VERSION 5.8 ;
BUSBITCHARS "[]" ;
DIVIDERCHAR "/" ;
UNITS
    DATABASE MICRONS 1000 ;
END UNITS

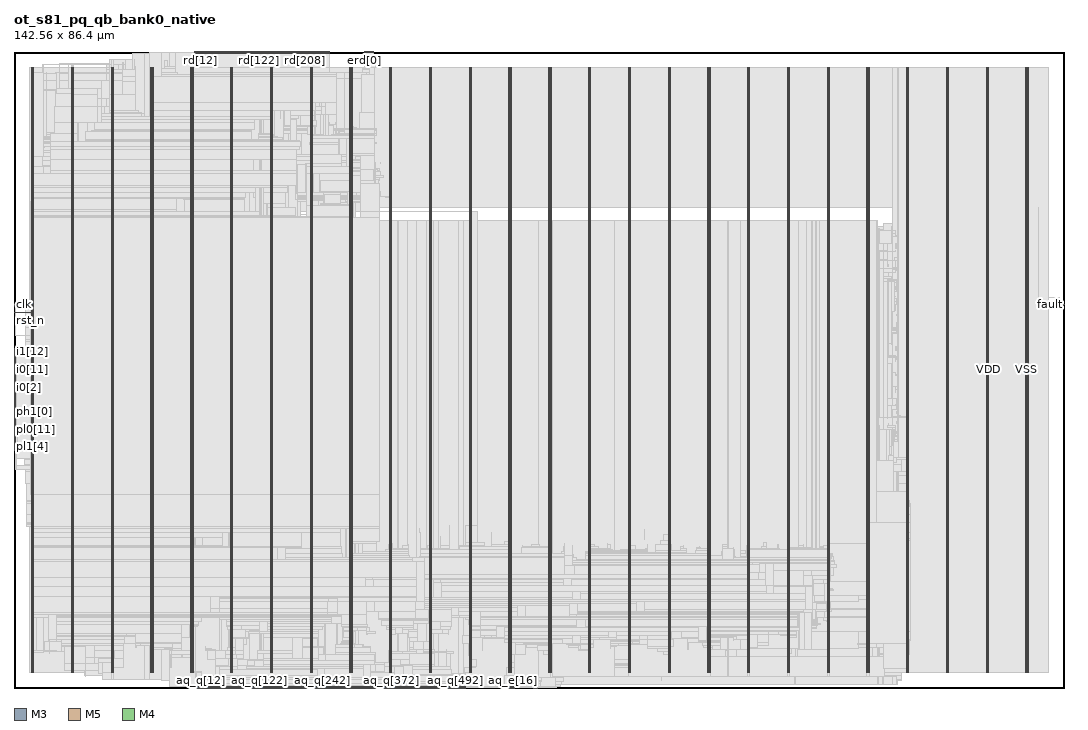
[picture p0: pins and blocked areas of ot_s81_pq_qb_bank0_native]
MACRO ot_s81_pq_qb_bank0_native
  FOREIGN ot_s81_pq_qb_bank0_native 0 0 ;
  CLASS BLOCK ;
  SIZE 142.56 BY 86.4 ;
  PIN aq_e[0]
    DIRECTION INPUT ;
    USE SIGNAL ;
    PORT
      LAYER M3 ;
        RECT  66.528 0 66.546 0.144 ;
    END
  END aq_e[0]
  PIN aq_e[10]
    DIRECTION INPUT ;
    USE SIGNAL ;
    PORT
      LAYER M3 ;
        RECT  67.248 0 67.266 0.144 ;
    END
  END aq_e[10]
  PIN aq_e[11]
    DIRECTION INPUT ;
    USE SIGNAL ;
    PORT
      LAYER M5 ;
        RECT  67.296 0 67.32 0.192 ;
    END
  END aq_e[11]
  PIN aq_e[12]
    DIRECTION INPUT ;
    USE SIGNAL ;
    PORT
      LAYER M3 ;
        RECT  67.392 0 67.41 0.144 ;
    END
  END aq_e[12]
  PIN aq_e[13]
    DIRECTION INPUT ;
    USE SIGNAL ;
    PORT
      LAYER M5 ;
        RECT  67.44 0 67.464 0.192 ;
    END
  END aq_e[13]
  PIN aq_e[14]
    DIRECTION INPUT ;
    USE SIGNAL ;
    PORT
      LAYER M3 ;
        RECT  67.536 0 67.554 0.144 ;
    END
  END aq_e[14]
  PIN aq_e[15]
    DIRECTION INPUT ;
    USE SIGNAL ;
    PORT
      LAYER M5 ;
        RECT  67.584 0 67.608 0.192 ;
    END
  END aq_e[15]
  PIN aq_e[16]
    DIRECTION INPUT ;
    USE SIGNAL ;
    PORT
      LAYER M3 ;
        RECT  67.68 0 67.698 0.144 ;
    END
  END aq_e[16]
  PIN aq_e[17]
    DIRECTION INPUT ;
    USE SIGNAL ;
    PORT
      LAYER M5 ;
        RECT  67.728 0 67.752 0.192 ;
    END
  END aq_e[17]
  PIN aq_e[18]
    DIRECTION INPUT ;
    USE SIGNAL ;
    PORT
      LAYER M3 ;
        RECT  67.824 0 67.842 0.144 ;
    END
  END aq_e[18]
  PIN aq_e[19]
    DIRECTION INPUT ;
    USE SIGNAL ;
    PORT
      LAYER M5 ;
        RECT  67.872 0 67.896 0.192 ;
    END
  END aq_e[19]
  PIN aq_e[1]
    DIRECTION INPUT ;
    USE SIGNAL ;
    PORT
      LAYER M5 ;
        RECT  66.576 0 66.6 0.192 ;
    END
  END aq_e[1]
  PIN aq_e[2]
    DIRECTION INPUT ;
    USE SIGNAL ;
    PORT
      LAYER M3 ;
        RECT  66.672 0 66.69 0.144 ;
    END
  END aq_e[2]
  PIN aq_e[3]
    DIRECTION INPUT ;
    USE SIGNAL ;
    PORT
      LAYER M5 ;
        RECT  66.72 0 66.744 0.192 ;
    END
  END aq_e[3]
  PIN aq_e[4]
    DIRECTION INPUT ;
    USE SIGNAL ;
    PORT
      LAYER M3 ;
        RECT  66.816 0 66.834 0.144 ;
    END
  END aq_e[4]
  PIN aq_e[5]
    DIRECTION INPUT ;
    USE SIGNAL ;
    PORT
      LAYER M5 ;
        RECT  66.864 0 66.888 0.192 ;
    END
  END aq_e[5]
  PIN aq_e[6]
    DIRECTION INPUT ;
    USE SIGNAL ;
    PORT
      LAYER M3 ;
        RECT  66.96 0 66.978 0.144 ;
    END
  END aq_e[6]
  PIN aq_e[7]
    DIRECTION INPUT ;
    USE SIGNAL ;
    PORT
      LAYER M5 ;
        RECT  67.008 0 67.032 0.192 ;
    END
  END aq_e[7]
  PIN aq_e[8]
    DIRECTION INPUT ;
    USE SIGNAL ;
    PORT
      LAYER M3 ;
        RECT  67.104 0 67.122 0.144 ;
    END
  END aq_e[8]
  PIN aq_e[9]
    DIRECTION INPUT ;
    USE SIGNAL ;
    PORT
      LAYER M5 ;
        RECT  67.152 0 67.176 0.192 ;
    END
  END aq_e[9]
  PIN aq_p[0]
    DIRECTION INPUT ;
    USE SIGNAL ;
    PORT
      LAYER M3 ;
        RECT  70.488 0 70.506 0.144 ;
    END
  END aq_p[0]
  PIN aq_p[1]
    DIRECTION INPUT ;
    USE SIGNAL ;
    PORT
      LAYER M5 ;
        RECT  70.512 0 70.536 0.192 ;
    END
  END aq_p[1]
  PIN aq_p[2]
    DIRECTION INPUT ;
    USE SIGNAL ;
    PORT
      LAYER M3 ;
        RECT  70.632 0 70.65 0.144 ;
    END
  END aq_p[2]
  PIN aq_p[3]
    DIRECTION INPUT ;
    USE SIGNAL ;
    PORT
      LAYER M5 ;
        RECT  70.656 0 70.68 0.192 ;
    END
  END aq_p[3]
  PIN aq_p[4]
    DIRECTION INPUT ;
    USE SIGNAL ;
    PORT
      LAYER M3 ;
        RECT  70.776 0 70.794 0.144 ;
    END
  END aq_p[4]
  PIN aq_p[5]
    DIRECTION INPUT ;
    USE SIGNAL ;
    PORT
      LAYER M5 ;
        RECT  70.8 0 70.824 0.192 ;
    END
  END aq_p[5]
  PIN aq_p[6]
    DIRECTION INPUT ;
    USE SIGNAL ;
    PORT
      LAYER M3 ;
        RECT  70.92 0 70.938 0.144 ;
    END
  END aq_p[6]
  PIN aq_p[7]
    DIRECTION INPUT ;
    USE SIGNAL ;
    PORT
      LAYER M5 ;
        RECT  70.944 0 70.968 0.192 ;
    END
  END aq_p[7]
  PIN aq_p[8]
    DIRECTION INPUT ;
    USE SIGNAL ;
    PORT
      LAYER M3 ;
        RECT  71.064 0 71.082 0.144 ;
    END
  END aq_p[8]
  PIN aq_p[9]
    DIRECTION INPUT ;
    USE SIGNAL ;
    PORT
      LAYER M5 ;
        RECT  71.088 0 71.112 0.192 ;
    END
  END aq_p[9]
  PIN aq_q[0]
    DIRECTION INPUT ;
    USE SIGNAL ;
    PORT
      LAYER M3 ;
        RECT  24.48 0 24.498 0.144 ;
    END
  END aq_q[0]
  PIN aq_q[100]
    DIRECTION INPUT ;
    USE SIGNAL ;
    PORT
      LAYER M3 ;
        RECT  31.68 0 31.698 0.144 ;
    END
  END aq_q[100]
  PIN aq_q[101]
    DIRECTION INPUT ;
    USE SIGNAL ;
    PORT
      LAYER M5 ;
        RECT  31.728 0 31.752 0.192 ;
    END
  END aq_q[101]
  PIN aq_q[102]
    DIRECTION INPUT ;
    USE SIGNAL ;
    PORT
      LAYER M3 ;
        RECT  31.824 0 31.842 0.144 ;
    END
  END aq_q[102]
  PIN aq_q[103]
    DIRECTION INPUT ;
    USE SIGNAL ;
    PORT
      LAYER M5 ;
        RECT  31.872 0 31.896 0.192 ;
    END
  END aq_q[103]
  PIN aq_q[104]
    DIRECTION INPUT ;
    USE SIGNAL ;
    PORT
      LAYER M3 ;
        RECT  31.968 0 31.986 0.144 ;
    END
  END aq_q[104]
  PIN aq_q[105]
    DIRECTION INPUT ;
    USE SIGNAL ;
    PORT
      LAYER M5 ;
        RECT  32.016 0 32.04 0.192 ;
    END
  END aq_q[105]
  PIN aq_q[106]
    DIRECTION INPUT ;
    USE SIGNAL ;
    PORT
      LAYER M3 ;
        RECT  32.112 0 32.13 0.144 ;
    END
  END aq_q[106]
  PIN aq_q[107]
    DIRECTION INPUT ;
    USE SIGNAL ;
    PORT
      LAYER M5 ;
        RECT  32.16 0 32.184 0.192 ;
    END
  END aq_q[107]
  PIN aq_q[108]
    DIRECTION INPUT ;
    USE SIGNAL ;
    PORT
      LAYER M3 ;
        RECT  32.256 0 32.274 0.144 ;
    END
  END aq_q[108]
  PIN aq_q[109]
    DIRECTION INPUT ;
    USE SIGNAL ;
    PORT
      LAYER M5 ;
        RECT  32.304 0 32.328 0.192 ;
    END
  END aq_q[109]
  PIN aq_q[10]
    DIRECTION INPUT ;
    USE SIGNAL ;
    PORT
      LAYER M3 ;
        RECT  25.2 0 25.218 0.144 ;
    END
  END aq_q[10]
  PIN aq_q[110]
    DIRECTION INPUT ;
    USE SIGNAL ;
    PORT
      LAYER M3 ;
        RECT  32.4 0 32.418 0.144 ;
    END
  END aq_q[110]
  PIN aq_q[111]
    DIRECTION INPUT ;
    USE SIGNAL ;
    PORT
      LAYER M5 ;
        RECT  32.448 0 32.472 0.192 ;
    END
  END aq_q[111]
  PIN aq_q[112]
    DIRECTION INPUT ;
    USE SIGNAL ;
    PORT
      LAYER M3 ;
        RECT  32.544 0 32.562 0.144 ;
    END
  END aq_q[112]
  PIN aq_q[113]
    DIRECTION INPUT ;
    USE SIGNAL ;
    PORT
      LAYER M5 ;
        RECT  32.592 0 32.616 0.192 ;
    END
  END aq_q[113]
  PIN aq_q[114]
    DIRECTION INPUT ;
    USE SIGNAL ;
    PORT
      LAYER M3 ;
        RECT  32.688 0 32.706 0.144 ;
    END
  END aq_q[114]
  PIN aq_q[115]
    DIRECTION INPUT ;
    USE SIGNAL ;
    PORT
      LAYER M5 ;
        RECT  32.736 0 32.76 0.192 ;
    END
  END aq_q[115]
  PIN aq_q[116]
    DIRECTION INPUT ;
    USE SIGNAL ;
    PORT
      LAYER M3 ;
        RECT  32.832 0 32.85 0.144 ;
    END
  END aq_q[116]
  PIN aq_q[117]
    DIRECTION INPUT ;
    USE SIGNAL ;
    PORT
      LAYER M5 ;
        RECT  32.88 0 32.904 0.192 ;
    END
  END aq_q[117]
  PIN aq_q[118]
    DIRECTION INPUT ;
    USE SIGNAL ;
    PORT
      LAYER M3 ;
        RECT  32.976 0 32.994 0.144 ;
    END
  END aq_q[118]
  PIN aq_q[119]
    DIRECTION INPUT ;
    USE SIGNAL ;
    PORT
      LAYER M5 ;
        RECT  33.024 0 33.048 0.192 ;
    END
  END aq_q[119]
  PIN aq_q[11]
    DIRECTION INPUT ;
    USE SIGNAL ;
    PORT
      LAYER M5 ;
        RECT  25.248 0 25.272 0.192 ;
    END
  END aq_q[11]
  PIN aq_q[120]
    DIRECTION INPUT ;
    USE SIGNAL ;
    PORT
      LAYER M3 ;
        RECT  33.12 0 33.138 0.144 ;
    END
  END aq_q[120]
  PIN aq_q[121]
    DIRECTION INPUT ;
    USE SIGNAL ;
    PORT
      LAYER M5 ;
        RECT  33.168 0 33.192 0.192 ;
    END
  END aq_q[121]
  PIN aq_q[122]
    DIRECTION INPUT ;
    USE SIGNAL ;
    PORT
      LAYER M3 ;
        RECT  33.264 0 33.282 0.144 ;
    END
  END aq_q[122]
  PIN aq_q[123]
    DIRECTION INPUT ;
    USE SIGNAL ;
    PORT
      LAYER M5 ;
        RECT  33.312 0 33.336 0.192 ;
    END
  END aq_q[123]
  PIN aq_q[124]
    DIRECTION INPUT ;
    USE SIGNAL ;
    PORT
      LAYER M3 ;
        RECT  33.408 0 33.426 0.144 ;
    END
  END aq_q[124]
  PIN aq_q[125]
    DIRECTION INPUT ;
    USE SIGNAL ;
    PORT
      LAYER M5 ;
        RECT  33.456 0 33.48 0.192 ;
    END
  END aq_q[125]
  PIN aq_q[126]
    DIRECTION INPUT ;
    USE SIGNAL ;
    PORT
      LAYER M3 ;
        RECT  33.552 0 33.57 0.144 ;
    END
  END aq_q[126]
  PIN aq_q[127]
    DIRECTION INPUT ;
    USE SIGNAL ;
    PORT
      LAYER M5 ;
        RECT  33.6 0 33.624 0.192 ;
    END
  END aq_q[127]
  PIN aq_q[128]
    DIRECTION INPUT ;
    USE SIGNAL ;
    PORT
      LAYER M3 ;
        RECT  33.696 0 33.714 0.144 ;
    END
  END aq_q[128]
  PIN aq_q[129]
    DIRECTION INPUT ;
    USE SIGNAL ;
    PORT
      LAYER M5 ;
        RECT  33.744 0 33.768 0.192 ;
    END
  END aq_q[129]
  PIN aq_q[12]
    DIRECTION INPUT ;
    USE SIGNAL ;
    PORT
      LAYER M3 ;
        RECT  25.344 0 25.362 0.144 ;
    END
  END aq_q[12]
  PIN aq_q[130]
    DIRECTION INPUT ;
    USE SIGNAL ;
    PORT
      LAYER M3 ;
        RECT  33.84 0 33.858 0.144 ;
    END
  END aq_q[130]
  PIN aq_q[131]
    DIRECTION INPUT ;
    USE SIGNAL ;
    PORT
      LAYER M5 ;
        RECT  33.888 0 33.912 0.192 ;
    END
  END aq_q[131]
  PIN aq_q[132]
    DIRECTION INPUT ;
    USE SIGNAL ;
    PORT
      LAYER M3 ;
        RECT  33.984 0 34.002 0.144 ;
    END
  END aq_q[132]
  PIN aq_q[133]
    DIRECTION INPUT ;
    USE SIGNAL ;
    PORT
      LAYER M5 ;
        RECT  34.032 0 34.056 0.192 ;
    END
  END aq_q[133]
  PIN aq_q[134]
    DIRECTION INPUT ;
    USE SIGNAL ;
    PORT
      LAYER M3 ;
        RECT  34.128 0 34.146 0.144 ;
    END
  END aq_q[134]
  PIN aq_q[135]
    DIRECTION INPUT ;
    USE SIGNAL ;
    PORT
      LAYER M5 ;
        RECT  34.176 0 34.2 0.192 ;
    END
  END aq_q[135]
  PIN aq_q[136]
    DIRECTION INPUT ;
    USE SIGNAL ;
    PORT
      LAYER M3 ;
        RECT  34.272 0 34.29 0.144 ;
    END
  END aq_q[136]
  PIN aq_q[137]
    DIRECTION INPUT ;
    USE SIGNAL ;
    PORT
      LAYER M5 ;
        RECT  34.32 0 34.344 0.192 ;
    END
  END aq_q[137]
  PIN aq_q[138]
    DIRECTION INPUT ;
    USE SIGNAL ;
    PORT
      LAYER M3 ;
        RECT  34.416 0 34.434 0.144 ;
    END
  END aq_q[138]
  PIN aq_q[139]
    DIRECTION INPUT ;
    USE SIGNAL ;
    PORT
      LAYER M5 ;
        RECT  34.464 0 34.488 0.192 ;
    END
  END aq_q[139]
  PIN aq_q[13]
    DIRECTION INPUT ;
    USE SIGNAL ;
    PORT
      LAYER M5 ;
        RECT  25.392 0 25.416 0.192 ;
    END
  END aq_q[13]
  PIN aq_q[140]
    DIRECTION INPUT ;
    USE SIGNAL ;
    PORT
      LAYER M3 ;
        RECT  34.56 0 34.578 0.144 ;
    END
  END aq_q[140]
  PIN aq_q[141]
    DIRECTION INPUT ;
    USE SIGNAL ;
    PORT
      LAYER M5 ;
        RECT  34.608 0 34.632 0.192 ;
    END
  END aq_q[141]
  PIN aq_q[142]
    DIRECTION INPUT ;
    USE SIGNAL ;
    PORT
      LAYER M3 ;
        RECT  34.704 0 34.722 0.144 ;
    END
  END aq_q[142]
  PIN aq_q[143]
    DIRECTION INPUT ;
    USE SIGNAL ;
    PORT
      LAYER M5 ;
        RECT  34.752 0 34.776 0.192 ;
    END
  END aq_q[143]
  PIN aq_q[144]
    DIRECTION INPUT ;
    USE SIGNAL ;
    PORT
      LAYER M3 ;
        RECT  34.848 0 34.866 0.144 ;
    END
  END aq_q[144]
  PIN aq_q[145]
    DIRECTION INPUT ;
    USE SIGNAL ;
    PORT
      LAYER M5 ;
        RECT  34.896 0 34.92 0.192 ;
    END
  END aq_q[145]
  PIN aq_q[146]
    DIRECTION INPUT ;
    USE SIGNAL ;
    PORT
      LAYER M3 ;
        RECT  34.992 0 35.01 0.144 ;
    END
  END aq_q[146]
  PIN aq_q[147]
    DIRECTION INPUT ;
    USE SIGNAL ;
    PORT
      LAYER M5 ;
        RECT  35.04 0 35.064 0.192 ;
    END
  END aq_q[147]
  PIN aq_q[148]
    DIRECTION INPUT ;
    USE SIGNAL ;
    PORT
      LAYER M3 ;
        RECT  35.136 0 35.154 0.144 ;
    END
  END aq_q[148]
  PIN aq_q[149]
    DIRECTION INPUT ;
    USE SIGNAL ;
    PORT
      LAYER M5 ;
        RECT  35.184 0 35.208 0.192 ;
    END
  END aq_q[149]
  PIN aq_q[14]
    DIRECTION INPUT ;
    USE SIGNAL ;
    PORT
      LAYER M3 ;
        RECT  25.488 0 25.506 0.144 ;
    END
  END aq_q[14]
  PIN aq_q[150]
    DIRECTION INPUT ;
    USE SIGNAL ;
    PORT
      LAYER M3 ;
        RECT  35.28 0 35.298 0.144 ;
    END
  END aq_q[150]
  PIN aq_q[151]
    DIRECTION INPUT ;
    USE SIGNAL ;
    PORT
      LAYER M5 ;
        RECT  35.328 0 35.352 0.192 ;
    END
  END aq_q[151]
  PIN aq_q[152]
    DIRECTION INPUT ;
    USE SIGNAL ;
    PORT
      LAYER M3 ;
        RECT  35.424 0 35.442 0.144 ;
    END
  END aq_q[152]
  PIN aq_q[153]
    DIRECTION INPUT ;
    USE SIGNAL ;
    PORT
      LAYER M5 ;
        RECT  35.472 0 35.496 0.192 ;
    END
  END aq_q[153]
  PIN aq_q[154]
    DIRECTION INPUT ;
    USE SIGNAL ;
    PORT
      LAYER M3 ;
        RECT  35.568 0 35.586 0.144 ;
    END
  END aq_q[154]
  PIN aq_q[155]
    DIRECTION INPUT ;
    USE SIGNAL ;
    PORT
      LAYER M5 ;
        RECT  35.616 0 35.64 0.192 ;
    END
  END aq_q[155]
  PIN aq_q[156]
    DIRECTION INPUT ;
    USE SIGNAL ;
    PORT
      LAYER M3 ;
        RECT  35.712 0 35.73 0.144 ;
    END
  END aq_q[156]
  PIN aq_q[157]
    DIRECTION INPUT ;
    USE SIGNAL ;
    PORT
      LAYER M5 ;
        RECT  35.76 0 35.784 0.192 ;
    END
  END aq_q[157]
  PIN aq_q[158]
    DIRECTION INPUT ;
    USE SIGNAL ;
    PORT
      LAYER M3 ;
        RECT  35.856 0 35.874 0.144 ;
    END
  END aq_q[158]
  PIN aq_q[159]
    DIRECTION INPUT ;
    USE SIGNAL ;
    PORT
      LAYER M5 ;
        RECT  35.904 0 35.928 0.192 ;
    END
  END aq_q[159]
  PIN aq_q[15]
    DIRECTION INPUT ;
    USE SIGNAL ;
    PORT
      LAYER M5 ;
        RECT  25.536 0 25.56 0.192 ;
    END
  END aq_q[15]
  PIN aq_q[160]
    DIRECTION INPUT ;
    USE SIGNAL ;
    PORT
      LAYER M3 ;
        RECT  36 0 36.018 0.144 ;
    END
  END aq_q[160]
  PIN aq_q[161]
    DIRECTION INPUT ;
    USE SIGNAL ;
    PORT
      LAYER M5 ;
        RECT  36.048 0 36.072 0.192 ;
    END
  END aq_q[161]
  PIN aq_q[162]
    DIRECTION INPUT ;
    USE SIGNAL ;
    PORT
      LAYER M3 ;
        RECT  36.144 0 36.162 0.144 ;
    END
  END aq_q[162]
  PIN aq_q[163]
    DIRECTION INPUT ;
    USE SIGNAL ;
    PORT
      LAYER M5 ;
        RECT  36.192 0 36.216 0.192 ;
    END
  END aq_q[163]
  PIN aq_q[164]
    DIRECTION INPUT ;
    USE SIGNAL ;
    PORT
      LAYER M3 ;
        RECT  36.288 0 36.306 0.144 ;
    END
  END aq_q[164]
  PIN aq_q[165]
    DIRECTION INPUT ;
    USE SIGNAL ;
    PORT
      LAYER M5 ;
        RECT  36.336 0 36.36 0.192 ;
    END
  END aq_q[165]
  PIN aq_q[166]
    DIRECTION INPUT ;
    USE SIGNAL ;
    PORT
      LAYER M3 ;
        RECT  36.432 0 36.45 0.144 ;
    END
  END aq_q[166]
  PIN aq_q[167]
    DIRECTION INPUT ;
    USE SIGNAL ;
    PORT
      LAYER M5 ;
        RECT  36.48 0 36.504 0.192 ;
    END
  END aq_q[167]
  PIN aq_q[168]
    DIRECTION INPUT ;
    USE SIGNAL ;
    PORT
      LAYER M3 ;
        RECT  36.576 0 36.594 0.144 ;
    END
  END aq_q[168]
  PIN aq_q[169]
    DIRECTION INPUT ;
    USE SIGNAL ;
    PORT
      LAYER M5 ;
        RECT  36.624 0 36.648 0.192 ;
    END
  END aq_q[169]
  PIN aq_q[16]
    DIRECTION INPUT ;
    USE SIGNAL ;
    PORT
      LAYER M3 ;
        RECT  25.632 0 25.65 0.144 ;
    END
  END aq_q[16]
  PIN aq_q[170]
    DIRECTION INPUT ;
    USE SIGNAL ;
    PORT
      LAYER M3 ;
        RECT  36.72 0 36.738 0.144 ;
    END
  END aq_q[170]
  PIN aq_q[171]
    DIRECTION INPUT ;
    USE SIGNAL ;
    PORT
      LAYER M5 ;
        RECT  36.768 0 36.792 0.192 ;
    END
  END aq_q[171]
  PIN aq_q[172]
    DIRECTION INPUT ;
    USE SIGNAL ;
    PORT
      LAYER M3 ;
        RECT  36.864 0 36.882 0.144 ;
    END
  END aq_q[172]
  PIN aq_q[173]
    DIRECTION INPUT ;
    USE SIGNAL ;
    PORT
      LAYER M5 ;
        RECT  36.912 0 36.936 0.192 ;
    END
  END aq_q[173]
  PIN aq_q[174]
    DIRECTION INPUT ;
    USE SIGNAL ;
    PORT
      LAYER M3 ;
        RECT  37.008 0 37.026 0.144 ;
    END
  END aq_q[174]
  PIN aq_q[175]
    DIRECTION INPUT ;
    USE SIGNAL ;
    PORT
      LAYER M5 ;
        RECT  37.056 0 37.08 0.192 ;
    END
  END aq_q[175]
  PIN aq_q[176]
    DIRECTION INPUT ;
    USE SIGNAL ;
    PORT
      LAYER M3 ;
        RECT  37.152 0 37.17 0.144 ;
    END
  END aq_q[176]
  PIN aq_q[177]
    DIRECTION INPUT ;
    USE SIGNAL ;
    PORT
      LAYER M5 ;
        RECT  37.2 0 37.224 0.192 ;
    END
  END aq_q[177]
  PIN aq_q[178]
    DIRECTION INPUT ;
    USE SIGNAL ;
    PORT
      LAYER M3 ;
        RECT  37.296 0 37.314 0.144 ;
    END
  END aq_q[178]
  PIN aq_q[179]
    DIRECTION INPUT ;
    USE SIGNAL ;
    PORT
      LAYER M5 ;
        RECT  37.344 0 37.368 0.192 ;
    END
  END aq_q[179]
  PIN aq_q[17]
    DIRECTION INPUT ;
    USE SIGNAL ;
    PORT
      LAYER M5 ;
        RECT  25.68 0 25.704 0.192 ;
    END
  END aq_q[17]
  PIN aq_q[180]
    DIRECTION INPUT ;
    USE SIGNAL ;
    PORT
      LAYER M3 ;
        RECT  37.44 0 37.458 0.144 ;
    END
  END aq_q[180]
  PIN aq_q[181]
    DIRECTION INPUT ;
    USE SIGNAL ;
    PORT
      LAYER M5 ;
        RECT  37.488 0 37.512 0.192 ;
    END
  END aq_q[181]
  PIN aq_q[182]
    DIRECTION INPUT ;
    USE SIGNAL ;
    PORT
      LAYER M3 ;
        RECT  37.584 0 37.602 0.144 ;
    END
  END aq_q[182]
  PIN aq_q[183]
    DIRECTION INPUT ;
    USE SIGNAL ;
    PORT
      LAYER M5 ;
        RECT  37.632 0 37.656 0.192 ;
    END
  END aq_q[183]
  PIN aq_q[184]
    DIRECTION INPUT ;
    USE SIGNAL ;
    PORT
      LAYER M3 ;
        RECT  37.728 0 37.746 0.144 ;
    END
  END aq_q[184]
  PIN aq_q[185]
    DIRECTION INPUT ;
    USE SIGNAL ;
    PORT
      LAYER M5 ;
        RECT  37.776 0 37.8 0.192 ;
    END
  END aq_q[185]
  PIN aq_q[186]
    DIRECTION INPUT ;
    USE SIGNAL ;
    PORT
      LAYER M3 ;
        RECT  37.872 0 37.89 0.144 ;
    END
  END aq_q[186]
  PIN aq_q[187]
    DIRECTION INPUT ;
    USE SIGNAL ;
    PORT
      LAYER M5 ;
        RECT  37.92 0 37.944 0.192 ;
    END
  END aq_q[187]
  PIN aq_q[188]
    DIRECTION INPUT ;
    USE SIGNAL ;
    PORT
      LAYER M3 ;
        RECT  38.016 0 38.034 0.144 ;
    END
  END aq_q[188]
  PIN aq_q[189]
    DIRECTION INPUT ;
    USE SIGNAL ;
    PORT
      LAYER M5 ;
        RECT  38.064 0 38.088 0.192 ;
    END
  END aq_q[189]
  PIN aq_q[18]
    DIRECTION INPUT ;
    USE SIGNAL ;
    PORT
      LAYER M3 ;
        RECT  25.776 0 25.794 0.144 ;
    END
  END aq_q[18]
  PIN aq_q[190]
    DIRECTION INPUT ;
    USE SIGNAL ;
    PORT
      LAYER M3 ;
        RECT  38.16 0 38.178 0.144 ;
    END
  END aq_q[190]
  PIN aq_q[191]
    DIRECTION INPUT ;
    USE SIGNAL ;
    PORT
      LAYER M5 ;
        RECT  38.208 0 38.232 0.192 ;
    END
  END aq_q[191]
  PIN aq_q[192]
    DIRECTION INPUT ;
    USE SIGNAL ;
    PORT
      LAYER M3 ;
        RECT  38.304 0 38.322 0.144 ;
    END
  END aq_q[192]
  PIN aq_q[193]
    DIRECTION INPUT ;
    USE SIGNAL ;
    PORT
      LAYER M5 ;
        RECT  38.352 0 38.376 0.192 ;
    END
  END aq_q[193]
  PIN aq_q[194]
    DIRECTION INPUT ;
    USE SIGNAL ;
    PORT
      LAYER M3 ;
        RECT  38.448 0 38.466 0.144 ;
    END
  END aq_q[194]
  PIN aq_q[195]
    DIRECTION INPUT ;
    USE SIGNAL ;
    PORT
      LAYER M5 ;
        RECT  38.496 0 38.52 0.192 ;
    END
  END aq_q[195]
  PIN aq_q[196]
    DIRECTION INPUT ;
    USE SIGNAL ;
    PORT
      LAYER M3 ;
        RECT  38.592 0 38.61 0.144 ;
    END
  END aq_q[196]
  PIN aq_q[197]
    DIRECTION INPUT ;
    USE SIGNAL ;
    PORT
      LAYER M5 ;
        RECT  38.64 0 38.664 0.192 ;
    END
  END aq_q[197]
  PIN aq_q[198]
    DIRECTION INPUT ;
    USE SIGNAL ;
    PORT
      LAYER M3 ;
        RECT  38.736 0 38.754 0.144 ;
    END
  END aq_q[198]
  PIN aq_q[199]
    DIRECTION INPUT ;
    USE SIGNAL ;
    PORT
      LAYER M5 ;
        RECT  38.784 0 38.808 0.192 ;
    END
  END aq_q[199]
  PIN aq_q[19]
    DIRECTION INPUT ;
    USE SIGNAL ;
    PORT
      LAYER M5 ;
        RECT  25.824 0 25.848 0.192 ;
    END
  END aq_q[19]
  PIN aq_q[1]
    DIRECTION INPUT ;
    USE SIGNAL ;
    PORT
      LAYER M5 ;
        RECT  24.528 0 24.552 0.192 ;
    END
  END aq_q[1]
  PIN aq_q[200]
    DIRECTION INPUT ;
    USE SIGNAL ;
    PORT
      LAYER M3 ;
        RECT  38.88 0 38.898 0.144 ;
    END
  END aq_q[200]
  PIN aq_q[201]
    DIRECTION INPUT ;
    USE SIGNAL ;
    PORT
      LAYER M5 ;
        RECT  38.928 0 38.952 0.192 ;
    END
  END aq_q[201]
  PIN aq_q[202]
    DIRECTION INPUT ;
    USE SIGNAL ;
    PORT
      LAYER M3 ;
        RECT  39.024 0 39.042 0.144 ;
    END
  END aq_q[202]
  PIN aq_q[203]
    DIRECTION INPUT ;
    USE SIGNAL ;
    PORT
      LAYER M5 ;
        RECT  39.072 0 39.096 0.192 ;
    END
  END aq_q[203]
  PIN aq_q[204]
    DIRECTION INPUT ;
    USE SIGNAL ;
    PORT
      LAYER M3 ;
        RECT  39.168 0 39.186 0.144 ;
    END
  END aq_q[204]
  PIN aq_q[205]
    DIRECTION INPUT ;
    USE SIGNAL ;
    PORT
      LAYER M5 ;
        RECT  39.216 0 39.24 0.192 ;
    END
  END aq_q[205]
  PIN aq_q[206]
    DIRECTION INPUT ;
    USE SIGNAL ;
    PORT
      LAYER M3 ;
        RECT  39.312 0 39.33 0.144 ;
    END
  END aq_q[206]
  PIN aq_q[207]
    DIRECTION INPUT ;
    USE SIGNAL ;
    PORT
      LAYER M5 ;
        RECT  39.36 0 39.384 0.192 ;
    END
  END aq_q[207]
  PIN aq_q[208]
    DIRECTION INPUT ;
    USE SIGNAL ;
    PORT
      LAYER M3 ;
        RECT  39.456 0 39.474 0.144 ;
    END
  END aq_q[208]
  PIN aq_q[209]
    DIRECTION INPUT ;
    USE SIGNAL ;
    PORT
      LAYER M5 ;
        RECT  39.504 0 39.528 0.192 ;
    END
  END aq_q[209]
  PIN aq_q[20]
    DIRECTION INPUT ;
    USE SIGNAL ;
    PORT
      LAYER M3 ;
        RECT  25.92 0 25.938 0.144 ;
    END
  END aq_q[20]
  PIN aq_q[210]
    DIRECTION INPUT ;
    USE SIGNAL ;
    PORT
      LAYER M3 ;
        RECT  39.6 0 39.618 0.144 ;
    END
  END aq_q[210]
  PIN aq_q[211]
    DIRECTION INPUT ;
    USE SIGNAL ;
    PORT
      LAYER M5 ;
        RECT  39.648 0 39.672 0.192 ;
    END
  END aq_q[211]
  PIN aq_q[212]
    DIRECTION INPUT ;
    USE SIGNAL ;
    PORT
      LAYER M3 ;
        RECT  39.744 0 39.762 0.144 ;
    END
  END aq_q[212]
  PIN aq_q[213]
    DIRECTION INPUT ;
    USE SIGNAL ;
    PORT
      LAYER M5 ;
        RECT  39.792 0 39.816 0.192 ;
    END
  END aq_q[213]
  PIN aq_q[214]
    DIRECTION INPUT ;
    USE SIGNAL ;
    PORT
      LAYER M3 ;
        RECT  39.888 0 39.906 0.144 ;
    END
  END aq_q[214]
  PIN aq_q[215]
    DIRECTION INPUT ;
    USE SIGNAL ;
    PORT
      LAYER M5 ;
        RECT  39.936 0 39.96 0.192 ;
    END
  END aq_q[215]
  PIN aq_q[216]
    DIRECTION INPUT ;
    USE SIGNAL ;
    PORT
      LAYER M3 ;
        RECT  40.032 0 40.05 0.144 ;
    END
  END aq_q[216]
  PIN aq_q[217]
    DIRECTION INPUT ;
    USE SIGNAL ;
    PORT
      LAYER M5 ;
        RECT  40.08 0 40.104 0.192 ;
    END
  END aq_q[217]
  PIN aq_q[218]
    DIRECTION INPUT ;
    USE SIGNAL ;
    PORT
      LAYER M3 ;
        RECT  40.176 0 40.194 0.144 ;
    END
  END aq_q[218]
  PIN aq_q[219]
    DIRECTION INPUT ;
    USE SIGNAL ;
    PORT
      LAYER M5 ;
        RECT  40.224 0 40.248 0.192 ;
    END
  END aq_q[219]
  PIN aq_q[21]
    DIRECTION INPUT ;
    USE SIGNAL ;
    PORT
      LAYER M5 ;
        RECT  25.968 0 25.992 0.192 ;
    END
  END aq_q[21]
  PIN aq_q[220]
    DIRECTION INPUT ;
    USE SIGNAL ;
    PORT
      LAYER M3 ;
        RECT  40.32 0 40.338 0.144 ;
    END
  END aq_q[220]
  PIN aq_q[221]
    DIRECTION INPUT ;
    USE SIGNAL ;
    PORT
      LAYER M5 ;
        RECT  40.368 0 40.392 0.192 ;
    END
  END aq_q[221]
  PIN aq_q[222]
    DIRECTION INPUT ;
    USE SIGNAL ;
    PORT
      LAYER M3 ;
        RECT  40.464 0 40.482 0.144 ;
    END
  END aq_q[222]
  PIN aq_q[223]
    DIRECTION INPUT ;
    USE SIGNAL ;
    PORT
      LAYER M5 ;
        RECT  40.512 0 40.536 0.192 ;
    END
  END aq_q[223]
  PIN aq_q[224]
    DIRECTION INPUT ;
    USE SIGNAL ;
    PORT
      LAYER M3 ;
        RECT  40.608 0 40.626 0.144 ;
    END
  END aq_q[224]
  PIN aq_q[225]
    DIRECTION INPUT ;
    USE SIGNAL ;
    PORT
      LAYER M5 ;
        RECT  40.656 0 40.68 0.192 ;
    END
  END aq_q[225]
  PIN aq_q[226]
    DIRECTION INPUT ;
    USE SIGNAL ;
    PORT
      LAYER M3 ;
        RECT  40.752 0 40.77 0.144 ;
    END
  END aq_q[226]
  PIN aq_q[227]
    DIRECTION INPUT ;
    USE SIGNAL ;
    PORT
      LAYER M5 ;
        RECT  40.8 0 40.824 0.192 ;
    END
  END aq_q[227]
  PIN aq_q[228]
    DIRECTION INPUT ;
    USE SIGNAL ;
    PORT
      LAYER M3 ;
        RECT  40.896 0 40.914 0.144 ;
    END
  END aq_q[228]
  PIN aq_q[229]
    DIRECTION INPUT ;
    USE SIGNAL ;
    PORT
      LAYER M5 ;
        RECT  40.944 0 40.968 0.192 ;
    END
  END aq_q[229]
  PIN aq_q[22]
    DIRECTION INPUT ;
    USE SIGNAL ;
    PORT
      LAYER M3 ;
        RECT  26.064 0 26.082 0.144 ;
    END
  END aq_q[22]
  PIN aq_q[230]
    DIRECTION INPUT ;
    USE SIGNAL ;
    PORT
      LAYER M3 ;
        RECT  41.04 0 41.058 0.144 ;
    END
  END aq_q[230]
  PIN aq_q[231]
    DIRECTION INPUT ;
    USE SIGNAL ;
    PORT
      LAYER M5 ;
        RECT  41.088 0 41.112 0.192 ;
    END
  END aq_q[231]
  PIN aq_q[232]
    DIRECTION INPUT ;
    USE SIGNAL ;
    PORT
      LAYER M3 ;
        RECT  41.184 0 41.202 0.144 ;
    END
  END aq_q[232]
  PIN aq_q[233]
    DIRECTION INPUT ;
    USE SIGNAL ;
    PORT
      LAYER M5 ;
        RECT  41.232 0 41.256 0.192 ;
    END
  END aq_q[233]
  PIN aq_q[234]
    DIRECTION INPUT ;
    USE SIGNAL ;
    PORT
      LAYER M3 ;
        RECT  41.328 0 41.346 0.144 ;
    END
  END aq_q[234]
  PIN aq_q[235]
    DIRECTION INPUT ;
    USE SIGNAL ;
    PORT
      LAYER M5 ;
        RECT  41.376 0 41.4 0.192 ;
    END
  END aq_q[235]
  PIN aq_q[236]
    DIRECTION INPUT ;
    USE SIGNAL ;
    PORT
      LAYER M3 ;
        RECT  41.472 0 41.49 0.144 ;
    END
  END aq_q[236]
  PIN aq_q[237]
    DIRECTION INPUT ;
    USE SIGNAL ;
    PORT
      LAYER M5 ;
        RECT  41.52 0 41.544 0.192 ;
    END
  END aq_q[237]
  PIN aq_q[238]
    DIRECTION INPUT ;
    USE SIGNAL ;
    PORT
      LAYER M3 ;
        RECT  41.616 0 41.634 0.144 ;
    END
  END aq_q[238]
  PIN aq_q[239]
    DIRECTION INPUT ;
    USE SIGNAL ;
    PORT
      LAYER M5 ;
        RECT  41.664 0 41.688 0.192 ;
    END
  END aq_q[239]
  PIN aq_q[23]
    DIRECTION INPUT ;
    USE SIGNAL ;
    PORT
      LAYER M5 ;
        RECT  26.112 0 26.136 0.192 ;
    END
  END aq_q[23]
  PIN aq_q[240]
    DIRECTION INPUT ;
    USE SIGNAL ;
    PORT
      LAYER M3 ;
        RECT  41.76 0 41.778 0.144 ;
    END
  END aq_q[240]
  PIN aq_q[241]
    DIRECTION INPUT ;
    USE SIGNAL ;
    PORT
      LAYER M5 ;
        RECT  41.808 0 41.832 0.192 ;
    END
  END aq_q[241]
  PIN aq_q[242]
    DIRECTION INPUT ;
    USE SIGNAL ;
    PORT
      LAYER M3 ;
        RECT  41.904 0 41.922 0.144 ;
    END
  END aq_q[242]
  PIN aq_q[243]
    DIRECTION INPUT ;
    USE SIGNAL ;
    PORT
      LAYER M5 ;
        RECT  41.952 0 41.976 0.192 ;
    END
  END aq_q[243]
  PIN aq_q[244]
    DIRECTION INPUT ;
    USE SIGNAL ;
    PORT
      LAYER M3 ;
        RECT  42.048 0 42.066 0.144 ;
    END
  END aq_q[244]
  PIN aq_q[245]
    DIRECTION INPUT ;
    USE SIGNAL ;
    PORT
      LAYER M5 ;
        RECT  42.096 0 42.12 0.192 ;
    END
  END aq_q[245]
  PIN aq_q[246]
    DIRECTION INPUT ;
    USE SIGNAL ;
    PORT
      LAYER M3 ;
        RECT  42.192 0 42.21 0.144 ;
    END
  END aq_q[246]
  PIN aq_q[247]
    DIRECTION INPUT ;
    USE SIGNAL ;
    PORT
      LAYER M5 ;
        RECT  42.24 0 42.264 0.192 ;
    END
  END aq_q[247]
  PIN aq_q[248]
    DIRECTION INPUT ;
    USE SIGNAL ;
    PORT
      LAYER M3 ;
        RECT  42.336 0 42.354 0.144 ;
    END
  END aq_q[248]
  PIN aq_q[249]
    DIRECTION INPUT ;
    USE SIGNAL ;
    PORT
      LAYER M5 ;
        RECT  42.384 0 42.408 0.192 ;
    END
  END aq_q[249]
  PIN aq_q[24]
    DIRECTION INPUT ;
    USE SIGNAL ;
    PORT
      LAYER M3 ;
        RECT  26.208 0 26.226 0.144 ;
    END
  END aq_q[24]
  PIN aq_q[250]
    DIRECTION INPUT ;
    USE SIGNAL ;
    PORT
      LAYER M3 ;
        RECT  42.48 0 42.498 0.144 ;
    END
  END aq_q[250]
  PIN aq_q[251]
    DIRECTION INPUT ;
    USE SIGNAL ;
    PORT
      LAYER M5 ;
        RECT  42.528 0 42.552 0.192 ;
    END
  END aq_q[251]
  PIN aq_q[252]
    DIRECTION INPUT ;
    USE SIGNAL ;
    PORT
      LAYER M3 ;
        RECT  42.624 0 42.642 0.144 ;
    END
  END aq_q[252]
  PIN aq_q[253]
    DIRECTION INPUT ;
    USE SIGNAL ;
    PORT
      LAYER M5 ;
        RECT  42.672 0 42.696 0.192 ;
    END
  END aq_q[253]
  PIN aq_q[254]
    DIRECTION INPUT ;
    USE SIGNAL ;
    PORT
      LAYER M3 ;
        RECT  42.768 0 42.786 0.144 ;
    END
  END aq_q[254]
  PIN aq_q[255]
    DIRECTION INPUT ;
    USE SIGNAL ;
    PORT
      LAYER M5 ;
        RECT  42.816 0 42.84 0.192 ;
    END
  END aq_q[255]
  PIN aq_q[256]
    DIRECTION INPUT ;
    USE SIGNAL ;
    PORT
      LAYER M3 ;
        RECT  42.912 0 42.93 0.144 ;
    END
  END aq_q[256]
  PIN aq_q[257]
    DIRECTION INPUT ;
    USE SIGNAL ;
    PORT
      LAYER M5 ;
        RECT  42.96 0 42.984 0.192 ;
    END
  END aq_q[257]
  PIN aq_q[258]
    DIRECTION INPUT ;
    USE SIGNAL ;
    PORT
      LAYER M3 ;
        RECT  43.056 0 43.074 0.144 ;
    END
  END aq_q[258]
  PIN aq_q[259]
    DIRECTION INPUT ;
    USE SIGNAL ;
    PORT
      LAYER M5 ;
        RECT  43.104 0 43.128 0.192 ;
    END
  END aq_q[259]
  PIN aq_q[25]
    DIRECTION INPUT ;
    USE SIGNAL ;
    PORT
      LAYER M5 ;
        RECT  26.256 0 26.28 0.192 ;
    END
  END aq_q[25]
  PIN aq_q[260]
    DIRECTION INPUT ;
    USE SIGNAL ;
    PORT
      LAYER M3 ;
        RECT  43.2 0 43.218 0.144 ;
    END
  END aq_q[260]
  PIN aq_q[261]
    DIRECTION INPUT ;
    USE SIGNAL ;
    PORT
      LAYER M5 ;
        RECT  43.248 0 43.272 0.192 ;
    END
  END aq_q[261]
  PIN aq_q[262]
    DIRECTION INPUT ;
    USE SIGNAL ;
    PORT
      LAYER M3 ;
        RECT  43.344 0 43.362 0.144 ;
    END
  END aq_q[262]
  PIN aq_q[263]
    DIRECTION INPUT ;
    USE SIGNAL ;
    PORT
      LAYER M5 ;
        RECT  43.392 0 43.416 0.192 ;
    END
  END aq_q[263]
  PIN aq_q[264]
    DIRECTION INPUT ;
    USE SIGNAL ;
    PORT
      LAYER M3 ;
        RECT  43.488 0 43.506 0.144 ;
    END
  END aq_q[264]
  PIN aq_q[265]
    DIRECTION INPUT ;
    USE SIGNAL ;
    PORT
      LAYER M5 ;
        RECT  43.536 0 43.56 0.192 ;
    END
  END aq_q[265]
  PIN aq_q[266]
    DIRECTION INPUT ;
    USE SIGNAL ;
    PORT
      LAYER M3 ;
        RECT  43.632 0 43.65 0.144 ;
    END
  END aq_q[266]
  PIN aq_q[267]
    DIRECTION INPUT ;
    USE SIGNAL ;
    PORT
      LAYER M5 ;
        RECT  43.68 0 43.704 0.192 ;
    END
  END aq_q[267]
  PIN aq_q[268]
    DIRECTION INPUT ;
    USE SIGNAL ;
    PORT
      LAYER M3 ;
        RECT  43.776 0 43.794 0.144 ;
    END
  END aq_q[268]
  PIN aq_q[269]
    DIRECTION INPUT ;
    USE SIGNAL ;
    PORT
      LAYER M5 ;
        RECT  43.824 0 43.848 0.192 ;
    END
  END aq_q[269]
  PIN aq_q[26]
    DIRECTION INPUT ;
    USE SIGNAL ;
    PORT
      LAYER M3 ;
        RECT  26.352 0 26.37 0.144 ;
    END
  END aq_q[26]
  PIN aq_q[270]
    DIRECTION INPUT ;
    USE SIGNAL ;
    PORT
      LAYER M3 ;
        RECT  43.92 0 43.938 0.144 ;
    END
  END aq_q[270]
  PIN aq_q[271]
    DIRECTION INPUT ;
    USE SIGNAL ;
    PORT
      LAYER M5 ;
        RECT  43.968 0 43.992 0.192 ;
    END
  END aq_q[271]
  PIN aq_q[272]
    DIRECTION INPUT ;
    USE SIGNAL ;
    PORT
      LAYER M3 ;
        RECT  44.064 0 44.082 0.144 ;
    END
  END aq_q[272]
  PIN aq_q[273]
    DIRECTION INPUT ;
    USE SIGNAL ;
    PORT
      LAYER M5 ;
        RECT  44.112 0 44.136 0.192 ;
    END
  END aq_q[273]
  PIN aq_q[274]
    DIRECTION INPUT ;
    USE SIGNAL ;
    PORT
      LAYER M3 ;
        RECT  44.208 0 44.226 0.144 ;
    END
  END aq_q[274]
  PIN aq_q[275]
    DIRECTION INPUT ;
    USE SIGNAL ;
    PORT
      LAYER M5 ;
        RECT  44.256 0 44.28 0.192 ;
    END
  END aq_q[275]
  PIN aq_q[276]
    DIRECTION INPUT ;
    USE SIGNAL ;
    PORT
      LAYER M3 ;
        RECT  44.352 0 44.37 0.144 ;
    END
  END aq_q[276]
  PIN aq_q[277]
    DIRECTION INPUT ;
    USE SIGNAL ;
    PORT
      LAYER M5 ;
        RECT  44.4 0 44.424 0.192 ;
    END
  END aq_q[277]
  PIN aq_q[278]
    DIRECTION INPUT ;
    USE SIGNAL ;
    PORT
      LAYER M3 ;
        RECT  44.496 0 44.514 0.144 ;
    END
  END aq_q[278]
  PIN aq_q[279]
    DIRECTION INPUT ;
    USE SIGNAL ;
    PORT
      LAYER M5 ;
        RECT  44.544 0 44.568 0.192 ;
    END
  END aq_q[279]
  PIN aq_q[27]
    DIRECTION INPUT ;
    USE SIGNAL ;
    PORT
      LAYER M5 ;
        RECT  26.4 0 26.424 0.192 ;
    END
  END aq_q[27]
  PIN aq_q[280]
    DIRECTION INPUT ;
    USE SIGNAL ;
    PORT
      LAYER M3 ;
        RECT  44.64 0 44.658 0.144 ;
    END
  END aq_q[280]
  PIN aq_q[281]
    DIRECTION INPUT ;
    USE SIGNAL ;
    PORT
      LAYER M5 ;
        RECT  44.688 0 44.712 0.192 ;
    END
  END aq_q[281]
  PIN aq_q[282]
    DIRECTION INPUT ;
    USE SIGNAL ;
    PORT
      LAYER M3 ;
        RECT  44.784 0 44.802 0.144 ;
    END
  END aq_q[282]
  PIN aq_q[283]
    DIRECTION INPUT ;
    USE SIGNAL ;
    PORT
      LAYER M5 ;
        RECT  44.832 0 44.856 0.192 ;
    END
  END aq_q[283]
  PIN aq_q[284]
    DIRECTION INPUT ;
    USE SIGNAL ;
    PORT
      LAYER M3 ;
        RECT  44.928 0 44.946 0.144 ;
    END
  END aq_q[284]
  PIN aq_q[285]
    DIRECTION INPUT ;
    USE SIGNAL ;
    PORT
      LAYER M5 ;
        RECT  44.976 0 45 0.192 ;
    END
  END aq_q[285]
  PIN aq_q[286]
    DIRECTION INPUT ;
    USE SIGNAL ;
    PORT
      LAYER M3 ;
        RECT  45.072 0 45.09 0.144 ;
    END
  END aq_q[286]
  PIN aq_q[287]
    DIRECTION INPUT ;
    USE SIGNAL ;
    PORT
      LAYER M5 ;
        RECT  45.12 0 45.144 0.192 ;
    END
  END aq_q[287]
  PIN aq_q[288]
    DIRECTION INPUT ;
    USE SIGNAL ;
    PORT
      LAYER M3 ;
        RECT  45.216 0 45.234 0.144 ;
    END
  END aq_q[288]
  PIN aq_q[289]
    DIRECTION INPUT ;
    USE SIGNAL ;
    PORT
      LAYER M5 ;
        RECT  45.264 0 45.288 0.192 ;
    END
  END aq_q[289]
  PIN aq_q[28]
    DIRECTION INPUT ;
    USE SIGNAL ;
    PORT
      LAYER M3 ;
        RECT  26.496 0 26.514 0.144 ;
    END
  END aq_q[28]
  PIN aq_q[290]
    DIRECTION INPUT ;
    USE SIGNAL ;
    PORT
      LAYER M3 ;
        RECT  45.36 0 45.378 0.144 ;
    END
  END aq_q[290]
  PIN aq_q[291]
    DIRECTION INPUT ;
    USE SIGNAL ;
    PORT
      LAYER M5 ;
        RECT  45.408 0 45.432 0.192 ;
    END
  END aq_q[291]
  PIN aq_q[292]
    DIRECTION INPUT ;
    USE SIGNAL ;
    PORT
      LAYER M3 ;
        RECT  45.504 0 45.522 0.144 ;
    END
  END aq_q[292]
  PIN aq_q[293]
    DIRECTION INPUT ;
    USE SIGNAL ;
    PORT
      LAYER M5 ;
        RECT  45.552 0 45.576 0.192 ;
    END
  END aq_q[293]
  PIN aq_q[294]
    DIRECTION INPUT ;
    USE SIGNAL ;
    PORT
      LAYER M3 ;
        RECT  45.648 0 45.666 0.144 ;
    END
  END aq_q[294]
  PIN aq_q[295]
    DIRECTION INPUT ;
    USE SIGNAL ;
    PORT
      LAYER M5 ;
        RECT  45.696 0 45.72 0.192 ;
    END
  END aq_q[295]
  PIN aq_q[296]
    DIRECTION INPUT ;
    USE SIGNAL ;
    PORT
      LAYER M3 ;
        RECT  45.792 0 45.81 0.144 ;
    END
  END aq_q[296]
  PIN aq_q[297]
    DIRECTION INPUT ;
    USE SIGNAL ;
    PORT
      LAYER M5 ;
        RECT  45.84 0 45.864 0.192 ;
    END
  END aq_q[297]
  PIN aq_q[298]
    DIRECTION INPUT ;
    USE SIGNAL ;
    PORT
      LAYER M3 ;
        RECT  45.936 0 45.954 0.144 ;
    END
  END aq_q[298]
  PIN aq_q[299]
    DIRECTION INPUT ;
    USE SIGNAL ;
    PORT
      LAYER M5 ;
        RECT  45.984 0 46.008 0.192 ;
    END
  END aq_q[299]
  PIN aq_q[29]
    DIRECTION INPUT ;
    USE SIGNAL ;
    PORT
      LAYER M5 ;
        RECT  26.544 0 26.568 0.192 ;
    END
  END aq_q[29]
  PIN aq_q[2]
    DIRECTION INPUT ;
    USE SIGNAL ;
    PORT
      LAYER M3 ;
        RECT  24.624 0 24.642 0.144 ;
    END
  END aq_q[2]
  PIN aq_q[300]
    DIRECTION INPUT ;
    USE SIGNAL ;
    PORT
      LAYER M3 ;
        RECT  46.08 0 46.098 0.144 ;
    END
  END aq_q[300]
  PIN aq_q[301]
    DIRECTION INPUT ;
    USE SIGNAL ;
    PORT
      LAYER M5 ;
        RECT  46.128 0 46.152 0.192 ;
    END
  END aq_q[301]
  PIN aq_q[302]
    DIRECTION INPUT ;
    USE SIGNAL ;
    PORT
      LAYER M3 ;
        RECT  46.224 0 46.242 0.144 ;
    END
  END aq_q[302]
  PIN aq_q[303]
    DIRECTION INPUT ;
    USE SIGNAL ;
    PORT
      LAYER M5 ;
        RECT  46.272 0 46.296 0.192 ;
    END
  END aq_q[303]
  PIN aq_q[304]
    DIRECTION INPUT ;
    USE SIGNAL ;
    PORT
      LAYER M3 ;
        RECT  46.368 0 46.386 0.144 ;
    END
  END aq_q[304]
  PIN aq_q[305]
    DIRECTION INPUT ;
    USE SIGNAL ;
    PORT
      LAYER M5 ;
        RECT  46.416 0 46.44 0.192 ;
    END
  END aq_q[305]
  PIN aq_q[306]
    DIRECTION INPUT ;
    USE SIGNAL ;
    PORT
      LAYER M3 ;
        RECT  46.512 0 46.53 0.144 ;
    END
  END aq_q[306]
  PIN aq_q[307]
    DIRECTION INPUT ;
    USE SIGNAL ;
    PORT
      LAYER M5 ;
        RECT  46.56 0 46.584 0.192 ;
    END
  END aq_q[307]
  PIN aq_q[308]
    DIRECTION INPUT ;
    USE SIGNAL ;
    PORT
      LAYER M3 ;
        RECT  46.656 0 46.674 0.144 ;
    END
  END aq_q[308]
  PIN aq_q[309]
    DIRECTION INPUT ;
    USE SIGNAL ;
    PORT
      LAYER M5 ;
        RECT  46.704 0 46.728 0.192 ;
    END
  END aq_q[309]
  PIN aq_q[30]
    DIRECTION INPUT ;
    USE SIGNAL ;
    PORT
      LAYER M3 ;
        RECT  26.64 0 26.658 0.144 ;
    END
  END aq_q[30]
  PIN aq_q[310]
    DIRECTION INPUT ;
    USE SIGNAL ;
    PORT
      LAYER M3 ;
        RECT  46.8 0 46.818 0.144 ;
    END
  END aq_q[310]
  PIN aq_q[311]
    DIRECTION INPUT ;
    USE SIGNAL ;
    PORT
      LAYER M5 ;
        RECT  46.848 0 46.872 0.192 ;
    END
  END aq_q[311]
  PIN aq_q[312]
    DIRECTION INPUT ;
    USE SIGNAL ;
    PORT
      LAYER M3 ;
        RECT  46.944 0 46.962 0.144 ;
    END
  END aq_q[312]
  PIN aq_q[313]
    DIRECTION INPUT ;
    USE SIGNAL ;
    PORT
      LAYER M5 ;
        RECT  46.992 0 47.016 0.192 ;
    END
  END aq_q[313]
  PIN aq_q[314]
    DIRECTION INPUT ;
    USE SIGNAL ;
    PORT
      LAYER M3 ;
        RECT  47.088 0 47.106 0.144 ;
    END
  END aq_q[314]
  PIN aq_q[315]
    DIRECTION INPUT ;
    USE SIGNAL ;
    PORT
      LAYER M5 ;
        RECT  47.136 0 47.16 0.192 ;
    END
  END aq_q[315]
  PIN aq_q[316]
    DIRECTION INPUT ;
    USE SIGNAL ;
    PORT
      LAYER M3 ;
        RECT  47.232 0 47.25 0.144 ;
    END
  END aq_q[316]
  PIN aq_q[317]
    DIRECTION INPUT ;
    USE SIGNAL ;
    PORT
      LAYER M5 ;
        RECT  47.28 0 47.304 0.192 ;
    END
  END aq_q[317]
  PIN aq_q[318]
    DIRECTION INPUT ;
    USE SIGNAL ;
    PORT
      LAYER M3 ;
        RECT  47.376 0 47.394 0.144 ;
    END
  END aq_q[318]
  PIN aq_q[319]
    DIRECTION INPUT ;
    USE SIGNAL ;
    PORT
      LAYER M5 ;
        RECT  47.424 0 47.448 0.192 ;
    END
  END aq_q[319]
  PIN aq_q[31]
    DIRECTION INPUT ;
    USE SIGNAL ;
    PORT
      LAYER M5 ;
        RECT  26.688 0 26.712 0.192 ;
    END
  END aq_q[31]
  PIN aq_q[320]
    DIRECTION INPUT ;
    USE SIGNAL ;
    PORT
      LAYER M3 ;
        RECT  47.52 0 47.538 0.144 ;
    END
  END aq_q[320]
  PIN aq_q[321]
    DIRECTION INPUT ;
    USE SIGNAL ;
    PORT
      LAYER M5 ;
        RECT  47.568 0 47.592 0.192 ;
    END
  END aq_q[321]
  PIN aq_q[322]
    DIRECTION INPUT ;
    USE SIGNAL ;
    PORT
      LAYER M3 ;
        RECT  47.664 0 47.682 0.144 ;
    END
  END aq_q[322]
  PIN aq_q[323]
    DIRECTION INPUT ;
    USE SIGNAL ;
    PORT
      LAYER M5 ;
        RECT  47.712 0 47.736 0.192 ;
    END
  END aq_q[323]
  PIN aq_q[324]
    DIRECTION INPUT ;
    USE SIGNAL ;
    PORT
      LAYER M3 ;
        RECT  47.808 0 47.826 0.144 ;
    END
  END aq_q[324]
  PIN aq_q[325]
    DIRECTION INPUT ;
    USE SIGNAL ;
    PORT
      LAYER M5 ;
        RECT  47.856 0 47.88 0.192 ;
    END
  END aq_q[325]
  PIN aq_q[326]
    DIRECTION INPUT ;
    USE SIGNAL ;
    PORT
      LAYER M3 ;
        RECT  47.952 0 47.97 0.144 ;
    END
  END aq_q[326]
  PIN aq_q[327]
    DIRECTION INPUT ;
    USE SIGNAL ;
    PORT
      LAYER M5 ;
        RECT  48 0 48.024 0.192 ;
    END
  END aq_q[327]
  PIN aq_q[328]
    DIRECTION INPUT ;
    USE SIGNAL ;
    PORT
      LAYER M3 ;
        RECT  48.096 0 48.114 0.144 ;
    END
  END aq_q[328]
  PIN aq_q[329]
    DIRECTION INPUT ;
    USE SIGNAL ;
    PORT
      LAYER M5 ;
        RECT  48.144 0 48.168 0.192 ;
    END
  END aq_q[329]
  PIN aq_q[32]
    DIRECTION INPUT ;
    USE SIGNAL ;
    PORT
      LAYER M3 ;
        RECT  26.784 0 26.802 0.144 ;
    END
  END aq_q[32]
  PIN aq_q[330]
    DIRECTION INPUT ;
    USE SIGNAL ;
    PORT
      LAYER M3 ;
        RECT  48.24 0 48.258 0.144 ;
    END
  END aq_q[330]
  PIN aq_q[331]
    DIRECTION INPUT ;
    USE SIGNAL ;
    PORT
      LAYER M5 ;
        RECT  48.288 0 48.312 0.192 ;
    END
  END aq_q[331]
  PIN aq_q[332]
    DIRECTION INPUT ;
    USE SIGNAL ;
    PORT
      LAYER M3 ;
        RECT  48.384 0 48.402 0.144 ;
    END
  END aq_q[332]
  PIN aq_q[333]
    DIRECTION INPUT ;
    USE SIGNAL ;
    PORT
      LAYER M5 ;
        RECT  48.432 0 48.456 0.192 ;
    END
  END aq_q[333]
  PIN aq_q[334]
    DIRECTION INPUT ;
    USE SIGNAL ;
    PORT
      LAYER M3 ;
        RECT  48.528 0 48.546 0.144 ;
    END
  END aq_q[334]
  PIN aq_q[335]
    DIRECTION INPUT ;
    USE SIGNAL ;
    PORT
      LAYER M5 ;
        RECT  48.576 0 48.6 0.192 ;
    END
  END aq_q[335]
  PIN aq_q[336]
    DIRECTION INPUT ;
    USE SIGNAL ;
    PORT
      LAYER M3 ;
        RECT  48.672 0 48.69 0.144 ;
    END
  END aq_q[336]
  PIN aq_q[337]
    DIRECTION INPUT ;
    USE SIGNAL ;
    PORT
      LAYER M5 ;
        RECT  48.72 0 48.744 0.192 ;
    END
  END aq_q[337]
  PIN aq_q[338]
    DIRECTION INPUT ;
    USE SIGNAL ;
    PORT
      LAYER M3 ;
        RECT  48.816 0 48.834 0.144 ;
    END
  END aq_q[338]
  PIN aq_q[339]
    DIRECTION INPUT ;
    USE SIGNAL ;
    PORT
      LAYER M5 ;
        RECT  48.864 0 48.888 0.192 ;
    END
  END aq_q[339]
  PIN aq_q[33]
    DIRECTION INPUT ;
    USE SIGNAL ;
    PORT
      LAYER M5 ;
        RECT  26.832 0 26.856 0.192 ;
    END
  END aq_q[33]
  PIN aq_q[340]
    DIRECTION INPUT ;
    USE SIGNAL ;
    PORT
      LAYER M3 ;
        RECT  48.96 0 48.978 0.144 ;
    END
  END aq_q[340]
  PIN aq_q[341]
    DIRECTION INPUT ;
    USE SIGNAL ;
    PORT
      LAYER M5 ;
        RECT  49.008 0 49.032 0.192 ;
    END
  END aq_q[341]
  PIN aq_q[342]
    DIRECTION INPUT ;
    USE SIGNAL ;
    PORT
      LAYER M3 ;
        RECT  49.104 0 49.122 0.144 ;
    END
  END aq_q[342]
  PIN aq_q[343]
    DIRECTION INPUT ;
    USE SIGNAL ;
    PORT
      LAYER M5 ;
        RECT  49.152 0 49.176 0.192 ;
    END
  END aq_q[343]
  PIN aq_q[344]
    DIRECTION INPUT ;
    USE SIGNAL ;
    PORT
      LAYER M3 ;
        RECT  49.248 0 49.266 0.144 ;
    END
  END aq_q[344]
  PIN aq_q[345]
    DIRECTION INPUT ;
    USE SIGNAL ;
    PORT
      LAYER M5 ;
        RECT  49.296 0 49.32 0.192 ;
    END
  END aq_q[345]
  PIN aq_q[346]
    DIRECTION INPUT ;
    USE SIGNAL ;
    PORT
      LAYER M3 ;
        RECT  49.392 0 49.41 0.144 ;
    END
  END aq_q[346]
  PIN aq_q[347]
    DIRECTION INPUT ;
    USE SIGNAL ;
    PORT
      LAYER M5 ;
        RECT  49.44 0 49.464 0.192 ;
    END
  END aq_q[347]
  PIN aq_q[348]
    DIRECTION INPUT ;
    USE SIGNAL ;
    PORT
      LAYER M3 ;
        RECT  49.536 0 49.554 0.144 ;
    END
  END aq_q[348]
  PIN aq_q[349]
    DIRECTION INPUT ;
    USE SIGNAL ;
    PORT
      LAYER M5 ;
        RECT  49.584 0 49.608 0.192 ;
    END
  END aq_q[349]
  PIN aq_q[34]
    DIRECTION INPUT ;
    USE SIGNAL ;
    PORT
      LAYER M3 ;
        RECT  26.928 0 26.946 0.144 ;
    END
  END aq_q[34]
  PIN aq_q[350]
    DIRECTION INPUT ;
    USE SIGNAL ;
    PORT
      LAYER M3 ;
        RECT  49.68 0 49.698 0.144 ;
    END
  END aq_q[350]
  PIN aq_q[351]
    DIRECTION INPUT ;
    USE SIGNAL ;
    PORT
      LAYER M5 ;
        RECT  49.728 0 49.752 0.192 ;
    END
  END aq_q[351]
  PIN aq_q[352]
    DIRECTION INPUT ;
    USE SIGNAL ;
    PORT
      LAYER M3 ;
        RECT  49.824 0 49.842 0.144 ;
    END
  END aq_q[352]
  PIN aq_q[353]
    DIRECTION INPUT ;
    USE SIGNAL ;
    PORT
      LAYER M5 ;
        RECT  49.872 0 49.896 0.192 ;
    END
  END aq_q[353]
  PIN aq_q[354]
    DIRECTION INPUT ;
    USE SIGNAL ;
    PORT
      LAYER M3 ;
        RECT  49.968 0 49.986 0.144 ;
    END
  END aq_q[354]
  PIN aq_q[355]
    DIRECTION INPUT ;
    USE SIGNAL ;
    PORT
      LAYER M5 ;
        RECT  50.016 0 50.04 0.192 ;
    END
  END aq_q[355]
  PIN aq_q[356]
    DIRECTION INPUT ;
    USE SIGNAL ;
    PORT
      LAYER M3 ;
        RECT  50.112 0 50.13 0.144 ;
    END
  END aq_q[356]
  PIN aq_q[357]
    DIRECTION INPUT ;
    USE SIGNAL ;
    PORT
      LAYER M5 ;
        RECT  50.16 0 50.184 0.192 ;
    END
  END aq_q[357]
  PIN aq_q[358]
    DIRECTION INPUT ;
    USE SIGNAL ;
    PORT
      LAYER M3 ;
        RECT  50.256 0 50.274 0.144 ;
    END
  END aq_q[358]
  PIN aq_q[359]
    DIRECTION INPUT ;
    USE SIGNAL ;
    PORT
      LAYER M5 ;
        RECT  50.304 0 50.328 0.192 ;
    END
  END aq_q[359]
  PIN aq_q[35]
    DIRECTION INPUT ;
    USE SIGNAL ;
    PORT
      LAYER M5 ;
        RECT  26.976 0 27 0.192 ;
    END
  END aq_q[35]
  PIN aq_q[360]
    DIRECTION INPUT ;
    USE SIGNAL ;
    PORT
      LAYER M3 ;
        RECT  50.4 0 50.418 0.144 ;
    END
  END aq_q[360]
  PIN aq_q[361]
    DIRECTION INPUT ;
    USE SIGNAL ;
    PORT
      LAYER M5 ;
        RECT  50.448 0 50.472 0.192 ;
    END
  END aq_q[361]
  PIN aq_q[362]
    DIRECTION INPUT ;
    USE SIGNAL ;
    PORT
      LAYER M3 ;
        RECT  50.544 0 50.562 0.144 ;
    END
  END aq_q[362]
  PIN aq_q[363]
    DIRECTION INPUT ;
    USE SIGNAL ;
    PORT
      LAYER M5 ;
        RECT  50.592 0 50.616 0.192 ;
    END
  END aq_q[363]
  PIN aq_q[364]
    DIRECTION INPUT ;
    USE SIGNAL ;
    PORT
      LAYER M3 ;
        RECT  50.688 0 50.706 0.144 ;
    END
  END aq_q[364]
  PIN aq_q[365]
    DIRECTION INPUT ;
    USE SIGNAL ;
    PORT
      LAYER M5 ;
        RECT  50.736 0 50.76 0.192 ;
    END
  END aq_q[365]
  PIN aq_q[366]
    DIRECTION INPUT ;
    USE SIGNAL ;
    PORT
      LAYER M3 ;
        RECT  50.832 0 50.85 0.144 ;
    END
  END aq_q[366]
  PIN aq_q[367]
    DIRECTION INPUT ;
    USE SIGNAL ;
    PORT
      LAYER M5 ;
        RECT  50.88 0 50.904 0.192 ;
    END
  END aq_q[367]
  PIN aq_q[368]
    DIRECTION INPUT ;
    USE SIGNAL ;
    PORT
      LAYER M3 ;
        RECT  50.976 0 50.994 0.144 ;
    END
  END aq_q[368]
  PIN aq_q[369]
    DIRECTION INPUT ;
    USE SIGNAL ;
    PORT
      LAYER M5 ;
        RECT  51.024 0 51.048 0.192 ;
    END
  END aq_q[369]
  PIN aq_q[36]
    DIRECTION INPUT ;
    USE SIGNAL ;
    PORT
      LAYER M3 ;
        RECT  27.072 0 27.09 0.144 ;
    END
  END aq_q[36]
  PIN aq_q[370]
    DIRECTION INPUT ;
    USE SIGNAL ;
    PORT
      LAYER M3 ;
        RECT  51.12 0 51.138 0.144 ;
    END
  END aq_q[370]
  PIN aq_q[371]
    DIRECTION INPUT ;
    USE SIGNAL ;
    PORT
      LAYER M5 ;
        RECT  51.168 0 51.192 0.192 ;
    END
  END aq_q[371]
  PIN aq_q[372]
    DIRECTION INPUT ;
    USE SIGNAL ;
    PORT
      LAYER M3 ;
        RECT  51.264 0 51.282 0.144 ;
    END
  END aq_q[372]
  PIN aq_q[373]
    DIRECTION INPUT ;
    USE SIGNAL ;
    PORT
      LAYER M5 ;
        RECT  51.312 0 51.336 0.192 ;
    END
  END aq_q[373]
  PIN aq_q[374]
    DIRECTION INPUT ;
    USE SIGNAL ;
    PORT
      LAYER M3 ;
        RECT  51.408 0 51.426 0.144 ;
    END
  END aq_q[374]
  PIN aq_q[375]
    DIRECTION INPUT ;
    USE SIGNAL ;
    PORT
      LAYER M5 ;
        RECT  51.456 0 51.48 0.192 ;
    END
  END aq_q[375]
  PIN aq_q[376]
    DIRECTION INPUT ;
    USE SIGNAL ;
    PORT
      LAYER M3 ;
        RECT  51.552 0 51.57 0.144 ;
    END
  END aq_q[376]
  PIN aq_q[377]
    DIRECTION INPUT ;
    USE SIGNAL ;
    PORT
      LAYER M5 ;
        RECT  51.6 0 51.624 0.192 ;
    END
  END aq_q[377]
  PIN aq_q[378]
    DIRECTION INPUT ;
    USE SIGNAL ;
    PORT
      LAYER M3 ;
        RECT  51.696 0 51.714 0.144 ;
    END
  END aq_q[378]
  PIN aq_q[379]
    DIRECTION INPUT ;
    USE SIGNAL ;
    PORT
      LAYER M5 ;
        RECT  51.744 0 51.768 0.192 ;
    END
  END aq_q[379]
  PIN aq_q[37]
    DIRECTION INPUT ;
    USE SIGNAL ;
    PORT
      LAYER M5 ;
        RECT  27.12 0 27.144 0.192 ;
    END
  END aq_q[37]
  PIN aq_q[380]
    DIRECTION INPUT ;
    USE SIGNAL ;
    PORT
      LAYER M3 ;
        RECT  51.84 0 51.858 0.144 ;
    END
  END aq_q[380]
  PIN aq_q[381]
    DIRECTION INPUT ;
    USE SIGNAL ;
    PORT
      LAYER M5 ;
        RECT  51.888 0 51.912 0.192 ;
    END
  END aq_q[381]
  PIN aq_q[382]
    DIRECTION INPUT ;
    USE SIGNAL ;
    PORT
      LAYER M3 ;
        RECT  51.984 0 52.002 0.144 ;
    END
  END aq_q[382]
  PIN aq_q[383]
    DIRECTION INPUT ;
    USE SIGNAL ;
    PORT
      LAYER M5 ;
        RECT  52.032 0 52.056 0.192 ;
    END
  END aq_q[383]
  PIN aq_q[384]
    DIRECTION INPUT ;
    USE SIGNAL ;
    PORT
      LAYER M3 ;
        RECT  52.128 0 52.146 0.144 ;
    END
  END aq_q[384]
  PIN aq_q[385]
    DIRECTION INPUT ;
    USE SIGNAL ;
    PORT
      LAYER M5 ;
        RECT  52.176 0 52.2 0.192 ;
    END
  END aq_q[385]
  PIN aq_q[386]
    DIRECTION INPUT ;
    USE SIGNAL ;
    PORT
      LAYER M3 ;
        RECT  52.272 0 52.29 0.144 ;
    END
  END aq_q[386]
  PIN aq_q[387]
    DIRECTION INPUT ;
    USE SIGNAL ;
    PORT
      LAYER M5 ;
        RECT  52.32 0 52.344 0.192 ;
    END
  END aq_q[387]
  PIN aq_q[388]
    DIRECTION INPUT ;
    USE SIGNAL ;
    PORT
      LAYER M3 ;
        RECT  52.416 0 52.434 0.144 ;
    END
  END aq_q[388]
  PIN aq_q[389]
    DIRECTION INPUT ;
    USE SIGNAL ;
    PORT
      LAYER M5 ;
        RECT  52.464 0 52.488 0.192 ;
    END
  END aq_q[389]
  PIN aq_q[38]
    DIRECTION INPUT ;
    USE SIGNAL ;
    PORT
      LAYER M3 ;
        RECT  27.216 0 27.234 0.144 ;
    END
  END aq_q[38]
  PIN aq_q[390]
    DIRECTION INPUT ;
    USE SIGNAL ;
    PORT
      LAYER M3 ;
        RECT  52.56 0 52.578 0.144 ;
    END
  END aq_q[390]
  PIN aq_q[391]
    DIRECTION INPUT ;
    USE SIGNAL ;
    PORT
      LAYER M5 ;
        RECT  52.608 0 52.632 0.192 ;
    END
  END aq_q[391]
  PIN aq_q[392]
    DIRECTION INPUT ;
    USE SIGNAL ;
    PORT
      LAYER M3 ;
        RECT  52.704 0 52.722 0.144 ;
    END
  END aq_q[392]
  PIN aq_q[393]
    DIRECTION INPUT ;
    USE SIGNAL ;
    PORT
      LAYER M5 ;
        RECT  52.752 0 52.776 0.192 ;
    END
  END aq_q[393]
  PIN aq_q[394]
    DIRECTION INPUT ;
    USE SIGNAL ;
    PORT
      LAYER M3 ;
        RECT  52.848 0 52.866 0.144 ;
    END
  END aq_q[394]
  PIN aq_q[395]
    DIRECTION INPUT ;
    USE SIGNAL ;
    PORT
      LAYER M5 ;
        RECT  52.896 0 52.92 0.192 ;
    END
  END aq_q[395]
  PIN aq_q[396]
    DIRECTION INPUT ;
    USE SIGNAL ;
    PORT
      LAYER M3 ;
        RECT  52.992 0 53.01 0.144 ;
    END
  END aq_q[396]
  PIN aq_q[397]
    DIRECTION INPUT ;
    USE SIGNAL ;
    PORT
      LAYER M5 ;
        RECT  53.04 0 53.064 0.192 ;
    END
  END aq_q[397]
  PIN aq_q[398]
    DIRECTION INPUT ;
    USE SIGNAL ;
    PORT
      LAYER M3 ;
        RECT  53.136 0 53.154 0.144 ;
    END
  END aq_q[398]
  PIN aq_q[399]
    DIRECTION INPUT ;
    USE SIGNAL ;
    PORT
      LAYER M5 ;
        RECT  53.184 0 53.208 0.192 ;
    END
  END aq_q[399]
  PIN aq_q[39]
    DIRECTION INPUT ;
    USE SIGNAL ;
    PORT
      LAYER M5 ;
        RECT  27.264 0 27.288 0.192 ;
    END
  END aq_q[39]
  PIN aq_q[3]
    DIRECTION INPUT ;
    USE SIGNAL ;
    PORT
      LAYER M5 ;
        RECT  24.672 0 24.696 0.192 ;
    END
  END aq_q[3]
  PIN aq_q[400]
    DIRECTION INPUT ;
    USE SIGNAL ;
    PORT
      LAYER M3 ;
        RECT  53.28 0 53.298 0.144 ;
    END
  END aq_q[400]
  PIN aq_q[401]
    DIRECTION INPUT ;
    USE SIGNAL ;
    PORT
      LAYER M5 ;
        RECT  53.328 0 53.352 0.192 ;
    END
  END aq_q[401]
  PIN aq_q[402]
    DIRECTION INPUT ;
    USE SIGNAL ;
    PORT
      LAYER M3 ;
        RECT  53.424 0 53.442 0.144 ;
    END
  END aq_q[402]
  PIN aq_q[403]
    DIRECTION INPUT ;
    USE SIGNAL ;
    PORT
      LAYER M5 ;
        RECT  53.472 0 53.496 0.192 ;
    END
  END aq_q[403]
  PIN aq_q[404]
    DIRECTION INPUT ;
    USE SIGNAL ;
    PORT
      LAYER M3 ;
        RECT  53.568 0 53.586 0.144 ;
    END
  END aq_q[404]
  PIN aq_q[405]
    DIRECTION INPUT ;
    USE SIGNAL ;
    PORT
      LAYER M5 ;
        RECT  53.616 0 53.64 0.192 ;
    END
  END aq_q[405]
  PIN aq_q[406]
    DIRECTION INPUT ;
    USE SIGNAL ;
    PORT
      LAYER M3 ;
        RECT  53.712 0 53.73 0.144 ;
    END
  END aq_q[406]
  PIN aq_q[407]
    DIRECTION INPUT ;
    USE SIGNAL ;
    PORT
      LAYER M5 ;
        RECT  53.76 0 53.784 0.192 ;
    END
  END aq_q[407]
  PIN aq_q[408]
    DIRECTION INPUT ;
    USE SIGNAL ;
    PORT
      LAYER M3 ;
        RECT  53.856 0 53.874 0.144 ;
    END
  END aq_q[408]
  PIN aq_q[409]
    DIRECTION INPUT ;
    USE SIGNAL ;
    PORT
      LAYER M5 ;
        RECT  53.904 0 53.928 0.192 ;
    END
  END aq_q[409]
  PIN aq_q[40]
    DIRECTION INPUT ;
    USE SIGNAL ;
    PORT
      LAYER M3 ;
        RECT  27.36 0 27.378 0.144 ;
    END
  END aq_q[40]
  PIN aq_q[410]
    DIRECTION INPUT ;
    USE SIGNAL ;
    PORT
      LAYER M3 ;
        RECT  54 0 54.018 0.144 ;
    END
  END aq_q[410]
  PIN aq_q[411]
    DIRECTION INPUT ;
    USE SIGNAL ;
    PORT
      LAYER M5 ;
        RECT  54.048 0 54.072 0.192 ;
    END
  END aq_q[411]
  PIN aq_q[412]
    DIRECTION INPUT ;
    USE SIGNAL ;
    PORT
      LAYER M3 ;
        RECT  54.144 0 54.162 0.144 ;
    END
  END aq_q[412]
  PIN aq_q[413]
    DIRECTION INPUT ;
    USE SIGNAL ;
    PORT
      LAYER M5 ;
        RECT  54.192 0 54.216 0.192 ;
    END
  END aq_q[413]
  PIN aq_q[414]
    DIRECTION INPUT ;
    USE SIGNAL ;
    PORT
      LAYER M3 ;
        RECT  54.288 0 54.306 0.144 ;
    END
  END aq_q[414]
  PIN aq_q[415]
    DIRECTION INPUT ;
    USE SIGNAL ;
    PORT
      LAYER M5 ;
        RECT  54.336 0 54.36 0.192 ;
    END
  END aq_q[415]
  PIN aq_q[416]
    DIRECTION INPUT ;
    USE SIGNAL ;
    PORT
      LAYER M3 ;
        RECT  54.432 0 54.45 0.144 ;
    END
  END aq_q[416]
  PIN aq_q[417]
    DIRECTION INPUT ;
    USE SIGNAL ;
    PORT
      LAYER M5 ;
        RECT  54.48 0 54.504 0.192 ;
    END
  END aq_q[417]
  PIN aq_q[418]
    DIRECTION INPUT ;
    USE SIGNAL ;
    PORT
      LAYER M3 ;
        RECT  54.576 0 54.594 0.144 ;
    END
  END aq_q[418]
  PIN aq_q[419]
    DIRECTION INPUT ;
    USE SIGNAL ;
    PORT
      LAYER M5 ;
        RECT  54.624 0 54.648 0.192 ;
    END
  END aq_q[419]
  PIN aq_q[41]
    DIRECTION INPUT ;
    USE SIGNAL ;
    PORT
      LAYER M5 ;
        RECT  27.408 0 27.432 0.192 ;
    END
  END aq_q[41]
  PIN aq_q[420]
    DIRECTION INPUT ;
    USE SIGNAL ;
    PORT
      LAYER M3 ;
        RECT  54.72 0 54.738 0.144 ;
    END
  END aq_q[420]
  PIN aq_q[421]
    DIRECTION INPUT ;
    USE SIGNAL ;
    PORT
      LAYER M5 ;
        RECT  54.768 0 54.792 0.192 ;
    END
  END aq_q[421]
  PIN aq_q[422]
    DIRECTION INPUT ;
    USE SIGNAL ;
    PORT
      LAYER M3 ;
        RECT  54.864 0 54.882 0.144 ;
    END
  END aq_q[422]
  PIN aq_q[423]
    DIRECTION INPUT ;
    USE SIGNAL ;
    PORT
      LAYER M5 ;
        RECT  54.912 0 54.936 0.192 ;
    END
  END aq_q[423]
  PIN aq_q[424]
    DIRECTION INPUT ;
    USE SIGNAL ;
    PORT
      LAYER M3 ;
        RECT  55.008 0 55.026 0.144 ;
    END
  END aq_q[424]
  PIN aq_q[425]
    DIRECTION INPUT ;
    USE SIGNAL ;
    PORT
      LAYER M5 ;
        RECT  55.056 0 55.08 0.192 ;
    END
  END aq_q[425]
  PIN aq_q[426]
    DIRECTION INPUT ;
    USE SIGNAL ;
    PORT
      LAYER M3 ;
        RECT  55.152 0 55.17 0.144 ;
    END
  END aq_q[426]
  PIN aq_q[427]
    DIRECTION INPUT ;
    USE SIGNAL ;
    PORT
      LAYER M5 ;
        RECT  55.2 0 55.224 0.192 ;
    END
  END aq_q[427]
  PIN aq_q[428]
    DIRECTION INPUT ;
    USE SIGNAL ;
    PORT
      LAYER M3 ;
        RECT  55.296 0 55.314 0.144 ;
    END
  END aq_q[428]
  PIN aq_q[429]
    DIRECTION INPUT ;
    USE SIGNAL ;
    PORT
      LAYER M5 ;
        RECT  55.344 0 55.368 0.192 ;
    END
  END aq_q[429]
  PIN aq_q[42]
    DIRECTION INPUT ;
    USE SIGNAL ;
    PORT
      LAYER M3 ;
        RECT  27.504 0 27.522 0.144 ;
    END
  END aq_q[42]
  PIN aq_q[430]
    DIRECTION INPUT ;
    USE SIGNAL ;
    PORT
      LAYER M3 ;
        RECT  55.44 0 55.458 0.144 ;
    END
  END aq_q[430]
  PIN aq_q[431]
    DIRECTION INPUT ;
    USE SIGNAL ;
    PORT
      LAYER M5 ;
        RECT  55.488 0 55.512 0.192 ;
    END
  END aq_q[431]
  PIN aq_q[432]
    DIRECTION INPUT ;
    USE SIGNAL ;
    PORT
      LAYER M3 ;
        RECT  55.584 0 55.602 0.144 ;
    END
  END aq_q[432]
  PIN aq_q[433]
    DIRECTION INPUT ;
    USE SIGNAL ;
    PORT
      LAYER M5 ;
        RECT  55.632 0 55.656 0.192 ;
    END
  END aq_q[433]
  PIN aq_q[434]
    DIRECTION INPUT ;
    USE SIGNAL ;
    PORT
      LAYER M3 ;
        RECT  55.728 0 55.746 0.144 ;
    END
  END aq_q[434]
  PIN aq_q[435]
    DIRECTION INPUT ;
    USE SIGNAL ;
    PORT
      LAYER M5 ;
        RECT  55.776 0 55.8 0.192 ;
    END
  END aq_q[435]
  PIN aq_q[436]
    DIRECTION INPUT ;
    USE SIGNAL ;
    PORT
      LAYER M3 ;
        RECT  55.872 0 55.89 0.144 ;
    END
  END aq_q[436]
  PIN aq_q[437]
    DIRECTION INPUT ;
    USE SIGNAL ;
    PORT
      LAYER M5 ;
        RECT  55.92 0 55.944 0.192 ;
    END
  END aq_q[437]
  PIN aq_q[438]
    DIRECTION INPUT ;
    USE SIGNAL ;
    PORT
      LAYER M3 ;
        RECT  56.016 0 56.034 0.144 ;
    END
  END aq_q[438]
  PIN aq_q[439]
    DIRECTION INPUT ;
    USE SIGNAL ;
    PORT
      LAYER M5 ;
        RECT  56.064 0 56.088 0.192 ;
    END
  END aq_q[439]
  PIN aq_q[43]
    DIRECTION INPUT ;
    USE SIGNAL ;
    PORT
      LAYER M5 ;
        RECT  27.552 0 27.576 0.192 ;
    END
  END aq_q[43]
  PIN aq_q[440]
    DIRECTION INPUT ;
    USE SIGNAL ;
    PORT
      LAYER M3 ;
        RECT  56.16 0 56.178 0.144 ;
    END
  END aq_q[440]
  PIN aq_q[441]
    DIRECTION INPUT ;
    USE SIGNAL ;
    PORT
      LAYER M5 ;
        RECT  56.208 0 56.232 0.192 ;
    END
  END aq_q[441]
  PIN aq_q[442]
    DIRECTION INPUT ;
    USE SIGNAL ;
    PORT
      LAYER M3 ;
        RECT  56.304 0 56.322 0.144 ;
    END
  END aq_q[442]
  PIN aq_q[443]
    DIRECTION INPUT ;
    USE SIGNAL ;
    PORT
      LAYER M5 ;
        RECT  56.352 0 56.376 0.192 ;
    END
  END aq_q[443]
  PIN aq_q[444]
    DIRECTION INPUT ;
    USE SIGNAL ;
    PORT
      LAYER M3 ;
        RECT  56.448 0 56.466 0.144 ;
    END
  END aq_q[444]
  PIN aq_q[445]
    DIRECTION INPUT ;
    USE SIGNAL ;
    PORT
      LAYER M5 ;
        RECT  56.496 0 56.52 0.192 ;
    END
  END aq_q[445]
  PIN aq_q[446]
    DIRECTION INPUT ;
    USE SIGNAL ;
    PORT
      LAYER M3 ;
        RECT  56.592 0 56.61 0.144 ;
    END
  END aq_q[446]
  PIN aq_q[447]
    DIRECTION INPUT ;
    USE SIGNAL ;
    PORT
      LAYER M5 ;
        RECT  56.64 0 56.664 0.192 ;
    END
  END aq_q[447]
  PIN aq_q[448]
    DIRECTION INPUT ;
    USE SIGNAL ;
    PORT
      LAYER M3 ;
        RECT  56.736 0 56.754 0.144 ;
    END
  END aq_q[448]
  PIN aq_q[449]
    DIRECTION INPUT ;
    USE SIGNAL ;
    PORT
      LAYER M5 ;
        RECT  56.784 0 56.808 0.192 ;
    END
  END aq_q[449]
  PIN aq_q[44]
    DIRECTION INPUT ;
    USE SIGNAL ;
    PORT
      LAYER M3 ;
        RECT  27.648 0 27.666 0.144 ;
    END
  END aq_q[44]
  PIN aq_q[450]
    DIRECTION INPUT ;
    USE SIGNAL ;
    PORT
      LAYER M3 ;
        RECT  56.88 0 56.898 0.144 ;
    END
  END aq_q[450]
  PIN aq_q[451]
    DIRECTION INPUT ;
    USE SIGNAL ;
    PORT
      LAYER M5 ;
        RECT  56.928 0 56.952 0.192 ;
    END
  END aq_q[451]
  PIN aq_q[452]
    DIRECTION INPUT ;
    USE SIGNAL ;
    PORT
      LAYER M3 ;
        RECT  57.024 0 57.042 0.144 ;
    END
  END aq_q[452]
  PIN aq_q[453]
    DIRECTION INPUT ;
    USE SIGNAL ;
    PORT
      LAYER M5 ;
        RECT  57.072 0 57.096 0.192 ;
    END
  END aq_q[453]
  PIN aq_q[454]
    DIRECTION INPUT ;
    USE SIGNAL ;
    PORT
      LAYER M3 ;
        RECT  57.168 0 57.186 0.144 ;
    END
  END aq_q[454]
  PIN aq_q[455]
    DIRECTION INPUT ;
    USE SIGNAL ;
    PORT
      LAYER M5 ;
        RECT  57.216 0 57.24 0.192 ;
    END
  END aq_q[455]
  PIN aq_q[456]
    DIRECTION INPUT ;
    USE SIGNAL ;
    PORT
      LAYER M3 ;
        RECT  57.312 0 57.33 0.144 ;
    END
  END aq_q[456]
  PIN aq_q[457]
    DIRECTION INPUT ;
    USE SIGNAL ;
    PORT
      LAYER M5 ;
        RECT  57.36 0 57.384 0.192 ;
    END
  END aq_q[457]
  PIN aq_q[458]
    DIRECTION INPUT ;
    USE SIGNAL ;
    PORT
      LAYER M3 ;
        RECT  57.456 0 57.474 0.144 ;
    END
  END aq_q[458]
  PIN aq_q[459]
    DIRECTION INPUT ;
    USE SIGNAL ;
    PORT
      LAYER M5 ;
        RECT  57.504 0 57.528 0.192 ;
    END
  END aq_q[459]
  PIN aq_q[45]
    DIRECTION INPUT ;
    USE SIGNAL ;
    PORT
      LAYER M5 ;
        RECT  27.696 0 27.72 0.192 ;
    END
  END aq_q[45]
  PIN aq_q[460]
    DIRECTION INPUT ;
    USE SIGNAL ;
    PORT
      LAYER M3 ;
        RECT  57.6 0 57.618 0.144 ;
    END
  END aq_q[460]
  PIN aq_q[461]
    DIRECTION INPUT ;
    USE SIGNAL ;
    PORT
      LAYER M5 ;
        RECT  57.648 0 57.672 0.192 ;
    END
  END aq_q[461]
  PIN aq_q[462]
    DIRECTION INPUT ;
    USE SIGNAL ;
    PORT
      LAYER M3 ;
        RECT  57.744 0 57.762 0.144 ;
    END
  END aq_q[462]
  PIN aq_q[463]
    DIRECTION INPUT ;
    USE SIGNAL ;
    PORT
      LAYER M5 ;
        RECT  57.792 0 57.816 0.192 ;
    END
  END aq_q[463]
  PIN aq_q[464]
    DIRECTION INPUT ;
    USE SIGNAL ;
    PORT
      LAYER M3 ;
        RECT  57.888 0 57.906 0.144 ;
    END
  END aq_q[464]
  PIN aq_q[465]
    DIRECTION INPUT ;
    USE SIGNAL ;
    PORT
      LAYER M5 ;
        RECT  57.936 0 57.96 0.192 ;
    END
  END aq_q[465]
  PIN aq_q[466]
    DIRECTION INPUT ;
    USE SIGNAL ;
    PORT
      LAYER M3 ;
        RECT  58.032 0 58.05 0.144 ;
    END
  END aq_q[466]
  PIN aq_q[467]
    DIRECTION INPUT ;
    USE SIGNAL ;
    PORT
      LAYER M5 ;
        RECT  58.08 0 58.104 0.192 ;
    END
  END aq_q[467]
  PIN aq_q[468]
    DIRECTION INPUT ;
    USE SIGNAL ;
    PORT
      LAYER M3 ;
        RECT  58.176 0 58.194 0.144 ;
    END
  END aq_q[468]
  PIN aq_q[469]
    DIRECTION INPUT ;
    USE SIGNAL ;
    PORT
      LAYER M5 ;
        RECT  58.224 0 58.248 0.192 ;
    END
  END aq_q[469]
  PIN aq_q[46]
    DIRECTION INPUT ;
    USE SIGNAL ;
    PORT
      LAYER M3 ;
        RECT  27.792 0 27.81 0.144 ;
    END
  END aq_q[46]
  PIN aq_q[470]
    DIRECTION INPUT ;
    USE SIGNAL ;
    PORT
      LAYER M3 ;
        RECT  58.32 0 58.338 0.144 ;
    END
  END aq_q[470]
  PIN aq_q[471]
    DIRECTION INPUT ;
    USE SIGNAL ;
    PORT
      LAYER M5 ;
        RECT  58.368 0 58.392 0.192 ;
    END
  END aq_q[471]
  PIN aq_q[472]
    DIRECTION INPUT ;
    USE SIGNAL ;
    PORT
      LAYER M3 ;
        RECT  58.464 0 58.482 0.144 ;
    END
  END aq_q[472]
  PIN aq_q[473]
    DIRECTION INPUT ;
    USE SIGNAL ;
    PORT
      LAYER M5 ;
        RECT  58.512 0 58.536 0.192 ;
    END
  END aq_q[473]
  PIN aq_q[474]
    DIRECTION INPUT ;
    USE SIGNAL ;
    PORT
      LAYER M3 ;
        RECT  58.608 0 58.626 0.144 ;
    END
  END aq_q[474]
  PIN aq_q[475]
    DIRECTION INPUT ;
    USE SIGNAL ;
    PORT
      LAYER M5 ;
        RECT  58.656 0 58.68 0.192 ;
    END
  END aq_q[475]
  PIN aq_q[476]
    DIRECTION INPUT ;
    USE SIGNAL ;
    PORT
      LAYER M3 ;
        RECT  58.752 0 58.77 0.144 ;
    END
  END aq_q[476]
  PIN aq_q[477]
    DIRECTION INPUT ;
    USE SIGNAL ;
    PORT
      LAYER M5 ;
        RECT  58.8 0 58.824 0.192 ;
    END
  END aq_q[477]
  PIN aq_q[478]
    DIRECTION INPUT ;
    USE SIGNAL ;
    PORT
      LAYER M3 ;
        RECT  58.896 0 58.914 0.144 ;
    END
  END aq_q[478]
  PIN aq_q[479]
    DIRECTION INPUT ;
    USE SIGNAL ;
    PORT
      LAYER M5 ;
        RECT  58.944 0 58.968 0.192 ;
    END
  END aq_q[479]
  PIN aq_q[47]
    DIRECTION INPUT ;
    USE SIGNAL ;
    PORT
      LAYER M5 ;
        RECT  27.84 0 27.864 0.192 ;
    END
  END aq_q[47]
  PIN aq_q[480]
    DIRECTION INPUT ;
    USE SIGNAL ;
    PORT
      LAYER M3 ;
        RECT  59.04 0 59.058 0.144 ;
    END
  END aq_q[480]
  PIN aq_q[481]
    DIRECTION INPUT ;
    USE SIGNAL ;
    PORT
      LAYER M5 ;
        RECT  59.088 0 59.112 0.192 ;
    END
  END aq_q[481]
  PIN aq_q[482]
    DIRECTION INPUT ;
    USE SIGNAL ;
    PORT
      LAYER M3 ;
        RECT  59.184 0 59.202 0.144 ;
    END
  END aq_q[482]
  PIN aq_q[483]
    DIRECTION INPUT ;
    USE SIGNAL ;
    PORT
      LAYER M5 ;
        RECT  59.232 0 59.256 0.192 ;
    END
  END aq_q[483]
  PIN aq_q[484]
    DIRECTION INPUT ;
    USE SIGNAL ;
    PORT
      LAYER M3 ;
        RECT  59.328 0 59.346 0.144 ;
    END
  END aq_q[484]
  PIN aq_q[485]
    DIRECTION INPUT ;
    USE SIGNAL ;
    PORT
      LAYER M5 ;
        RECT  59.376 0 59.4 0.192 ;
    END
  END aq_q[485]
  PIN aq_q[486]
    DIRECTION INPUT ;
    USE SIGNAL ;
    PORT
      LAYER M3 ;
        RECT  59.472 0 59.49 0.144 ;
    END
  END aq_q[486]
  PIN aq_q[487]
    DIRECTION INPUT ;
    USE SIGNAL ;
    PORT
      LAYER M5 ;
        RECT  59.52 0 59.544 0.192 ;
    END
  END aq_q[487]
  PIN aq_q[488]
    DIRECTION INPUT ;
    USE SIGNAL ;
    PORT
      LAYER M3 ;
        RECT  59.616 0 59.634 0.144 ;
    END
  END aq_q[488]
  PIN aq_q[489]
    DIRECTION INPUT ;
    USE SIGNAL ;
    PORT
      LAYER M5 ;
        RECT  59.664 0 59.688 0.192 ;
    END
  END aq_q[489]
  PIN aq_q[48]
    DIRECTION INPUT ;
    USE SIGNAL ;
    PORT
      LAYER M3 ;
        RECT  27.936 0 27.954 0.144 ;
    END
  END aq_q[48]
  PIN aq_q[490]
    DIRECTION INPUT ;
    USE SIGNAL ;
    PORT
      LAYER M3 ;
        RECT  59.76 0 59.778 0.144 ;
    END
  END aq_q[490]
  PIN aq_q[491]
    DIRECTION INPUT ;
    USE SIGNAL ;
    PORT
      LAYER M5 ;
        RECT  59.808 0 59.832 0.192 ;
    END
  END aq_q[491]
  PIN aq_q[492]
    DIRECTION INPUT ;
    USE SIGNAL ;
    PORT
      LAYER M3 ;
        RECT  59.904 0 59.922 0.144 ;
    END
  END aq_q[492]
  PIN aq_q[493]
    DIRECTION INPUT ;
    USE SIGNAL ;
    PORT
      LAYER M5 ;
        RECT  59.952 0 59.976 0.192 ;
    END
  END aq_q[493]
  PIN aq_q[494]
    DIRECTION INPUT ;
    USE SIGNAL ;
    PORT
      LAYER M3 ;
        RECT  60.048 0 60.066 0.144 ;
    END
  END aq_q[494]
  PIN aq_q[495]
    DIRECTION INPUT ;
    USE SIGNAL ;
    PORT
      LAYER M5 ;
        RECT  60.096 0 60.12 0.192 ;
    END
  END aq_q[495]
  PIN aq_q[496]
    DIRECTION INPUT ;
    USE SIGNAL ;
    PORT
      LAYER M3 ;
        RECT  60.192 0 60.21 0.144 ;
    END
  END aq_q[496]
  PIN aq_q[497]
    DIRECTION INPUT ;
    USE SIGNAL ;
    PORT
      LAYER M5 ;
        RECT  60.24 0 60.264 0.192 ;
    END
  END aq_q[497]
  PIN aq_q[498]
    DIRECTION INPUT ;
    USE SIGNAL ;
    PORT
      LAYER M3 ;
        RECT  60.336 0 60.354 0.144 ;
    END
  END aq_q[498]
  PIN aq_q[499]
    DIRECTION INPUT ;
    USE SIGNAL ;
    PORT
      LAYER M5 ;
        RECT  60.384 0 60.408 0.192 ;
    END
  END aq_q[499]
  PIN aq_q[49]
    DIRECTION INPUT ;
    USE SIGNAL ;
    PORT
      LAYER M5 ;
        RECT  27.984 0 28.008 0.192 ;
    END
  END aq_q[49]
  PIN aq_q[4]
    DIRECTION INPUT ;
    USE SIGNAL ;
    PORT
      LAYER M3 ;
        RECT  24.768 0 24.786 0.144 ;
    END
  END aq_q[4]
  PIN aq_q[500]
    DIRECTION INPUT ;
    USE SIGNAL ;
    PORT
      LAYER M3 ;
        RECT  60.48 0 60.498 0.144 ;
    END
  END aq_q[500]
  PIN aq_q[501]
    DIRECTION INPUT ;
    USE SIGNAL ;
    PORT
      LAYER M5 ;
        RECT  60.528 0 60.552 0.192 ;
    END
  END aq_q[501]
  PIN aq_q[502]
    DIRECTION INPUT ;
    USE SIGNAL ;
    PORT
      LAYER M3 ;
        RECT  60.624 0 60.642 0.144 ;
    END
  END aq_q[502]
  PIN aq_q[503]
    DIRECTION INPUT ;
    USE SIGNAL ;
    PORT
      LAYER M5 ;
        RECT  60.672 0 60.696 0.192 ;
    END
  END aq_q[503]
  PIN aq_q[504]
    DIRECTION INPUT ;
    USE SIGNAL ;
    PORT
      LAYER M3 ;
        RECT  60.768 0 60.786 0.144 ;
    END
  END aq_q[504]
  PIN aq_q[505]
    DIRECTION INPUT ;
    USE SIGNAL ;
    PORT
      LAYER M5 ;
        RECT  60.816 0 60.84 0.192 ;
    END
  END aq_q[505]
  PIN aq_q[506]
    DIRECTION INPUT ;
    USE SIGNAL ;
    PORT
      LAYER M3 ;
        RECT  60.912 0 60.93 0.144 ;
    END
  END aq_q[506]
  PIN aq_q[507]
    DIRECTION INPUT ;
    USE SIGNAL ;
    PORT
      LAYER M5 ;
        RECT  60.96 0 60.984 0.192 ;
    END
  END aq_q[507]
  PIN aq_q[508]
    DIRECTION INPUT ;
    USE SIGNAL ;
    PORT
      LAYER M3 ;
        RECT  61.056 0 61.074 0.144 ;
    END
  END aq_q[508]
  PIN aq_q[509]
    DIRECTION INPUT ;
    USE SIGNAL ;
    PORT
      LAYER M5 ;
        RECT  61.104 0 61.128 0.192 ;
    END
  END aq_q[509]
  PIN aq_q[50]
    DIRECTION INPUT ;
    USE SIGNAL ;
    PORT
      LAYER M3 ;
        RECT  28.08 0 28.098 0.144 ;
    END
  END aq_q[50]
  PIN aq_q[510]
    DIRECTION INPUT ;
    USE SIGNAL ;
    PORT
      LAYER M3 ;
        RECT  61.2 0 61.218 0.144 ;
    END
  END aq_q[510]
  PIN aq_q[511]
    DIRECTION INPUT ;
    USE SIGNAL ;
    PORT
      LAYER M5 ;
        RECT  61.248 0 61.272 0.192 ;
    END
  END aq_q[511]
  PIN aq_q[51]
    DIRECTION INPUT ;
    USE SIGNAL ;
    PORT
      LAYER M5 ;
        RECT  28.128 0 28.152 0.192 ;
    END
  END aq_q[51]
  PIN aq_q[52]
    DIRECTION INPUT ;
    USE SIGNAL ;
    PORT
      LAYER M3 ;
        RECT  28.224 0 28.242 0.144 ;
    END
  END aq_q[52]
  PIN aq_q[53]
    DIRECTION INPUT ;
    USE SIGNAL ;
    PORT
      LAYER M5 ;
        RECT  28.272 0 28.296 0.192 ;
    END
  END aq_q[53]
  PIN aq_q[54]
    DIRECTION INPUT ;
    USE SIGNAL ;
    PORT
      LAYER M3 ;
        RECT  28.368 0 28.386 0.144 ;
    END
  END aq_q[54]
  PIN aq_q[55]
    DIRECTION INPUT ;
    USE SIGNAL ;
    PORT
      LAYER M5 ;
        RECT  28.416 0 28.44 0.192 ;
    END
  END aq_q[55]
  PIN aq_q[56]
    DIRECTION INPUT ;
    USE SIGNAL ;
    PORT
      LAYER M3 ;
        RECT  28.512 0 28.53 0.144 ;
    END
  END aq_q[56]
  PIN aq_q[57]
    DIRECTION INPUT ;
    USE SIGNAL ;
    PORT
      LAYER M5 ;
        RECT  28.56 0 28.584 0.192 ;
    END
  END aq_q[57]
  PIN aq_q[58]
    DIRECTION INPUT ;
    USE SIGNAL ;
    PORT
      LAYER M3 ;
        RECT  28.656 0 28.674 0.144 ;
    END
  END aq_q[58]
  PIN aq_q[59]
    DIRECTION INPUT ;
    USE SIGNAL ;
    PORT
      LAYER M5 ;
        RECT  28.704 0 28.728 0.192 ;
    END
  END aq_q[59]
  PIN aq_q[5]
    DIRECTION INPUT ;
    USE SIGNAL ;
    PORT
      LAYER M5 ;
        RECT  24.816 0 24.84 0.192 ;
    END
  END aq_q[5]
  PIN aq_q[60]
    DIRECTION INPUT ;
    USE SIGNAL ;
    PORT
      LAYER M3 ;
        RECT  28.8 0 28.818 0.144 ;
    END
  END aq_q[60]
  PIN aq_q[61]
    DIRECTION INPUT ;
    USE SIGNAL ;
    PORT
      LAYER M5 ;
        RECT  28.848 0 28.872 0.192 ;
    END
  END aq_q[61]
  PIN aq_q[62]
    DIRECTION INPUT ;
    USE SIGNAL ;
    PORT
      LAYER M3 ;
        RECT  28.944 0 28.962 0.144 ;
    END
  END aq_q[62]
  PIN aq_q[63]
    DIRECTION INPUT ;
    USE SIGNAL ;
    PORT
      LAYER M5 ;
        RECT  28.992 0 29.016 0.192 ;
    END
  END aq_q[63]
  PIN aq_q[64]
    DIRECTION INPUT ;
    USE SIGNAL ;
    PORT
      LAYER M3 ;
        RECT  29.088 0 29.106 0.144 ;
    END
  END aq_q[64]
  PIN aq_q[65]
    DIRECTION INPUT ;
    USE SIGNAL ;
    PORT
      LAYER M5 ;
        RECT  29.136 0 29.16 0.192 ;
    END
  END aq_q[65]
  PIN aq_q[66]
    DIRECTION INPUT ;
    USE SIGNAL ;
    PORT
      LAYER M3 ;
        RECT  29.232 0 29.25 0.144 ;
    END
  END aq_q[66]
  PIN aq_q[67]
    DIRECTION INPUT ;
    USE SIGNAL ;
    PORT
      LAYER M5 ;
        RECT  29.28 0 29.304 0.192 ;
    END
  END aq_q[67]
  PIN aq_q[68]
    DIRECTION INPUT ;
    USE SIGNAL ;
    PORT
      LAYER M3 ;
        RECT  29.376 0 29.394 0.144 ;
    END
  END aq_q[68]
  PIN aq_q[69]
    DIRECTION INPUT ;
    USE SIGNAL ;
    PORT
      LAYER M5 ;
        RECT  29.424 0 29.448 0.192 ;
    END
  END aq_q[69]
  PIN aq_q[6]
    DIRECTION INPUT ;
    USE SIGNAL ;
    PORT
      LAYER M3 ;
        RECT  24.912 0 24.93 0.144 ;
    END
  END aq_q[6]
  PIN aq_q[70]
    DIRECTION INPUT ;
    USE SIGNAL ;
    PORT
      LAYER M3 ;
        RECT  29.52 0 29.538 0.144 ;
    END
  END aq_q[70]
  PIN aq_q[71]
    DIRECTION INPUT ;
    USE SIGNAL ;
    PORT
      LAYER M5 ;
        RECT  29.568 0 29.592 0.192 ;
    END
  END aq_q[71]
  PIN aq_q[72]
    DIRECTION INPUT ;
    USE SIGNAL ;
    PORT
      LAYER M3 ;
        RECT  29.664 0 29.682 0.144 ;
    END
  END aq_q[72]
  PIN aq_q[73]
    DIRECTION INPUT ;
    USE SIGNAL ;
    PORT
      LAYER M5 ;
        RECT  29.712 0 29.736 0.192 ;
    END
  END aq_q[73]
  PIN aq_q[74]
    DIRECTION INPUT ;
    USE SIGNAL ;
    PORT
      LAYER M3 ;
        RECT  29.808 0 29.826 0.144 ;
    END
  END aq_q[74]
  PIN aq_q[75]
    DIRECTION INPUT ;
    USE SIGNAL ;
    PORT
      LAYER M5 ;
        RECT  29.856 0 29.88 0.192 ;
    END
  END aq_q[75]
  PIN aq_q[76]
    DIRECTION INPUT ;
    USE SIGNAL ;
    PORT
      LAYER M3 ;
        RECT  29.952 0 29.97 0.144 ;
    END
  END aq_q[76]
  PIN aq_q[77]
    DIRECTION INPUT ;
    USE SIGNAL ;
    PORT
      LAYER M5 ;
        RECT  30 0 30.024 0.192 ;
    END
  END aq_q[77]
  PIN aq_q[78]
    DIRECTION INPUT ;
    USE SIGNAL ;
    PORT
      LAYER M3 ;
        RECT  30.096 0 30.114 0.144 ;
    END
  END aq_q[78]
  PIN aq_q[79]
    DIRECTION INPUT ;
    USE SIGNAL ;
    PORT
      LAYER M5 ;
        RECT  30.144 0 30.168 0.192 ;
    END
  END aq_q[79]
  PIN aq_q[7]
    DIRECTION INPUT ;
    USE SIGNAL ;
    PORT
      LAYER M5 ;
        RECT  24.96 0 24.984 0.192 ;
    END
  END aq_q[7]
  PIN aq_q[80]
    DIRECTION INPUT ;
    USE SIGNAL ;
    PORT
      LAYER M3 ;
        RECT  30.24 0 30.258 0.144 ;
    END
  END aq_q[80]
  PIN aq_q[81]
    DIRECTION INPUT ;
    USE SIGNAL ;
    PORT
      LAYER M5 ;
        RECT  30.288 0 30.312 0.192 ;
    END
  END aq_q[81]
  PIN aq_q[82]
    DIRECTION INPUT ;
    USE SIGNAL ;
    PORT
      LAYER M3 ;
        RECT  30.384 0 30.402 0.144 ;
    END
  END aq_q[82]
  PIN aq_q[83]
    DIRECTION INPUT ;
    USE SIGNAL ;
    PORT
      LAYER M5 ;
        RECT  30.432 0 30.456 0.192 ;
    END
  END aq_q[83]
  PIN aq_q[84]
    DIRECTION INPUT ;
    USE SIGNAL ;
    PORT
      LAYER M3 ;
        RECT  30.528 0 30.546 0.144 ;
    END
  END aq_q[84]
  PIN aq_q[85]
    DIRECTION INPUT ;
    USE SIGNAL ;
    PORT
      LAYER M5 ;
        RECT  30.576 0 30.6 0.192 ;
    END
  END aq_q[85]
  PIN aq_q[86]
    DIRECTION INPUT ;
    USE SIGNAL ;
    PORT
      LAYER M3 ;
        RECT  30.672 0 30.69 0.144 ;
    END
  END aq_q[86]
  PIN aq_q[87]
    DIRECTION INPUT ;
    USE SIGNAL ;
    PORT
      LAYER M5 ;
        RECT  30.72 0 30.744 0.192 ;
    END
  END aq_q[87]
  PIN aq_q[88]
    DIRECTION INPUT ;
    USE SIGNAL ;
    PORT
      LAYER M3 ;
        RECT  30.816 0 30.834 0.144 ;
    END
  END aq_q[88]
  PIN aq_q[89]
    DIRECTION INPUT ;
    USE SIGNAL ;
    PORT
      LAYER M5 ;
        RECT  30.864 0 30.888 0.192 ;
    END
  END aq_q[89]
  PIN aq_q[8]
    DIRECTION INPUT ;
    USE SIGNAL ;
    PORT
      LAYER M3 ;
        RECT  25.056 0 25.074 0.144 ;
    END
  END aq_q[8]
  PIN aq_q[90]
    DIRECTION INPUT ;
    USE SIGNAL ;
    PORT
      LAYER M3 ;
        RECT  30.96 0 30.978 0.144 ;
    END
  END aq_q[90]
  PIN aq_q[91]
    DIRECTION INPUT ;
    USE SIGNAL ;
    PORT
      LAYER M5 ;
        RECT  31.008 0 31.032 0.192 ;
    END
  END aq_q[91]
  PIN aq_q[92]
    DIRECTION INPUT ;
    USE SIGNAL ;
    PORT
      LAYER M3 ;
        RECT  31.104 0 31.122 0.144 ;
    END
  END aq_q[92]
  PIN aq_q[93]
    DIRECTION INPUT ;
    USE SIGNAL ;
    PORT
      LAYER M5 ;
        RECT  31.152 0 31.176 0.192 ;
    END
  END aq_q[93]
  PIN aq_q[94]
    DIRECTION INPUT ;
    USE SIGNAL ;
    PORT
      LAYER M3 ;
        RECT  31.248 0 31.266 0.144 ;
    END
  END aq_q[94]
  PIN aq_q[95]
    DIRECTION INPUT ;
    USE SIGNAL ;
    PORT
      LAYER M5 ;
        RECT  31.296 0 31.32 0.192 ;
    END
  END aq_q[95]
  PIN aq_q[96]
    DIRECTION INPUT ;
    USE SIGNAL ;
    PORT
      LAYER M3 ;
        RECT  31.392 0 31.41 0.144 ;
    END
  END aq_q[96]
  PIN aq_q[97]
    DIRECTION INPUT ;
    USE SIGNAL ;
    PORT
      LAYER M5 ;
        RECT  31.44 0 31.464 0.192 ;
    END
  END aq_q[97]
  PIN aq_q[98]
    DIRECTION INPUT ;
    USE SIGNAL ;
    PORT
      LAYER M3 ;
        RECT  31.536 0 31.554 0.144 ;
    END
  END aq_q[98]
  PIN aq_q[99]
    DIRECTION INPUT ;
    USE SIGNAL ;
    PORT
      LAYER M5 ;
        RECT  31.584 0 31.608 0.192 ;
    END
  END aq_q[99]
  PIN aq_q[9]
    DIRECTION INPUT ;
    USE SIGNAL ;
    PORT
      LAYER M5 ;
        RECT  25.104 0 25.128 0.192 ;
    END
  END aq_q[9]
  PIN clk
    DIRECTION INPUT ;
    USE SIGNAL ;
    PORT
      LAYER M4 ;
        RECT  0 52.032 0.192 52.056 ;
    END
    PORT
      LAYER M4 ;
        RECT  0.156 52.032 0.275 52.056 ;
    END
  END clk
  PIN erd[0]
    DIRECTION OUTPUT ;
    USE SIGNAL ;
    PORT
      LAYER M3 ;
        RECT  47.52 86.256 47.538 86.4 ;
    END
  END erd[0]
  PIN erd[1]
    DIRECTION OUTPUT ;
    USE SIGNAL ;
    PORT
      LAYER M3 ;
        RECT  47.664 86.256 47.682 86.4 ;
    END
  END erd[1]
  PIN erd[2]
    DIRECTION OUTPUT ;
    USE SIGNAL ;
    PORT
      LAYER M3 ;
        RECT  47.808 86.256 47.826 86.4 ;
    END
  END erd[2]
  PIN erd[3]
    DIRECTION OUTPUT ;
    USE SIGNAL ;
    PORT
      LAYER M3 ;
        RECT  47.952 86.256 47.97 86.4 ;
    END
  END erd[3]
  PIN erd[4]
    DIRECTION OUTPUT ;
    USE SIGNAL ;
    PORT
      LAYER M3 ;
        RECT  48.096 86.256 48.114 86.4 ;
    END
  END erd[4]
  PIN erd[5]
    DIRECTION OUTPUT ;
    USE SIGNAL ;
    PORT
      LAYER M3 ;
        RECT  48.24 86.256 48.258 86.4 ;
    END
  END erd[5]
  PIN erd[6]
    DIRECTION OUTPUT ;
    USE SIGNAL ;
    PORT
      LAYER M3 ;
        RECT  48.384 86.256 48.402 86.4 ;
    END
  END erd[6]
  PIN erd[7]
    DIRECTION OUTPUT ;
    USE SIGNAL ;
    PORT
      LAYER M3 ;
        RECT  48.528 86.256 48.546 86.4 ;
    END
  END erd[7]
  PIN erd[8]
    DIRECTION OUTPUT ;
    USE SIGNAL ;
    PORT
      LAYER M3 ;
        RECT  48.672 86.256 48.69 86.4 ;
    END
  END erd[8]
  PIN erd[9]
    DIRECTION OUTPUT ;
    USE SIGNAL ;
    PORT
      LAYER M3 ;
        RECT  48.816 86.256 48.834 86.4 ;
    END
  END erd[9]
  PIN fault
    DIRECTION OUTPUT ;
    USE SIGNAL ;
    PORT
      LAYER M4 ;
        RECT  142.368 52.032 142.56 52.056 ;
    END
    PORT
      LAYER M4 ;
        RECT  141.901 52.032 142.38 52.056 ;
    END
  END fault
  PIN i0[0]
    DIRECTION INPUT ;
    USE SIGNAL ;
    PORT
      LAYER M4 ;
        RECT  0 41.616 0.192 41.64 ;
    END
  END i0[0]
  PIN i0[10]
    DIRECTION INPUT ;
    USE SIGNAL ;
    PORT
      LAYER M4 ;
        RECT  0 43.056 0.192 43.08 ;
    END
  END i0[10]
  PIN i0[11]
    DIRECTION INPUT ;
    USE SIGNAL ;
    PORT
      LAYER M4 ;
        RECT  0 43.2 0.192 43.224 ;
    END
  END i0[11]
  PIN i0[12]
    DIRECTION INPUT ;
    USE SIGNAL ;
    PORT
      LAYER M4 ;
        RECT  0 43.344 0.192 43.368 ;
    END
  END i0[12]
  PIN i0[13]
    DIRECTION INPUT ;
    USE SIGNAL ;
    PORT
      LAYER M4 ;
        RECT  0 43.488 0.192 43.512 ;
    END
  END i0[13]
  PIN i0[14]
    DIRECTION INPUT ;
    USE SIGNAL ;
    PORT
      LAYER M4 ;
        RECT  0 43.632 0.192 43.656 ;
    END
  END i0[14]
  PIN i0[15]
    DIRECTION INPUT ;
    USE SIGNAL ;
    PORT
      LAYER M4 ;
        RECT  0 43.776 0.192 43.8 ;
    END
  END i0[15]
  PIN i0[1]
    DIRECTION INPUT ;
    USE SIGNAL ;
    PORT
      LAYER M4 ;
        RECT  0 41.76 0.192 41.784 ;
    END
  END i0[1]
  PIN i0[2]
    DIRECTION INPUT ;
    USE SIGNAL ;
    PORT
      LAYER M4 ;
        RECT  0 41.904 0.192 41.928 ;
    END
  END i0[2]
  PIN i0[3]
    DIRECTION INPUT ;
    USE SIGNAL ;
    PORT
      LAYER M4 ;
        RECT  0 42.048 0.192 42.072 ;
    END
  END i0[3]
  PIN i0[4]
    DIRECTION INPUT ;
    USE SIGNAL ;
    PORT
      LAYER M4 ;
        RECT  0 42.192 0.192 42.216 ;
    END
  END i0[4]
  PIN i0[5]
    DIRECTION INPUT ;
    USE SIGNAL ;
    PORT
      LAYER M4 ;
        RECT  0 42.336 0.192 42.36 ;
    END
  END i0[5]
  PIN i0[6]
    DIRECTION INPUT ;
    USE SIGNAL ;
    PORT
      LAYER M4 ;
        RECT  0 42.48 0.192 42.504 ;
    END
  END i0[6]
  PIN i0[7]
    DIRECTION INPUT ;
    USE SIGNAL ;
    PORT
      LAYER M4 ;
        RECT  0 42.624 0.192 42.648 ;
    END
  END i0[7]
  PIN i0[8]
    DIRECTION INPUT ;
    USE SIGNAL ;
    PORT
      LAYER M4 ;
        RECT  0 42.768 0.192 42.792 ;
    END
  END i0[8]
  PIN i0[9]
    DIRECTION INPUT ;
    USE SIGNAL ;
    PORT
      LAYER M4 ;
        RECT  0 42.912 0.192 42.936 ;
    END
  END i0[9]
  PIN i1[0]
    DIRECTION INPUT ;
    USE SIGNAL ;
    PORT
      LAYER M4 ;
        RECT  0 43.92 0.192 43.944 ;
    END
  END i1[0]
  PIN i1[10]
    DIRECTION INPUT ;
    USE SIGNAL ;
    PORT
      LAYER M4 ;
        RECT  0 45.36 0.192 45.384 ;
    END
  END i1[10]
  PIN i1[11]
    DIRECTION INPUT ;
    USE SIGNAL ;
    PORT
      LAYER M4 ;
        RECT  0 45.504 0.192 45.528 ;
    END
  END i1[11]
  PIN i1[12]
    DIRECTION INPUT ;
    USE SIGNAL ;
    PORT
      LAYER M4 ;
        RECT  0 45.648 0.192 45.672 ;
    END
  END i1[12]
  PIN i1[13]
    DIRECTION INPUT ;
    USE SIGNAL ;
    PORT
      LAYER M4 ;
        RECT  0 45.792 0.192 45.816 ;
    END
  END i1[13]
  PIN i1[14]
    DIRECTION INPUT ;
    USE SIGNAL ;
    PORT
      LAYER M4 ;
        RECT  0 45.936 0.192 45.96 ;
    END
  END i1[14]
  PIN i1[15]
    DIRECTION INPUT ;
    USE SIGNAL ;
    PORT
      LAYER M4 ;
        RECT  0 46.08 0.192 46.104 ;
    END
  END i1[15]
  PIN i1[1]
    DIRECTION INPUT ;
    USE SIGNAL ;
    PORT
      LAYER M4 ;
        RECT  0 44.064 0.192 44.088 ;
    END
  END i1[1]
  PIN i1[2]
    DIRECTION INPUT ;
    USE SIGNAL ;
    PORT
      LAYER M4 ;
        RECT  0 44.208 0.192 44.232 ;
    END
  END i1[2]
  PIN i1[3]
    DIRECTION INPUT ;
    USE SIGNAL ;
    PORT
      LAYER M4 ;
        RECT  0 44.352 0.192 44.376 ;
    END
  END i1[3]
  PIN i1[4]
    DIRECTION INPUT ;
    USE SIGNAL ;
    PORT
      LAYER M4 ;
        RECT  0 44.496 0.192 44.52 ;
    END
  END i1[4]
  PIN i1[5]
    DIRECTION INPUT ;
    USE SIGNAL ;
    PORT
      LAYER M4 ;
        RECT  0 44.64 0.192 44.664 ;
    END
  END i1[5]
  PIN i1[6]
    DIRECTION INPUT ;
    USE SIGNAL ;
    PORT
      LAYER M4 ;
        RECT  0 44.784 0.192 44.808 ;
    END
  END i1[6]
  PIN i1[7]
    DIRECTION INPUT ;
    USE SIGNAL ;
    PORT
      LAYER M4 ;
        RECT  0 44.928 0.192 44.952 ;
    END
  END i1[7]
  PIN i1[8]
    DIRECTION INPUT ;
    USE SIGNAL ;
    PORT
      LAYER M4 ;
        RECT  0 45.072 0.192 45.096 ;
    END
  END i1[8]
  PIN i1[9]
    DIRECTION INPUT ;
    USE SIGNAL ;
    PORT
      LAYER M4 ;
        RECT  0 45.216 0.192 45.24 ;
    END
  END i1[9]
  PIN ph0[0]
    DIRECTION INPUT ;
    USE SIGNAL ;
    PORT
      LAYER M4 ;
        RECT  0 38.448 0.192 38.472 ;
    END
  END ph0[0]
  PIN ph0[1]
    DIRECTION INPUT ;
    USE SIGNAL ;
    PORT
      LAYER M4 ;
        RECT  0 38.304 0.192 38.328 ;
    END
  END ph0[1]
  PIN ph0[2]
    DIRECTION INPUT ;
    USE SIGNAL ;
    PORT
      LAYER M4 ;
        RECT  0 38.16 0.192 38.184 ;
    END
  END ph0[2]
  PIN ph0[3]
    DIRECTION INPUT ;
    USE SIGNAL ;
    PORT
      LAYER M4 ;
        RECT  0 38.016 0.192 38.04 ;
    END
  END ph0[3]
  PIN ph0[4]
    DIRECTION INPUT ;
    USE SIGNAL ;
    PORT
      LAYER M4 ;
        RECT  0 37.872 0.192 37.896 ;
    END
  END ph0[4]
  PIN ph0[5]
    DIRECTION INPUT ;
    USE SIGNAL ;
    PORT
      LAYER M4 ;
        RECT  0 37.728 0.192 37.752 ;
    END
  END ph0[5]
  PIN ph1[0]
    DIRECTION INPUT ;
    USE SIGNAL ;
    PORT
      LAYER M4 ;
        RECT  0 37.584 0.192 37.608 ;
    END
  END ph1[0]
  PIN ph1[1]
    DIRECTION INPUT ;
    USE SIGNAL ;
    PORT
      LAYER M4 ;
        RECT  0 37.44 0.192 37.464 ;
    END
  END ph1[1]
  PIN ph1[2]
    DIRECTION INPUT ;
    USE SIGNAL ;
    PORT
      LAYER M4 ;
        RECT  0 37.296 0.192 37.32 ;
    END
  END ph1[2]
  PIN ph1[3]
    DIRECTION INPUT ;
    USE SIGNAL ;
    PORT
      LAYER M4 ;
        RECT  0 37.152 0.192 37.176 ;
    END
  END ph1[3]
  PIN ph1[4]
    DIRECTION INPUT ;
    USE SIGNAL ;
    PORT
      LAYER M4 ;
        RECT  0 37.008 0.192 37.032 ;
    END
  END ph1[4]
  PIN ph1[5]
    DIRECTION INPUT ;
    USE SIGNAL ;
    PORT
      LAYER M4 ;
        RECT  0 36.864 0.192 36.888 ;
    END
  END ph1[5]
  PIN pl0[0]
    DIRECTION INPUT ;
    USE SIGNAL ;
    PORT
      LAYER M4 ;
        RECT  0 36.72 0.192 36.744 ;
    END
  END pl0[0]
  PIN pl0[10]
    DIRECTION INPUT ;
    USE SIGNAL ;
    PORT
      LAYER M4 ;
        RECT  0 35.28 0.192 35.304 ;
    END
  END pl0[10]
  PIN pl0[11]
    DIRECTION INPUT ;
    USE SIGNAL ;
    PORT
      LAYER M4 ;
        RECT  0 35.136 0.192 35.16 ;
    END
  END pl0[11]
  PIN pl0[12]
    DIRECTION INPUT ;
    USE SIGNAL ;
    PORT
      LAYER M4 ;
        RECT  0 34.992 0.192 35.016 ;
    END
  END pl0[12]
  PIN pl0[13]
    DIRECTION INPUT ;
    USE SIGNAL ;
    PORT
      LAYER M4 ;
        RECT  0 34.848 0.192 34.872 ;
    END
  END pl0[13]
  PIN pl0[14]
    DIRECTION INPUT ;
    USE SIGNAL ;
    PORT
      LAYER M4 ;
        RECT  0 34.704 0.192 34.728 ;
    END
  END pl0[14]
  PIN pl0[15]
    DIRECTION INPUT ;
    USE SIGNAL ;
    PORT
      LAYER M4 ;
        RECT  0 34.56 0.192 34.584 ;
    END
  END pl0[15]
  PIN pl0[1]
    DIRECTION INPUT ;
    USE SIGNAL ;
    PORT
      LAYER M4 ;
        RECT  0 36.576 0.192 36.6 ;
    END
  END pl0[1]
  PIN pl0[2]
    DIRECTION INPUT ;
    USE SIGNAL ;
    PORT
      LAYER M4 ;
        RECT  0 36.432 0.192 36.456 ;
    END
  END pl0[2]
  PIN pl0[3]
    DIRECTION INPUT ;
    USE SIGNAL ;
    PORT
      LAYER M4 ;
        RECT  0 36.288 0.192 36.312 ;
    END
  END pl0[3]
  PIN pl0[4]
    DIRECTION INPUT ;
    USE SIGNAL ;
    PORT
      LAYER M4 ;
        RECT  0 36.144 0.192 36.168 ;
    END
  END pl0[4]
  PIN pl0[5]
    DIRECTION INPUT ;
    USE SIGNAL ;
    PORT
      LAYER M4 ;
        RECT  0 36 0.192 36.024 ;
    END
  END pl0[5]
  PIN pl0[6]
    DIRECTION INPUT ;
    USE SIGNAL ;
    PORT
      LAYER M4 ;
        RECT  0 35.856 0.192 35.88 ;
    END
  END pl0[6]
  PIN pl0[7]
    DIRECTION INPUT ;
    USE SIGNAL ;
    PORT
      LAYER M4 ;
        RECT  0 35.712 0.192 35.736 ;
    END
  END pl0[7]
  PIN pl0[8]
    DIRECTION INPUT ;
    USE SIGNAL ;
    PORT
      LAYER M4 ;
        RECT  0 35.568 0.192 35.592 ;
    END
  END pl0[8]
  PIN pl0[9]
    DIRECTION INPUT ;
    USE SIGNAL ;
    PORT
      LAYER M4 ;
        RECT  0 35.424 0.192 35.448 ;
    END
  END pl0[9]
  PIN pl1[0]
    DIRECTION INPUT ;
    USE SIGNAL ;
    PORT
      LAYER M4 ;
        RECT  0 34.416 0.192 34.44 ;
    END
  END pl1[0]
  PIN pl1[10]
    DIRECTION INPUT ;
    USE SIGNAL ;
    PORT
      LAYER M4 ;
        RECT  0 32.976 0.192 33 ;
    END
  END pl1[10]
  PIN pl1[11]
    DIRECTION INPUT ;
    USE SIGNAL ;
    PORT
      LAYER M4 ;
        RECT  0 32.832 0.192 32.856 ;
    END
  END pl1[11]
  PIN pl1[12]
    DIRECTION INPUT ;
    USE SIGNAL ;
    PORT
      LAYER M4 ;
        RECT  0 32.688 0.192 32.712 ;
    END
  END pl1[12]
  PIN pl1[13]
    DIRECTION INPUT ;
    USE SIGNAL ;
    PORT
      LAYER M4 ;
        RECT  0 32.544 0.192 32.568 ;
    END
  END pl1[13]
  PIN pl1[14]
    DIRECTION INPUT ;
    USE SIGNAL ;
    PORT
      LAYER M4 ;
        RECT  0 32.4 0.192 32.424 ;
    END
  END pl1[14]
  PIN pl1[15]
    DIRECTION INPUT ;
    USE SIGNAL ;
    PORT
      LAYER M4 ;
        RECT  0 32.256 0.192 32.28 ;
    END
  END pl1[15]
  PIN pl1[1]
    DIRECTION INPUT ;
    USE SIGNAL ;
    PORT
      LAYER M4 ;
        RECT  0 34.272 0.192 34.296 ;
    END
  END pl1[1]
  PIN pl1[2]
    DIRECTION INPUT ;
    USE SIGNAL ;
    PORT
      LAYER M4 ;
        RECT  0 34.128 0.192 34.152 ;
    END
  END pl1[2]
  PIN pl1[3]
    DIRECTION INPUT ;
    USE SIGNAL ;
    PORT
      LAYER M4 ;
        RECT  0 33.984 0.192 34.008 ;
    END
  END pl1[3]
  PIN pl1[4]
    DIRECTION INPUT ;
    USE SIGNAL ;
    PORT
      LAYER M4 ;
        RECT  0 33.84 0.192 33.864 ;
    END
  END pl1[4]
  PIN pl1[5]
    DIRECTION INPUT ;
    USE SIGNAL ;
    PORT
      LAYER M4 ;
        RECT  0 33.696 0.192 33.72 ;
    END
  END pl1[5]
  PIN pl1[6]
    DIRECTION INPUT ;
    USE SIGNAL ;
    PORT
      LAYER M4 ;
        RECT  0 33.552 0.192 33.576 ;
    END
  END pl1[6]
  PIN pl1[7]
    DIRECTION INPUT ;
    USE SIGNAL ;
    PORT
      LAYER M4 ;
        RECT  0 33.408 0.192 33.432 ;
    END
  END pl1[7]
  PIN pl1[8]
    DIRECTION INPUT ;
    USE SIGNAL ;
    PORT
      LAYER M4 ;
        RECT  0 33.264 0.192 33.288 ;
    END
  END pl1[8]
  PIN pl1[9]
    DIRECTION INPUT ;
    USE SIGNAL ;
    PORT
      LAYER M4 ;
        RECT  0 33.12 0.192 33.144 ;
    END
  END pl1[9]
  PIN rd[0]
    DIRECTION OUTPUT ;
    USE SIGNAL ;
    PORT
      LAYER M3 ;
        RECT  24.48 86.256 24.498 86.4 ;
    END
  END rd[0]
  PIN rd[100]
    DIRECTION OUTPUT ;
    USE SIGNAL ;
    PORT
      LAYER M3 ;
        RECT  31.68 86.256 31.698 86.4 ;
    END
  END rd[100]
  PIN rd[101]
    DIRECTION OUTPUT ;
    USE SIGNAL ;
    PORT
      LAYER M5 ;
        RECT  31.728 86.208 31.752 86.4 ;
    END
  END rd[101]
  PIN rd[102]
    DIRECTION OUTPUT ;
    USE SIGNAL ;
    PORT
      LAYER M3 ;
        RECT  31.824 86.256 31.842 86.4 ;
    END
  END rd[102]
  PIN rd[103]
    DIRECTION OUTPUT ;
    USE SIGNAL ;
    PORT
      LAYER M5 ;
        RECT  31.872 86.208 31.896 86.4 ;
    END
  END rd[103]
  PIN rd[104]
    DIRECTION OUTPUT ;
    USE SIGNAL ;
    PORT
      LAYER M3 ;
        RECT  31.968 86.256 31.986 86.4 ;
    END
  END rd[104]
  PIN rd[105]
    DIRECTION OUTPUT ;
    USE SIGNAL ;
    PORT
      LAYER M5 ;
        RECT  32.016 86.208 32.04 86.4 ;
    END
  END rd[105]
  PIN rd[106]
    DIRECTION OUTPUT ;
    USE SIGNAL ;
    PORT
      LAYER M3 ;
        RECT  32.112 86.256 32.13 86.4 ;
    END
  END rd[106]
  PIN rd[107]
    DIRECTION OUTPUT ;
    USE SIGNAL ;
    PORT
      LAYER M5 ;
        RECT  32.16 86.208 32.184 86.4 ;
    END
  END rd[107]
  PIN rd[108]
    DIRECTION OUTPUT ;
    USE SIGNAL ;
    PORT
      LAYER M3 ;
        RECT  32.256 86.256 32.274 86.4 ;
    END
  END rd[108]
  PIN rd[109]
    DIRECTION OUTPUT ;
    USE SIGNAL ;
    PORT
      LAYER M5 ;
        RECT  32.304 86.208 32.328 86.4 ;
    END
  END rd[109]
  PIN rd[10]
    DIRECTION OUTPUT ;
    USE SIGNAL ;
    PORT
      LAYER M3 ;
        RECT  25.2 86.256 25.218 86.4 ;
    END
  END rd[10]
  PIN rd[110]
    DIRECTION OUTPUT ;
    USE SIGNAL ;
    PORT
      LAYER M3 ;
        RECT  32.4 86.256 32.418 86.4 ;
    END
  END rd[110]
  PIN rd[111]
    DIRECTION OUTPUT ;
    USE SIGNAL ;
    PORT
      LAYER M5 ;
        RECT  32.448 86.208 32.472 86.4 ;
    END
  END rd[111]
  PIN rd[112]
    DIRECTION OUTPUT ;
    USE SIGNAL ;
    PORT
      LAYER M3 ;
        RECT  32.544 86.256 32.562 86.4 ;
    END
  END rd[112]
  PIN rd[113]
    DIRECTION OUTPUT ;
    USE SIGNAL ;
    PORT
      LAYER M5 ;
        RECT  32.592 86.208 32.616 86.4 ;
    END
  END rd[113]
  PIN rd[114]
    DIRECTION OUTPUT ;
    USE SIGNAL ;
    PORT
      LAYER M3 ;
        RECT  32.688 86.256 32.706 86.4 ;
    END
  END rd[114]
  PIN rd[115]
    DIRECTION OUTPUT ;
    USE SIGNAL ;
    PORT
      LAYER M5 ;
        RECT  32.736 86.208 32.76 86.4 ;
    END
  END rd[115]
  PIN rd[116]
    DIRECTION OUTPUT ;
    USE SIGNAL ;
    PORT
      LAYER M3 ;
        RECT  32.832 86.256 32.85 86.4 ;
    END
  END rd[116]
  PIN rd[117]
    DIRECTION OUTPUT ;
    USE SIGNAL ;
    PORT
      LAYER M5 ;
        RECT  32.88 86.208 32.904 86.4 ;
    END
  END rd[117]
  PIN rd[118]
    DIRECTION OUTPUT ;
    USE SIGNAL ;
    PORT
      LAYER M3 ;
        RECT  32.976 86.256 32.994 86.4 ;
    END
  END rd[118]
  PIN rd[119]
    DIRECTION OUTPUT ;
    USE SIGNAL ;
    PORT
      LAYER M5 ;
        RECT  33.024 86.208 33.048 86.4 ;
    END
  END rd[119]
  PIN rd[11]
    DIRECTION OUTPUT ;
    USE SIGNAL ;
    PORT
      LAYER M5 ;
        RECT  25.248 86.208 25.272 86.4 ;
    END
  END rd[11]
  PIN rd[120]
    DIRECTION OUTPUT ;
    USE SIGNAL ;
    PORT
      LAYER M3 ;
        RECT  33.12 86.256 33.138 86.4 ;
    END
  END rd[120]
  PIN rd[121]
    DIRECTION OUTPUT ;
    USE SIGNAL ;
    PORT
      LAYER M5 ;
        RECT  33.168 86.208 33.192 86.4 ;
    END
  END rd[121]
  PIN rd[122]
    DIRECTION OUTPUT ;
    USE SIGNAL ;
    PORT
      LAYER M3 ;
        RECT  33.264 86.256 33.282 86.4 ;
    END
  END rd[122]
  PIN rd[123]
    DIRECTION OUTPUT ;
    USE SIGNAL ;
    PORT
      LAYER M5 ;
        RECT  33.312 86.208 33.336 86.4 ;
    END
  END rd[123]
  PIN rd[124]
    DIRECTION OUTPUT ;
    USE SIGNAL ;
    PORT
      LAYER M3 ;
        RECT  33.408 86.256 33.426 86.4 ;
    END
  END rd[124]
  PIN rd[125]
    DIRECTION OUTPUT ;
    USE SIGNAL ;
    PORT
      LAYER M5 ;
        RECT  33.456 86.208 33.48 86.4 ;
    END
  END rd[125]
  PIN rd[126]
    DIRECTION OUTPUT ;
    USE SIGNAL ;
    PORT
      LAYER M3 ;
        RECT  33.552 86.256 33.57 86.4 ;
    END
  END rd[126]
  PIN rd[127]
    DIRECTION OUTPUT ;
    USE SIGNAL ;
    PORT
      LAYER M5 ;
        RECT  33.6 86.208 33.624 86.4 ;
    END
  END rd[127]
  PIN rd[128]
    DIRECTION OUTPUT ;
    USE SIGNAL ;
    PORT
      LAYER M3 ;
        RECT  33.696 86.256 33.714 86.4 ;
    END
  END rd[128]
  PIN rd[129]
    DIRECTION OUTPUT ;
    USE SIGNAL ;
    PORT
      LAYER M5 ;
        RECT  33.744 86.208 33.768 86.4 ;
    END
  END rd[129]
  PIN rd[12]
    DIRECTION OUTPUT ;
    USE SIGNAL ;
    PORT
      LAYER M3 ;
        RECT  25.344 86.256 25.362 86.4 ;
    END
  END rd[12]
  PIN rd[130]
    DIRECTION OUTPUT ;
    USE SIGNAL ;
    PORT
      LAYER M3 ;
        RECT  33.84 86.256 33.858 86.4 ;
    END
  END rd[130]
  PIN rd[131]
    DIRECTION OUTPUT ;
    USE SIGNAL ;
    PORT
      LAYER M5 ;
        RECT  33.888 86.208 33.912 86.4 ;
    END
  END rd[131]
  PIN rd[132]
    DIRECTION OUTPUT ;
    USE SIGNAL ;
    PORT
      LAYER M3 ;
        RECT  33.984 86.256 34.002 86.4 ;
    END
  END rd[132]
  PIN rd[133]
    DIRECTION OUTPUT ;
    USE SIGNAL ;
    PORT
      LAYER M5 ;
        RECT  34.032 86.208 34.056 86.4 ;
    END
  END rd[133]
  PIN rd[134]
    DIRECTION OUTPUT ;
    USE SIGNAL ;
    PORT
      LAYER M3 ;
        RECT  34.128 86.256 34.146 86.4 ;
    END
  END rd[134]
  PIN rd[135]
    DIRECTION OUTPUT ;
    USE SIGNAL ;
    PORT
      LAYER M5 ;
        RECT  34.176 86.208 34.2 86.4 ;
    END
  END rd[135]
  PIN rd[136]
    DIRECTION OUTPUT ;
    USE SIGNAL ;
    PORT
      LAYER M3 ;
        RECT  34.272 86.256 34.29 86.4 ;
    END
  END rd[136]
  PIN rd[137]
    DIRECTION OUTPUT ;
    USE SIGNAL ;
    PORT
      LAYER M5 ;
        RECT  34.32 86.208 34.344 86.4 ;
    END
  END rd[137]
  PIN rd[138]
    DIRECTION OUTPUT ;
    USE SIGNAL ;
    PORT
      LAYER M3 ;
        RECT  34.416 86.256 34.434 86.4 ;
    END
  END rd[138]
  PIN rd[139]
    DIRECTION OUTPUT ;
    USE SIGNAL ;
    PORT
      LAYER M5 ;
        RECT  34.464 86.208 34.488 86.4 ;
    END
  END rd[139]
  PIN rd[13]
    DIRECTION OUTPUT ;
    USE SIGNAL ;
    PORT
      LAYER M5 ;
        RECT  25.392 86.208 25.416 86.4 ;
    END
  END rd[13]
  PIN rd[140]
    DIRECTION OUTPUT ;
    USE SIGNAL ;
    PORT
      LAYER M3 ;
        RECT  34.56 86.256 34.578 86.4 ;
    END
  END rd[140]
  PIN rd[141]
    DIRECTION OUTPUT ;
    USE SIGNAL ;
    PORT
      LAYER M5 ;
        RECT  34.608 86.208 34.632 86.4 ;
    END
  END rd[141]
  PIN rd[142]
    DIRECTION OUTPUT ;
    USE SIGNAL ;
    PORT
      LAYER M3 ;
        RECT  34.704 86.256 34.722 86.4 ;
    END
  END rd[142]
  PIN rd[143]
    DIRECTION OUTPUT ;
    USE SIGNAL ;
    PORT
      LAYER M5 ;
        RECT  34.752 86.208 34.776 86.4 ;
    END
  END rd[143]
  PIN rd[144]
    DIRECTION OUTPUT ;
    USE SIGNAL ;
    PORT
      LAYER M3 ;
        RECT  34.848 86.256 34.866 86.4 ;
    END
  END rd[144]
  PIN rd[145]
    DIRECTION OUTPUT ;
    USE SIGNAL ;
    PORT
      LAYER M5 ;
        RECT  34.896 86.208 34.92 86.4 ;
    END
  END rd[145]
  PIN rd[146]
    DIRECTION OUTPUT ;
    USE SIGNAL ;
    PORT
      LAYER M3 ;
        RECT  34.992 86.256 35.01 86.4 ;
    END
  END rd[146]
  PIN rd[147]
    DIRECTION OUTPUT ;
    USE SIGNAL ;
    PORT
      LAYER M5 ;
        RECT  35.04 86.208 35.064 86.4 ;
    END
  END rd[147]
  PIN rd[148]
    DIRECTION OUTPUT ;
    USE SIGNAL ;
    PORT
      LAYER M3 ;
        RECT  35.136 86.256 35.154 86.4 ;
    END
  END rd[148]
  PIN rd[149]
    DIRECTION OUTPUT ;
    USE SIGNAL ;
    PORT
      LAYER M5 ;
        RECT  35.184 86.208 35.208 86.4 ;
    END
  END rd[149]
  PIN rd[14]
    DIRECTION OUTPUT ;
    USE SIGNAL ;
    PORT
      LAYER M3 ;
        RECT  25.488 86.256 25.506 86.4 ;
    END
  END rd[14]
  PIN rd[150]
    DIRECTION OUTPUT ;
    USE SIGNAL ;
    PORT
      LAYER M3 ;
        RECT  35.28 86.256 35.298 86.4 ;
    END
  END rd[150]
  PIN rd[151]
    DIRECTION OUTPUT ;
    USE SIGNAL ;
    PORT
      LAYER M5 ;
        RECT  35.328 86.208 35.352 86.4 ;
    END
  END rd[151]
  PIN rd[152]
    DIRECTION OUTPUT ;
    USE SIGNAL ;
    PORT
      LAYER M3 ;
        RECT  35.424 86.256 35.442 86.4 ;
    END
  END rd[152]
  PIN rd[153]
    DIRECTION OUTPUT ;
    USE SIGNAL ;
    PORT
      LAYER M5 ;
        RECT  35.472 86.208 35.496 86.4 ;
    END
  END rd[153]
  PIN rd[154]
    DIRECTION OUTPUT ;
    USE SIGNAL ;
    PORT
      LAYER M3 ;
        RECT  35.568 86.256 35.586 86.4 ;
    END
  END rd[154]
  PIN rd[155]
    DIRECTION OUTPUT ;
    USE SIGNAL ;
    PORT
      LAYER M5 ;
        RECT  35.616 86.208 35.64 86.4 ;
    END
  END rd[155]
  PIN rd[156]
    DIRECTION OUTPUT ;
    USE SIGNAL ;
    PORT
      LAYER M3 ;
        RECT  35.712 86.256 35.73 86.4 ;
    END
  END rd[156]
  PIN rd[157]
    DIRECTION OUTPUT ;
    USE SIGNAL ;
    PORT
      LAYER M5 ;
        RECT  35.76 86.208 35.784 86.4 ;
    END
  END rd[157]
  PIN rd[158]
    DIRECTION OUTPUT ;
    USE SIGNAL ;
    PORT
      LAYER M3 ;
        RECT  35.856 86.256 35.874 86.4 ;
    END
  END rd[158]
  PIN rd[159]
    DIRECTION OUTPUT ;
    USE SIGNAL ;
    PORT
      LAYER M5 ;
        RECT  35.904 86.208 35.928 86.4 ;
    END
  END rd[159]
  PIN rd[15]
    DIRECTION OUTPUT ;
    USE SIGNAL ;
    PORT
      LAYER M5 ;
        RECT  25.536 86.208 25.56 86.4 ;
    END
  END rd[15]
  PIN rd[160]
    DIRECTION OUTPUT ;
    USE SIGNAL ;
    PORT
      LAYER M3 ;
        RECT  36 86.256 36.018 86.4 ;
    END
  END rd[160]
  PIN rd[161]
    DIRECTION OUTPUT ;
    USE SIGNAL ;
    PORT
      LAYER M5 ;
        RECT  36.048 86.208 36.072 86.4 ;
    END
  END rd[161]
  PIN rd[162]
    DIRECTION OUTPUT ;
    USE SIGNAL ;
    PORT
      LAYER M3 ;
        RECT  36.144 86.256 36.162 86.4 ;
    END
  END rd[162]
  PIN rd[163]
    DIRECTION OUTPUT ;
    USE SIGNAL ;
    PORT
      LAYER M5 ;
        RECT  36.192 86.208 36.216 86.4 ;
    END
  END rd[163]
  PIN rd[164]
    DIRECTION OUTPUT ;
    USE SIGNAL ;
    PORT
      LAYER M3 ;
        RECT  36.288 86.256 36.306 86.4 ;
    END
  END rd[164]
  PIN rd[165]
    DIRECTION OUTPUT ;
    USE SIGNAL ;
    PORT
      LAYER M5 ;
        RECT  36.336 86.208 36.36 86.4 ;
    END
  END rd[165]
  PIN rd[166]
    DIRECTION OUTPUT ;
    USE SIGNAL ;
    PORT
      LAYER M3 ;
        RECT  36.432 86.256 36.45 86.4 ;
    END
  END rd[166]
  PIN rd[167]
    DIRECTION OUTPUT ;
    USE SIGNAL ;
    PORT
      LAYER M5 ;
        RECT  36.48 86.208 36.504 86.4 ;
    END
  END rd[167]
  PIN rd[168]
    DIRECTION OUTPUT ;
    USE SIGNAL ;
    PORT
      LAYER M3 ;
        RECT  36.576 86.256 36.594 86.4 ;
    END
  END rd[168]
  PIN rd[169]
    DIRECTION OUTPUT ;
    USE SIGNAL ;
    PORT
      LAYER M5 ;
        RECT  36.624 86.208 36.648 86.4 ;
    END
  END rd[169]
  PIN rd[16]
    DIRECTION OUTPUT ;
    USE SIGNAL ;
    PORT
      LAYER M3 ;
        RECT  25.632 86.256 25.65 86.4 ;
    END
  END rd[16]
  PIN rd[170]
    DIRECTION OUTPUT ;
    USE SIGNAL ;
    PORT
      LAYER M3 ;
        RECT  36.72 86.256 36.738 86.4 ;
    END
  END rd[170]
  PIN rd[171]
    DIRECTION OUTPUT ;
    USE SIGNAL ;
    PORT
      LAYER M5 ;
        RECT  36.768 86.208 36.792 86.4 ;
    END
  END rd[171]
  PIN rd[172]
    DIRECTION OUTPUT ;
    USE SIGNAL ;
    PORT
      LAYER M3 ;
        RECT  36.864 86.256 36.882 86.4 ;
    END
  END rd[172]
  PIN rd[173]
    DIRECTION OUTPUT ;
    USE SIGNAL ;
    PORT
      LAYER M5 ;
        RECT  36.912 86.208 36.936 86.4 ;
    END
  END rd[173]
  PIN rd[174]
    DIRECTION OUTPUT ;
    USE SIGNAL ;
    PORT
      LAYER M3 ;
        RECT  37.008 86.256 37.026 86.4 ;
    END
  END rd[174]
  PIN rd[175]
    DIRECTION OUTPUT ;
    USE SIGNAL ;
    PORT
      LAYER M5 ;
        RECT  37.056 86.208 37.08 86.4 ;
    END
  END rd[175]
  PIN rd[176]
    DIRECTION OUTPUT ;
    USE SIGNAL ;
    PORT
      LAYER M3 ;
        RECT  37.152 86.256 37.17 86.4 ;
    END
  END rd[176]
  PIN rd[177]
    DIRECTION OUTPUT ;
    USE SIGNAL ;
    PORT
      LAYER M5 ;
        RECT  37.2 86.208 37.224 86.4 ;
    END
  END rd[177]
  PIN rd[178]
    DIRECTION OUTPUT ;
    USE SIGNAL ;
    PORT
      LAYER M3 ;
        RECT  37.296 86.256 37.314 86.4 ;
    END
  END rd[178]
  PIN rd[179]
    DIRECTION OUTPUT ;
    USE SIGNAL ;
    PORT
      LAYER M5 ;
        RECT  37.344 86.208 37.368 86.4 ;
    END
  END rd[179]
  PIN rd[17]
    DIRECTION OUTPUT ;
    USE SIGNAL ;
    PORT
      LAYER M5 ;
        RECT  25.68 86.208 25.704 86.4 ;
    END
  END rd[17]
  PIN rd[180]
    DIRECTION OUTPUT ;
    USE SIGNAL ;
    PORT
      LAYER M3 ;
        RECT  37.44 86.256 37.458 86.4 ;
    END
  END rd[180]
  PIN rd[181]
    DIRECTION OUTPUT ;
    USE SIGNAL ;
    PORT
      LAYER M5 ;
        RECT  37.488 86.208 37.512 86.4 ;
    END
  END rd[181]
  PIN rd[182]
    DIRECTION OUTPUT ;
    USE SIGNAL ;
    PORT
      LAYER M3 ;
        RECT  37.584 86.256 37.602 86.4 ;
    END
  END rd[182]
  PIN rd[183]
    DIRECTION OUTPUT ;
    USE SIGNAL ;
    PORT
      LAYER M5 ;
        RECT  37.632 86.208 37.656 86.4 ;
    END
  END rd[183]
  PIN rd[184]
    DIRECTION OUTPUT ;
    USE SIGNAL ;
    PORT
      LAYER M3 ;
        RECT  37.728 86.256 37.746 86.4 ;
    END
  END rd[184]
  PIN rd[185]
    DIRECTION OUTPUT ;
    USE SIGNAL ;
    PORT
      LAYER M5 ;
        RECT  37.776 86.208 37.8 86.4 ;
    END
  END rd[185]
  PIN rd[186]
    DIRECTION OUTPUT ;
    USE SIGNAL ;
    PORT
      LAYER M3 ;
        RECT  37.872 86.256 37.89 86.4 ;
    END
  END rd[186]
  PIN rd[187]
    DIRECTION OUTPUT ;
    USE SIGNAL ;
    PORT
      LAYER M5 ;
        RECT  37.92 86.208 37.944 86.4 ;
    END
  END rd[187]
  PIN rd[188]
    DIRECTION OUTPUT ;
    USE SIGNAL ;
    PORT
      LAYER M3 ;
        RECT  38.016 86.256 38.034 86.4 ;
    END
  END rd[188]
  PIN rd[189]
    DIRECTION OUTPUT ;
    USE SIGNAL ;
    PORT
      LAYER M5 ;
        RECT  38.064 86.208 38.088 86.4 ;
    END
  END rd[189]
  PIN rd[18]
    DIRECTION OUTPUT ;
    USE SIGNAL ;
    PORT
      LAYER M3 ;
        RECT  25.776 86.256 25.794 86.4 ;
    END
  END rd[18]
  PIN rd[190]
    DIRECTION OUTPUT ;
    USE SIGNAL ;
    PORT
      LAYER M3 ;
        RECT  38.16 86.256 38.178 86.4 ;
    END
  END rd[190]
  PIN rd[191]
    DIRECTION OUTPUT ;
    USE SIGNAL ;
    PORT
      LAYER M5 ;
        RECT  38.208 86.208 38.232 86.4 ;
    END
  END rd[191]
  PIN rd[192]
    DIRECTION OUTPUT ;
    USE SIGNAL ;
    PORT
      LAYER M3 ;
        RECT  38.304 86.256 38.322 86.4 ;
    END
  END rd[192]
  PIN rd[193]
    DIRECTION OUTPUT ;
    USE SIGNAL ;
    PORT
      LAYER M5 ;
        RECT  38.352 86.208 38.376 86.4 ;
    END
  END rd[193]
  PIN rd[194]
    DIRECTION OUTPUT ;
    USE SIGNAL ;
    PORT
      LAYER M3 ;
        RECT  38.448 86.256 38.466 86.4 ;
    END
  END rd[194]
  PIN rd[195]
    DIRECTION OUTPUT ;
    USE SIGNAL ;
    PORT
      LAYER M5 ;
        RECT  38.496 86.208 38.52 86.4 ;
    END
  END rd[195]
  PIN rd[196]
    DIRECTION OUTPUT ;
    USE SIGNAL ;
    PORT
      LAYER M3 ;
        RECT  38.592 86.256 38.61 86.4 ;
    END
  END rd[196]
  PIN rd[197]
    DIRECTION OUTPUT ;
    USE SIGNAL ;
    PORT
      LAYER M5 ;
        RECT  38.64 86.208 38.664 86.4 ;
    END
  END rd[197]
  PIN rd[198]
    DIRECTION OUTPUT ;
    USE SIGNAL ;
    PORT
      LAYER M3 ;
        RECT  38.736 86.256 38.754 86.4 ;
    END
  END rd[198]
  PIN rd[199]
    DIRECTION OUTPUT ;
    USE SIGNAL ;
    PORT
      LAYER M5 ;
        RECT  38.784 86.208 38.808 86.4 ;
    END
  END rd[199]
  PIN rd[19]
    DIRECTION OUTPUT ;
    USE SIGNAL ;
    PORT
      LAYER M5 ;
        RECT  25.824 86.208 25.848 86.4 ;
    END
  END rd[19]
  PIN rd[1]
    DIRECTION OUTPUT ;
    USE SIGNAL ;
    PORT
      LAYER M5 ;
        RECT  24.528 86.208 24.552 86.4 ;
    END
  END rd[1]
  PIN rd[200]
    DIRECTION OUTPUT ;
    USE SIGNAL ;
    PORT
      LAYER M3 ;
        RECT  38.88 86.256 38.898 86.4 ;
    END
  END rd[200]
  PIN rd[201]
    DIRECTION OUTPUT ;
    USE SIGNAL ;
    PORT
      LAYER M5 ;
        RECT  38.928 86.208 38.952 86.4 ;
    END
  END rd[201]
  PIN rd[202]
    DIRECTION OUTPUT ;
    USE SIGNAL ;
    PORT
      LAYER M3 ;
        RECT  39.024 86.256 39.042 86.4 ;
    END
  END rd[202]
  PIN rd[203]
    DIRECTION OUTPUT ;
    USE SIGNAL ;
    PORT
      LAYER M5 ;
        RECT  39.072 86.208 39.096 86.4 ;
    END
  END rd[203]
  PIN rd[204]
    DIRECTION OUTPUT ;
    USE SIGNAL ;
    PORT
      LAYER M3 ;
        RECT  39.168 86.256 39.186 86.4 ;
    END
  END rd[204]
  PIN rd[205]
    DIRECTION OUTPUT ;
    USE SIGNAL ;
    PORT
      LAYER M5 ;
        RECT  39.216 86.208 39.24 86.4 ;
    END
  END rd[205]
  PIN rd[206]
    DIRECTION OUTPUT ;
    USE SIGNAL ;
    PORT
      LAYER M3 ;
        RECT  39.312 86.256 39.33 86.4 ;
    END
  END rd[206]
  PIN rd[207]
    DIRECTION OUTPUT ;
    USE SIGNAL ;
    PORT
      LAYER M5 ;
        RECT  39.36 86.208 39.384 86.4 ;
    END
  END rd[207]
  PIN rd[208]
    DIRECTION OUTPUT ;
    USE SIGNAL ;
    PORT
      LAYER M3 ;
        RECT  39.456 86.256 39.474 86.4 ;
    END
  END rd[208]
  PIN rd[209]
    DIRECTION OUTPUT ;
    USE SIGNAL ;
    PORT
      LAYER M5 ;
        RECT  39.504 86.208 39.528 86.4 ;
    END
  END rd[209]
  PIN rd[20]
    DIRECTION OUTPUT ;
    USE SIGNAL ;
    PORT
      LAYER M3 ;
        RECT  25.92 86.256 25.938 86.4 ;
    END
  END rd[20]
  PIN rd[210]
    DIRECTION OUTPUT ;
    USE SIGNAL ;
    PORT
      LAYER M3 ;
        RECT  39.6 86.256 39.618 86.4 ;
    END
  END rd[210]
  PIN rd[211]
    DIRECTION OUTPUT ;
    USE SIGNAL ;
    PORT
      LAYER M5 ;
        RECT  39.648 86.208 39.672 86.4 ;
    END
  END rd[211]
  PIN rd[212]
    DIRECTION OUTPUT ;
    USE SIGNAL ;
    PORT
      LAYER M3 ;
        RECT  39.744 86.256 39.762 86.4 ;
    END
  END rd[212]
  PIN rd[213]
    DIRECTION OUTPUT ;
    USE SIGNAL ;
    PORT
      LAYER M5 ;
        RECT  39.792 86.208 39.816 86.4 ;
    END
  END rd[213]
  PIN rd[214]
    DIRECTION OUTPUT ;
    USE SIGNAL ;
    PORT
      LAYER M3 ;
        RECT  39.888 86.256 39.906 86.4 ;
    END
  END rd[214]
  PIN rd[215]
    DIRECTION OUTPUT ;
    USE SIGNAL ;
    PORT
      LAYER M5 ;
        RECT  39.936 86.208 39.96 86.4 ;
    END
  END rd[215]
  PIN rd[216]
    DIRECTION OUTPUT ;
    USE SIGNAL ;
    PORT
      LAYER M3 ;
        RECT  40.032 86.256 40.05 86.4 ;
    END
  END rd[216]
  PIN rd[217]
    DIRECTION OUTPUT ;
    USE SIGNAL ;
    PORT
      LAYER M5 ;
        RECT  40.08 86.208 40.104 86.4 ;
    END
  END rd[217]
  PIN rd[218]
    DIRECTION OUTPUT ;
    USE SIGNAL ;
    PORT
      LAYER M3 ;
        RECT  40.176 86.256 40.194 86.4 ;
    END
  END rd[218]
  PIN rd[219]
    DIRECTION OUTPUT ;
    USE SIGNAL ;
    PORT
      LAYER M5 ;
        RECT  40.224 86.208 40.248 86.4 ;
    END
  END rd[219]
  PIN rd[21]
    DIRECTION OUTPUT ;
    USE SIGNAL ;
    PORT
      LAYER M5 ;
        RECT  25.968 86.208 25.992 86.4 ;
    END
  END rd[21]
  PIN rd[220]
    DIRECTION OUTPUT ;
    USE SIGNAL ;
    PORT
      LAYER M3 ;
        RECT  40.32 86.256 40.338 86.4 ;
    END
  END rd[220]
  PIN rd[221]
    DIRECTION OUTPUT ;
    USE SIGNAL ;
    PORT
      LAYER M5 ;
        RECT  40.368 86.208 40.392 86.4 ;
    END
  END rd[221]
  PIN rd[222]
    DIRECTION OUTPUT ;
    USE SIGNAL ;
    PORT
      LAYER M3 ;
        RECT  40.464 86.256 40.482 86.4 ;
    END
  END rd[222]
  PIN rd[223]
    DIRECTION OUTPUT ;
    USE SIGNAL ;
    PORT
      LAYER M5 ;
        RECT  40.512 86.208 40.536 86.4 ;
    END
  END rd[223]
  PIN rd[224]
    DIRECTION OUTPUT ;
    USE SIGNAL ;
    PORT
      LAYER M3 ;
        RECT  40.608 86.256 40.626 86.4 ;
    END
  END rd[224]
  PIN rd[225]
    DIRECTION OUTPUT ;
    USE SIGNAL ;
    PORT
      LAYER M5 ;
        RECT  40.656 86.208 40.68 86.4 ;
    END
  END rd[225]
  PIN rd[226]
    DIRECTION OUTPUT ;
    USE SIGNAL ;
    PORT
      LAYER M3 ;
        RECT  40.752 86.256 40.77 86.4 ;
    END
  END rd[226]
  PIN rd[227]
    DIRECTION OUTPUT ;
    USE SIGNAL ;
    PORT
      LAYER M5 ;
        RECT  40.8 86.208 40.824 86.4 ;
    END
  END rd[227]
  PIN rd[228]
    DIRECTION OUTPUT ;
    USE SIGNAL ;
    PORT
      LAYER M3 ;
        RECT  40.896 86.256 40.914 86.4 ;
    END
  END rd[228]
  PIN rd[229]
    DIRECTION OUTPUT ;
    USE SIGNAL ;
    PORT
      LAYER M5 ;
        RECT  40.944 86.208 40.968 86.4 ;
    END
  END rd[229]
  PIN rd[22]
    DIRECTION OUTPUT ;
    USE SIGNAL ;
    PORT
      LAYER M3 ;
        RECT  26.064 86.256 26.082 86.4 ;
    END
  END rd[22]
  PIN rd[230]
    DIRECTION OUTPUT ;
    USE SIGNAL ;
    PORT
      LAYER M3 ;
        RECT  41.04 86.256 41.058 86.4 ;
    END
  END rd[230]
  PIN rd[231]
    DIRECTION OUTPUT ;
    USE SIGNAL ;
    PORT
      LAYER M5 ;
        RECT  41.088 86.208 41.112 86.4 ;
    END
  END rd[231]
  PIN rd[232]
    DIRECTION OUTPUT ;
    USE SIGNAL ;
    PORT
      LAYER M3 ;
        RECT  41.184 86.256 41.202 86.4 ;
    END
  END rd[232]
  PIN rd[233]
    DIRECTION OUTPUT ;
    USE SIGNAL ;
    PORT
      LAYER M5 ;
        RECT  41.232 86.208 41.256 86.4 ;
    END
  END rd[233]
  PIN rd[234]
    DIRECTION OUTPUT ;
    USE SIGNAL ;
    PORT
      LAYER M3 ;
        RECT  41.328 86.256 41.346 86.4 ;
    END
  END rd[234]
  PIN rd[235]
    DIRECTION OUTPUT ;
    USE SIGNAL ;
    PORT
      LAYER M5 ;
        RECT  41.376 86.208 41.4 86.4 ;
    END
  END rd[235]
  PIN rd[236]
    DIRECTION OUTPUT ;
    USE SIGNAL ;
    PORT
      LAYER M3 ;
        RECT  41.472 86.256 41.49 86.4 ;
    END
  END rd[236]
  PIN rd[237]
    DIRECTION OUTPUT ;
    USE SIGNAL ;
    PORT
      LAYER M5 ;
        RECT  41.52 86.208 41.544 86.4 ;
    END
  END rd[237]
  PIN rd[238]
    DIRECTION OUTPUT ;
    USE SIGNAL ;
    PORT
      LAYER M3 ;
        RECT  41.616 86.256 41.634 86.4 ;
    END
  END rd[238]
  PIN rd[239]
    DIRECTION OUTPUT ;
    USE SIGNAL ;
    PORT
      LAYER M5 ;
        RECT  41.664 86.208 41.688 86.4 ;
    END
  END rd[239]
  PIN rd[23]
    DIRECTION OUTPUT ;
    USE SIGNAL ;
    PORT
      LAYER M5 ;
        RECT  26.112 86.208 26.136 86.4 ;
    END
  END rd[23]
  PIN rd[240]
    DIRECTION OUTPUT ;
    USE SIGNAL ;
    PORT
      LAYER M3 ;
        RECT  41.76 86.256 41.778 86.4 ;
    END
  END rd[240]
  PIN rd[241]
    DIRECTION OUTPUT ;
    USE SIGNAL ;
    PORT
      LAYER M5 ;
        RECT  41.808 86.208 41.832 86.4 ;
    END
  END rd[241]
  PIN rd[242]
    DIRECTION OUTPUT ;
    USE SIGNAL ;
    PORT
      LAYER M3 ;
        RECT  41.904 86.256 41.922 86.4 ;
    END
  END rd[242]
  PIN rd[243]
    DIRECTION OUTPUT ;
    USE SIGNAL ;
    PORT
      LAYER M5 ;
        RECT  41.952 86.208 41.976 86.4 ;
    END
  END rd[243]
  PIN rd[244]
    DIRECTION OUTPUT ;
    USE SIGNAL ;
    PORT
      LAYER M3 ;
        RECT  42.048 86.256 42.066 86.4 ;
    END
  END rd[244]
  PIN rd[245]
    DIRECTION OUTPUT ;
    USE SIGNAL ;
    PORT
      LAYER M5 ;
        RECT  42.096 86.208 42.12 86.4 ;
    END
  END rd[245]
  PIN rd[246]
    DIRECTION OUTPUT ;
    USE SIGNAL ;
    PORT
      LAYER M3 ;
        RECT  42.192 86.256 42.21 86.4 ;
    END
  END rd[246]
  PIN rd[247]
    DIRECTION OUTPUT ;
    USE SIGNAL ;
    PORT
      LAYER M5 ;
        RECT  42.24 86.208 42.264 86.4 ;
    END
  END rd[247]
  PIN rd[248]
    DIRECTION OUTPUT ;
    USE SIGNAL ;
    PORT
      LAYER M3 ;
        RECT  42.336 86.256 42.354 86.4 ;
    END
  END rd[248]
  PIN rd[249]
    DIRECTION OUTPUT ;
    USE SIGNAL ;
    PORT
      LAYER M5 ;
        RECT  42.384 86.208 42.408 86.4 ;
    END
  END rd[249]
  PIN rd[24]
    DIRECTION OUTPUT ;
    USE SIGNAL ;
    PORT
      LAYER M3 ;
        RECT  26.208 86.256 26.226 86.4 ;
    END
  END rd[24]
  PIN rd[250]
    DIRECTION OUTPUT ;
    USE SIGNAL ;
    PORT
      LAYER M3 ;
        RECT  42.48 86.256 42.498 86.4 ;
    END
  END rd[250]
  PIN rd[251]
    DIRECTION OUTPUT ;
    USE SIGNAL ;
    PORT
      LAYER M5 ;
        RECT  42.528 86.208 42.552 86.4 ;
    END
  END rd[251]
  PIN rd[252]
    DIRECTION OUTPUT ;
    USE SIGNAL ;
    PORT
      LAYER M3 ;
        RECT  42.624 86.256 42.642 86.4 ;
    END
  END rd[252]
  PIN rd[253]
    DIRECTION OUTPUT ;
    USE SIGNAL ;
    PORT
      LAYER M5 ;
        RECT  42.672 86.208 42.696 86.4 ;
    END
  END rd[253]
  PIN rd[254]
    DIRECTION OUTPUT ;
    USE SIGNAL ;
    PORT
      LAYER M3 ;
        RECT  42.768 86.256 42.786 86.4 ;
    END
  END rd[254]
  PIN rd[255]
    DIRECTION OUTPUT ;
    USE SIGNAL ;
    PORT
      LAYER M5 ;
        RECT  42.816 86.208 42.84 86.4 ;
    END
  END rd[255]
  PIN rd[25]
    DIRECTION OUTPUT ;
    USE SIGNAL ;
    PORT
      LAYER M5 ;
        RECT  26.256 86.208 26.28 86.4 ;
    END
  END rd[25]
  PIN rd[26]
    DIRECTION OUTPUT ;
    USE SIGNAL ;
    PORT
      LAYER M3 ;
        RECT  26.352 86.256 26.37 86.4 ;
    END
  END rd[26]
  PIN rd[27]
    DIRECTION OUTPUT ;
    USE SIGNAL ;
    PORT
      LAYER M5 ;
        RECT  26.4 86.208 26.424 86.4 ;
    END
  END rd[27]
  PIN rd[28]
    DIRECTION OUTPUT ;
    USE SIGNAL ;
    PORT
      LAYER M3 ;
        RECT  26.496 86.256 26.514 86.4 ;
    END
  END rd[28]
  PIN rd[29]
    DIRECTION OUTPUT ;
    USE SIGNAL ;
    PORT
      LAYER M5 ;
        RECT  26.544 86.208 26.568 86.4 ;
    END
  END rd[29]
  PIN rd[2]
    DIRECTION OUTPUT ;
    USE SIGNAL ;
    PORT
      LAYER M3 ;
        RECT  24.624 86.256 24.642 86.4 ;
    END
  END rd[2]
  PIN rd[30]
    DIRECTION OUTPUT ;
    USE SIGNAL ;
    PORT
      LAYER M3 ;
        RECT  26.64 86.256 26.658 86.4 ;
    END
  END rd[30]
  PIN rd[31]
    DIRECTION OUTPUT ;
    USE SIGNAL ;
    PORT
      LAYER M5 ;
        RECT  26.688 86.208 26.712 86.4 ;
    END
  END rd[31]
  PIN rd[32]
    DIRECTION OUTPUT ;
    USE SIGNAL ;
    PORT
      LAYER M3 ;
        RECT  26.784 86.256 26.802 86.4 ;
    END
  END rd[32]
  PIN rd[33]
    DIRECTION OUTPUT ;
    USE SIGNAL ;
    PORT
      LAYER M5 ;
        RECT  26.832 86.208 26.856 86.4 ;
    END
  END rd[33]
  PIN rd[34]
    DIRECTION OUTPUT ;
    USE SIGNAL ;
    PORT
      LAYER M3 ;
        RECT  26.928 86.256 26.946 86.4 ;
    END
  END rd[34]
  PIN rd[35]
    DIRECTION OUTPUT ;
    USE SIGNAL ;
    PORT
      LAYER M5 ;
        RECT  26.976 86.208 27 86.4 ;
    END
  END rd[35]
  PIN rd[36]
    DIRECTION OUTPUT ;
    USE SIGNAL ;
    PORT
      LAYER M3 ;
        RECT  27.072 86.256 27.09 86.4 ;
    END
  END rd[36]
  PIN rd[37]
    DIRECTION OUTPUT ;
    USE SIGNAL ;
    PORT
      LAYER M5 ;
        RECT  27.12 86.208 27.144 86.4 ;
    END
  END rd[37]
  PIN rd[38]
    DIRECTION OUTPUT ;
    USE SIGNAL ;
    PORT
      LAYER M3 ;
        RECT  27.216 86.256 27.234 86.4 ;
    END
  END rd[38]
  PIN rd[39]
    DIRECTION OUTPUT ;
    USE SIGNAL ;
    PORT
      LAYER M5 ;
        RECT  27.264 86.208 27.288 86.4 ;
    END
  END rd[39]
  PIN rd[3]
    DIRECTION OUTPUT ;
    USE SIGNAL ;
    PORT
      LAYER M5 ;
        RECT  24.672 86.208 24.696 86.4 ;
    END
  END rd[3]
  PIN rd[40]
    DIRECTION OUTPUT ;
    USE SIGNAL ;
    PORT
      LAYER M3 ;
        RECT  27.36 86.256 27.378 86.4 ;
    END
  END rd[40]
  PIN rd[41]
    DIRECTION OUTPUT ;
    USE SIGNAL ;
    PORT
      LAYER M5 ;
        RECT  27.408 86.208 27.432 86.4 ;
    END
  END rd[41]
  PIN rd[42]
    DIRECTION OUTPUT ;
    USE SIGNAL ;
    PORT
      LAYER M3 ;
        RECT  27.504 86.256 27.522 86.4 ;
    END
  END rd[42]
  PIN rd[43]
    DIRECTION OUTPUT ;
    USE SIGNAL ;
    PORT
      LAYER M5 ;
        RECT  27.552 86.208 27.576 86.4 ;
    END
  END rd[43]
  PIN rd[44]
    DIRECTION OUTPUT ;
    USE SIGNAL ;
    PORT
      LAYER M3 ;
        RECT  27.648 86.256 27.666 86.4 ;
    END
  END rd[44]
  PIN rd[45]
    DIRECTION OUTPUT ;
    USE SIGNAL ;
    PORT
      LAYER M5 ;
        RECT  27.696 86.208 27.72 86.4 ;
    END
  END rd[45]
  PIN rd[46]
    DIRECTION OUTPUT ;
    USE SIGNAL ;
    PORT
      LAYER M3 ;
        RECT  27.792 86.256 27.81 86.4 ;
    END
  END rd[46]
  PIN rd[47]
    DIRECTION OUTPUT ;
    USE SIGNAL ;
    PORT
      LAYER M5 ;
        RECT  27.84 86.208 27.864 86.4 ;
    END
  END rd[47]
  PIN rd[48]
    DIRECTION OUTPUT ;
    USE SIGNAL ;
    PORT
      LAYER M3 ;
        RECT  27.936 86.256 27.954 86.4 ;
    END
  END rd[48]
  PIN rd[49]
    DIRECTION OUTPUT ;
    USE SIGNAL ;
    PORT
      LAYER M5 ;
        RECT  27.984 86.208 28.008 86.4 ;
    END
  END rd[49]
  PIN rd[4]
    DIRECTION OUTPUT ;
    USE SIGNAL ;
    PORT
      LAYER M3 ;
        RECT  24.768 86.256 24.786 86.4 ;
    END
  END rd[4]
  PIN rd[50]
    DIRECTION OUTPUT ;
    USE SIGNAL ;
    PORT
      LAYER M3 ;
        RECT  28.08 86.256 28.098 86.4 ;
    END
  END rd[50]
  PIN rd[51]
    DIRECTION OUTPUT ;
    USE SIGNAL ;
    PORT
      LAYER M5 ;
        RECT  28.128 86.208 28.152 86.4 ;
    END
  END rd[51]
  PIN rd[52]
    DIRECTION OUTPUT ;
    USE SIGNAL ;
    PORT
      LAYER M3 ;
        RECT  28.224 86.256 28.242 86.4 ;
    END
  END rd[52]
  PIN rd[53]
    DIRECTION OUTPUT ;
    USE SIGNAL ;
    PORT
      LAYER M5 ;
        RECT  28.272 86.208 28.296 86.4 ;
    END
  END rd[53]
  PIN rd[54]
    DIRECTION OUTPUT ;
    USE SIGNAL ;
    PORT
      LAYER M3 ;
        RECT  28.368 86.256 28.386 86.4 ;
    END
  END rd[54]
  PIN rd[55]
    DIRECTION OUTPUT ;
    USE SIGNAL ;
    PORT
      LAYER M5 ;
        RECT  28.416 86.208 28.44 86.4 ;
    END
  END rd[55]
  PIN rd[56]
    DIRECTION OUTPUT ;
    USE SIGNAL ;
    PORT
      LAYER M3 ;
        RECT  28.512 86.256 28.53 86.4 ;
    END
  END rd[56]
  PIN rd[57]
    DIRECTION OUTPUT ;
    USE SIGNAL ;
    PORT
      LAYER M5 ;
        RECT  28.56 86.208 28.584 86.4 ;
    END
  END rd[57]
  PIN rd[58]
    DIRECTION OUTPUT ;
    USE SIGNAL ;
    PORT
      LAYER M3 ;
        RECT  28.656 86.256 28.674 86.4 ;
    END
  END rd[58]
  PIN rd[59]
    DIRECTION OUTPUT ;
    USE SIGNAL ;
    PORT
      LAYER M5 ;
        RECT  28.704 86.208 28.728 86.4 ;
    END
  END rd[59]
  PIN rd[5]
    DIRECTION OUTPUT ;
    USE SIGNAL ;
    PORT
      LAYER M5 ;
        RECT  24.816 86.208 24.84 86.4 ;
    END
  END rd[5]
  PIN rd[60]
    DIRECTION OUTPUT ;
    USE SIGNAL ;
    PORT
      LAYER M3 ;
        RECT  28.8 86.256 28.818 86.4 ;
    END
  END rd[60]
  PIN rd[61]
    DIRECTION OUTPUT ;
    USE SIGNAL ;
    PORT
      LAYER M5 ;
        RECT  28.848 86.208 28.872 86.4 ;
    END
  END rd[61]
  PIN rd[62]
    DIRECTION OUTPUT ;
    USE SIGNAL ;
    PORT
      LAYER M3 ;
        RECT  28.944 86.256 28.962 86.4 ;
    END
  END rd[62]
  PIN rd[63]
    DIRECTION OUTPUT ;
    USE SIGNAL ;
    PORT
      LAYER M5 ;
        RECT  28.992 86.208 29.016 86.4 ;
    END
  END rd[63]
  PIN rd[64]
    DIRECTION OUTPUT ;
    USE SIGNAL ;
    PORT
      LAYER M3 ;
        RECT  29.088 86.256 29.106 86.4 ;
    END
  END rd[64]
  PIN rd[65]
    DIRECTION OUTPUT ;
    USE SIGNAL ;
    PORT
      LAYER M5 ;
        RECT  29.136 86.208 29.16 86.4 ;
    END
  END rd[65]
  PIN rd[66]
    DIRECTION OUTPUT ;
    USE SIGNAL ;
    PORT
      LAYER M3 ;
        RECT  29.232 86.256 29.25 86.4 ;
    END
  END rd[66]
  PIN rd[67]
    DIRECTION OUTPUT ;
    USE SIGNAL ;
    PORT
      LAYER M5 ;
        RECT  29.28 86.208 29.304 86.4 ;
    END
  END rd[67]
  PIN rd[68]
    DIRECTION OUTPUT ;
    USE SIGNAL ;
    PORT
      LAYER M3 ;
        RECT  29.376 86.256 29.394 86.4 ;
    END
  END rd[68]
  PIN rd[69]
    DIRECTION OUTPUT ;
    USE SIGNAL ;
    PORT
      LAYER M5 ;
        RECT  29.424 86.208 29.448 86.4 ;
    END
  END rd[69]
  PIN rd[6]
    DIRECTION OUTPUT ;
    USE SIGNAL ;
    PORT
      LAYER M3 ;
        RECT  24.912 86.256 24.93 86.4 ;
    END
  END rd[6]
  PIN rd[70]
    DIRECTION OUTPUT ;
    USE SIGNAL ;
    PORT
      LAYER M3 ;
        RECT  29.52 86.256 29.538 86.4 ;
    END
  END rd[70]
  PIN rd[71]
    DIRECTION OUTPUT ;
    USE SIGNAL ;
    PORT
      LAYER M5 ;
        RECT  29.568 86.208 29.592 86.4 ;
    END
  END rd[71]
  PIN rd[72]
    DIRECTION OUTPUT ;
    USE SIGNAL ;
    PORT
      LAYER M3 ;
        RECT  29.664 86.256 29.682 86.4 ;
    END
  END rd[72]
  PIN rd[73]
    DIRECTION OUTPUT ;
    USE SIGNAL ;
    PORT
      LAYER M5 ;
        RECT  29.712 86.208 29.736 86.4 ;
    END
  END rd[73]
  PIN rd[74]
    DIRECTION OUTPUT ;
    USE SIGNAL ;
    PORT
      LAYER M3 ;
        RECT  29.808 86.256 29.826 86.4 ;
    END
  END rd[74]
  PIN rd[75]
    DIRECTION OUTPUT ;
    USE SIGNAL ;
    PORT
      LAYER M5 ;
        RECT  29.856 86.208 29.88 86.4 ;
    END
  END rd[75]
  PIN rd[76]
    DIRECTION OUTPUT ;
    USE SIGNAL ;
    PORT
      LAYER M3 ;
        RECT  29.952 86.256 29.97 86.4 ;
    END
  END rd[76]
  PIN rd[77]
    DIRECTION OUTPUT ;
    USE SIGNAL ;
    PORT
      LAYER M5 ;
        RECT  30 86.208 30.024 86.4 ;
    END
  END rd[77]
  PIN rd[78]
    DIRECTION OUTPUT ;
    USE SIGNAL ;
    PORT
      LAYER M3 ;
        RECT  30.096 86.256 30.114 86.4 ;
    END
  END rd[78]
  PIN rd[79]
    DIRECTION OUTPUT ;
    USE SIGNAL ;
    PORT
      LAYER M5 ;
        RECT  30.144 86.208 30.168 86.4 ;
    END
  END rd[79]
  PIN rd[7]
    DIRECTION OUTPUT ;
    USE SIGNAL ;
    PORT
      LAYER M5 ;
        RECT  24.96 86.208 24.984 86.4 ;
    END
  END rd[7]
  PIN rd[80]
    DIRECTION OUTPUT ;
    USE SIGNAL ;
    PORT
      LAYER M3 ;
        RECT  30.24 86.256 30.258 86.4 ;
    END
  END rd[80]
  PIN rd[81]
    DIRECTION OUTPUT ;
    USE SIGNAL ;
    PORT
      LAYER M5 ;
        RECT  30.288 86.208 30.312 86.4 ;
    END
  END rd[81]
  PIN rd[82]
    DIRECTION OUTPUT ;
    USE SIGNAL ;
    PORT
      LAYER M3 ;
        RECT  30.384 86.256 30.402 86.4 ;
    END
  END rd[82]
  PIN rd[83]
    DIRECTION OUTPUT ;
    USE SIGNAL ;
    PORT
      LAYER M5 ;
        RECT  30.432 86.208 30.456 86.4 ;
    END
  END rd[83]
  PIN rd[84]
    DIRECTION OUTPUT ;
    USE SIGNAL ;
    PORT
      LAYER M3 ;
        RECT  30.528 86.256 30.546 86.4 ;
    END
  END rd[84]
  PIN rd[85]
    DIRECTION OUTPUT ;
    USE SIGNAL ;
    PORT
      LAYER M5 ;
        RECT  30.576 86.208 30.6 86.4 ;
    END
  END rd[85]
  PIN rd[86]
    DIRECTION OUTPUT ;
    USE SIGNAL ;
    PORT
      LAYER M3 ;
        RECT  30.672 86.256 30.69 86.4 ;
    END
  END rd[86]
  PIN rd[87]
    DIRECTION OUTPUT ;
    USE SIGNAL ;
    PORT
      LAYER M5 ;
        RECT  30.72 86.208 30.744 86.4 ;
    END
  END rd[87]
  PIN rd[88]
    DIRECTION OUTPUT ;
    USE SIGNAL ;
    PORT
      LAYER M3 ;
        RECT  30.816 86.256 30.834 86.4 ;
    END
  END rd[88]
  PIN rd[89]
    DIRECTION OUTPUT ;
    USE SIGNAL ;
    PORT
      LAYER M5 ;
        RECT  30.864 86.208 30.888 86.4 ;
    END
  END rd[89]
  PIN rd[8]
    DIRECTION OUTPUT ;
    USE SIGNAL ;
    PORT
      LAYER M3 ;
        RECT  25.056 86.256 25.074 86.4 ;
    END
  END rd[8]
  PIN rd[90]
    DIRECTION OUTPUT ;
    USE SIGNAL ;
    PORT
      LAYER M3 ;
        RECT  30.96 86.256 30.978 86.4 ;
    END
  END rd[90]
  PIN rd[91]
    DIRECTION OUTPUT ;
    USE SIGNAL ;
    PORT
      LAYER M5 ;
        RECT  31.008 86.208 31.032 86.4 ;
    END
  END rd[91]
  PIN rd[92]
    DIRECTION OUTPUT ;
    USE SIGNAL ;
    PORT
      LAYER M3 ;
        RECT  31.104 86.256 31.122 86.4 ;
    END
  END rd[92]
  PIN rd[93]
    DIRECTION OUTPUT ;
    USE SIGNAL ;
    PORT
      LAYER M5 ;
        RECT  31.152 86.208 31.176 86.4 ;
    END
  END rd[93]
  PIN rd[94]
    DIRECTION OUTPUT ;
    USE SIGNAL ;
    PORT
      LAYER M3 ;
        RECT  31.248 86.256 31.266 86.4 ;
    END
  END rd[94]
  PIN rd[95]
    DIRECTION OUTPUT ;
    USE SIGNAL ;
    PORT
      LAYER M5 ;
        RECT  31.296 86.208 31.32 86.4 ;
    END
  END rd[95]
  PIN rd[96]
    DIRECTION OUTPUT ;
    USE SIGNAL ;
    PORT
      LAYER M3 ;
        RECT  31.392 86.256 31.41 86.4 ;
    END
  END rd[96]
  PIN rd[97]
    DIRECTION OUTPUT ;
    USE SIGNAL ;
    PORT
      LAYER M5 ;
        RECT  31.44 86.208 31.464 86.4 ;
    END
  END rd[97]
  PIN rd[98]
    DIRECTION OUTPUT ;
    USE SIGNAL ;
    PORT
      LAYER M3 ;
        RECT  31.536 86.256 31.554 86.4 ;
    END
  END rd[98]
  PIN rd[99]
    DIRECTION OUTPUT ;
    USE SIGNAL ;
    PORT
      LAYER M5 ;
        RECT  31.584 86.208 31.608 86.4 ;
    END
  END rd[99]
  PIN rd[9]
    DIRECTION OUTPUT ;
    USE SIGNAL ;
    PORT
      LAYER M5 ;
        RECT  25.104 86.208 25.128 86.4 ;
    END
  END rd[9]
  PIN rq0
    DIRECTION INPUT ;
    USE SIGNAL ;
    PORT
      LAYER M4 ;
        RECT  0 38.736 0.192 38.76 ;
    END
  END rq0
  PIN rq1
    DIRECTION INPUT ;
    USE SIGNAL ;
    PORT
      LAYER M4 ;
        RECT  0 38.592 0.192 38.616 ;
    END
  END rq1
  PIN rst_n
    DIRECTION INPUT ;
    USE SIGNAL ;
    PORT
      LAYER M4 ;
        RECT  0 51.024 0.192 51.048 ;
    END
    PORT
      LAYER M4 ;
        RECT  0.156 51.024 2.408 51.048 ;
    END
  END rst_n
  PIN w0[0]
    DIRECTION INPUT ;
    USE SIGNAL ;
    PORT
      LAYER M4 ;
        RECT  0 38.88 0.192 38.904 ;
    END
  END w0[0]
  PIN w0[1]
    DIRECTION INPUT ;
    USE SIGNAL ;
    PORT
      LAYER M4 ;
        RECT  0 39.024 0.192 39.048 ;
    END
  END w0[1]
  PIN w0[2]
    DIRECTION INPUT ;
    USE SIGNAL ;
    PORT
      LAYER M4 ;
        RECT  0 39.168 0.192 39.192 ;
    END
  END w0[2]
  PIN w0[3]
    DIRECTION INPUT ;
    USE SIGNAL ;
    PORT
      LAYER M4 ;
        RECT  0 39.312 0.192 39.336 ;
    END
  END w0[3]
  PIN w0[4]
    DIRECTION INPUT ;
    USE SIGNAL ;
    PORT
      LAYER M4 ;
        RECT  0 39.456 0.192 39.48 ;
    END
  END w0[4]
  PIN w0[5]
    DIRECTION INPUT ;
    USE SIGNAL ;
    PORT
      LAYER M4 ;
        RECT  0 39.6 0.192 39.624 ;
    END
  END w0[5]
  PIN w0[6]
    DIRECTION INPUT ;
    USE SIGNAL ;
    PORT
      LAYER M4 ;
        RECT  0 39.744 0.192 39.768 ;
    END
  END w0[6]
  PIN w0[7]
    DIRECTION INPUT ;
    USE SIGNAL ;
    PORT
      LAYER M4 ;
        RECT  0 39.888 0.192 39.912 ;
    END
  END w0[7]
  PIN w0[8]
    DIRECTION INPUT ;
    USE SIGNAL ;
    PORT
      LAYER M4 ;
        RECT  0 40.032 0.192 40.056 ;
    END
  END w0[8]
  PIN w1[0]
    DIRECTION INPUT ;
    USE SIGNAL ;
    PORT
      LAYER M4 ;
        RECT  0 40.176 0.192 40.2 ;
    END
  END w1[0]
  PIN w1[1]
    DIRECTION INPUT ;
    USE SIGNAL ;
    PORT
      LAYER M4 ;
        RECT  0 40.32 0.192 40.344 ;
    END
  END w1[1]
  PIN w1[2]
    DIRECTION INPUT ;
    USE SIGNAL ;
    PORT
      LAYER M4 ;
        RECT  0 40.464 0.192 40.488 ;
    END
  END w1[2]
  PIN w1[3]
    DIRECTION INPUT ;
    USE SIGNAL ;
    PORT
      LAYER M4 ;
        RECT  0 40.608 0.192 40.632 ;
    END
  END w1[3]
  PIN w1[4]
    DIRECTION INPUT ;
    USE SIGNAL ;
    PORT
      LAYER M4 ;
        RECT  0 40.752 0.192 40.776 ;
    END
  END w1[4]
  PIN w1[5]
    DIRECTION INPUT ;
    USE SIGNAL ;
    PORT
      LAYER M4 ;
        RECT  0 40.896 0.192 40.92 ;
    END
  END w1[5]
  PIN w1[6]
    DIRECTION INPUT ;
    USE SIGNAL ;
    PORT
      LAYER M4 ;
        RECT  0 41.04 0.192 41.064 ;
    END
  END w1[6]
  PIN w1[7]
    DIRECTION INPUT ;
    USE SIGNAL ;
    PORT
      LAYER M4 ;
        RECT  0 41.184 0.192 41.208 ;
    END
  END w1[7]
  PIN w1[8]
    DIRECTION INPUT ;
    USE SIGNAL ;
    PORT
      LAYER M4 ;
        RECT  0 41.328 0.192 41.352 ;
    END
  END w1[8]
  PIN wv
    DIRECTION INPUT ;
    USE SIGNAL ;
    PORT
      LAYER M4 ;
        RECT  0 41.472 0.192 41.496 ;
    END
  END wv
  PIN VDD
    DIRECTION INOUT ;
    USE POWER ;
    PORT
      LAYER M5 ;
        RECT  137.592 2.151 137.712 84.249 ;
        RECT  132.192 2.151 132.312 84.249 ;
        RECT  126.792 2.151 126.912 84.249 ;
        RECT  121.392 2.151 121.512 84.249 ;
        RECT  115.992 2.151 116.112 84.249 ;
        RECT  110.592 2.151 110.712 84.249 ;
        RECT  105.192 2.151 105.312 84.249 ;
        RECT  99.792 2.151 99.912 84.249 ;
        RECT  94.392 2.151 94.512 84.249 ;
        RECT  88.992 2.151 89.112 84.249 ;
        RECT  83.592 2.151 83.712 84.249 ;
        RECT  78.192 2.151 78.312 84.249 ;
        RECT  72.792 2.151 72.912 84.249 ;
        RECT  67.392 2.151 67.512 84.249 ;
        RECT  61.992 2.151 62.112 84.249 ;
        RECT  56.592 2.151 56.712 84.249 ;
        RECT  51.192 2.151 51.312 84.249 ;
        RECT  45.792 2.151 45.912 84.249 ;
        RECT  40.392 2.151 40.512 84.249 ;
        RECT  34.992 2.151 35.112 84.249 ;
        RECT  29.592 2.151 29.712 84.249 ;
        RECT  24.192 2.151 24.312 84.249 ;
        RECT  18.792 2.151 18.912 84.249 ;
        RECT  13.392 2.151 13.512 84.249 ;
        RECT  7.992 2.151 8.112 84.249 ;
        RECT  2.592 2.151 2.712 84.249 ;
    END
  END VDD
  PIN VSS
    DIRECTION INOUT ;
    USE GROUND ;
    PORT
      LAYER M5 ;
        RECT  137.4 2.137 137.52 84.263 ;
        RECT  132 2.137 132.12 84.263 ;
        RECT  126.6 2.137 126.72 84.263 ;
        RECT  121.2 2.137 121.32 84.263 ;
        RECT  115.8 2.137 115.92 84.263 ;
        RECT  110.4 2.137 110.52 84.263 ;
        RECT  105 2.137 105.12 84.263 ;
        RECT  99.6 2.137 99.72 84.263 ;
        RECT  94.2 2.137 94.32 84.263 ;
        RECT  88.8 2.137 88.92 84.263 ;
        RECT  83.4 2.137 83.52 84.263 ;
        RECT  78 2.137 78.12 84.263 ;
        RECT  72.6 2.137 72.72 84.263 ;
        RECT  67.2 2.137 67.32 84.263 ;
        RECT  61.8 2.137 61.92 84.263 ;
        RECT  56.4 2.137 56.52 84.263 ;
        RECT  51 2.137 51.12 84.263 ;
        RECT  45.6 2.137 45.72 84.263 ;
        RECT  40.2 2.137 40.32 84.263 ;
        RECT  34.8 2.137 34.92 84.263 ;
        RECT  29.4 2.137 29.52 84.263 ;
        RECT  24 2.137 24.12 84.263 ;
        RECT  18.6 2.137 18.72 84.263 ;
        RECT  13.2 2.137 13.32 84.263 ;
        RECT  7.8 2.137 7.92 84.263 ;
        RECT  2.4 2.137 2.52 84.263 ;
    END
  END VSS
  # OT_OBS_CLOSED layer=M5 d_um=1.536 added=336
  OBS
    LAYER LVTN ;
     RECT  12.906 4.725 18.954 4.86 ;
     RECT  13.068 4.86 13.608 4.995 ;
     RECT  71.874 7.965 72.468 8.1 ;
     RECT  88.398 7.965 90.072 8.1 ;
     RECT  90.558 7.965 92.232 8.1 ;
     RECT  99.576 7.965 100.116 8.1 ;
     RECT  82.188 8.1 83.862 8.235 ;
     RECT  99.846 8.1 100.494 8.235 ;
     RECT  72.306 8.505 72.684 8.64 ;
     RECT  100.872 8.64 101.358 8.775 ;
     RECT  105.138 8.64 106.11 8.775 ;
     RECT  72.144 9.045 73.764 9.18 ;
     RECT  79.974 9.045 80.622 9.18 ;
     RECT  90.828 9.18 91.692 9.315 ;
     RECT  103.95 9.585 105.408 9.72 ;
     RECT  7.56 10.26 8.532 10.395 ;
     RECT  105.354 10.26 106.164 10.395 ;
     RECT  72.252 10.665 73.008 10.8 ;
     RECT  77.76 10.665 79.218 10.8 ;
     RECT  104.436 10.665 105.57 10.8 ;
     RECT  81.702 11.205 82.026 11.34 ;
     RECT  105.894 12.285 106.38 12.42 ;
     RECT  77.274 12.825 77.706 12.96 ;
     RECT  90.882 12.825 91.692 12.96 ;
     RECT  105.516 12.825 106.65 12.96 ;
     RECT  48.924 12.96 50.004 13.095 ;
     RECT  81.648 12.96 81.972 13.095 ;
     RECT  75.06 13.365 77.058 13.5 ;
     RECT  58.644 14.04 60.858 14.175 ;
     RECT  57.726 14.58 58.266 14.715 ;
     RECT  69.66 14.58 70.686 14.715 ;
     RECT  81.054 15.12 81.54 15.255 ;
     RECT  81.756 15.66 82.188 15.795 ;
     RECT  79.812 16.2 80.244 16.335 ;
     RECT  33.588 16.605 34.29 16.74 ;
     RECT  65.988 16.74 67.176 16.875 ;
     RECT  81.432 16.74 82.242 16.875 ;
     RECT  45.9 17.28 46.602 17.415 ;
     RECT  101.196 17.28 101.574 17.415 ;
     RECT  105.948 17.28 107.622 17.415 ;
     RECT  43.848 17.685 44.172 17.82 ;
     RECT  61.182 17.685 62.37 17.82 ;
     RECT  99.522 17.685 100.008 17.82 ;
     RECT  64.314 17.82 66.042 17.955 ;
     RECT  66.69 17.82 67.122 17.955 ;
     RECT  68.31 17.82 68.904 17.955 ;
     RECT  64.692 18.225 65.07 18.36 ;
     RECT  80.082 18.225 80.514 18.36 ;
     RECT  36.558 18.36 37.53 18.495 ;
     RECT  65.394 18.36 65.934 18.495 ;
     RECT  77.922 18.36 79.434 18.495 ;
     RECT  37.584 18.765 38.772 18.9 ;
     RECT  66.204 18.765 74.466 18.9 ;
     RECT  80.568 18.765 83.592 18.9 ;
     RECT  10.692 18.9 12.258 19.035 ;
     RECT  14.796 18.9 15.336 19.035 ;
     RECT  31.59 18.9 33.048 19.035 ;
     RECT  33.696 18.9 35.1 19.035 ;
     RECT  36.45 18.9 38.718 19.035 ;
     RECT  39.042 18.9 40.014 19.035 ;
     RECT  47.304 18.9 48.114 19.035 ;
     RECT  31.374 19.305 32.454 19.44 ;
     RECT  33.534 19.305 35.91 19.44 ;
     RECT  41.742 19.305 42.714 19.44 ;
     RECT  48.654 19.305 49.464 19.44 ;
     RECT  77.706 19.305 79.002 19.44 ;
     RECT  22.788 19.44 24.462 19.575 ;
     RECT  31.374 19.44 33.588 19.575 ;
     RECT  34.776 19.44 36.882 19.575 ;
     RECT  39.528 19.44 40.068 19.575 ;
     RECT  46.116 19.44 47.358 19.575 ;
     RECT  48.114 19.44 48.762 19.575 ;
     RECT  49.41 19.44 51.192 19.575 ;
     RECT  52.812 19.44 54.108 19.575 ;
     RECT  77.112 19.44 77.868 19.575 ;
     RECT  29.646 19.845 30.834 19.98 ;
     RECT  44.28 19.845 45.468 19.98 ;
     RECT  35.532 19.98 37.368 20.115 ;
     RECT  7.938 22.14 8.802 22.275 ;
     RECT  7.992 23.085 8.37 23.22 ;
     RECT  7.452 23.625 7.884 23.76 ;
     RECT  15.552 24.165 18.522 24.3 ;
     RECT  13.446 25.92 14.526 26.055 ;
     RECT  13.5 26.325 14.04 26.46 ;
     RECT  10.854 28.62 11.718 28.755 ;
     RECT  15.876 28.62 18.954 28.755 ;
     RECT  2.754 29.565 4.05 29.7 ;
     RECT  6.912 30.24 8.154 30.375 ;
     RECT  14.688 31.32 16.362 31.455 ;
     RECT  15.606 31.725 16.632 31.86 ;
     RECT  2.754 31.86 3.726 31.995 ;
     RECT  14.418 31.86 15.12 31.995 ;
     RECT  3.834 32.4 5.562 32.535 ;
     RECT  13.878 32.4 14.58 32.535 ;
     RECT  2.268 32.805 3.24 32.94 ;
     RECT  12.15 32.805 13.176 32.94 ;
     RECT  10.26 33.48 10.962 33.615 ;
     RECT  2.268 33.885 4.104 34.02 ;
     RECT  4.428 33.885 5.994 34.02 ;
     RECT  17.28 33.885 17.928 34.02 ;
     RECT  2.862 34.425 3.51 34.56 ;
     RECT  2.97 34.965 4.05 35.1 ;
     RECT  2.268 35.1 3.456 35.235 ;
     RECT  3.672 35.505 5.022 35.64 ;
     RECT  9.504 35.505 10.638 35.64 ;
     RECT  2.538 36.045 3.51 36.18 ;
     RECT  2.322 36.18 3.294 36.315 ;
     RECT  19.17 37.8 20.304 37.935 ;
     RECT  2.862 38.745 4.968 38.88 ;
     RECT  3.294 39.285 7.506 39.42 ;
     RECT  17.928 41.445 20.304 41.58 ;
     RECT  6.966 46.44 9.504 46.575 ;
     RECT  13.878 50.625 14.58 50.76 ;
     RECT  15.282 50.625 16.47 50.76 ;
     RECT  15.768 52.785 16.146 52.92 ;
     RECT  19.656 54.405 20.304 54.54 ;
     RECT  9.45 56.16 9.774 56.295 ;
     RECT  10.152 57.105 11.286 57.24 ;
     RECT  13.662 57.105 14.634 57.24 ;
     RECT  17.766 59.94 18.36 60.075 ;
     RECT  10.314 63.045 10.746 63.18 ;
     RECT  7.398 63.72 8.748 63.855 ;
     RECT  14.904 63.72 15.228 63.855 ;
     RECT  7.56 64.665 8.046 64.8 ;
     RECT  16.416 64.665 17.442 64.8 ;
     RECT  46.872 65.745 47.358 65.88 ;
     RECT  29.052 65.88 31.536 66.015 ;
     RECT  40.662 65.88 41.256 66.015 ;
     RECT  47.25 66.285 49.086 66.42 ;
     RECT  12.042 66.96 12.366 67.095 ;
     RECT  11.07 67.905 12.906 68.04 ;
     RECT  36.99 68.58 38.07 68.715 ;
     RECT  40.986 68.985 42.012 69.12 ;
     RECT  49.302 68.985 52.056 69.12 ;
     RECT  29.808 69.66 30.348 69.795 ;
     RECT  45.252 71.28 46.44 71.415 ;
     RECT  34.776 72.36 35.802 72.495 ;
     RECT  45.198 72.36 45.576 72.495 ;
     RECT  34.722 72.765 36.072 72.9 ;
     RECT  45.036 75.06 45.738 75.195 ;
    LAYER LVTP ;
     RECT  12.906 4.59 18.954 4.725 ;
     RECT  13.068 4.995 13.608 5.13 ;
     RECT  71.874 7.83 72.468 7.965 ;
     RECT  88.398 7.83 90.072 7.965 ;
     RECT  90.558 7.83 92.232 7.965 ;
     RECT  99.576 7.83 100.116 7.965 ;
     RECT  82.188 8.235 83.862 8.37 ;
     RECT  99.846 8.235 100.494 8.37 ;
     RECT  72.306 8.37 72.684 8.505 ;
     RECT  100.872 8.775 101.358 8.91 ;
     RECT  105.138 8.775 106.11 8.91 ;
     RECT  72.144 8.91 73.764 9.045 ;
     RECT  79.974 8.91 80.622 9.045 ;
     RECT  90.828 9.315 91.692 9.45 ;
     RECT  103.95 9.45 105.408 9.585 ;
     RECT  7.56 10.395 8.532 10.53 ;
     RECT  105.354 10.395 106.164 10.53 ;
     RECT  72.252 10.53 73.008 10.665 ;
     RECT  77.76 10.53 79.218 10.665 ;
     RECT  104.436 10.53 105.57 10.665 ;
     RECT  81.702 11.07 82.026 11.205 ;
     RECT  105.894 12.15 106.38 12.285 ;
     RECT  77.274 12.69 77.706 12.825 ;
     RECT  90.882 12.69 91.692 12.825 ;
     RECT  105.516 12.69 106.65 12.825 ;
     RECT  48.924 13.095 50.004 13.23 ;
     RECT  81.648 13.095 81.972 13.23 ;
     RECT  75.06 13.23 77.058 13.365 ;
     RECT  58.644 14.175 60.858 14.31 ;
     RECT  57.726 14.715 58.266 14.85 ;
     RECT  69.66 14.715 70.686 14.85 ;
     RECT  81.054 15.255 81.54 15.39 ;
     RECT  81.756 15.795 82.188 15.93 ;
     RECT  79.812 16.335 80.244 16.47 ;
     RECT  33.588 16.47 34.29 16.605 ;
     RECT  65.988 16.875 67.176 17.01 ;
     RECT  81.432 16.875 82.242 17.01 ;
     RECT  45.9 17.415 46.602 17.55 ;
     RECT  101.196 17.415 101.574 17.55 ;
     RECT  105.948 17.415 107.622 17.55 ;
     RECT  43.848 17.55 44.172 17.685 ;
     RECT  61.182 17.55 62.37 17.685 ;
     RECT  99.522 17.55 100.008 17.685 ;
     RECT  64.314 17.955 66.042 18.09 ;
     RECT  66.69 17.955 67.122 18.09 ;
     RECT  68.31 17.955 68.904 18.09 ;
     RECT  64.692 18.09 65.07 18.225 ;
     RECT  80.082 18.09 80.514 18.225 ;
     RECT  36.558 18.495 37.53 18.63 ;
     RECT  65.394 18.495 65.934 18.63 ;
     RECT  77.922 18.495 79.434 18.63 ;
     RECT  37.584 18.63 38.772 18.765 ;
     RECT  66.204 18.63 74.466 18.765 ;
     RECT  80.568 18.63 83.592 18.765 ;
     RECT  10.692 19.035 12.258 19.17 ;
     RECT  14.796 19.035 15.336 19.17 ;
     RECT  31.59 19.035 33.048 19.17 ;
     RECT  33.696 19.035 35.1 19.17 ;
     RECT  36.45 19.035 38.718 19.17 ;
     RECT  39.042 19.035 40.014 19.17 ;
     RECT  47.304 19.035 48.114 19.17 ;
     RECT  31.374 19.17 32.454 19.305 ;
     RECT  33.534 19.17 35.91 19.305 ;
     RECT  41.742 19.17 42.714 19.305 ;
     RECT  48.654 19.17 49.464 19.305 ;
     RECT  77.706 19.17 79.002 19.305 ;
     RECT  22.788 19.575 24.462 19.71 ;
     RECT  31.374 19.575 33.588 19.71 ;
     RECT  34.776 19.575 36.882 19.71 ;
     RECT  39.528 19.575 40.068 19.71 ;
     RECT  46.116 19.575 47.358 19.71 ;
     RECT  48.114 19.575 48.762 19.71 ;
     RECT  49.41 19.575 51.192 19.71 ;
     RECT  52.812 19.575 54.108 19.71 ;
     RECT  77.112 19.575 77.868 19.71 ;
     RECT  29.646 19.71 30.834 19.845 ;
     RECT  44.28 19.71 45.468 19.845 ;
     RECT  35.532 20.115 37.368 20.25 ;
     RECT  7.938 22.275 8.802 22.41 ;
     RECT  7.992 22.95 8.37 23.085 ;
     RECT  7.452 23.49 7.884 23.625 ;
     RECT  15.552 24.03 18.522 24.165 ;
     RECT  13.446 26.055 14.526 26.19 ;
     RECT  13.5 26.19 14.04 26.325 ;
     RECT  10.854 28.755 11.718 28.89 ;
     RECT  15.876 28.755 18.954 28.89 ;
     RECT  2.754 29.43 4.05 29.565 ;
     RECT  6.912 30.375 8.154 30.51 ;
     RECT  14.688 31.455 16.362 31.59 ;
     RECT  15.606 31.59 16.632 31.725 ;
     RECT  2.754 31.995 3.726 32.13 ;
     RECT  14.418 31.995 15.12 32.13 ;
     RECT  3.834 32.535 5.562 32.67 ;
     RECT  13.878 32.535 14.58 32.67 ;
     RECT  2.268 32.67 3.24 32.805 ;
     RECT  12.15 32.67 13.176 32.805 ;
     RECT  10.26 33.615 10.962 33.75 ;
     RECT  2.268 33.75 4.104 33.885 ;
     RECT  4.428 33.75 5.994 33.885 ;
     RECT  17.28 33.75 17.928 33.885 ;
     RECT  2.862 34.29 3.51 34.425 ;
     RECT  2.97 34.83 4.05 34.965 ;
     RECT  2.268 35.235 3.456 35.37 ;
     RECT  3.672 35.37 5.022 35.505 ;
     RECT  9.504 35.37 10.638 35.505 ;
     RECT  2.538 35.91 3.51 36.045 ;
     RECT  2.322 36.315 3.294 36.45 ;
     RECT  19.17 37.935 20.304 38.07 ;
     RECT  2.862 38.61 4.968 38.745 ;
     RECT  3.294 39.15 7.506 39.285 ;
     RECT  17.928 41.31 20.304 41.445 ;
     RECT  6.966 46.575 9.504 46.71 ;
     RECT  13.878 50.49 14.58 50.625 ;
     RECT  15.282 50.49 16.47 50.625 ;
     RECT  15.768 52.65 16.146 52.785 ;
     RECT  19.656 54.27 20.304 54.405 ;
     RECT  9.45 56.295 9.774 56.43 ;
     RECT  10.152 56.97 11.286 57.105 ;
     RECT  13.662 56.97 14.634 57.105 ;
     RECT  17.766 60.075 18.36 60.21 ;
     RECT  10.314 62.91 10.746 63.045 ;
     RECT  7.398 63.855 8.748 63.99 ;
     RECT  14.904 63.855 15.228 63.99 ;
     RECT  7.56 64.53 8.046 64.665 ;
     RECT  16.416 64.53 17.442 64.665 ;
     RECT  46.872 65.61 47.358 65.745 ;
     RECT  29.052 66.015 31.536 66.15 ;
     RECT  40.662 66.015 41.256 66.15 ;
     RECT  47.25 66.15 49.086 66.285 ;
     RECT  12.042 67.095 12.366 67.23 ;
     RECT  11.07 67.77 12.906 67.905 ;
     RECT  36.99 68.715 38.07 68.85 ;
     RECT  40.986 68.85 42.012 68.985 ;
     RECT  49.302 68.85 52.056 68.985 ;
     RECT  29.808 69.795 30.348 69.93 ;
     RECT  45.252 71.415 46.44 71.55 ;
     RECT  34.776 72.495 35.802 72.63 ;
     RECT  45.198 72.495 45.576 72.63 ;
     RECT  34.722 72.63 36.072 72.765 ;
     RECT  45.036 75.195 45.738 75.33 ;
    LAYER RVTN ;
     RECT  2.16 2.16 140.4 2.295 ;
     RECT  2.16 2.565 140.4 2.835 ;
     RECT  2.16 3.105 140.4 3.375 ;
     RECT  2.16 3.645 140.4 3.915 ;
     RECT  2.16 4.185 140.4 4.455 ;
     RECT  2.16 4.725 12.906 4.86 ;
     RECT  18.954 4.725 140.4 4.86 ;
     RECT  2.16 4.86 13.068 4.995 ;
     RECT  13.608 4.86 140.4 4.995 ;
     RECT  2.16 5.265 140.4 5.535 ;
     RECT  2.16 5.805 140.4 6.075 ;
     RECT  2.16 6.345 140.4 6.615 ;
     RECT  2.16 6.885 140.4 7.155 ;
     RECT  2.16 7.425 140.4 7.695 ;
     RECT  2.16 7.965 71.874 8.1 ;
     RECT  72.468 7.965 88.398 8.1 ;
     RECT  90.072 7.965 90.558 8.1 ;
     RECT  92.232 7.965 99.576 8.1 ;
     RECT  100.116 7.965 140.4 8.1 ;
     RECT  2.16 8.1 82.188 8.235 ;
     RECT  83.862 8.1 99.846 8.235 ;
     RECT  100.494 8.1 140.4 8.235 ;
     RECT  2.16 8.505 72.306 8.64 ;
     RECT  72.684 8.505 140.4 8.64 ;
     RECT  2.16 8.64 100.872 8.775 ;
     RECT  101.358 8.64 105.138 8.775 ;
     RECT  106.11 8.64 140.4 8.775 ;
     RECT  2.16 9.045 72.144 9.18 ;
     RECT  73.764 9.045 79.974 9.18 ;
     RECT  80.622 9.045 140.4 9.18 ;
     RECT  2.16 9.18 90.828 9.315 ;
     RECT  91.692 9.18 140.4 9.315 ;
     RECT  2.16 9.585 103.95 9.72 ;
     RECT  105.408 9.585 140.4 9.72 ;
     RECT  2.16 9.72 140.4 9.855 ;
     RECT  2.16 10.125 140.4 10.26 ;
     RECT  2.16 10.26 7.56 10.395 ;
     RECT  8.532 10.26 105.354 10.395 ;
     RECT  106.164 10.26 140.4 10.395 ;
     RECT  2.16 10.665 72.252 10.8 ;
     RECT  73.008 10.665 77.76 10.8 ;
     RECT  79.218 10.665 104.436 10.8 ;
     RECT  105.57 10.665 140.4 10.8 ;
     RECT  2.16 10.8 140.4 10.935 ;
     RECT  2.16 11.205 81.702 11.34 ;
     RECT  82.026 11.205 140.4 11.34 ;
     RECT  2.16 11.34 140.4 11.475 ;
     RECT  2.16 11.745 140.4 12.015 ;
     RECT  2.16 12.285 105.894 12.42 ;
     RECT  106.38 12.285 140.4 12.42 ;
     RECT  2.16 12.42 140.4 12.555 ;
     RECT  2.16 12.825 77.274 12.96 ;
     RECT  77.706 12.825 90.882 12.96 ;
     RECT  91.692 12.825 105.516 12.96 ;
     RECT  106.65 12.825 140.4 12.96 ;
     RECT  2.16 12.96 48.924 13.095 ;
     RECT  50.004 12.96 81.648 13.095 ;
     RECT  81.972 12.96 140.4 13.095 ;
     RECT  2.16 13.365 75.06 13.5 ;
     RECT  77.058 13.365 140.4 13.5 ;
     RECT  2.16 13.5 140.4 13.635 ;
     RECT  2.16 13.905 140.4 14.04 ;
     RECT  2.16 14.04 58.644 14.175 ;
     RECT  60.858 14.04 140.4 14.175 ;
     RECT  2.16 14.445 140.4 14.58 ;
     RECT  2.16 14.58 57.726 14.715 ;
     RECT  58.266 14.58 69.66 14.715 ;
     RECT  70.686 14.58 140.4 14.715 ;
     RECT  2.16 14.985 140.4 15.12 ;
     RECT  2.16 15.12 81.054 15.255 ;
     RECT  81.54 15.12 140.4 15.255 ;
     RECT  2.16 15.525 140.4 15.66 ;
     RECT  2.16 15.66 81.756 15.795 ;
     RECT  82.188 15.66 140.4 15.795 ;
     RECT  2.16 16.065 140.4 16.2 ;
     RECT  2.16 16.2 79.812 16.335 ;
     RECT  80.244 16.2 140.4 16.335 ;
     RECT  2.16 16.605 33.588 16.74 ;
     RECT  34.29 16.605 140.4 16.74 ;
     RECT  2.16 16.74 65.988 16.875 ;
     RECT  67.176 16.74 81.432 16.875 ;
     RECT  82.242 16.74 140.4 16.875 ;
     RECT  2.16 17.145 140.4 17.28 ;
     RECT  2.16 17.28 45.9 17.415 ;
     RECT  46.602 17.28 101.196 17.415 ;
     RECT  101.574 17.28 105.948 17.415 ;
     RECT  107.622 17.28 140.4 17.415 ;
     RECT  2.16 17.685 43.848 17.82 ;
     RECT  44.172 17.685 61.182 17.82 ;
     RECT  62.37 17.685 99.522 17.82 ;
     RECT  100.008 17.685 140.4 17.82 ;
     RECT  2.16 17.82 64.314 17.955 ;
     RECT  66.042 17.82 66.69 17.955 ;
     RECT  67.122 17.82 68.31 17.955 ;
     RECT  68.904 17.82 140.4 17.955 ;
     RECT  2.16 18.225 64.692 18.36 ;
     RECT  65.07 18.225 80.082 18.36 ;
     RECT  80.514 18.225 140.4 18.36 ;
     RECT  2.16 18.36 36.558 18.495 ;
     RECT  37.53 18.36 65.394 18.495 ;
     RECT  65.934 18.36 77.922 18.495 ;
     RECT  79.434 18.36 140.4 18.495 ;
     RECT  2.16 18.765 37.584 18.9 ;
     RECT  38.772 18.765 66.204 18.9 ;
     RECT  74.466 18.765 80.568 18.9 ;
     RECT  83.592 18.765 140.4 18.9 ;
     RECT  2.16 18.9 10.692 19.035 ;
     RECT  12.258 18.9 14.796 19.035 ;
     RECT  15.336 18.9 31.59 19.035 ;
     RECT  33.048 18.9 33.696 19.035 ;
     RECT  35.1 18.9 36.45 19.035 ;
     RECT  38.718 18.9 39.042 19.035 ;
     RECT  40.014 18.9 47.304 19.035 ;
     RECT  48.114 18.9 140.4 19.035 ;
     RECT  2.16 19.305 31.374 19.44 ;
     RECT  32.454 19.305 33.534 19.44 ;
     RECT  35.91 19.305 41.742 19.44 ;
     RECT  42.714 19.305 48.654 19.44 ;
     RECT  49.464 19.305 77.706 19.44 ;
     RECT  79.002 19.305 140.4 19.44 ;
     RECT  2.16 19.44 22.788 19.575 ;
     RECT  24.462 19.44 31.374 19.575 ;
     RECT  33.588 19.44 34.776 19.575 ;
     RECT  36.882 19.44 39.528 19.575 ;
     RECT  40.068 19.44 46.116 19.575 ;
     RECT  47.358 19.44 48.114 19.575 ;
     RECT  48.762 19.44 49.41 19.575 ;
     RECT  51.192 19.44 52.812 19.575 ;
     RECT  54.108 19.44 77.112 19.575 ;
     RECT  77.868 19.44 140.4 19.575 ;
     RECT  2.16 19.845 29.646 19.98 ;
     RECT  30.834 19.845 44.28 19.98 ;
     RECT  45.468 19.845 140.4 19.98 ;
     RECT  2.16 19.98 35.532 20.115 ;
     RECT  37.368 19.98 140.4 20.115 ;
     RECT  2.16 20.385 20.412 20.655 ;
     RECT  119.34 20.385 140.4 20.655 ;
     RECT  2.16 20.925 20.412 21.195 ;
     RECT  119.34 20.925 140.4 21.195 ;
     RECT  2.16 21.465 20.412 21.735 ;
     RECT  119.34 21.465 140.4 21.735 ;
     RECT  2.16 22.005 20.412 22.14 ;
     RECT  2.16 22.14 7.938 22.275 ;
     RECT  8.802 22.14 20.412 22.275 ;
     RECT  119.34 22.005 140.4 22.275 ;
     RECT  2.16 22.545 20.412 22.815 ;
     RECT  119.34 22.545 140.4 22.815 ;
     RECT  2.16 23.085 7.992 23.22 ;
     RECT  8.37 23.085 20.412 23.22 ;
     RECT  2.16 23.22 20.412 23.355 ;
     RECT  119.34 23.085 140.4 23.355 ;
     RECT  2.16 23.625 7.452 23.76 ;
     RECT  7.884 23.625 20.412 23.76 ;
     RECT  2.16 23.76 20.412 23.895 ;
     RECT  119.34 23.625 140.4 23.895 ;
     RECT  2.16 24.165 15.552 24.3 ;
     RECT  18.522 24.165 20.412 24.3 ;
     RECT  2.16 24.3 20.412 24.435 ;
     RECT  119.34 24.165 140.4 24.435 ;
     RECT  2.16 24.705 20.412 24.975 ;
     RECT  119.34 24.705 140.4 24.975 ;
     RECT  2.16 25.245 20.412 25.515 ;
     RECT  119.34 25.245 140.4 25.515 ;
     RECT  2.16 25.785 20.412 25.92 ;
     RECT  2.16 25.92 13.446 26.055 ;
     RECT  14.526 25.92 20.412 26.055 ;
     RECT  119.34 25.785 140.4 26.055 ;
     RECT  2.16 26.325 13.5 26.46 ;
     RECT  14.04 26.325 20.412 26.46 ;
     RECT  2.16 26.46 20.412 26.595 ;
     RECT  119.34 26.325 140.4 26.595 ;
     RECT  2.16 26.865 20.412 27.135 ;
     RECT  119.34 26.865 140.4 27.135 ;
     RECT  2.16 27.405 20.412 27.675 ;
     RECT  119.34 27.405 140.4 27.675 ;
     RECT  2.16 27.945 20.412 28.215 ;
     RECT  119.34 27.945 140.4 28.215 ;
     RECT  2.16 28.485 20.412 28.62 ;
     RECT  2.16 28.62 10.854 28.755 ;
     RECT  11.718 28.62 15.876 28.755 ;
     RECT  18.954 28.62 20.412 28.755 ;
     RECT  119.34 28.485 140.4 28.755 ;
     RECT  2.16 29.025 20.412 29.295 ;
     RECT  119.34 29.025 140.4 29.295 ;
     RECT  2.16 29.565 2.754 29.7 ;
     RECT  4.05 29.565 20.412 29.7 ;
     RECT  2.16 29.7 20.412 29.835 ;
     RECT  119.34 29.565 140.4 29.835 ;
     RECT  2.16 30.105 20.412 30.24 ;
     RECT  2.16 30.24 6.912 30.375 ;
     RECT  8.154 30.24 20.412 30.375 ;
     RECT  119.34 30.105 140.4 30.375 ;
     RECT  2.16 30.645 20.412 30.915 ;
     RECT  119.34 30.645 140.4 30.915 ;
     RECT  2.16 31.185 20.412 31.32 ;
     RECT  2.16 31.32 14.688 31.455 ;
     RECT  16.362 31.32 20.412 31.455 ;
     RECT  119.34 31.185 140.4 31.455 ;
     RECT  2.16 31.725 15.606 31.86 ;
     RECT  16.632 31.725 20.412 31.86 ;
     RECT  2.16 31.86 2.754 31.995 ;
     RECT  3.726 31.86 14.418 31.995 ;
     RECT  15.12 31.86 20.412 31.995 ;
     RECT  119.34 31.725 140.4 31.995 ;
     RECT  2.16 32.265 20.412 32.4 ;
     RECT  2.16 32.4 3.834 32.535 ;
     RECT  5.562 32.4 13.878 32.535 ;
     RECT  14.58 32.4 20.412 32.535 ;
     RECT  119.34 32.265 140.4 32.535 ;
     RECT  2.16 32.805 2.268 32.94 ;
     RECT  3.24 32.805 12.15 32.94 ;
     RECT  13.176 32.805 20.412 32.94 ;
     RECT  2.16 32.94 20.412 33.075 ;
     RECT  119.34 32.805 140.4 33.075 ;
     RECT  2.16 33.345 20.412 33.48 ;
     RECT  2.16 33.48 10.26 33.615 ;
     RECT  10.962 33.48 20.412 33.615 ;
     RECT  119.34 33.345 140.4 33.615 ;
     RECT  2.16 33.885 2.268 34.02 ;
     RECT  4.104 33.885 4.428 34.02 ;
     RECT  5.994 33.885 17.28 34.02 ;
     RECT  17.928 33.885 20.412 34.02 ;
     RECT  2.16 34.02 20.412 34.155 ;
     RECT  119.34 33.885 140.4 34.155 ;
     RECT  2.16 34.425 2.862 34.56 ;
     RECT  3.51 34.425 20.412 34.56 ;
     RECT  2.16 34.56 20.412 34.695 ;
     RECT  119.34 34.425 140.4 34.695 ;
     RECT  2.16 34.965 2.97 35.1 ;
     RECT  4.05 34.965 20.412 35.1 ;
     RECT  2.16 35.1 2.268 35.235 ;
     RECT  3.456 35.1 20.412 35.235 ;
     RECT  119.34 34.965 140.4 35.235 ;
     RECT  2.16 35.505 3.672 35.64 ;
     RECT  5.022 35.505 9.504 35.64 ;
     RECT  10.638 35.505 20.412 35.64 ;
     RECT  2.16 35.64 20.412 35.775 ;
     RECT  119.34 35.505 140.4 35.775 ;
     RECT  2.16 36.045 2.538 36.18 ;
     RECT  3.51 36.045 20.412 36.18 ;
     RECT  2.16 36.18 2.322 36.315 ;
     RECT  3.294 36.18 20.412 36.315 ;
     RECT  119.34 36.045 140.4 36.315 ;
     RECT  2.16 36.585 20.412 36.855 ;
     RECT  119.34 36.585 140.4 36.855 ;
     RECT  2.16 37.125 20.412 37.395 ;
     RECT  119.34 37.125 140.4 37.395 ;
     RECT  2.16 37.665 20.412 37.8 ;
     RECT  2.16 37.8 19.17 37.935 ;
     RECT  20.304 37.8 20.412 37.935 ;
     RECT  119.34 37.665 140.4 37.935 ;
     RECT  2.16 38.205 20.412 38.475 ;
     RECT  119.34 38.205 140.4 38.475 ;
     RECT  2.16 38.745 2.862 38.88 ;
     RECT  4.968 38.745 20.412 38.88 ;
     RECT  2.16 38.88 20.412 39.015 ;
     RECT  119.34 38.745 140.4 39.015 ;
     RECT  2.16 39.285 3.294 39.42 ;
     RECT  7.506 39.285 20.412 39.42 ;
     RECT  2.16 39.42 20.412 39.555 ;
     RECT  119.34 39.285 140.4 39.555 ;
     RECT  2.16 39.825 20.412 40.095 ;
     RECT  119.34 39.825 140.4 40.095 ;
     RECT  2.16 40.365 20.412 40.635 ;
     RECT  119.34 40.365 140.4 40.635 ;
     RECT  2.16 40.905 20.412 41.175 ;
     RECT  119.34 40.905 140.4 41.175 ;
     RECT  2.16 41.445 17.928 41.58 ;
     RECT  20.304 41.445 20.412 41.58 ;
     RECT  2.16 41.58 20.412 41.715 ;
     RECT  119.34 41.445 140.4 41.715 ;
     RECT  2.16 41.985 20.412 42.255 ;
     RECT  119.34 41.985 140.4 42.255 ;
     RECT  2.16 42.525 20.412 42.795 ;
     RECT  119.34 42.525 140.4 42.795 ;
     RECT  2.16 43.065 20.412 43.335 ;
     RECT  119.34 43.065 140.4 43.335 ;
     RECT  2.16 43.605 20.412 43.875 ;
     RECT  119.34 43.605 140.4 43.875 ;
     RECT  2.16 44.145 20.412 44.415 ;
     RECT  119.34 44.145 140.4 44.415 ;
     RECT  2.16 44.685 20.412 44.955 ;
     RECT  119.34 44.685 140.4 44.955 ;
     RECT  2.16 45.225 20.412 45.495 ;
     RECT  119.34 45.225 140.4 45.495 ;
     RECT  2.16 45.765 20.412 46.035 ;
     RECT  119.34 45.765 140.4 46.035 ;
     RECT  2.16 46.305 20.412 46.44 ;
     RECT  2.16 46.44 6.966 46.575 ;
     RECT  9.504 46.44 20.412 46.575 ;
     RECT  119.34 46.305 140.4 46.575 ;
     RECT  2.16 46.845 20.412 47.115 ;
     RECT  119.34 46.845 140.4 47.115 ;
     RECT  2.16 47.385 20.412 47.655 ;
     RECT  119.34 47.385 140.4 47.655 ;
     RECT  2.16 47.925 20.412 48.195 ;
     RECT  119.34 47.925 140.4 48.195 ;
     RECT  2.16 48.465 20.412 48.735 ;
     RECT  119.34 48.465 140.4 48.735 ;
     RECT  2.16 49.005 20.412 49.275 ;
     RECT  119.34 49.005 140.4 49.275 ;
     RECT  2.16 49.545 20.412 49.815 ;
     RECT  119.34 49.545 140.4 49.815 ;
     RECT  2.16 50.085 20.412 50.355 ;
     RECT  119.34 50.085 140.4 50.355 ;
     RECT  2.16 50.625 13.878 50.76 ;
     RECT  14.58 50.625 15.282 50.76 ;
     RECT  16.47 50.625 20.412 50.76 ;
     RECT  2.16 50.76 20.412 50.895 ;
     RECT  119.34 50.625 140.4 50.895 ;
     RECT  2.16 51.165 20.412 51.435 ;
     RECT  119.34 51.165 140.4 51.435 ;
     RECT  2.16 51.705 20.412 51.975 ;
     RECT  119.34 51.705 140.4 51.975 ;
     RECT  2.16 52.245 20.412 52.515 ;
     RECT  119.34 52.245 140.4 52.515 ;
     RECT  2.16 52.785 15.768 52.92 ;
     RECT  16.146 52.785 20.412 52.92 ;
     RECT  2.16 52.92 20.412 53.055 ;
     RECT  119.34 52.785 140.4 53.055 ;
     RECT  2.16 53.325 20.412 53.595 ;
     RECT  119.34 53.325 140.4 53.595 ;
     RECT  2.16 53.865 20.412 54.135 ;
     RECT  119.34 53.865 140.4 54.135 ;
     RECT  2.16 54.405 19.656 54.54 ;
     RECT  20.304 54.405 20.412 54.54 ;
     RECT  2.16 54.54 20.412 54.675 ;
     RECT  119.34 54.405 140.4 54.675 ;
     RECT  2.16 54.945 20.412 55.215 ;
     RECT  119.34 54.945 140.4 55.215 ;
     RECT  2.16 55.485 20.412 55.755 ;
     RECT  119.34 55.485 140.4 55.755 ;
     RECT  2.16 56.025 20.412 56.16 ;
     RECT  2.16 56.16 9.45 56.295 ;
     RECT  9.774 56.16 20.412 56.295 ;
     RECT  119.34 56.025 140.4 56.295 ;
     RECT  2.16 56.565 20.412 56.835 ;
     RECT  119.34 56.565 140.4 56.835 ;
     RECT  2.16 57.105 10.152 57.24 ;
     RECT  11.286 57.105 13.662 57.24 ;
     RECT  14.634 57.105 20.412 57.24 ;
     RECT  2.16 57.24 20.412 57.375 ;
     RECT  119.34 57.105 140.4 57.375 ;
     RECT  2.16 57.645 20.412 57.915 ;
     RECT  119.34 57.645 140.4 57.915 ;
     RECT  2.16 58.185 20.412 58.455 ;
     RECT  119.34 58.185 140.4 58.455 ;
     RECT  2.16 58.725 20.412 58.995 ;
     RECT  119.34 58.725 140.4 58.995 ;
     RECT  2.16 59.265 20.412 59.535 ;
     RECT  119.34 59.265 140.4 59.535 ;
     RECT  2.16 59.805 20.412 59.94 ;
     RECT  2.16 59.94 17.766 60.075 ;
     RECT  18.36 59.94 20.412 60.075 ;
     RECT  119.34 59.805 140.4 60.075 ;
     RECT  2.16 60.345 20.412 60.615 ;
     RECT  119.34 60.345 140.4 60.615 ;
     RECT  2.16 60.885 20.412 61.155 ;
     RECT  119.34 60.885 140.4 61.155 ;
     RECT  2.16 61.425 20.412 61.695 ;
     RECT  119.34 61.425 140.4 61.695 ;
     RECT  2.16 61.965 20.412 62.235 ;
     RECT  119.34 61.965 140.4 62.235 ;
     RECT  2.16 62.505 20.412 62.775 ;
     RECT  119.34 62.505 140.4 62.775 ;
     RECT  2.16 63.045 10.314 63.18 ;
     RECT  10.746 63.045 20.412 63.18 ;
     RECT  2.16 63.18 20.412 63.315 ;
     RECT  119.34 63.045 140.4 63.315 ;
     RECT  2.16 63.585 20.412 63.72 ;
     RECT  2.16 63.72 7.398 63.855 ;
     RECT  8.748 63.72 14.904 63.855 ;
     RECT  15.228 63.72 20.412 63.855 ;
     RECT  119.34 63.585 140.4 63.855 ;
     RECT  2.16 64.125 20.412 64.395 ;
     RECT  119.34 64.125 140.4 64.395 ;
     RECT  2.16 64.665 7.56 64.8 ;
     RECT  8.046 64.665 16.416 64.8 ;
     RECT  17.442 64.665 20.412 64.8 ;
     RECT  2.16 64.8 20.412 64.935 ;
     RECT  119.34 64.665 140.4 64.935 ;
     RECT  2.16 65.205 20.412 65.475 ;
     RECT  119.34 65.205 140.4 65.475 ;
     RECT  2.16 65.745 46.872 65.88 ;
     RECT  47.358 65.745 140.4 65.88 ;
     RECT  2.16 65.88 29.052 66.015 ;
     RECT  31.536 65.88 40.662 66.015 ;
     RECT  41.256 65.88 140.4 66.015 ;
     RECT  2.16 66.285 47.25 66.42 ;
     RECT  49.086 66.285 140.4 66.42 ;
     RECT  2.16 66.42 140.4 66.555 ;
     RECT  2.16 66.825 140.4 66.96 ;
     RECT  2.16 66.96 12.042 67.095 ;
     RECT  12.366 66.96 140.4 67.095 ;
     RECT  2.16 67.365 140.4 67.635 ;
     RECT  2.16 67.905 11.07 68.04 ;
     RECT  12.906 67.905 140.4 68.04 ;
     RECT  2.16 68.04 140.4 68.175 ;
     RECT  2.16 68.445 140.4 68.58 ;
     RECT  2.16 68.58 36.99 68.715 ;
     RECT  38.07 68.58 140.4 68.715 ;
     RECT  2.16 68.985 40.986 69.12 ;
     RECT  42.012 68.985 49.302 69.12 ;
     RECT  52.056 68.985 140.4 69.12 ;
     RECT  2.16 69.12 140.4 69.255 ;
     RECT  2.16 69.525 140.4 69.66 ;
     RECT  2.16 69.66 29.808 69.795 ;
     RECT  30.348 69.66 140.4 69.795 ;
     RECT  2.16 70.065 140.4 70.335 ;
     RECT  2.16 70.605 140.4 70.875 ;
     RECT  2.16 71.145 140.4 71.28 ;
     RECT  2.16 71.28 45.252 71.415 ;
     RECT  46.44 71.28 140.4 71.415 ;
     RECT  2.16 71.685 140.4 71.955 ;
     RECT  2.16 72.225 140.4 72.36 ;
     RECT  2.16 72.36 34.776 72.495 ;
     RECT  35.802 72.36 45.198 72.495 ;
     RECT  45.576 72.36 140.4 72.495 ;
     RECT  2.16 72.765 34.722 72.9 ;
     RECT  36.072 72.765 140.4 72.9 ;
     RECT  2.16 72.9 140.4 73.035 ;
     RECT  2.16 73.305 140.4 73.575 ;
     RECT  2.16 73.845 140.4 74.115 ;
     RECT  2.16 74.385 140.4 74.655 ;
     RECT  2.16 74.925 140.4 75.06 ;
     RECT  2.16 75.06 45.036 75.195 ;
     RECT  45.738 75.06 140.4 75.195 ;
     RECT  2.16 75.465 140.4 75.735 ;
     RECT  2.16 76.005 140.4 76.275 ;
     RECT  2.16 76.545 140.4 76.815 ;
     RECT  2.16 77.085 140.4 77.355 ;
     RECT  2.16 77.625 140.4 77.895 ;
     RECT  2.16 78.165 140.4 78.435 ;
     RECT  2.16 78.705 140.4 78.975 ;
     RECT  2.16 79.245 140.4 79.515 ;
     RECT  2.16 79.785 140.4 80.055 ;
     RECT  2.16 80.325 140.4 80.595 ;
     RECT  2.16 80.865 140.4 81.135 ;
     RECT  2.16 81.405 140.4 81.675 ;
     RECT  2.16 81.945 140.4 82.215 ;
     RECT  2.16 82.485 140.4 82.755 ;
     RECT  2.16 83.025 140.4 83.295 ;
     RECT  2.16 83.565 140.4 83.835 ;
     RECT  2.16 84.105 140.4 84.24 ;
    LAYER RVTP ;
     RECT  2.16 2.295 140.4 2.565 ;
     RECT  2.16 2.835 140.4 3.105 ;
     RECT  2.16 3.375 140.4 3.645 ;
     RECT  2.16 3.915 140.4 4.185 ;
     RECT  2.16 4.455 140.4 4.59 ;
     RECT  2.16 4.59 12.906 4.725 ;
     RECT  18.954 4.59 140.4 4.725 ;
     RECT  2.16 4.995 13.068 5.13 ;
     RECT  13.608 4.995 140.4 5.13 ;
     RECT  2.16 5.13 140.4 5.265 ;
     RECT  2.16 5.535 140.4 5.805 ;
     RECT  2.16 6.075 140.4 6.345 ;
     RECT  2.16 6.615 140.4 6.885 ;
     RECT  2.16 7.155 140.4 7.425 ;
     RECT  2.16 7.695 140.4 7.83 ;
     RECT  2.16 7.83 71.874 7.965 ;
     RECT  72.468 7.83 88.398 7.965 ;
     RECT  90.072 7.83 90.558 7.965 ;
     RECT  92.232 7.83 99.576 7.965 ;
     RECT  100.116 7.83 140.4 7.965 ;
     RECT  2.16 8.235 82.188 8.37 ;
     RECT  83.862 8.235 99.846 8.37 ;
     RECT  100.494 8.235 140.4 8.37 ;
     RECT  2.16 8.37 72.306 8.505 ;
     RECT  72.684 8.37 140.4 8.505 ;
     RECT  2.16 8.775 100.872 8.91 ;
     RECT  101.358 8.775 105.138 8.91 ;
     RECT  106.11 8.775 140.4 8.91 ;
     RECT  2.16 8.91 72.144 9.045 ;
     RECT  73.764 8.91 79.974 9.045 ;
     RECT  80.622 8.91 140.4 9.045 ;
     RECT  2.16 9.315 90.828 9.45 ;
     RECT  91.692 9.315 140.4 9.45 ;
     RECT  2.16 9.45 103.95 9.585 ;
     RECT  105.408 9.45 140.4 9.585 ;
     RECT  2.16 9.855 140.4 10.125 ;
     RECT  2.16 10.395 7.56 10.53 ;
     RECT  8.532 10.395 105.354 10.53 ;
     RECT  106.164 10.395 140.4 10.53 ;
     RECT  2.16 10.53 72.252 10.665 ;
     RECT  73.008 10.53 77.76 10.665 ;
     RECT  79.218 10.53 104.436 10.665 ;
     RECT  105.57 10.53 140.4 10.665 ;
     RECT  2.16 10.935 140.4 11.07 ;
     RECT  2.16 11.07 81.702 11.205 ;
     RECT  82.026 11.07 140.4 11.205 ;
     RECT  2.16 11.475 140.4 11.745 ;
     RECT  2.16 12.015 140.4 12.15 ;
     RECT  2.16 12.15 105.894 12.285 ;
     RECT  106.38 12.15 140.4 12.285 ;
     RECT  2.16 12.555 140.4 12.69 ;
     RECT  2.16 12.69 77.274 12.825 ;
     RECT  77.706 12.69 90.882 12.825 ;
     RECT  91.692 12.69 105.516 12.825 ;
     RECT  106.65 12.69 140.4 12.825 ;
     RECT  2.16 13.095 48.924 13.23 ;
     RECT  50.004 13.095 81.648 13.23 ;
     RECT  81.972 13.095 140.4 13.23 ;
     RECT  2.16 13.23 75.06 13.365 ;
     RECT  77.058 13.23 140.4 13.365 ;
     RECT  2.16 13.635 140.4 13.905 ;
     RECT  2.16 14.175 58.644 14.31 ;
     RECT  60.858 14.175 140.4 14.31 ;
     RECT  2.16 14.31 140.4 14.445 ;
     RECT  2.16 14.715 57.726 14.85 ;
     RECT  58.266 14.715 69.66 14.85 ;
     RECT  70.686 14.715 140.4 14.85 ;
     RECT  2.16 14.85 140.4 14.985 ;
     RECT  2.16 15.255 81.054 15.39 ;
     RECT  81.54 15.255 140.4 15.39 ;
     RECT  2.16 15.39 140.4 15.525 ;
     RECT  2.16 15.795 81.756 15.93 ;
     RECT  82.188 15.795 140.4 15.93 ;
     RECT  2.16 15.93 140.4 16.065 ;
     RECT  2.16 16.335 79.812 16.47 ;
     RECT  80.244 16.335 140.4 16.47 ;
     RECT  2.16 16.47 33.588 16.605 ;
     RECT  34.29 16.47 140.4 16.605 ;
     RECT  2.16 16.875 65.988 17.01 ;
     RECT  67.176 16.875 81.432 17.01 ;
     RECT  82.242 16.875 140.4 17.01 ;
     RECT  2.16 17.01 140.4 17.145 ;
     RECT  2.16 17.415 45.9 17.55 ;
     RECT  46.602 17.415 101.196 17.55 ;
     RECT  101.574 17.415 105.948 17.55 ;
     RECT  107.622 17.415 140.4 17.55 ;
     RECT  2.16 17.55 43.848 17.685 ;
     RECT  44.172 17.55 61.182 17.685 ;
     RECT  62.37 17.55 99.522 17.685 ;
     RECT  100.008 17.55 140.4 17.685 ;
     RECT  2.16 17.955 64.314 18.09 ;
     RECT  66.042 17.955 66.69 18.09 ;
     RECT  67.122 17.955 68.31 18.09 ;
     RECT  68.904 17.955 140.4 18.09 ;
     RECT  2.16 18.09 64.692 18.225 ;
     RECT  65.07 18.09 80.082 18.225 ;
     RECT  80.514 18.09 140.4 18.225 ;
     RECT  2.16 18.495 36.558 18.63 ;
     RECT  37.53 18.495 65.394 18.63 ;
     RECT  65.934 18.495 77.922 18.63 ;
     RECT  79.434 18.495 140.4 18.63 ;
     RECT  2.16 18.63 37.584 18.765 ;
     RECT  38.772 18.63 66.204 18.765 ;
     RECT  74.466 18.63 80.568 18.765 ;
     RECT  83.592 18.63 140.4 18.765 ;
     RECT  2.16 19.035 10.692 19.17 ;
     RECT  12.258 19.035 14.796 19.17 ;
     RECT  15.336 19.035 31.59 19.17 ;
     RECT  33.048 19.035 33.696 19.17 ;
     RECT  35.1 19.035 36.45 19.17 ;
     RECT  38.718 19.035 39.042 19.17 ;
     RECT  40.014 19.035 47.304 19.17 ;
     RECT  48.114 19.035 140.4 19.17 ;
     RECT  2.16 19.17 31.374 19.305 ;
     RECT  32.454 19.17 33.534 19.305 ;
     RECT  35.91 19.17 41.742 19.305 ;
     RECT  42.714 19.17 48.654 19.305 ;
     RECT  49.464 19.17 77.706 19.305 ;
     RECT  79.002 19.17 140.4 19.305 ;
     RECT  2.16 19.575 22.788 19.71 ;
     RECT  24.462 19.575 31.374 19.71 ;
     RECT  33.588 19.575 34.776 19.71 ;
     RECT  36.882 19.575 39.528 19.71 ;
     RECT  40.068 19.575 46.116 19.71 ;
     RECT  47.358 19.575 48.114 19.71 ;
     RECT  48.762 19.575 49.41 19.71 ;
     RECT  51.192 19.575 52.812 19.71 ;
     RECT  54.108 19.575 77.112 19.71 ;
     RECT  77.868 19.575 140.4 19.71 ;
     RECT  2.16 19.71 29.646 19.845 ;
     RECT  30.834 19.71 44.28 19.845 ;
     RECT  45.468 19.71 140.4 19.845 ;
     RECT  2.16 20.115 35.532 20.25 ;
     RECT  37.368 20.115 140.4 20.25 ;
     RECT  2.16 20.25 20.412 20.385 ;
     RECT  119.34 20.25 140.4 20.385 ;
     RECT  2.16 20.655 20.412 20.925 ;
     RECT  119.34 20.655 140.4 20.925 ;
     RECT  2.16 21.195 20.412 21.465 ;
     RECT  119.34 21.195 140.4 21.465 ;
     RECT  2.16 21.735 20.412 22.005 ;
     RECT  119.34 21.735 140.4 22.005 ;
     RECT  2.16 22.275 7.938 22.41 ;
     RECT  8.802 22.275 20.412 22.41 ;
     RECT  2.16 22.41 20.412 22.545 ;
     RECT  119.34 22.275 140.4 22.545 ;
     RECT  2.16 22.815 20.412 22.95 ;
     RECT  2.16 22.95 7.992 23.085 ;
     RECT  8.37 22.95 20.412 23.085 ;
     RECT  119.34 22.815 140.4 23.085 ;
     RECT  2.16 23.355 20.412 23.49 ;
     RECT  2.16 23.49 7.452 23.625 ;
     RECT  7.884 23.49 20.412 23.625 ;
     RECT  119.34 23.355 140.4 23.625 ;
     RECT  2.16 23.895 20.412 24.03 ;
     RECT  2.16 24.03 15.552 24.165 ;
     RECT  18.522 24.03 20.412 24.165 ;
     RECT  119.34 23.895 140.4 24.165 ;
     RECT  2.16 24.435 20.412 24.705 ;
     RECT  119.34 24.435 140.4 24.705 ;
     RECT  2.16 24.975 20.412 25.245 ;
     RECT  119.34 24.975 140.4 25.245 ;
     RECT  2.16 25.515 20.412 25.785 ;
     RECT  119.34 25.515 140.4 25.785 ;
     RECT  2.16 26.055 13.446 26.19 ;
     RECT  14.526 26.055 20.412 26.19 ;
     RECT  2.16 26.19 13.5 26.325 ;
     RECT  14.04 26.19 20.412 26.325 ;
     RECT  119.34 26.055 140.4 26.325 ;
     RECT  2.16 26.595 20.412 26.865 ;
     RECT  119.34 26.595 140.4 26.865 ;
     RECT  2.16 27.135 20.412 27.405 ;
     RECT  119.34 27.135 140.4 27.405 ;
     RECT  2.16 27.675 20.412 27.945 ;
     RECT  119.34 27.675 140.4 27.945 ;
     RECT  2.16 28.215 20.412 28.485 ;
     RECT  119.34 28.215 140.4 28.485 ;
     RECT  2.16 28.755 10.854 28.89 ;
     RECT  11.718 28.755 15.876 28.89 ;
     RECT  18.954 28.755 20.412 28.89 ;
     RECT  2.16 28.89 20.412 29.025 ;
     RECT  119.34 28.755 140.4 29.025 ;
     RECT  2.16 29.295 20.412 29.43 ;
     RECT  2.16 29.43 2.754 29.565 ;
     RECT  4.05 29.43 20.412 29.565 ;
     RECT  119.34 29.295 140.4 29.565 ;
     RECT  2.16 29.835 20.412 30.105 ;
     RECT  119.34 29.835 140.4 30.105 ;
     RECT  2.16 30.375 6.912 30.51 ;
     RECT  8.154 30.375 20.412 30.51 ;
     RECT  2.16 30.51 20.412 30.645 ;
     RECT  119.34 30.375 140.4 30.645 ;
     RECT  2.16 30.915 20.412 31.185 ;
     RECT  119.34 30.915 140.4 31.185 ;
     RECT  2.16 31.455 14.688 31.59 ;
     RECT  16.362 31.455 20.412 31.59 ;
     RECT  2.16 31.59 15.606 31.725 ;
     RECT  16.632 31.59 20.412 31.725 ;
     RECT  119.34 31.455 140.4 31.725 ;
     RECT  2.16 31.995 2.754 32.13 ;
     RECT  3.726 31.995 14.418 32.13 ;
     RECT  15.12 31.995 20.412 32.13 ;
     RECT  2.16 32.13 20.412 32.265 ;
     RECT  119.34 31.995 140.4 32.265 ;
     RECT  2.16 32.535 3.834 32.67 ;
     RECT  5.562 32.535 13.878 32.67 ;
     RECT  14.58 32.535 20.412 32.67 ;
     RECT  2.16 32.67 2.268 32.805 ;
     RECT  3.24 32.67 12.15 32.805 ;
     RECT  13.176 32.67 20.412 32.805 ;
     RECT  119.34 32.535 140.4 32.805 ;
     RECT  2.16 33.075 20.412 33.345 ;
     RECT  119.34 33.075 140.4 33.345 ;
     RECT  2.16 33.615 10.26 33.75 ;
     RECT  10.962 33.615 20.412 33.75 ;
     RECT  2.16 33.75 2.268 33.885 ;
     RECT  4.104 33.75 4.428 33.885 ;
     RECT  5.994 33.75 17.28 33.885 ;
     RECT  17.928 33.75 20.412 33.885 ;
     RECT  119.34 33.615 140.4 33.885 ;
     RECT  2.16 34.155 20.412 34.29 ;
     RECT  2.16 34.29 2.862 34.425 ;
     RECT  3.51 34.29 20.412 34.425 ;
     RECT  119.34 34.155 140.4 34.425 ;
     RECT  2.16 34.695 20.412 34.83 ;
     RECT  2.16 34.83 2.97 34.965 ;
     RECT  4.05 34.83 20.412 34.965 ;
     RECT  119.34 34.695 140.4 34.965 ;
     RECT  2.16 35.235 2.268 35.37 ;
     RECT  3.456 35.235 20.412 35.37 ;
     RECT  2.16 35.37 3.672 35.505 ;
     RECT  5.022 35.37 9.504 35.505 ;
     RECT  10.638 35.37 20.412 35.505 ;
     RECT  119.34 35.235 140.4 35.505 ;
     RECT  2.16 35.775 20.412 35.91 ;
     RECT  2.16 35.91 2.538 36.045 ;
     RECT  3.51 35.91 20.412 36.045 ;
     RECT  119.34 35.775 140.4 36.045 ;
     RECT  2.16 36.315 2.322 36.45 ;
     RECT  3.294 36.315 20.412 36.45 ;
     RECT  2.16 36.45 20.412 36.585 ;
     RECT  119.34 36.315 140.4 36.585 ;
     RECT  2.16 36.855 20.412 37.125 ;
     RECT  119.34 36.855 140.4 37.125 ;
     RECT  2.16 37.395 20.412 37.665 ;
     RECT  119.34 37.395 140.4 37.665 ;
     RECT  2.16 37.935 19.17 38.07 ;
     RECT  20.304 37.935 20.412 38.07 ;
     RECT  2.16 38.07 20.412 38.205 ;
     RECT  119.34 37.935 140.4 38.205 ;
     RECT  2.16 38.475 20.412 38.61 ;
     RECT  2.16 38.61 2.862 38.745 ;
     RECT  4.968 38.61 20.412 38.745 ;
     RECT  119.34 38.475 140.4 38.745 ;
     RECT  2.16 39.015 20.412 39.15 ;
     RECT  2.16 39.15 3.294 39.285 ;
     RECT  7.506 39.15 20.412 39.285 ;
     RECT  119.34 39.015 140.4 39.285 ;
     RECT  2.16 39.555 20.412 39.825 ;
     RECT  119.34 39.555 140.4 39.825 ;
     RECT  2.16 40.095 20.412 40.365 ;
     RECT  119.34 40.095 140.4 40.365 ;
     RECT  2.16 40.635 20.412 40.905 ;
     RECT  119.34 40.635 140.4 40.905 ;
     RECT  2.16 41.175 20.412 41.31 ;
     RECT  2.16 41.31 17.928 41.445 ;
     RECT  20.304 41.31 20.412 41.445 ;
     RECT  119.34 41.175 140.4 41.445 ;
     RECT  2.16 41.715 20.412 41.985 ;
     RECT  119.34 41.715 140.4 41.985 ;
     RECT  2.16 42.255 20.412 42.525 ;
     RECT  119.34 42.255 140.4 42.525 ;
     RECT  2.16 42.795 20.412 43.065 ;
     RECT  119.34 42.795 140.4 43.065 ;
     RECT  2.16 43.335 20.412 43.605 ;
     RECT  119.34 43.335 140.4 43.605 ;
     RECT  2.16 43.875 20.412 44.145 ;
     RECT  119.34 43.875 140.4 44.145 ;
     RECT  2.16 44.415 20.412 44.685 ;
     RECT  119.34 44.415 140.4 44.685 ;
     RECT  2.16 44.955 20.412 45.225 ;
     RECT  119.34 44.955 140.4 45.225 ;
     RECT  2.16 45.495 20.412 45.765 ;
     RECT  119.34 45.495 140.4 45.765 ;
     RECT  2.16 46.035 20.412 46.305 ;
     RECT  119.34 46.035 140.4 46.305 ;
     RECT  2.16 46.575 6.966 46.71 ;
     RECT  9.504 46.575 20.412 46.71 ;
     RECT  2.16 46.71 20.412 46.845 ;
     RECT  119.34 46.575 140.4 46.845 ;
     RECT  2.16 47.115 20.412 47.385 ;
     RECT  119.34 47.115 140.4 47.385 ;
     RECT  2.16 47.655 20.412 47.925 ;
     RECT  119.34 47.655 140.4 47.925 ;
     RECT  2.16 48.195 20.412 48.465 ;
     RECT  119.34 48.195 140.4 48.465 ;
     RECT  2.16 48.735 20.412 49.005 ;
     RECT  119.34 48.735 140.4 49.005 ;
     RECT  2.16 49.275 20.412 49.545 ;
     RECT  119.34 49.275 140.4 49.545 ;
     RECT  2.16 49.815 20.412 50.085 ;
     RECT  119.34 49.815 140.4 50.085 ;
     RECT  2.16 50.355 20.412 50.49 ;
     RECT  2.16 50.49 13.878 50.625 ;
     RECT  14.58 50.49 15.282 50.625 ;
     RECT  16.47 50.49 20.412 50.625 ;
     RECT  119.34 50.355 140.4 50.625 ;
     RECT  2.16 50.895 20.412 51.165 ;
     RECT  119.34 50.895 140.4 51.165 ;
     RECT  2.16 51.435 20.412 51.705 ;
     RECT  119.34 51.435 140.4 51.705 ;
     RECT  2.16 51.975 20.412 52.245 ;
     RECT  119.34 51.975 140.4 52.245 ;
     RECT  2.16 52.515 20.412 52.65 ;
     RECT  2.16 52.65 15.768 52.785 ;
     RECT  16.146 52.65 20.412 52.785 ;
     RECT  119.34 52.515 140.4 52.785 ;
     RECT  2.16 53.055 20.412 53.325 ;
     RECT  119.34 53.055 140.4 53.325 ;
     RECT  2.16 53.595 20.412 53.865 ;
     RECT  119.34 53.595 140.4 53.865 ;
     RECT  2.16 54.135 20.412 54.27 ;
     RECT  2.16 54.27 19.656 54.405 ;
     RECT  20.304 54.27 20.412 54.405 ;
     RECT  119.34 54.135 140.4 54.405 ;
     RECT  2.16 54.675 20.412 54.945 ;
     RECT  119.34 54.675 140.4 54.945 ;
     RECT  2.16 55.215 20.412 55.485 ;
     RECT  119.34 55.215 140.4 55.485 ;
     RECT  2.16 55.755 20.412 56.025 ;
     RECT  119.34 55.755 140.4 56.025 ;
     RECT  2.16 56.295 9.45 56.43 ;
     RECT  9.774 56.295 20.412 56.43 ;
     RECT  2.16 56.43 20.412 56.565 ;
     RECT  119.34 56.295 140.4 56.565 ;
     RECT  2.16 56.835 20.412 56.97 ;
     RECT  2.16 56.97 10.152 57.105 ;
     RECT  11.286 56.97 13.662 57.105 ;
     RECT  14.634 56.97 20.412 57.105 ;
     RECT  119.34 56.835 140.4 57.105 ;
     RECT  2.16 57.375 20.412 57.645 ;
     RECT  119.34 57.375 140.4 57.645 ;
     RECT  2.16 57.915 20.412 58.185 ;
     RECT  119.34 57.915 140.4 58.185 ;
     RECT  2.16 58.455 20.412 58.725 ;
     RECT  119.34 58.455 140.4 58.725 ;
     RECT  2.16 58.995 20.412 59.265 ;
     RECT  119.34 58.995 140.4 59.265 ;
     RECT  2.16 59.535 20.412 59.805 ;
     RECT  119.34 59.535 140.4 59.805 ;
     RECT  2.16 60.075 17.766 60.21 ;
     RECT  18.36 60.075 20.412 60.21 ;
     RECT  2.16 60.21 20.412 60.345 ;
     RECT  119.34 60.075 140.4 60.345 ;
     RECT  2.16 60.615 20.412 60.885 ;
     RECT  119.34 60.615 140.4 60.885 ;
     RECT  2.16 61.155 20.412 61.425 ;
     RECT  119.34 61.155 140.4 61.425 ;
     RECT  2.16 61.695 20.412 61.965 ;
     RECT  119.34 61.695 140.4 61.965 ;
     RECT  2.16 62.235 20.412 62.505 ;
     RECT  119.34 62.235 140.4 62.505 ;
     RECT  2.16 62.775 20.412 62.91 ;
     RECT  2.16 62.91 10.314 63.045 ;
     RECT  10.746 62.91 20.412 63.045 ;
     RECT  119.34 62.775 140.4 63.045 ;
     RECT  2.16 63.315 20.412 63.585 ;
     RECT  119.34 63.315 140.4 63.585 ;
     RECT  2.16 63.855 7.398 63.99 ;
     RECT  8.748 63.855 14.904 63.99 ;
     RECT  15.228 63.855 20.412 63.99 ;
     RECT  2.16 63.99 20.412 64.125 ;
     RECT  119.34 63.855 140.4 64.125 ;
     RECT  2.16 64.395 20.412 64.53 ;
     RECT  2.16 64.53 7.56 64.665 ;
     RECT  8.046 64.53 16.416 64.665 ;
     RECT  17.442 64.53 20.412 64.665 ;
     RECT  119.34 64.395 140.4 64.665 ;
     RECT  2.16 64.935 20.412 65.205 ;
     RECT  119.34 64.935 140.4 65.205 ;
     RECT  2.16 65.475 20.412 65.61 ;
     RECT  119.34 65.475 140.4 65.61 ;
     RECT  2.16 65.61 46.872 65.745 ;
     RECT  47.358 65.61 140.4 65.745 ;
     RECT  2.16 66.015 29.052 66.15 ;
     RECT  31.536 66.015 40.662 66.15 ;
     RECT  41.256 66.015 140.4 66.15 ;
     RECT  2.16 66.15 47.25 66.285 ;
     RECT  49.086 66.15 140.4 66.285 ;
     RECT  2.16 66.555 140.4 66.825 ;
     RECT  2.16 67.095 12.042 67.23 ;
     RECT  12.366 67.095 140.4 67.23 ;
     RECT  2.16 67.23 140.4 67.365 ;
     RECT  2.16 67.635 140.4 67.77 ;
     RECT  2.16 67.77 11.07 67.905 ;
     RECT  12.906 67.77 140.4 67.905 ;
     RECT  2.16 68.175 140.4 68.445 ;
     RECT  2.16 68.715 36.99 68.85 ;
     RECT  38.07 68.715 140.4 68.85 ;
     RECT  2.16 68.85 40.986 68.985 ;
     RECT  42.012 68.85 49.302 68.985 ;
     RECT  52.056 68.85 140.4 68.985 ;
     RECT  2.16 69.255 140.4 69.525 ;
     RECT  2.16 69.795 29.808 69.93 ;
     RECT  30.348 69.795 140.4 69.93 ;
     RECT  2.16 69.93 140.4 70.065 ;
     RECT  2.16 70.335 140.4 70.605 ;
     RECT  2.16 70.875 140.4 71.145 ;
     RECT  2.16 71.415 45.252 71.55 ;
     RECT  46.44 71.415 140.4 71.55 ;
     RECT  2.16 71.55 140.4 71.685 ;
     RECT  2.16 71.955 140.4 72.225 ;
     RECT  2.16 72.495 34.776 72.63 ;
     RECT  35.802 72.495 45.198 72.63 ;
     RECT  45.576 72.495 140.4 72.63 ;
     RECT  2.16 72.63 34.722 72.765 ;
     RECT  36.072 72.63 140.4 72.765 ;
     RECT  2.16 73.035 140.4 73.305 ;
     RECT  2.16 73.575 140.4 73.845 ;
     RECT  2.16 74.115 140.4 74.385 ;
     RECT  2.16 74.655 140.4 74.925 ;
     RECT  2.16 75.195 45.036 75.33 ;
     RECT  45.738 75.195 140.4 75.33 ;
     RECT  2.16 75.33 140.4 75.465 ;
     RECT  2.16 75.735 140.4 76.005 ;
     RECT  2.16 76.275 140.4 76.545 ;
     RECT  2.16 76.815 140.4 77.085 ;
     RECT  2.16 77.355 140.4 77.625 ;
     RECT  2.16 77.895 140.4 78.165 ;
     RECT  2.16 78.435 140.4 78.705 ;
     RECT  2.16 78.975 140.4 79.245 ;
     RECT  2.16 79.515 140.4 79.785 ;
     RECT  2.16 80.055 140.4 80.325 ;
     RECT  2.16 80.595 140.4 80.865 ;
     RECT  2.16 81.135 140.4 81.405 ;
     RECT  2.16 81.675 140.4 81.945 ;
     RECT  2.16 82.215 140.4 82.485 ;
     RECT  2.16 82.755 140.4 83.025 ;
     RECT  2.16 83.295 140.4 83.565 ;
     RECT  2.16 83.835 140.4 84.105 ;
    LAYER M1 ;
     RECT  2.16 2.151 140.4 20.259 ;
     RECT  22.464 22.464 117.288 63.528 ;
     RECT  2.16 20.259 20.412 65.601 ;
     RECT  119.34 20.259 140.4 65.601 ;
     RECT  2.16 65.601 140.4 84.249 ;
    LAYER M2 ;
     RECT  0.211 37.062 0.247 38.538 ;
     RECT  0.211 39.294 0.247 40.32 ;
     RECT  0.211 43.848 0.247 43.866 ;
     RECT  0.211 35.01 0.535 36.036 ;
     RECT  0.247 36.9 0.535 40.32 ;
     RECT  0.211 41.22 0.535 42.624 ;
     RECT  0.319 31.266 0.571 31.284 ;
     RECT  0.535 34.506 1.579 40.32 ;
     RECT  0.247 43.848 1.651 44.442 ;
     RECT  0.571 31.266 1.723 31.914 ;
     RECT  1.579 33.858 1.723 40.32 ;
     RECT  0.535 41.076 1.723 42.624 ;
     RECT  1.399 30.384 1.975 30.402 ;
     RECT  1.615 27.756 2.16 27.774 ;
     RECT  1.975 29.916 2.16 30.402 ;
     RECT  1.723 31.266 2.16 32.454 ;
     RECT  1.723 33.858 2.16 42.624 ;
     RECT  1.651 43.848 2.16 45.144 ;
     RECT  1.615 49.248 2.16 49.266 ;
     RECT  1.687 50.436 2.16 50.454 ;
     RECT  1.579 51.408 2.16 51.426 ;
     RECT  2.16 2.151 12.523 84.249 ;
     RECT  12.523 2.151 14.179 84.708 ;
     RECT  14.179 2.151 19.615 85.329 ;
     RECT  19.615 1.926 20.155 85.329 ;
     RECT  20.155 1.881 20.412 85.329 ;
     RECT  20.412 48.816 20.435 50.382 ;
     RECT  20.412 56.808 20.435 58.788 ;
     RECT  20.412 52.596 20.471 53.01 ;
     RECT  20.412 59.778 20.471 85.329 ;
     RECT  20.412 47.286 20.507 47.916 ;
     RECT  20.412 55.26 20.507 55.278 ;
     RECT  20.435 57.618 20.507 58.788 ;
     RECT  20.471 60.822 20.507 85.329 ;
     RECT  20.507 60.858 20.651 61.524 ;
     RECT  20.412 1.881 20.687 33.102 ;
     RECT  20.507 47.286 20.687 47.88 ;
     RECT  20.687 1.881 20.795 30.168 ;
     RECT  20.507 62.316 20.795 85.329 ;
     RECT  20.412 38.178 20.939 40.428 ;
     RECT  20.507 57.618 21.011 58.014 ;
     RECT  20.687 31.158 21.083 33.102 ;
     RECT  20.435 48.816 21.083 49.878 ;
     RECT  21.083 48.906 21.119 49.734 ;
     RECT  20.651 60.858 21.119 61.146 ;
     RECT  21.127 1.116 21.163 1.134 ;
     RECT  20.795 1.881 21.163 27.162 ;
     RECT  20.412 42.066 21.163 44.208 ;
     RECT  20.795 28.296 21.227 30.168 ;
     RECT  21.163 1.116 21.263 27.162 ;
     RECT  20.471 59.778 21.263 59.832 ;
     RECT  20.412 45.126 21.271 45.144 ;
     RECT  20.939 38.646 21.299 40.428 ;
     RECT  21.271 45.036 21.299 45.144 ;
     RECT  20.471 52.992 21.299 53.01 ;
     RECT  21.083 31.698 21.307 33.102 ;
     RECT  20.412 33.966 21.307 35.874 ;
     RECT  21.299 39.096 21.307 40.428 ;
     RECT  20.795 62.676 21.371 85.329 ;
     RECT  21.163 42.066 21.407 44.289 ;
     RECT  21.263 59.778 21.407 59.796 ;
     RECT  21.263 1.116 21.415 26.928 ;
     RECT  21.307 39.096 21.415 40.464 ;
     RECT  20.412 41.256 21.415 41.274 ;
     RECT  21.407 43.074 21.415 44.289 ;
     RECT  21.299 45.036 21.415 45.054 ;
     RECT  20.412 46.08 21.443 46.368 ;
     RECT  21.415 43.074 21.479 45.054 ;
     RECT  20.687 47.286 21.487 47.61 ;
     RECT  21.307 31.698 21.515 35.874 ;
     RECT  21.119 61.011 21.515 61.146 ;
     RECT  21.415 1.026 21.523 26.928 ;
     RECT  21.487 46.971 21.523 47.61 ;
     RECT  21.515 31.698 21.551 32.904 ;
     RECT  20.412 37.026 21.551 37.422 ;
     RECT  21.415 39.096 21.551 41.274 ;
     RECT  21.479 43.686 21.551 45.054 ;
     RECT  21.371 63.288 21.559 85.329 ;
     RECT  21.407 42.066 21.587 42.282 ;
     RECT  21.551 43.686 21.587 44.982 ;
     RECT  21.515 33.696 21.623 35.874 ;
     RECT  21.551 39.096 21.623 40.464 ;
     RECT  21.587 43.686 21.623 44.208 ;
     RECT  21.523 46.971 21.623 47.682 ;
     RECT  21.227 28.296 21.659 29.664 ;
     RECT  21.551 31.77 21.659 32.364 ;
     RECT  21.551 37.026 21.659 37.224 ;
     RECT  21.623 39.096 21.659 40.428 ;
     RECT  21.587 42.066 21.659 42.084 ;
     RECT  21.623 47.592 21.659 47.682 ;
     RECT  21.119 48.906 21.659 49.689 ;
     RECT  21.659 28.296 21.695 28.818 ;
     RECT  21.623 35.046 21.695 35.874 ;
     RECT  20.412 51.714 21.731 51.732 ;
     RECT  21.443 46.08 22.171 46.179 ;
     RECT  21.523 0.531 22.207 26.928 ;
     RECT  21.551 41.256 22.279 41.274 ;
     RECT  21.011 57.996 22.279 58.014 ;
     RECT  20.507 58.77 22.279 58.788 ;
     RECT  22.207 0.531 22.464 27.549 ;
     RECT  21.695 28.296 22.464 28.314 ;
     RECT  21.659 29.61 22.464 29.664 ;
     RECT  21.659 31.77 22.464 31.788 ;
     RECT  21.623 34.236 22.464 34.254 ;
     RECT  21.695 35.046 22.464 35.334 ;
     RECT  21.659 37.026 22.464 37.044 ;
     RECT  21.659 39.096 22.464 39.654 ;
     RECT  21.659 40.41 22.464 40.428 ;
     RECT  22.279 41.256 22.464 41.94 ;
     RECT  21.623 44.154 22.464 44.208 ;
     RECT  22.171 46.08 22.464 46.224 ;
     RECT  21.659 48.906 22.464 48.996 ;
     RECT  22.279 56.421 22.464 56.439 ;
     RECT  22.279 57.312 22.464 58.014 ;
     RECT  22.279 58.77 22.464 59.526 ;
     RECT  21.515 61.128 22.464 61.146 ;
     RECT  21.559 63.288 22.464 85.374 ;
     RECT  22.464 0.531 24.035 85.374 ;
     RECT  24.035 65.142 24.575 85.374 ;
     RECT  24.575 65.178 24.647 85.374 ;
     RECT  24.035 0.531 24.691 64.35 ;
     RECT  24.691 0.216 24.763 64.35 ;
     RECT  24.763 0.144 24.863 64.35 ;
     RECT  24.863 0.216 25.079 64.35 ;
     RECT  25.079 0.531 25.223 64.35 ;
     RECT  24.647 65.286 25.439 85.374 ;
     RECT  25.439 65.412 25.655 85.374 ;
     RECT  25.655 65.556 26.267 85.374 ;
     RECT  25.223 0.531 27.967 63.528 ;
     RECT  27.967 0.216 28.075 63.528 ;
     RECT  26.267 65.601 29.263 85.374 ;
     RECT  20.155 86.274 29.263 86.292 ;
     RECT  29.263 65.601 29.399 86.292 ;
     RECT  28.075 0.144 30.947 63.528 ;
     RECT  29.399 65.601 31.099 85.374 ;
     RECT  30.947 0.216 31.675 63.528 ;
     RECT  31.675 0.144 32.387 63.528 ;
     RECT  31.099 65.25 32.503 85.374 ;
     RECT  32.503 65.25 33.143 85.518 ;
     RECT  29.399 86.274 33.619 86.292 ;
     RECT  33.619 86.202 33.647 86.292 ;
     RECT  33.647 86.202 33.863 86.22 ;
     RECT  33.143 65.25 34.519 85.284 ;
     RECT  32.387 0.531 34.627 63.528 ;
     RECT  34.519 65.25 34.871 85.518 ;
     RECT  34.627 0.144 36.455 63.528 ;
     RECT  34.871 65.25 36.743 85.284 ;
     RECT  36.455 0.18 37.183 63.528 ;
     RECT  37.183 0.144 37.535 63.528 ;
     RECT  37.535 0.216 38.515 63.528 ;
     RECT  38.515 0.144 38.615 63.528 ;
     RECT  38.615 0.216 39.451 63.528 ;
     RECT  36.743 65.25 40.343 85.248 ;
     RECT  40.343 65.25 40.919 84.789 ;
     RECT  40.919 65.25 41.063 84.708 ;
     RECT  25.223 64.332 41.351 64.35 ;
     RECT  39.451 0.144 41.575 63.528 ;
     RECT  41.575 0.072 42.151 63.528 ;
     RECT  41.063 65.25 42.503 84.636 ;
     RECT  42.503 65.25 47.443 84.249 ;
     RECT  47.443 65.25 47.687 84.294 ;
     RECT  42.151 0.036 73.607 63.528 ;
     RECT  73.607 0.45 74.399 63.528 ;
     RECT  74.399 0.486 106.043 63.528 ;
     RECT  106.043 0.531 117.288 63.528 ;
     RECT  117.288 0.531 117.419 22.419 ;
     RECT  117.288 23.4 117.419 24.354 ;
     RECT  117.419 0.531 117.887 21.222 ;
     RECT  117.419 21.978 117.923 22.419 ;
     RECT  117.419 24.336 117.923 24.354 ;
     RECT  117.419 23.4 117.959 23.418 ;
     RECT  117.288 25.641 117.995 26.784 ;
     RECT  117.887 0.531 118.031 21.15 ;
     RECT  117.923 21.978 118.031 22.374 ;
     RECT  117.288 34.092 118.039 62.694 ;
     RECT  118.031 21.978 118.247 22.068 ;
     RECT  117.995 26.766 118.391 26.784 ;
     RECT  117.995 25.641 118.427 25.659 ;
     RECT  118.031 0.531 119.34 21.114 ;
     RECT  118.247 21.978 119.34 21.996 ;
     RECT  118.039 34.092 119.34 63 ;
     RECT  47.687 65.25 119.34 84.249 ;
     RECT  119.34 0.531 119.903 84.249 ;
     RECT  119.903 1.026 120.083 84.249 ;
     RECT  120.083 1.026 120.371 1.089 ;
     RECT  120.371 1.026 120.515 1.044 ;
     RECT  120.083 2.151 140.4 84.249 ;
     RECT  140.4 52.956 141.935 52.974 ;
    LAYER M3 ;
     RECT  42.156 0.031 42.174 0.067 ;
     RECT  41.58 0.067 42.174 0.108 ;
     RECT  42.948 0.103 42.966 0.108 ;
     RECT  71.532 0.067 71.55 0.108 ;
     RECT  73.584 0.031 73.602 0.139 ;
     RECT  24.48 0.108 61.218 0.175 ;
     RECT  24.48 0.175 61.578 0.187 ;
     RECT  73.584 0.139 74.25 0.445 ;
     RECT  63.864 0.103 63.882 0.481 ;
     RECT  21.06 0.139 21.078 0.526 ;
     RECT  23.94 0.187 61.578 0.571 ;
     RECT  70.488 0.108 71.55 0.619 ;
     RECT  21.06 0.526 21.546 0.811 ;
     RECT  66.528 0.108 67.842 0.811 ;
     RECT  63.288 0.481 63.882 0.841 ;
     RECT  73.584 0.445 74.394 0.877 ;
     RECT  70.38 0.619 71.55 0.913 ;
     RECT  21.06 0.811 22.266 1.003 ;
     RECT  23.328 0.571 61.578 1.003 ;
     RECT  62.928 0.841 63.882 1.021 ;
     RECT  119.88 0.526 119.898 1.021 ;
     RECT  70.38 0.913 71.586 1.051 ;
     RECT  119.88 1.021 120.51 1.111 ;
     RECT  21.06 1.003 61.578 1.147 ;
     RECT  65.52 0.526 65.538 1.147 ;
     RECT  72.756 1.387 72.774 1.417 ;
     RECT  72.432 1.417 72.774 1.483 ;
     RECT  73.584 0.877 74.574 1.483 ;
     RECT  62.928 1.021 64.53 1.579 ;
     RECT  65.448 1.147 65.538 1.579 ;
     RECT  21.06 1.147 61.65 1.723 ;
     RECT  62.928 1.579 65.538 1.723 ;
     RECT  66.528 0.811 68.31 1.723 ;
     RECT  69.048 1.651 69.066 1.723 ;
     RECT  70.02 1.051 71.586 1.723 ;
     RECT  72.432 1.483 74.574 1.723 ;
     RECT  20.088 1.051 20.106 1.771 ;
     RECT  21.06 1.723 62.154 1.771 ;
     RECT  20.088 1.771 62.154 1.831 ;
     RECT  62.928 1.723 69.066 1.831 ;
     RECT  70.02 1.723 74.574 1.867 ;
     RECT  20.088 1.831 69.066 1.921 ;
     RECT  87.912 0.985 87.93 1.957 ;
     RECT  69.84 1.867 74.574 1.993 ;
     RECT  69.84 1.993 74.646 2.101 ;
     RECT  76.932 1.759 76.95 2.129 ;
     RECT  77.94 1.759 77.958 2.143 ;
     RECT  89.496 1.651 89.514 2.143 ;
     RECT  99.18 2.101 99.198 2.143 ;
     RECT  119.808 1.111 120.51 2.143 ;
     RECT  69.84 2.101 74.718 2.191 ;
     RECT  19.62 1.921 69.066 2.251 ;
     RECT  69.84 2.191 75.042 2.251 ;
     RECT  19.62 2.251 75.042 2.255 ;
     RECT  2.415 2.143 2.505 2.413 ;
     RECT  7.815 2.143 7.905 2.413 ;
     RECT  13.215 2.143 13.305 2.413 ;
     RECT  18.615 2.143 18.705 2.413 ;
     RECT  77.94 2.143 78.105 2.413 ;
     RECT  83.415 2.143 83.505 2.413 ;
     RECT  94.215 2.143 94.305 2.413 ;
     RECT  99.18 2.143 99.705 2.413 ;
     RECT  105.015 2.143 105.105 2.413 ;
     RECT  110.415 2.143 110.505 2.413 ;
     RECT  115.815 2.143 115.905 2.413 ;
     RECT  119.808 2.143 121.305 2.413 ;
     RECT  126.615 2.143 126.705 2.413 ;
     RECT  132.015 2.143 132.105 2.413 ;
     RECT  137.415 2.143 137.505 2.413 ;
     RECT  83.415 2.413 83.697 2.569 ;
     RECT  77.94 2.413 78.297 2.635 ;
     RECT  88.815 2.143 89.514 2.635 ;
     RECT  110.415 2.413 110.697 2.635 ;
     RECT  77.904 2.635 78.297 2.731 ;
     RECT  82.116 2.299 82.134 2.731 ;
     RECT  83.415 2.569 83.862 2.731 ;
     RECT  110.304 2.635 110.697 2.765 ;
     RECT  114.588 2.587 114.606 2.765 ;
     RECT  76.392 2.533 76.446 2.779 ;
     RECT  82.116 2.731 83.862 2.839 ;
     RECT  77.904 2.731 78.678 2.861 ;
     RECT  87.732 1.957 87.93 2.875 ;
     RECT  88.704 2.635 89.514 2.875 ;
     RECT  86.652 2.335 86.67 3.001 ;
     RECT  19.728 2.255 75.042 3.019 ;
     RECT  99.18 2.413 99.897 3.029 ;
     RECT  81.54 2.839 83.862 3.037 ;
     RECT  119.808 2.413 121.497 3.037 ;
     RECT  77.904 2.861 78.642 3.073 ;
     RECT  19.728 3.019 75.222 3.109 ;
     RECT  92.916 3.037 92.934 3.109 ;
     RECT  81.54 3.037 84.474 3.137 ;
     RECT  81.54 3.137 84.402 3.145 ;
     RECT  18.615 2.413 18.897 3.181 ;
     RECT  19.728 3.109 75.33 3.181 ;
     RECT  86.652 3.001 86.706 3.181 ;
     RECT  80.964 3.145 84.402 3.209 ;
     RECT  18.615 3.181 75.33 3.211 ;
     RECT  18.615 3.211 75.366 3.259 ;
     RECT  115.815 2.413 116.097 3.271 ;
     RECT  18.504 3.259 75.366 3.299 ;
     RECT  86.652 3.181 86.814 3.299 ;
     RECT  117.828 2.263 117.846 3.307 ;
     RECT  80.964 3.209 84.33 3.341 ;
     RECT  87.732 2.875 89.514 3.343 ;
     RECT  18.615 3.299 75.366 3.371 ;
     RECT  92.916 3.109 93.078 3.371 ;
     RECT  18.615 3.371 75.078 3.437 ;
     RECT  18.615 3.437 74.934 3.443 ;
     RECT  92.988 3.371 93.078 3.451 ;
     RECT  94.215 2.413 94.497 3.451 ;
     RECT  96.408 3.037 96.426 3.451 ;
     RECT  97.524 3.343 97.542 3.451 ;
     RECT  96.408 3.451 97.542 3.479 ;
     RECT  76.356 2.779 76.446 3.541 ;
     RECT  92.988 3.451 94.497 3.541 ;
     RECT  77.544 3.073 78.642 3.569 ;
     RECT  92.088 3.451 92.106 3.569 ;
     RECT  92.988 3.541 94.734 3.569 ;
     RECT  96.408 3.479 96.93 3.569 ;
     RECT  106.02 0.481 106.038 3.569 ;
     RECT  87.732 3.343 89.766 3.613 ;
     RECT  90.612 3.577 90.702 3.613 ;
     RECT  119.484 3.037 121.497 3.613 ;
     RECT  114.732 3.577 114.75 3.649 ;
     RECT  87.732 3.613 90.702 3.677 ;
     RECT  87.732 3.677 90.666 3.685 ;
     RECT  114.588 3.649 114.75 3.685 ;
     RECT  94.068 3.569 94.734 3.713 ;
     RECT  76.32 3.541 76.446 3.721 ;
     RECT  115.815 3.271 116.298 3.721 ;
     RECT  77.94 3.569 78.642 3.749 ;
     RECT  114.588 3.685 114.822 3.839 ;
     RECT  18.615 3.443 74.718 3.911 ;
     RECT  114.588 3.839 114.75 3.911 ;
     RECT  117.828 3.307 118.386 3.919 ;
     RECT  119.196 3.613 121.497 3.919 ;
     RECT  76.032 3.721 76.446 3.947 ;
     RECT  92.988 3.569 93.006 3.947 ;
     RECT  114.588 3.911 114.606 3.947 ;
     RECT  117.828 3.919 121.497 3.955 ;
     RECT  13.215 2.413 13.497 3.979 ;
     RECT  80.964 3.341 83.697 4.081 ;
     RECT  70.2 3.911 74.718 4.109 ;
     RECT  76.356 3.947 76.446 4.109 ;
     RECT  86.652 3.299 86.742 4.123 ;
     RECT  11.484 1.675 11.502 4.171 ;
     RECT  80.712 4.081 83.697 4.171 ;
     RECT  84.492 3.991 84.582 4.171 ;
     RECT  18.615 3.911 69.426 4.189 ;
     RECT  79.956 2.371 79.974 4.225 ;
     RECT  80.712 4.171 84.582 4.225 ;
     RECT  79.956 4.225 84.582 4.253 ;
     RECT  82.116 4.253 84.582 4.261 ;
     RECT  87.66 3.685 90.666 4.289 ;
     RECT  87.66 4.289 90.522 4.351 ;
     RECT  86.472 4.123 86.742 4.363 ;
     RECT  87.48 4.351 90.522 4.363 ;
     RECT  70.2 4.109 73.746 4.379 ;
     RECT  77.94 3.749 78.498 4.379 ;
     RECT  70.272 4.379 71.118 4.487 ;
     RECT  86.472 4.363 90.522 4.487 ;
     RECT  86.472 4.487 87.138 4.493 ;
     RECT  117.576 3.955 121.497 4.495 ;
     RECT  79.956 4.253 81.27 4.531 ;
     RECT  82.116 4.261 84.69 4.531 ;
     RECT  71.892 4.379 73.746 4.541 ;
     RECT  78.015 4.379 78.462 4.559 ;
     RECT  86.472 4.493 86.886 4.603 ;
     RECT  82.116 4.531 84.726 4.621 ;
     RECT  85.788 4.603 86.886 4.621 ;
     RECT  74.7 4.109 74.718 4.651 ;
     RECT  75.492 4.621 75.582 4.651 ;
     RECT  85.716 4.621 86.886 4.657 ;
     RECT  117.576 4.495 121.554 4.657 ;
     RECT  18.324 4.189 69.426 4.721 ;
     RECT  20.268 4.721 69.426 4.729 ;
     RECT  105.015 2.413 105.297 4.729 ;
     RECT  11.484 4.171 12.15 4.747 ;
     RECT  13.215 3.979 13.59 4.747 ;
     RECT  76.392 4.109 76.446 4.765 ;
     RECT  77.22 4.693 77.238 4.765 ;
     RECT  13.176 4.747 13.59 4.801 ;
     RECT  70.848 4.487 71.118 4.829 ;
     RECT  20.268 4.729 69.462 4.891 ;
     RECT  94.068 3.713 94.497 4.891 ;
     RECT  85.68 4.657 86.886 4.927 ;
     RECT  99.615 3.029 99.897 4.927 ;
     RECT  13.104 4.801 13.914 4.955 ;
     RECT  72 4.541 73.746 4.955 ;
     RECT  10.836 4.747 12.15 4.973 ;
     RECT  85.572 4.927 86.886 4.973 ;
     RECT  14.832 4.027 14.85 4.991 ;
     RECT  72.468 4.955 73.746 4.999 ;
     RECT  74.7 4.651 75.582 4.999 ;
     RECT  70.92 4.829 71.118 5.027 ;
     RECT  4.752 4.693 4.77 5.035 ;
     RECT  5.688 4.987 5.706 5.035 ;
     RECT  79.524 4.531 81.27 5.035 ;
     RECT  4.752 5.035 5.706 5.063 ;
     RECT  20.268 4.891 69.498 5.063 ;
     RECT  4.752 5.063 5.454 5.069 ;
     RECT  72.468 4.999 75.582 5.071 ;
     RECT  76.392 4.765 77.238 5.071 ;
     RECT  85.572 4.973 86.742 5.071 ;
     RECT  13.104 4.955 13.878 5.099 ;
     RECT  82.116 4.621 84.798 5.099 ;
     RECT  10.944 4.973 12.15 5.117 ;
     RECT  96.624 3.569 96.93 5.131 ;
     RECT  82.116 5.099 82.314 5.161 ;
     RECT  92.34 4.459 92.358 5.161 ;
     RECT  94.032 4.891 94.497 5.161 ;
     RECT  96.624 5.131 97.002 5.161 ;
     RECT  18.324 4.721 18.954 5.189 ;
     RECT  72.468 5.071 77.238 5.197 ;
     RECT  78.015 4.559 78.39 5.197 ;
     RECT  87.912 4.487 90.522 5.197 ;
     RECT  92.16 5.161 92.358 5.227 ;
     RECT  93.132 4.891 93.15 5.227 ;
     RECT  106.38 3.721 106.398 5.227 ;
     RECT  92.16 5.227 93.15 5.233 ;
     RECT  93.888 5.161 94.497 5.233 ;
     RECT  87.912 5.197 90.882 5.269 ;
     RECT  92.16 5.233 94.497 5.269 ;
     RECT  71.1 5.027 71.118 5.305 ;
     RECT  72.468 5.197 78.39 5.305 ;
     RECT  79.2 5.035 81.27 5.305 ;
     RECT  82.08 5.161 82.314 5.305 ;
     RECT  87.912 5.269 90.918 5.305 ;
     RECT  92.16 5.269 94.77 5.305 ;
     RECT  95.868 5.161 97.002 5.305 ;
     RECT  98.028 4.261 98.046 5.305 ;
     RECT  87.912 5.305 94.914 5.341 ;
     RECT  106.38 5.227 106.686 5.357 ;
     RECT  114.66 5.323 114.678 5.371 ;
     RECT  83.232 5.099 84.798 5.419 ;
     RECT  85.536 5.071 86.742 5.419 ;
     RECT  95.868 5.305 98.046 5.419 ;
     RECT  71.1 5.305 71.19 5.467 ;
     RECT  101.016 5.371 101.034 5.501 ;
     RECT  106.38 5.357 106.614 5.501 ;
     RECT  114.588 5.371 114.678 5.501 ;
     RECT  18.615 5.189 18.954 5.515 ;
     RECT  87.804 5.341 94.914 5.515 ;
     RECT  99.576 4.927 99.897 5.563 ;
     RECT  114.66 5.501 114.678 5.597 ;
     RECT  71.1 5.467 71.226 5.611 ;
     RECT  95.868 5.419 98.154 5.611 ;
     RECT  99.252 5.563 99.897 5.611 ;
     RECT  101.808 5.563 102.222 5.611 ;
     RECT  17.172 5.707 17.298 5.737 ;
     RECT  70.02 5.467 70.182 5.737 ;
     RECT  95.868 5.611 100.206 5.801 ;
     RECT  17.1 5.737 17.298 5.803 ;
     RECT  70.02 5.737 70.218 5.803 ;
     RECT  117.54 4.657 121.554 5.803 ;
     RECT  20.268 5.063 69.21 5.809 ;
     RECT  70.02 5.803 70.326 5.809 ;
     RECT  101.808 5.611 102.654 5.809 ;
     RECT  20.268 5.809 70.326 5.845 ;
     RECT  71.1 5.611 71.37 5.845 ;
     RECT  72.468 5.305 82.314 5.845 ;
     RECT  101.808 5.809 103.23 5.845 ;
     RECT  87.66 5.515 94.914 5.851 ;
     RECT  95.868 5.801 100.098 5.851 ;
     RECT  20.268 5.845 71.37 5.881 ;
     RECT  72.468 5.845 82.386 5.881 ;
     RECT  83.232 5.419 86.742 5.881 ;
     RECT  87.66 5.851 100.098 5.881 ;
     RECT  87.624 5.881 100.098 5.885 ;
     RECT  114.696 5.707 114.714 5.885 ;
     RECT  72.468 5.881 82.422 6.007 ;
     RECT  83.16 5.881 86.886 6.007 ;
     RECT  20.268 5.881 71.73 6.035 ;
     RECT  15.048 5.305 15.066 6.079 ;
     RECT  11.412 5.117 12.15 6.151 ;
     RECT  13.215 5.099 13.878 6.151 ;
     RECT  72.468 6.007 86.886 6.151 ;
     RECT  87.624 5.885 99.99 6.151 ;
     RECT  101.7 5.845 103.23 6.179 ;
     RECT  72.468 6.151 99.99 6.269 ;
     RECT  100.872 5.947 100.926 6.269 ;
     RECT  71.496 6.035 71.73 6.277 ;
     RECT  72.468 6.269 99.897 6.277 ;
     RECT  18.615 5.515 18.99 6.349 ;
     RECT  100.908 6.269 100.926 6.379 ;
     RECT  101.7 6.179 103.014 6.379 ;
     RECT  18.615 6.349 19.026 6.385 ;
     RECT  20.268 6.035 70.686 6.385 ;
     RECT  106.38 5.501 106.398 6.475 ;
     RECT  117.54 5.803 121.59 6.511 ;
     RECT  105.015 4.729 105.606 6.523 ;
     RECT  100.908 6.379 103.014 6.539 ;
     RECT  117.54 6.511 121.662 6.547 ;
     RECT  17.1 5.803 17.334 6.583 ;
     RECT  106.38 6.475 106.614 6.605 ;
     RECT  11.412 6.151 13.878 6.619 ;
     RECT  14.94 6.079 15.066 6.619 ;
     RECT  104.904 6.523 105.606 6.619 ;
     RECT  106.38 6.605 106.542 6.619 ;
     RECT  11.412 6.619 15.066 6.691 ;
     RECT  17.1 6.583 17.622 6.691 ;
     RECT  11.412 6.691 15.138 6.811 ;
     RECT  103.752 6.811 103.878 6.817 ;
     RECT  18.615 6.385 70.686 6.893 ;
     RECT  103.752 6.817 104.022 6.925 ;
     RECT  11.412 6.811 15.282 6.961 ;
     RECT  16.884 6.691 17.622 6.961 ;
     RECT  63.648 6.893 70.686 6.961 ;
     RECT  71.496 6.277 99.897 6.961 ;
     RECT  101.952 6.539 103.014 6.961 ;
     RECT  103.752 6.925 104.13 6.961 ;
     RECT  104.904 6.619 106.542 6.961 ;
     RECT  63.648 6.961 70.722 7.159 ;
     RECT  71.46 6.961 99.897 7.159 ;
     RECT  11.412 6.961 17.658 7.231 ;
     RECT  18.615 6.893 62.91 7.231 ;
     RECT  110.415 2.765 110.697 7.231 ;
     RECT  63.648 7.159 99.897 7.243 ;
     RECT  110.415 7.231 110.79 7.277 ;
     RECT  10.836 7.231 62.91 7.349 ;
     RECT  114.588 6.475 114.606 7.373 ;
     RECT  100.908 6.539 101.034 7.429 ;
     RECT  101.952 6.961 106.542 7.429 ;
     RECT  100.908 7.429 106.542 7.465 ;
     RECT  25.452 7.349 62.91 7.627 ;
     RECT  63.648 7.243 99.99 7.627 ;
     RECT  115.815 3.721 116.514 7.675 ;
     RECT  117.324 6.547 121.662 7.675 ;
     RECT  10.836 7.349 24.498 7.699 ;
     RECT  10.728 7.699 24.498 7.735 ;
     RECT  25.452 7.627 99.99 7.735 ;
     RECT  100.8 7.465 106.542 7.735 ;
     RECT  7.815 2.413 8.097 7.771 ;
     RECT  10.656 7.735 24.498 7.771 ;
     RECT  7.815 7.771 9.594 7.933 ;
     RECT  25.452 7.735 106.542 7.933 ;
     RECT  7.272 7.933 9.594 7.963 ;
     RECT  6.3 7.819 6.318 7.969 ;
     RECT  7.272 7.963 9.63 7.969 ;
     RECT  108.252 7.897 108.27 8.041 ;
     RECT  6.3 7.969 9.63 8.131 ;
     RECT  10.548 7.771 24.498 8.131 ;
     RECT  25.452 7.933 106.758 8.131 ;
     RECT  108.216 8.041 108.918 8.167 ;
     RECT  107.928 8.167 108.918 8.275 ;
     RECT  4.752 5.069 4.77 8.401 ;
     RECT  107.82 8.275 108.918 8.473 ;
     RECT  4.752 8.401 5.166 8.509 ;
     RECT  6.3 8.131 106.758 8.509 ;
     RECT  107.82 8.473 109.062 8.581 ;
     RECT  3.96 8.581 3.978 8.671 ;
     RECT  107.82 8.581 109.494 8.699 ;
     RECT  4.752 8.509 106.758 8.735 ;
     RECT  86.76 8.735 106.758 8.827 ;
     RECT  107.82 8.699 109.062 8.827 ;
     RECT  3.42 8.671 3.978 8.851 ;
     RECT  4.752 8.735 86.022 8.851 ;
     RECT  110.415 7.277 110.697 9.049 ;
     RECT  110.376 9.049 110.697 9.211 ;
     RECT  3.42 8.851 86.022 9.275 ;
     RECT  3.636 9.275 86.022 9.347 ;
     RECT  5.508 9.347 86.022 9.499 ;
     RECT  86.76 8.827 109.062 9.499 ;
     RECT  5.508 9.499 109.062 9.617 ;
     RECT  5.652 9.617 109.062 9.931 ;
     RECT  3.636 9.347 4.77 10.129 ;
     RECT  5.652 9.931 109.206 10.193 ;
     RECT  6.804 10.193 109.206 10.205 ;
     RECT  2.415 2.413 2.697 10.219 ;
     RECT  3.42 10.129 4.77 10.219 ;
     RECT  109.944 9.211 110.697 10.363 ;
     RECT  2.415 10.219 4.77 10.471 ;
     RECT  5.652 10.193 6.066 10.471 ;
     RECT  7.272 10.205 109.206 10.603 ;
     RECT  109.944 10.363 110.97 10.603 ;
     RECT  7.272 10.603 110.97 10.733 ;
     RECT  109.836 10.733 110.97 10.769 ;
     RECT  2.415 10.471 6.066 11.083 ;
     RECT  2.415 11.083 6.498 11.227 ;
     RECT  7.272 10.733 109.062 11.227 ;
     RECT  2.415 11.227 109.062 11.551 ;
     RECT  109.836 10.769 110.862 11.551 ;
     RECT  2.415 11.551 110.862 11.669 ;
     RECT  2.415 11.669 106.758 11.705 ;
     RECT  111.852 11.677 111.87 11.749 ;
     RECT  107.784 11.669 110.862 11.821 ;
     RECT  111.78 11.749 111.87 11.939 ;
     RECT  114.588 11.803 114.606 11.981 ;
     RECT  107.784 11.821 110.898 12.427 ;
     RECT  107.64 12.427 110.898 12.479 ;
     RECT  111.852 11.939 111.87 12.479 ;
     RECT  102.564 11.705 106.758 12.715 ;
     RECT  102.564 12.715 106.794 12.763 ;
     RECT  2.415 11.705 101.754 12.829 ;
     RECT  102.528 12.763 106.794 12.829 ;
     RECT  107.64 12.479 110.754 12.829 ;
     RECT  2.415 12.829 110.754 13.261 ;
     RECT  2.415 13.261 111.222 13.433 ;
     RECT  2.415 13.433 111.15 13.559 ;
     RECT  2.415 13.559 110.697 13.973 ;
     RECT  2.415 13.973 47.502 14.243 ;
     RECT  48.24 13.973 110.697 14.791 ;
     RECT  2.415 14.243 47.358 14.989 ;
     RECT  48.24 14.791 110.79 14.989 ;
     RECT  2.415 14.989 110.826 15.331 ;
     RECT  2.415 15.331 111.222 16.411 ;
     RECT  2.415 16.411 111.69 16.709 ;
     RECT  2.415 16.709 111.402 17.117 ;
     RECT  107.496 17.117 111.402 17.339 ;
     RECT  2.415 17.117 32.31 17.447 ;
     RECT  31.464 17.447 32.31 17.851 ;
     RECT  33.084 17.117 106.686 17.851 ;
     RECT  107.496 17.339 111.222 17.879 ;
     RECT  107.496 17.879 111.078 18.221 ;
     RECT  31.464 17.851 106.686 18.235 ;
     RECT  107.496 18.221 110.697 18.235 ;
     RECT  31.464 18.235 110.697 18.317 ;
     RECT  2.415 17.447 30.69 18.499 ;
     RECT  31.464 18.317 98.514 18.499 ;
     RECT  2.415 18.499 98.514 19.103 ;
     RECT  52.272 19.103 98.514 19.111 ;
     RECT  99.252 18.317 110.697 19.111 ;
     RECT  52.272 19.111 110.697 19.139 ;
     RECT  52.272 19.139 106.614 19.229 ;
     RECT  107.424 19.139 109.494 19.229 ;
     RECT  55.368 19.229 91.782 19.277 ;
     RECT  107.424 19.229 107.442 19.277 ;
     RECT  108.468 19.229 109.35 19.301 ;
     RECT  52.272 19.229 54.594 19.325 ;
     RECT  92.772 19.229 105.297 19.337 ;
     RECT  2.415 19.103 51.498 19.373 ;
     RECT  60.444 19.277 91.782 19.373 ;
     RECT  93.744 19.337 105.297 19.373 ;
     RECT  106.2 19.229 106.218 19.373 ;
     RECT  70.524 19.373 91.674 19.421 ;
     RECT  26.856 19.373 51.498 19.499 ;
     RECT  52.704 19.325 54.594 19.499 ;
     RECT  60.444 19.373 69.75 19.499 ;
     RECT  70.524 19.421 91.638 19.499 ;
     RECT  93.78 19.373 105.297 19.499 ;
     RECT  108.468 19.301 108.882 19.499 ;
     RECT  52.812 19.499 54.486 19.517 ;
     RECT  26.856 19.499 27.846 19.535 ;
     RECT  69.372 19.499 69.606 19.535 ;
     RECT  71.064 19.499 80.406 19.565 ;
     RECT  95.832 19.499 98.226 19.565 ;
     RECT  99.612 19.499 105.297 19.571 ;
     RECT  54.432 19.517 54.486 19.679 ;
     RECT  60.444 19.499 68.31 19.757 ;
     RECT  26.856 19.535 27.414 19.769 ;
     RECT  55.368 19.277 59.706 19.769 ;
     RECT  71.064 19.565 77.094 19.769 ;
     RECT  81.468 19.499 89.478 19.769 ;
     RECT  95.832 19.565 97.65 19.769 ;
     RECT  61.344 19.757 68.31 19.805 ;
     RECT  72.504 19.769 73.71 19.805 ;
     RECT  81.468 19.769 82.278 19.805 ;
     RECT  93.78 19.499 94.95 19.805 ;
     RECT  55.368 19.769 59.67 19.841 ;
     RECT  66.96 19.805 68.31 19.841 ;
     RECT  90.504 19.499 91.638 19.853 ;
     RECT  28.836 19.499 51.462 19.877 ;
     RECT  74.556 19.769 77.094 19.877 ;
     RECT  81.972 19.805 82.062 19.877 ;
     RECT  93.816 19.805 94.95 19.877 ;
     RECT  61.344 19.805 65.934 19.901 ;
     RECT  83.415 19.769 89.478 19.901 ;
     RECT  55.368 19.841 59.022 19.913 ;
     RECT  71.064 19.769 71.658 19.913 ;
     RECT  75.744 19.877 77.094 19.913 ;
     RECT  78.015 19.565 80.406 19.913 ;
     RECT  83.415 19.901 89.37 19.913 ;
     RECT  99.612 19.571 101.25 19.913 ;
     RECT  110.415 19.139 110.697 19.915 ;
     RECT  2.415 19.373 26.046 19.949 ;
     RECT  28.944 19.877 51.462 19.949 ;
     RECT  90.504 19.853 91.422 19.949 ;
     RECT  101.988 19.571 105.297 19.949 ;
     RECT  110.304 19.915 110.697 19.949 ;
     RECT  114.588 19.819 114.606 19.949 ;
     RECT  67.215 19.841 68.31 19.997 ;
     RECT  72.615 19.805 72.99 19.997 ;
     RECT  78.015 19.913 78.297 19.997 ;
     RECT  83.415 19.913 86.706 19.997 ;
     RECT  99.615 19.913 101.25 19.997 ;
     RECT  110.415 19.949 110.697 19.997 ;
     RECT  115.815 7.675 121.662 19.997 ;
     RECT  28.944 19.949 29.862 20.039 ;
     RECT  30.672 19.949 44.01 20.039 ;
     RECT  83.607 19.997 86.706 20.039 ;
     RECT  87.552 19.913 89.097 20.039 ;
     RECT  95.904 19.769 97.65 20.039 ;
     RECT  99.807 19.997 101.25 20.039 ;
     RECT  101.988 19.949 102.366 20.039 ;
     RECT  103.14 19.949 105.297 20.039 ;
     RECT  27.324 19.769 27.414 20.045 ;
     RECT  99.807 20.039 100.35 20.045 ;
     RECT  95.904 20.039 96.534 20.075 ;
     RECT  101.988 20.039 102.006 20.075 ;
     RECT  94.176 19.877 94.95 20.093 ;
     RECT  30.708 20.039 44.01 20.111 ;
     RECT  83.607 20.039 86.454 20.141 ;
     RECT  45.036 19.949 51.462 20.183 ;
     RECT  83.607 20.141 86.202 20.189 ;
     RECT  61.344 19.901 64.602 20.219 ;
     RECT  75.744 19.913 75.762 20.219 ;
     RECT  76.968 19.913 77.094 20.219 ;
     RECT  30.708 20.111 37.494 20.237 ;
     RECT  47.34 20.183 51.462 20.237 ;
     RECT  78.207 19.997 78.297 20.267 ;
     RECT  83.607 20.189 84.906 20.267 ;
     RECT  87.696 20.039 89.097 20.267 ;
     RECT  99.807 20.045 99.897 20.267 ;
     RECT  105.207 20.039 105.297 20.267 ;
     RECT  110.607 19.997 110.697 20.267 ;
     RECT  116.007 19.997 121.662 20.267 ;
     RECT  76.968 20.219 77.022 20.285 ;
     RECT  83.772 20.267 84.906 20.285 ;
     RECT  87.696 20.267 88.326 20.285 ;
     RECT  36.252 20.237 37.494 20.309 ;
     RECT  55.368 19.913 56.79 20.309 ;
     RECT  61.344 20.219 63.738 20.309 ;
     RECT  67.32 19.997 68.31 20.309 ;
     RECT  72.72 19.997 72.99 20.309 ;
     RECT  77.004 20.285 77.022 20.309 ;
     RECT  55.368 20.309 55.89 20.345 ;
     RECT  90.504 19.949 90.522 20.345 ;
     RECT  29.088 20.039 29.862 20.381 ;
     RECT  36.324 20.309 37.494 20.381 ;
     RECT  38.376 20.111 44.01 20.381 ;
     RECT  62.604 20.309 63.738 20.381 ;
     RECT  96.408 20.075 96.534 20.381 ;
     RECT  103.176 20.039 103.806 20.417 ;
     RECT  68.292 20.309 68.31 20.429 ;
     RECT  29.088 20.381 29.106 20.453 ;
     RECT  30.708 20.237 35.226 20.453 ;
     RECT  36.504 20.381 37.494 20.453 ;
     RECT  45.036 20.183 46.17 20.453 ;
     RECT  33.912 20.453 35.226 20.489 ;
     RECT  47.484 20.237 51.462 20.489 ;
     RECT  29.844 20.381 29.862 20.525 ;
     RECT  45.072 20.453 45.09 20.525 ;
     RECT  47.484 20.489 48.654 20.525 ;
     RECT  42.192 20.381 44.01 20.534 ;
     RECT  97.632 20.039 97.65 20.534 ;
     RECT  79.488 19.913 80.262 20.579 ;
     RECT  27.864 20.539 27.882 20.587 ;
     RECT  60.444 19.757 60.462 20.615 ;
     RECT  103.788 20.417 103.806 20.615 ;
     RECT  30.708 20.453 32.49 20.651 ;
     RECT  49.392 20.489 51.462 20.651 ;
     RECT  92.772 19.337 92.79 20.651 ;
     RECT  38.376 20.381 41.454 20.669 ;
     RECT  47.808 20.525 48.654 20.669 ;
     RECT  85.644 20.189 86.202 20.687 ;
     RECT  38.376 20.669 40.374 20.723 ;
     RECT  80.244 20.579 80.262 20.723 ;
     RECT  2.415 19.949 22.77 20.731 ;
     RECT  23.508 19.949 26.046 20.731 ;
     RECT  30.708 20.651 31.41 20.759 ;
     RECT  96.516 20.381 96.534 20.759 ;
     RECT  2.415 20.731 26.046 20.804 ;
     RECT  27.864 20.587 27.954 20.804 ;
     RECT  65.376 19.901 65.934 20.804 ;
     RECT  79.488 20.579 79.506 20.804 ;
     RECT  61.344 20.309 61.362 20.813 ;
     RECT  25.416 20.804 26.046 20.849 ;
     RECT  32.436 20.651 32.49 20.849 ;
     RECT  64.584 20.219 64.602 20.849 ;
     RECT  69.372 19.535 69.39 20.849 ;
     RECT  2.415 20.804 24.498 20.885 ;
     RECT  27.864 20.804 27.882 20.885 ;
     RECT  57.564 19.913 59.022 20.885 ;
     RECT  94.176 20.093 94.626 20.885 ;
     RECT  48.132 20.669 48.654 20.921 ;
     RECT  84.132 20.285 84.906 20.921 ;
     RECT  31.392 20.759 31.41 20.957 ;
     RECT  85.644 20.687 85.662 20.957 ;
     RECT  32.472 20.849 32.49 20.993 ;
     RECT  36.54 20.453 37.494 21.029 ;
     RECT  62.604 20.381 62.622 21.046 ;
     RECT  38.376 20.723 39.942 21.053 ;
     RECT  62.532 21.046 62.622 21.074 ;
     RECT  23.832 20.885 24.498 21.101 ;
     RECT  36.54 21.029 37.134 21.101 ;
     RECT  50.76 20.651 51.462 21.101 ;
     RECT  63.612 20.381 63.738 21.101 ;
     RECT  42.84 20.534 44.01 21.115 ;
     RECT  46.152 20.453 46.17 21.115 ;
     RECT  116.496 20.267 121.662 21.119 ;
     RECT  48.132 20.921 48.258 21.149 ;
     RECT  51.444 21.101 51.462 21.155 ;
     RECT  34.524 20.489 35.154 21.191 ;
     RECT  91.404 19.949 91.422 21.191 ;
     RECT  25.704 20.849 26.046 21.211 ;
     RECT  27.324 21.163 27.342 21.211 ;
     RECT  74.556 19.877 74.574 21.227 ;
     RECT  114.588 21.091 114.606 21.227 ;
     RECT  42.84 21.115 44.118 21.245 ;
     RECT  29.952 21.163 29.97 21.293 ;
     RECT  42.84 21.245 43.866 21.389 ;
     RECT  52.812 19.517 53.514 21.389 ;
     RECT  57.96 20.885 59.022 21.389 ;
     RECT  25.704 21.211 27.342 21.425 ;
     RECT  71.28 19.913 71.658 21.425 ;
     RECT  53.496 21.389 53.514 21.437 ;
     RECT  2.415 20.885 23.058 21.461 ;
     RECT  49.392 20.651 49.806 21.461 ;
     RECT  87.696 20.285 87.714 21.485 ;
     RECT  38.736 21.053 39.942 21.497 ;
     RECT  58.32 21.389 59.022 21.533 ;
     RECT  6.732 21.461 23.058 21.629 ;
     RECT  46.152 21.115 46.782 21.629 ;
     RECT  25.704 21.425 26.766 21.643 ;
     RECT  48.168 21.149 48.258 21.643 ;
     RECT  48.168 21.643 48.294 21.677 ;
     RECT  41.436 20.669 41.454 21.695 ;
     RECT  84.132 20.921 84.15 21.695 ;
     RECT  42.84 21.389 43.11 21.725 ;
     RECT  43.092 21.725 43.11 21.731 ;
     RECT  71.496 21.425 71.658 21.731 ;
     RECT  38.736 21.497 39.366 21.856 ;
     RECT  2.415 21.461 5.958 21.979 ;
     RECT  114.696 21.931 114.714 22.075 ;
     RECT  1.692 21.979 5.958 22.219 ;
     RECT  1.656 22.219 5.958 22.267 ;
     RECT  6.732 21.629 22.878 22.267 ;
     RECT  1.656 22.267 22.878 22.464 ;
     RECT  24.48 21.101 24.498 22.464 ;
     RECT  25.632 21.643 26.766 22.464 ;
     RECT  34.524 21.191 34.722 22.464 ;
     RECT  37.116 21.101 37.134 22.464 ;
     RECT  38.196 21.856 39.366 22.464 ;
     RECT  43.848 21.389 43.866 22.464 ;
     RECT  46.764 21.629 46.782 22.464 ;
     RECT  48.276 21.677 48.294 22.464 ;
     RECT  49.788 21.461 49.806 22.464 ;
     RECT  54.468 19.679 54.486 22.464 ;
     RECT  55.368 20.345 55.386 22.464 ;
     RECT  58.608 21.533 59.022 22.464 ;
     RECT  62.532 21.074 62.55 22.464 ;
     RECT  63.648 21.101 63.738 22.464 ;
     RECT  65.376 20.804 65.466 22.464 ;
     RECT  71.64 21.731 71.658 22.464 ;
     RECT  84.888 20.921 84.906 22.464 ;
     RECT  114.588 22.075 114.714 22.464 ;
     RECT  117 21.119 121.662 22.464 ;
     RECT  1.656 22.464 121.662 22.505 ;
     RECT  1.656 22.505 6.03 23.515 ;
     RECT  6.768 22.505 121.662 23.515 ;
     RECT  1.656 23.515 121.662 24.989 ;
     RECT  1.656 24.989 121.626 25.277 ;
     RECT  1.656 25.277 121.59 25.469 ;
     RECT  1.656 25.469 121.497 27.751 ;
     RECT  1.62 27.751 121.497 29.405 ;
     RECT  1.62 29.405 120.474 30.379 ;
     RECT  1.404 30.379 120.474 31.037 ;
     RECT  1.404 31.037 120.402 31.325 ;
     RECT  0.324 31.261 0.342 31.531 ;
     RECT  0.324 31.531 0.63 32.299 ;
     RECT  0.252 32.299 0.63 32.717 ;
     RECT  1.404 31.325 120.042 33.437 ;
     RECT  0.576 32.717 0.63 33.725 ;
     RECT  1.404 33.437 120.006 33.725 ;
     RECT  0.576 33.725 0.594 33.883 ;
     RECT  0.252 33.883 0.594 33.917 ;
     RECT  118.224 33.725 120.006 34.205 ;
     RECT  119.448 34.205 120.006 34.301 ;
     RECT  118.224 34.205 118.242 34.493 ;
     RECT  119.628 34.301 120.006 34.589 ;
     RECT  0.252 33.917 0.558 34.733 ;
     RECT  119.628 34.589 119.79 34.799 ;
     RECT  0.252 34.733 0.27 34.987 ;
     RECT  119.628 34.799 119.646 35.131 ;
     RECT  119.232 35.131 119.646 35.401 ;
     RECT  1.404 33.725 117.414 35.515 ;
     RECT  118.62 35.401 119.646 35.573 ;
     RECT  1.404 35.515 117.45 35.581 ;
     RECT  1.404 35.581 117.486 35.645 ;
     RECT  1.404 35.645 117.414 35.741 ;
     RECT  118.692 35.573 118.71 35.879 ;
     RECT  0.216 34.987 0.27 36.041 ;
     RECT  119.88 35.941 119.898 36.149 ;
     RECT  1.584 35.741 117.414 36.661 ;
     RECT  1.584 36.661 117.45 36.701 ;
     RECT  120.276 36.763 120.294 36.859 ;
     RECT  120.276 36.859 120.33 36.893 ;
     RECT  0.54 36.391 0.558 36.895 ;
     RECT  118.584 36.553 118.602 36.895 ;
     RECT  120.276 36.893 120.294 37.049 ;
     RECT  0.252 36.895 0.558 37.057 ;
     RECT  0.216 37.057 0.558 37.435 ;
     RECT  0.216 37.435 0.594 37.469 ;
     RECT  119.844 37.327 119.898 37.589 ;
     RECT  0.216 37.469 0.558 37.613 ;
     RECT  118.584 36.895 119.106 37.757 ;
     RECT  119.088 37.757 119.106 37.867 ;
     RECT  119.088 37.867 119.754 38.333 ;
     RECT  0.216 37.613 0.234 38.407 ;
     RECT  119.736 38.333 119.754 38.407 ;
     RECT  1.584 36.701 117.414 38.491 ;
     RECT  119.736 38.407 120.078 38.507 ;
     RECT  1.584 38.491 117.45 38.543 ;
     RECT  119.772 38.507 120.078 38.543 ;
     RECT  118.62 38.551 118.638 38.641 ;
     RECT  1.584 38.543 117.414 38.741 ;
     RECT  118.584 38.641 118.638 39.119 ;
     RECT  119.772 38.543 120.006 39.253 ;
     RECT  119.088 39.253 120.006 39.281 ;
     RECT  119.952 39.281 120.006 39.317 ;
     RECT  119.952 39.317 119.97 39.587 ;
     RECT  1.584 38.741 117.378 39.631 ;
     RECT  119.088 39.281 119.106 39.965 ;
     RECT  1.584 39.631 117.414 40.261 ;
     RECT  0.216 38.407 0.27 40.325 ;
     RECT  1.584 40.261 117.45 40.445 ;
     RECT  119.628 40.135 119.646 40.567 ;
     RECT  119.628 40.567 119.97 40.873 ;
     RECT  119.052 40.873 119.97 40.909 ;
     RECT  119.052 40.909 120.078 40.937 ;
     RECT  120.06 40.937 120.078 41.009 ;
     RECT  0.252 40.325 0.27 41.071 ;
     RECT  0.252 41.071 0.558 41.179 ;
     RECT  119.052 40.937 119.178 41.179 ;
     RECT  118.584 41.179 119.178 41.279 ;
     RECT  1.584 40.445 117.414 41.341 ;
     RECT  0.216 41.179 0.558 41.501 ;
     RECT  1.584 41.341 117.45 41.597 ;
     RECT  118.584 41.279 119.106 42.139 ;
     RECT  118.584 42.139 119.214 42.287 ;
     RECT  0.216 41.501 0.27 42.493 ;
     RECT  119.664 42.421 119.79 42.529 ;
     RECT  118.584 42.287 118.71 42.593 ;
     RECT  0.216 42.493 0.846 42.629 ;
     RECT  119.664 42.529 120.078 42.629 ;
     RECT  119.664 42.629 119.682 42.845 ;
     RECT  118.584 42.593 118.674 43.411 ;
     RECT  0.828 42.629 0.846 43.843 ;
     RECT  118.584 43.411 119.106 44.093 ;
     RECT  119.664 44.311 119.682 44.653 ;
     RECT  0.216 43.843 0.846 44.669 ;
     RECT  119.664 44.653 119.862 44.753 ;
     RECT  0.216 44.669 0.27 44.813 ;
     RECT  118.584 44.093 118.602 44.887 ;
     RECT  119.664 44.753 119.754 44.887 ;
     RECT  118.584 44.887 119.754 44.951 ;
     RECT  0.252 44.813 0.27 45.101 ;
     RECT  118.584 44.951 119.682 45.149 ;
     RECT  118.584 45.149 118.674 45.629 ;
     RECT  118.62 45.629 118.674 45.967 ;
     RECT  118.62 45.967 118.71 46.103 ;
     RECT  118.692 46.103 118.71 46.205 ;
     RECT  119.736 45.769 119.754 46.309 ;
     RECT  119.736 46.309 119.97 46.373 ;
     RECT  119.952 46.373 119.97 46.409 ;
     RECT  1.584 41.597 117.414 47.047 ;
     RECT  120.06 47.047 120.078 47.147 ;
     RECT  1.584 47.047 117.45 47.261 ;
     RECT  119.088 46.615 119.106 47.281 ;
     RECT  118.584 47.281 119.106 48.127 ;
     RECT  118.584 48.127 119.754 48.271 ;
     RECT  118.584 48.271 119.79 48.509 ;
     RECT  118.62 48.509 119.79 48.739 ;
     RECT  118.62 48.739 119.97 48.839 ;
     RECT  119.052 48.839 119.97 48.929 ;
     RECT  119.052 48.929 119.898 48.965 ;
     RECT  1.584 47.261 117.414 49.001 ;
     RECT  119.052 48.965 119.106 49.181 ;
     RECT  119.88 48.965 119.898 49.577 ;
     RECT  1.584 49.001 117.378 49.819 ;
     RECT  119.952 49.747 119.97 49.981 ;
     RECT  119.952 49.981 120.006 50.117 ;
     RECT  119.088 49.181 119.106 50.237 ;
     RECT  118.584 50.287 118.746 50.459 ;
     RECT  118.584 50.459 118.71 50.549 ;
     RECT  119.772 50.521 119.79 50.729 ;
     RECT  118.584 50.549 118.674 50.999 ;
     RECT  1.584 49.819 117.414 51.389 ;
     RECT  1.584 51.389 117.378 51.431 ;
     RECT  119.52 51.163 119.61 51.451 ;
     RECT  119.376 51.451 119.61 51.643 ;
     RECT  118.584 50.999 118.602 51.701 ;
     RECT  119.376 51.643 119.646 52.015 ;
     RECT  2.232 51.431 117.378 52.141 ;
     RECT  118.62 51.943 118.638 52.411 ;
     RECT  119.376 52.015 119.754 52.411 ;
     RECT  118.62 52.411 119.754 52.519 ;
     RECT  118.584 52.519 119.754 52.817 ;
     RECT  118.584 52.817 119.718 52.889 ;
     RECT  141.912 52.027 141.93 52.979 ;
     RECT  2.232 52.141 117.414 52.987 ;
     RECT  118.584 52.889 119.61 53.117 ;
     RECT  2.232 52.987 117.45 53.693 ;
     RECT  119.448 53.117 119.61 53.833 ;
     RECT  118.584 53.117 118.602 54.139 ;
     RECT  119.448 53.833 119.754 54.139 ;
     RECT  118.584 54.139 119.754 54.239 ;
     RECT  119.556 54.239 119.754 54.301 ;
     RECT  119.556 54.301 119.79 54.437 ;
     RECT  118.584 54.239 118.602 55.003 ;
     RECT  119.556 54.437 119.754 55.003 ;
     RECT  118.584 55.003 119.754 55.291 ;
     RECT  118.584 55.291 119.97 55.409 ;
     RECT  2.232 53.693 117.414 55.579 ;
     RECT  118.584 55.409 119.178 55.579 ;
     RECT  2.232 55.579 119.178 55.859 ;
     RECT  120.096 55.651 120.114 55.859 ;
     RECT  2.232 55.859 118.674 56.363 ;
     RECT  2.232 56.363 118.062 56.489 ;
     RECT  119.556 56.347 119.646 56.641 ;
     RECT  2.232 56.489 118.026 56.669 ;
     RECT  119.556 56.641 119.862 56.923 ;
     RECT  119.268 56.923 119.862 57.101 ;
     RECT  119.628 57.101 119.862 57.145 ;
     RECT  2.232 56.669 117.45 57.371 ;
     RECT  118.584 57.271 118.746 57.371 ;
     RECT  118.584 57.371 118.674 57.443 ;
     RECT  119.628 57.145 119.97 58.075 ;
     RECT  119.592 58.075 119.97 58.415 ;
     RECT  119.952 58.415 119.97 58.649 ;
     RECT  2.232 57.371 117.414 58.939 ;
     RECT  2.232 58.939 117.45 59.189 ;
     RECT  119.628 59.227 119.646 59.459 ;
     RECT  119.736 59.611 119.934 59.765 ;
     RECT  119.736 59.765 119.79 59.999 ;
     RECT  119.736 59.999 119.754 60.305 ;
     RECT  118.584 57.443 118.602 60.379 ;
     RECT  118.584 60.379 119.286 61.223 ;
     RECT  2.232 59.189 117.414 61.339 ;
     RECT  119.628 61.243 119.646 61.357 ;
     RECT  119.628 61.357 119.862 61.493 ;
     RECT  2.232 61.339 118.026 62.011 ;
     RECT  119.628 61.493 119.718 62.107 ;
     RECT  119.16 62.107 119.718 62.159 ;
     RECT  2.232 62.011 118.062 62.189 ;
     RECT  119.16 62.159 119.178 62.609 ;
     RECT  2.268 62.189 118.062 62.699 ;
     RECT  119.988 62.401 120.006 62.699 ;
     RECT  118.044 62.699 118.062 63.005 ;
     RECT  2.268 62.699 117.288 63.528 ;
     RECT  41.328 63.528 41.346 64.355 ;
     RECT  2.268 63.528 25.218 64.699 ;
     RECT  43.164 64.939 43.182 65.227 ;
     RECT  31.212 64.747 31.23 65.245 ;
     RECT  139.032 52.987 139.05 65.273 ;
     RECT  36.468 64.699 36.486 65.275 ;
     RECT  2.268 64.699 25.47 65.407 ;
     RECT  2.268 65.407 25.65 65.551 ;
     RECT  47.628 64.651 47.646 65.563 ;
     RECT  46.296 63.528 46.314 65.593 ;
     RECT  40.407 65.593 40.497 65.641 ;
     RECT  29.607 65.593 29.697 65.659 ;
     RECT  45.807 65.593 46.314 65.659 ;
     RECT  47.376 65.563 47.646 65.659 ;
     RECT  31.104 65.245 31.23 65.749 ;
     RECT  40.407 65.641 41.13 65.749 ;
     RECT  27.108 65.713 27.126 65.785 ;
     RECT  45.807 65.659 47.646 65.785 ;
     RECT  38.772 65.707 38.79 65.803 ;
     RECT  27.108 65.785 27.882 65.821 ;
     RECT  38.304 65.803 38.79 65.821 ;
     RECT  40.407 65.749 41.49 65.821 ;
     RECT  43.164 65.227 43.47 65.821 ;
     RECT  49.212 64.987 49.23 65.821 ;
     RECT  45.807 65.785 47.718 65.851 ;
     RECT  35.007 65.593 35.097 65.863 ;
     RECT  40.407 65.821 41.778 65.863 ;
     RECT  45.036 65.821 45.054 65.863 ;
     RECT  45.807 65.851 47.79 65.863 ;
     RECT  51.207 65.593 51.297 65.863 ;
     RECT  56.607 65.593 56.697 65.863 ;
     RECT  62.007 65.593 62.097 65.863 ;
     RECT  67.407 65.593 67.497 65.863 ;
     RECT  72.807 65.593 72.897 65.863 ;
     RECT  78.207 65.593 78.297 65.863 ;
     RECT  83.607 65.593 83.697 65.863 ;
     RECT  89.007 65.593 89.097 65.863 ;
     RECT  94.407 65.593 94.497 65.863 ;
     RECT  99.807 65.593 99.897 65.863 ;
     RECT  105.207 65.593 105.297 65.863 ;
     RECT  110.607 65.593 110.697 65.863 ;
     RECT  116.007 65.593 116.097 65.863 ;
     RECT  48.672 65.821 49.23 65.885 ;
     RECT  27.036 65.821 27.882 65.911 ;
     RECT  29.16 65.659 29.697 65.911 ;
     RECT  43.164 65.821 43.506 65.947 ;
     RECT  38.304 65.821 39.366 66.043 ;
     RECT  33.948 65.821 33.966 66.055 ;
     RECT  38.196 66.043 39.366 66.055 ;
     RECT  40.215 65.863 41.778 66.055 ;
     RECT  2.268 65.551 26.262 66.077 ;
     RECT  2.376 66.077 26.262 66.091 ;
     RECT  27.036 65.911 29.697 66.091 ;
     RECT  30.852 65.749 31.23 66.091 ;
     RECT  33.84 66.055 33.966 66.091 ;
     RECT  34.815 65.863 35.097 66.091 ;
     RECT  36.108 65.275 36.486 66.091 ;
     RECT  37.224 63.528 37.242 66.091 ;
     RECT  38.196 66.055 41.778 66.091 ;
     RECT  45.036 65.863 47.79 66.091 ;
     RECT  2.376 66.091 29.697 66.181 ;
     RECT  33.84 66.091 34.038 66.181 ;
     RECT  34.776 66.091 35.097 66.181 ;
     RECT  30.852 66.091 32.598 66.217 ;
     RECT  33.84 66.181 35.097 66.217 ;
     RECT  2.376 66.181 29.862 66.245 ;
     RECT  49.14 65.885 49.23 66.253 ;
     RECT  30.852 66.217 35.097 66.289 ;
     RECT  43.164 65.947 44.118 66.289 ;
     RECT  45 66.091 47.79 66.289 ;
     RECT  36.108 66.091 42.318 66.325 ;
     RECT  43.164 66.289 47.79 66.325 ;
     RECT  2.412 66.245 29.862 66.361 ;
     RECT  30.852 66.289 35.226 66.361 ;
     RECT  49.14 66.253 49.302 66.361 ;
     RECT  2.412 66.361 35.226 66.475 ;
     RECT  36.108 66.325 47.79 66.475 ;
     RECT  49.14 66.361 49.626 66.551 ;
     RECT  2.412 66.475 47.79 66.631 ;
     RECT  51.015 65.863 51.297 66.631 ;
     RECT  49.212 66.551 49.626 66.667 ;
     RECT  50.4 66.631 51.297 66.667 ;
     RECT  49.212 66.667 51.297 66.701 ;
     RECT  2.412 66.631 48.258 66.757 ;
     RECT  2.412 66.757 48.33 66.785 ;
     RECT  2.415 66.785 48.33 66.821 ;
     RECT  49.212 66.701 49.77 66.857 ;
     RECT  47.304 66.821 48.33 66.901 ;
     RECT  49.536 66.857 49.77 67.091 ;
     RECT  49.68 67.091 49.698 67.361 ;
     RECT  47.304 66.901 48.474 67.441 ;
     RECT  47.304 67.441 48.798 67.517 ;
     RECT  2.415 66.821 46.494 67.829 ;
     RECT  2.415 67.829 3.438 67.865 ;
     RECT  4.284 67.829 44.694 67.865 ;
     RECT  4.32 67.865 44.694 67.901 ;
     RECT  45.432 67.829 46.494 68.143 ;
     RECT  47.304 67.517 48.69 68.143 ;
     RECT  4.428 67.901 44.694 68.611 ;
     RECT  45.432 68.143 48.69 68.611 ;
     RECT  4.428 68.611 48.69 68.719 ;
     RECT  4.248 68.719 48.69 68.791 ;
     RECT  49.428 68.395 49.446 68.791 ;
     RECT  4.248 68.791 49.446 68.953 ;
     RECT  2.415 67.865 3.366 69.061 ;
     RECT  4.248 68.953 49.662 69.061 ;
     RECT  2.415 69.061 49.662 69.331 ;
     RECT  2.415 69.331 50.166 69.593 ;
     RECT  2.415 69.593 49.734 70.157 ;
     RECT  2.415 70.157 49.626 70.259 ;
     RECT  2.415 70.259 49.59 70.529 ;
     RECT  42.696 70.529 49.59 70.565 ;
     RECT  2.415 70.529 41.922 70.673 ;
     RECT  2.415 70.673 41.886 70.925 ;
     RECT  42.732 70.565 49.014 71.339 ;
     RECT  42.732 71.339 48.798 71.411 ;
     RECT  49.788 71.221 49.806 71.411 ;
     RECT  2.415 70.925 41.85 71.653 ;
     RECT  42.732 71.411 48.726 71.653 ;
     RECT  2.415 71.653 48.726 72.149 ;
     RECT  2.415 72.149 48.69 72.173 ;
     RECT  3.744 72.173 48.69 72.689 ;
     RECT  3.744 72.689 46.53 72.955 ;
     RECT  3.6 72.955 46.53 72.995 ;
     RECT  47.268 72.689 48.69 73.075 ;
     RECT  2.415 72.173 2.862 73.345 ;
     RECT  4.032 72.995 46.53 73.507 ;
     RECT  47.268 73.075 48.978 73.507 ;
     RECT  4.032 73.507 48.978 73.921 ;
     RECT  4.032 73.921 49.266 74.039 ;
     RECT  2.415 73.345 2.97 74.047 ;
     RECT  4.032 74.039 48.978 74.075 ;
     RECT  4.032 74.075 48.042 74.111 ;
     RECT  2.415 74.047 3.222 74.191 ;
     RECT  4.032 74.111 47.862 74.191 ;
     RECT  2.415 74.191 47.862 74.489 ;
     RECT  3.78 74.489 47.862 74.615 ;
     RECT  3.78 74.615 15.246 74.651 ;
     RECT  9.432 74.651 15.246 74.687 ;
     RECT  16.092 74.615 47.862 74.759 ;
     RECT  3.78 74.651 8.586 74.849 ;
     RECT  9.432 74.687 15.174 74.849 ;
     RECT  9.432 74.849 14.814 74.885 ;
     RECT  48.888 74.075 48.978 75.001 ;
     RECT  4.428 74.849 8.586 75.119 ;
     RECT  9.432 74.885 11.358 75.119 ;
     RECT  9.432 75.119 10.134 75.155 ;
     RECT  12.348 74.885 14.814 75.155 ;
     RECT  17.964 74.759 47.862 75.259 ;
     RECT  48.888 75.001 49.158 75.259 ;
     RECT  9.432 75.155 9.738 75.389 ;
     RECT  4.428 75.119 5.166 75.437 ;
     RECT  9.54 75.389 9.558 75.437 ;
     RECT  7.344 75.119 8.55 75.533 ;
     RECT  17.964 75.259 49.158 75.695 ;
     RECT  17.964 75.695 47.43 75.821 ;
     RECT  48.348 75.695 49.158 75.821 ;
     RECT  17.964 75.821 46.53 75.869 ;
     RECT  17.964 75.869 41.526 75.929 ;
     RECT  42.3 75.869 46.53 75.929 ;
     RECT  47.412 75.821 47.43 75.929 ;
     RECT  48.96 75.821 49.158 75.965 ;
     RECT  45.144 75.929 46.53 76.073 ;
     RECT  48.96 75.965 48.978 76.109 ;
     RECT  45.144 76.073 46.098 76.199 ;
     RECT  17.964 75.929 41.49 76.235 ;
     RECT  33.66 76.235 41.49 76.469 ;
     RECT  42.336 75.929 43.722 76.505 ;
     RECT  16.092 74.759 17.154 76.649 ;
     RECT  42.336 76.505 42.858 76.739 ;
     RECT  43.704 76.505 43.722 76.739 ;
     RECT  37.116 76.469 41.49 76.781 ;
     RECT  39.564 76.781 41.49 76.783 ;
     RECT  42.336 76.739 42.786 76.783 ;
     RECT  38.484 76.781 38.646 76.811 ;
     RECT  39.564 76.783 42.786 76.811 ;
     RECT  33.66 76.469 36.306 76.883 ;
     RECT  38.628 76.811 38.646 76.883 ;
     RECT  39.564 76.811 42.642 76.883 ;
     RECT  7.344 75.533 8.097 76.891 ;
     RECT  17.964 76.235 32.922 76.891 ;
     RECT  37.116 76.781 37.746 76.919 ;
     RECT  17.712 76.891 32.922 76.981 ;
     RECT  33.66 76.883 35.097 76.981 ;
     RECT  39.888 76.883 42.642 77.009 ;
     RECT  36.288 76.883 36.306 77.323 ;
     RECT  36.288 77.323 36.594 77.357 ;
     RECT  11.304 75.119 11.358 77.657 ;
     RECT  47.592 77.515 47.61 77.701 ;
     RECT  37.728 76.919 37.746 77.827 ;
     RECT  17.712 76.981 35.097 77.863 ;
     RECT  39.888 77.009 41.778 77.899 ;
     RECT  47.592 77.701 47.826 78.043 ;
     RECT  47.376 78.043 47.826 78.077 ;
     RECT  47.376 78.077 47.394 78.089 ;
     RECT  48.672 78.043 48.69 78.091 ;
     RECT  7.308 76.891 8.097 78.125 ;
     RECT  47.16 78.091 47.178 78.125 ;
     RECT  48.456 78.091 48.69 78.125 ;
     RECT  7.344 78.125 8.097 78.161 ;
     RECT  17.712 77.863 35.406 78.169 ;
     RECT  36.576 77.357 36.594 78.169 ;
     RECT  17.712 78.169 36.594 78.187 ;
     RECT  6.372 75.119 6.39 78.269 ;
     RECT  37.728 77.827 38.178 78.331 ;
     RECT  48.672 78.125 48.69 78.395 ;
     RECT  17.712 78.187 36.882 78.413 ;
     RECT  37.728 78.331 38.79 78.439 ;
     RECT  39.6 77.899 41.778 78.439 ;
     RECT  48.888 78.511 48.906 78.653 ;
     RECT  37.728 78.439 41.778 78.979 ;
     RECT  17.712 78.413 36.594 79.249 ;
     RECT  17.712 79.249 36.918 79.277 ;
     RECT  48.132 79.243 48.15 79.475 ;
     RECT  48.348 79.591 48.366 79.805 ;
     RECT  11.304 77.657 11.322 80.093 ;
     RECT  42.624 77.009 42.642 80.095 ;
     RECT  37.692 78.979 41.778 80.329 ;
     RECT  42.624 80.095 42.786 80.329 ;
     RECT  36.576 79.277 36.918 80.761 ;
     RECT  47.7 80.923 47.718 81.095 ;
     RECT  48.636 80.923 48.654 81.095 ;
     RECT  17.712 79.277 35.622 81.175 ;
     RECT  36.36 80.761 36.918 81.175 ;
     RECT  17.712 81.175 36.918 81.211 ;
     RECT  37.692 80.329 42.786 81.211 ;
     RECT  47.916 81.211 47.934 81.485 ;
     RECT  48.744 81.211 48.762 81.485 ;
     RECT  17.712 81.211 42.786 81.779 ;
     RECT  16.092 76.649 16.506 82.481 ;
     RECT  47.772 82.525 47.79 82.561 ;
     RECT  19.8 81.779 42.786 82.651 ;
     RECT  47.772 82.561 48.15 82.651 ;
     RECT  47.772 82.651 48.474 82.699 ;
     RECT  47.556 82.699 48.474 82.747 ;
     RECT  19.8 82.651 42.822 82.781 ;
     RECT  47.376 82.747 48.474 82.831 ;
     RECT  2.415 74.489 2.862 82.949 ;
     RECT  19.8 82.781 42.786 83.021 ;
     RECT  47.376 82.831 48.654 83.179 ;
     RECT  47.376 83.179 48.726 83.227 ;
     RECT  47.16 83.227 48.726 83.275 ;
     RECT  47.16 83.275 48.762 83.489 ;
     RECT  4.428 75.437 4.446 83.525 ;
     RECT  20.16 83.021 42.786 83.633 ;
     RECT  17.712 81.779 18.897 83.789 ;
     RECT  47.34 83.489 48.762 83.911 ;
     RECT  2.415 82.949 2.697 83.987 ;
     RECT  7.815 78.161 8.097 83.987 ;
     RECT  12.528 75.155 14.814 83.987 ;
     RECT  18.144 83.789 18.897 83.987 ;
     RECT  45.615 76.199 45.897 83.987 ;
     RECT  51.015 66.701 51.297 83.987 ;
     RECT  56.415 65.863 56.697 83.987 ;
     RECT  61.815 65.863 62.097 83.987 ;
     RECT  67.215 65.863 67.497 83.987 ;
     RECT  72.615 65.863 72.897 83.987 ;
     RECT  78.015 65.863 78.297 83.987 ;
     RECT  83.415 65.863 83.697 83.987 ;
     RECT  88.815 65.863 89.097 83.987 ;
     RECT  94.215 65.863 94.497 83.987 ;
     RECT  99.615 65.863 99.897 83.987 ;
     RECT  105.015 65.863 105.297 83.987 ;
     RECT  110.415 65.863 110.697 83.987 ;
     RECT  115.815 65.863 116.097 83.987 ;
     RECT  121.215 29.405 121.497 83.987 ;
     RECT  126.615 2.413 126.897 83.987 ;
     RECT  132.015 2.413 132.297 83.987 ;
     RECT  137.415 2.413 137.697 83.987 ;
     RECT  47.34 83.911 48.906 84.065 ;
     RECT  22.356 83.633 42.786 84.173 ;
     RECT  47.448 84.065 48.906 84.181 ;
     RECT  47.448 84.181 49.05 84.221 ;
     RECT  2.415 83.987 2.505 84.257 ;
     RECT  7.815 83.987 7.905 84.257 ;
     RECT  12.528 83.987 13.305 84.257 ;
     RECT  18.144 83.987 18.705 84.257 ;
     RECT  45.615 83.987 45.705 84.257 ;
     RECT  51.015 83.987 51.105 84.257 ;
     RECT  56.415 83.987 56.505 84.257 ;
     RECT  61.815 83.987 61.905 84.257 ;
     RECT  67.215 83.987 67.305 84.257 ;
     RECT  72.615 83.987 72.705 84.257 ;
     RECT  78.015 83.987 78.105 84.257 ;
     RECT  83.415 83.987 83.505 84.257 ;
     RECT  88.815 83.987 88.905 84.257 ;
     RECT  94.215 83.987 94.305 84.257 ;
     RECT  99.615 83.987 99.705 84.257 ;
     RECT  105.015 83.987 105.105 84.257 ;
     RECT  110.415 83.987 110.505 84.257 ;
     RECT  115.815 83.987 115.905 84.257 ;
     RECT  121.215 83.987 121.305 84.257 ;
     RECT  126.615 83.987 126.705 84.257 ;
     RECT  132.015 83.987 132.105 84.257 ;
     RECT  137.415 83.987 137.505 84.257 ;
     RECT  47.448 84.221 48.69 84.299 ;
     RECT  16.092 82.481 16.326 84.677 ;
     RECT  12.528 84.257 12.546 84.713 ;
     RECT  20.16 83.633 21.582 84.749 ;
     RECT  21.132 84.749 21.582 84.794 ;
     RECT  22.356 84.173 22.374 84.845 ;
     RECT  23.112 84.173 42.786 85.133 ;
     RECT  18.144 84.257 18.378 85.217 ;
     RECT  14.184 83.987 14.814 85.253 ;
     RECT  14.184 85.253 14.346 85.277 ;
     RECT  14.184 85.277 14.202 85.334 ;
     RECT  21.564 84.794 21.582 85.379 ;
     RECT  23.472 85.133 42.786 85.421 ;
     RECT  23.796 85.421 42.786 85.469 ;
     RECT  47.52 84.299 48.69 85.483 ;
     RECT  16.092 84.677 16.11 86.189 ;
     RECT  18.36 85.217 18.378 86.237 ;
     RECT  24.48 85.469 42.786 86.268 ;
     RECT  47.52 85.483 48.834 86.268 ;
     RECT  20.16 84.749 20.178 86.297 ;
     RECT  33.624 86.268 33.642 86.297 ;
    LAYER M4 ;
     RECT  0.229 29.616 0.277 29.64 ;
     RECT  0.156 44.064 0.281 45.096 ;
     RECT  0.181 31.2 0.325 31.224 ;
     RECT  0.156 32.256 0.325 42.792 ;
     RECT  1.645 22.224 1.681 22.248 ;
     RECT  0.325 31.2 2.329 42.792 ;
     RECT  0.281 44.064 2.329 44.952 ;
     RECT  0.229 47.856 2.365 47.88 ;
     RECT  2.257 66.048 2.401 66.072 ;
     RECT  1.681 21.984 2.408 22.248 ;
     RECT  2.293 26.256 2.408 26.28 ;
     RECT  0.277 29.616 2.408 30.216 ;
     RECT  2.329 31.2 2.408 44.952 ;
     RECT  2.365 47.856 2.408 48.456 ;
     RECT  2.329 59.28 2.408 59.304 ;
     RECT  2.221 62.16 2.408 62.184 ;
     RECT  2.293 64.944 2.408 64.968 ;
     RECT  2.401 66.048 2.408 66.6 ;
     RECT  2.408 2.148 2.512 84.252 ;
     RECT  2.512 2.418 2.704 83.982 ;
     RECT  2.704 56.832 2.819 59.304 ;
     RECT  2.704 61.104 2.915 63.864 ;
     RECT  2.704 13.392 3.053 22.248 ;
     RECT  3.053 13.392 3.059 20.088 ;
     RECT  2.819 57.696 3.089 59.304 ;
     RECT  2.704 74.064 3.443 74.808 ;
     RECT  3.059 13.488 3.521 20.088 ;
     RECT  2.704 50.064 3.539 55.32 ;
     RECT  2.704 70.032 3.593 72.984 ;
     RECT  2.704 66.048 3.635 69.048 ;
     RECT  2.704 23.904 3.685 23.928 ;
     RECT  2.704 25.056 3.685 27.336 ;
     RECT  2.704 28.656 3.701 48.936 ;
     RECT  3.593 72.144 3.733 72.984 ;
     RECT  3.539 50.064 3.779 52.008 ;
     RECT  3.701 28.656 3.781 41.688 ;
     RECT  3.701 42.768 3.781 48.936 ;
     RECT  3.779 50.064 3.781 51.96 ;
     RECT  3.685 23.904 3.805 27.336 ;
     RECT  3.781 28.32 3.805 41.688 ;
     RECT  3.805 23.328 3.827 41.688 ;
     RECT  3.089 57.696 3.841 57.912 ;
     RECT  3.733 72.144 3.875 73.656 ;
     RECT  2.704 8.112 3.877 8.136 ;
     RECT  2.704 9.6 3.877 12.312 ;
     RECT  3.635 67.248 3.877 69.048 ;
     RECT  3.593 70.032 3.877 70.824 ;
     RECT  3.053 21.12 3.925 22.248 ;
     RECT  3.827 23.328 3.925 41.64 ;
     RECT  2.704 64.896 3.949 64.968 ;
     RECT  3.635 66.048 3.949 66.216 ;
     RECT  3.875 72.144 3.971 73.56 ;
     RECT  2.704 5.04 3.973 5.064 ;
     RECT  3.089 58.992 4.021 59.304 ;
     RECT  3.877 8.112 4.057 12.312 ;
     RECT  3.521 13.488 4.057 19.992 ;
     RECT  3.925 21.12 4.061 41.64 ;
     RECT  3.539 53.04 4.061 55.32 ;
     RECT  3.841 57.072 4.093 57.912 ;
     RECT  3.971 73.44 4.205 73.464 ;
     RECT  3.949 64.896 4.277 66.216 ;
     RECT  4.057 8.112 4.565 19.992 ;
     RECT  4.021 58.992 4.633 59.352 ;
     RECT  4.277 64.896 4.637 66.12 ;
     RECT  4.061 53.04 4.645 54.696 ;
     RECT  4.565 10.752 4.741 19.992 ;
     RECT  4.061 21.12 4.741 38.808 ;
     RECT  3.443 74.64 4.745 74.808 ;
     RECT  4.741 10.752 4.787 38.808 ;
     RECT  4.093 55.824 4.813 57.912 ;
     RECT  4.633 58.992 4.885 59.64 ;
     RECT  2.915 61.104 4.885 63 ;
     RECT  4.813 55.824 4.921 57.96 ;
     RECT  4.885 58.992 4.921 63 ;
     RECT  4.745 74.784 4.981 74.808 ;
     RECT  4.061 39.888 5.077 41.64 ;
     RECT  3.781 42.768 5.077 51.96 ;
     RECT  5.077 39.888 5.137 51.96 ;
     RECT  4.645 52.992 5.137 54.696 ;
     RECT  4.981 74.784 5.137 75.288 ;
     RECT  5.137 39.888 5.173 54.696 ;
     RECT  4.921 55.824 5.173 63 ;
     RECT  5.173 39.888 5.315 63 ;
     RECT  3.877 67.248 5.353 70.824 ;
     RECT  5.315 61.104 5.393 63 ;
     RECT  4.787 13.056 5.461 38.808 ;
     RECT  5.315 39.888 5.461 60.072 ;
     RECT  3.973 4.896 5.465 5.064 ;
     RECT  4.565 8.112 5.605 9.336 ;
     RECT  4.787 10.752 5.605 12.024 ;
     RECT  3.829 81.168 5.653 81.192 ;
     RECT  3.971 72.144 5.677 72.168 ;
     RECT  5.461 73.488 5.677 73.512 ;
     RECT  2.704 83.472 5.701 83.496 ;
     RECT  4.693 6.288 5.749 6.312 ;
     RECT  5.605 8.112 5.785 12.024 ;
     RECT  5.461 13.056 5.785 60.072 ;
     RECT  5.677 72.144 5.785 73.512 ;
     RECT  5.137 74.784 5.857 75.432 ;
     RECT  5.785 72.144 6.145 73.56 ;
     RECT  5.857 74.688 6.145 75.432 ;
     RECT  3.925 84.624 6.181 84.648 ;
     RECT  5.785 8.112 6.229 60.072 ;
     RECT  5.353 67.2 6.229 70.824 ;
     RECT  6.145 72.144 6.229 75.432 ;
     RECT  6.229 7.92 6.277 60.072 ;
     RECT  4.637 64.896 6.289 66.072 ;
     RECT  6.229 67.2 6.289 75.432 ;
     RECT  6.277 7.824 6.329 60.072 ;
     RECT  5.465 4.896 6.469 5.016 ;
     RECT  5.749 6.288 6.469 6.6 ;
     RECT  6.289 64.896 6.469 75.432 ;
     RECT  5.393 61.104 6.577 62.952 ;
     RECT  6.577 61.104 6.649 63.096 ;
     RECT  6.469 64.08 6.649 75.432 ;
     RECT  6.329 7.92 6.755 60.072 ;
     RECT  5.653 80.64 6.757 81.192 ;
     RECT  6.755 13.152 6.805 60.072 ;
     RECT  6.649 61.104 6.805 75.432 ;
     RECT  6.469 4.896 7.237 6.6 ;
     RECT  6.853 2.352 7.808 2.376 ;
     RECT  7.237 4.656 7.808 6.6 ;
     RECT  6.755 7.92 7.808 12.168 ;
     RECT  6.805 13.152 7.808 75.432 ;
     RECT  5.509 78.912 7.808 78.936 ;
     RECT  6.757 80.64 7.808 81.336 ;
     RECT  2.704 82.416 7.808 82.44 ;
     RECT  5.701 83.472 7.808 83.544 ;
     RECT  6.181 84.624 7.808 84.744 ;
     RECT  7.808 2.148 7.912 84.744 ;
     RECT  7.912 2.352 8.104 84.744 ;
     RECT  8.104 7.776 8.777 76.776 ;
     RECT  8.104 2.352 9.637 2.376 ;
     RECT  8.104 4.656 10.021 6.6 ;
     RECT  8.777 7.92 10.021 76.776 ;
     RECT  8.104 3.36 10.933 3.384 ;
     RECT  10.021 4.656 10.933 76.776 ;
     RECT  10.933 3.36 10.981 76.776 ;
     RECT  8.104 80.64 11.293 81.336 ;
     RECT  11.293 80.064 11.845 81.336 ;
     RECT  8.104 82.416 11.845 82.44 ;
     RECT  9.637 1.632 12.037 2.376 ;
     RECT  8.104 78.912 12.229 78.936 ;
     RECT  8.104 84.624 12.901 84.744 ;
     RECT  12.901 84.624 12.997 84.792 ;
     RECT  12.037 1.104 13.208 2.376 ;
     RECT  10.981 3.36 13.208 76.824 ;
     RECT  12.229 77.952 13.208 78.936 ;
     RECT  11.845 80.064 13.208 82.44 ;
     RECT  8.104 83.472 13.208 83.544 ;
     RECT  12.997 84.624 13.208 85.32 ;
     RECT  13.208 1.104 13.504 85.32 ;
     RECT  13.504 77.952 14.725 82.44 ;
     RECT  13.504 83.472 14.725 83.544 ;
     RECT  14.725 77.952 15.109 83.544 ;
     RECT  13.504 84.624 15.109 85.32 ;
     RECT  15.109 77.952 16.081 85.32 ;
     RECT  13.504 1.104 17.653 76.824 ;
     RECT  16.081 77.952 17.653 86.184 ;
     RECT  17.653 1.104 18.349 86.184 ;
     RECT  18.349 1.104 20.077 86.232 ;
     RECT  20.077 1.056 21.049 86.232 ;
     RECT  21.049 0.144 24.689 86.232 ;
     RECT  24.689 0.192 27.893 86.232 ;
     RECT  27.893 0.24 28.163 86.232 ;
     RECT  28.163 0.432 29.173 86.232 ;
     RECT  29.173 0.384 29.221 86.232 ;
     RECT  29.221 0.288 29.459 86.232 ;
     RECT  29.459 0.384 29.603 86.232 ;
     RECT  29.603 0.912 30.697 86.232 ;
     RECT  30.697 0.192 30.917 86.232 ;
     RECT  30.917 0.192 31.187 86.136 ;
     RECT  31.187 0.288 31.907 86.136 ;
     RECT  31.907 1.008 33.301 86.136 ;
     RECT  33.301 0.288 33.491 86.136 ;
     RECT  33.491 0.288 33.635 81.432 ;
     RECT  33.635 0.288 33.877 81.192 ;
     RECT  33.877 0.24 34.309 81.192 ;
     RECT  33.491 82.416 34.499 86.136 ;
     RECT  34.499 82.416 34.643 85.464 ;
     RECT  34.309 0.192 34.808 81.192 ;
     RECT  34.643 82.416 34.808 85.416 ;
     RECT  34.808 0.192 35.104 85.416 ;
     RECT  35.104 0.192 35.341 81.192 ;
     RECT  35.104 82.416 35.507 85.416 ;
     RECT  35.507 82.464 35.651 85.416 ;
     RECT  35.341 0.144 36.605 81.192 ;
     RECT  36.605 76.416 36.659 81.192 ;
     RECT  36.605 0.144 37.331 75.24 ;
     RECT  37.331 72.48 37.573 75.24 ;
     RECT  36.659 76.416 37.573 79.56 ;
     RECT  37.573 72.48 38.189 79.56 ;
     RECT  35.651 82.464 38.243 85.368 ;
     RECT  37.331 0.144 38.477 71.112 ;
     RECT  36.659 80.784 38.531 81.192 ;
     RECT  38.477 0.144 38.867 66.12 ;
     RECT  38.189 76.368 38.963 79.56 ;
     RECT  38.189 72.48 38.977 75.24 ;
     RECT  38.477 67.296 39.589 71.112 ;
     RECT  38.867 64.704 40.208 66.12 ;
     RECT  39.589 67.296 40.208 71.256 ;
     RECT  38.977 72.432 40.208 75.24 ;
     RECT  38.963 76.368 40.208 79.512 ;
     RECT  38.531 80.784 40.208 80.904 ;
     RECT  38.243 82.464 40.208 85.32 ;
     RECT  40.208 64.704 40.345 85.32 ;
     RECT  40.345 64.704 40.504 85.512 ;
     RECT  40.504 67.296 40.673 79.512 ;
     RECT  40.504 82.464 40.691 85.512 ;
     RECT  40.673 72.48 40.979 79.512 ;
     RECT  38.867 0.144 41.105 63.528 ;
     RECT  40.691 82.656 41.267 85.512 ;
     RECT  41.105 0.192 41.317 63.528 ;
     RECT  40.504 64.704 41.317 66.168 ;
     RECT  41.317 0.192 41.363 66.168 ;
     RECT  40.979 78.912 41.411 79.512 ;
     RECT  40.673 67.296 41.497 71.496 ;
     RECT  41.267 82.656 41.555 83.832 ;
     RECT  41.497 67.248 41.677 71.496 ;
     RECT  40.979 72.48 41.677 77.88 ;
     RECT  41.267 84.96 41.699 85.512 ;
     RECT  41.699 85.488 41.987 85.512 ;
     RECT  41.363 64.704 42.037 66.168 ;
     RECT  41.677 67.248 42.037 77.88 ;
     RECT  40.504 80.832 42.131 80.904 ;
     RECT  41.363 0.192 42.181 63.528 ;
     RECT  42.037 64.704 42.323 77.88 ;
     RECT  42.181 0.144 42.329 63.528 ;
     RECT  41.411 78.912 42.419 78.936 ;
     RECT  42.131 80.88 42.563 80.904 ;
     RECT  42.323 67.2 42.653 77.88 ;
     RECT  41.555 82.656 42.707 83.544 ;
     RECT  42.707 82.656 42.833 82.776 ;
     RECT  42.653 77.856 42.851 77.88 ;
     RECT  42.653 67.2 43.373 76.392 ;
     RECT  42.323 64.704 43.693 66.168 ;
     RECT  43.373 67.2 43.693 75.672 ;
     RECT  42.833 82.752 43.717 82.776 ;
     RECT  42.329 0.192 43.801 63.528 ;
     RECT  43.801 0.144 43.949 63.528 ;
     RECT  43.693 64.704 44.021 75.672 ;
     RECT  44.021 64.704 44.147 75.528 ;
     RECT  44.147 64.704 44.345 71.4 ;
     RECT  43.717 82.752 44.917 83.592 ;
     RECT  43.949 0.192 44.989 63.528 ;
     RECT  44.989 0.144 45.101 63.528 ;
     RECT  44.345 67.296 45.133 71.4 ;
     RECT  44.147 72.384 45.133 75.528 ;
     RECT  44.345 64.704 45.608 65.976 ;
     RECT  45.133 67.296 45.608 75.528 ;
     RECT  44.917 82.704 45.608 83.592 ;
     RECT  45.608 64.704 45.712 84.252 ;
     RECT  45.712 64.704 45.904 83.982 ;
     RECT  45.101 0.192 46.117 63.528 ;
     RECT  45.904 64.704 46.117 65.976 ;
     RECT  46.117 0.192 46.325 65.976 ;
     RECT  45.904 71.712 46.355 75.96 ;
     RECT  46.355 73.104 46.505 75.96 ;
     RECT  46.325 0.192 46.753 63.528 ;
     RECT  46.505 73.104 46.979 75.816 ;
     RECT  46.979 73.104 47.027 75.24 ;
     RECT  46.933 78.096 47.189 78.12 ;
     RECT  45.904 67.296 47.221 69.576 ;
     RECT  45.904 70.608 47.221 70.632 ;
     RECT  46.325 64.704 47.293 65.976 ;
     RECT  47.221 67.296 47.293 70.632 ;
     RECT  47.293 64.704 47.365 70.632 ;
     RECT  47.365 78.048 47.581 78.072 ;
     RECT  47.365 64.704 47.617 70.728 ;
     RECT  46.355 71.712 47.653 71.736 ;
     RECT  47.027 73.104 47.653 73.56 ;
     RECT  47.617 64.656 47.725 70.728 ;
     RECT  47.653 71.712 47.725 73.56 ;
     RECT  47.581 77.52 47.795 78.072 ;
     RECT  47.027 74.64 47.873 75.24 ;
     RECT  47.365 80.928 47.905 80.952 ;
     RECT  45.904 82.704 47.905 83.592 ;
     RECT  47.725 64.656 48.053 73.56 ;
     RECT  47.905 82.656 48.229 83.592 ;
     RECT  48.085 85.488 48.229 85.512 ;
     RECT  48.121 79.248 48.325 79.272 ;
     RECT  48.121 75.264 48.337 75.288 ;
     RECT  48.229 82.656 48.373 83.688 ;
     RECT  48.229 85.488 48.373 85.56 ;
     RECT  48.325 79.248 48.377 79.8 ;
     RECT  48.377 79.248 48.419 79.272 ;
     RECT  48.373 85.488 48.419 85.656 ;
     RECT  47.795 78.048 48.445 78.072 ;
     RECT  48.419 85.488 48.467 85.56 ;
     RECT  48.053 64.656 48.485 73.224 ;
     RECT  48.485 72.336 48.515 73.224 ;
     RECT  48.485 64.656 48.611 71.304 ;
     RECT  48.445 78.048 48.661 78.12 ;
     RECT  48.611 64.656 48.701 71.256 ;
     RECT  48.661 78.048 48.707 78.168 ;
     RECT  48.373 82.656 48.707 84.216 ;
     RECT  48.707 83.184 48.737 84.216 ;
     RECT  47.905 80.928 48.773 81.48 ;
     RECT  48.701 66.672 48.851 71.256 ;
     RECT  48.337 75.264 48.851 75.816 ;
     RECT  48.707 78.144 48.877 78.168 ;
     RECT  48.851 68.4 48.899 71.256 ;
     RECT  48.515 72.576 48.899 73.224 ;
     RECT  48.851 75.792 48.901 75.816 ;
     RECT  48.899 72.576 48.947 72.6 ;
     RECT  48.877 78.144 48.947 78.648 ;
     RECT  48.773 80.928 48.947 80.952 ;
     RECT  48.901 75.792 48.989 76.104 ;
     RECT  48.737 83.28 48.995 84.216 ;
     RECT  48.989 75.792 49.025 75.816 ;
     RECT  48.467 85.488 49.043 85.512 ;
     RECT  48.899 68.4 49.061 70.44 ;
     RECT  48.995 84.192 49.061 84.216 ;
     RECT  48.701 64.656 49.241 65.016 ;
     RECT  49.061 70.128 49.349 70.44 ;
     RECT  49.061 68.4 49.421 69 ;
     RECT  49.421 68.4 49.571 68.424 ;
     RECT  49.241 64.656 49.619 64.728 ;
     RECT  49.349 70.128 49.745 70.152 ;
     RECT  48.851 66.672 49.781 66.792 ;
     RECT  49.781 66.672 51.008 66.696 ;
     RECT  51.008 65.868 51.112 84.252 ;
     RECT  49.619 64.656 51.2 64.68 ;
     RECT  51.112 65.868 51.2 83.982 ;
     RECT  51.2 64.656 51.304 83.982 ;
     RECT  46.753 0.144 52.049 63.528 ;
     RECT  52.049 0.192 52.211 63.528 ;
     RECT  52.211 0.288 53.363 63.528 ;
     RECT  53.363 0.48 54.601 63.528 ;
     RECT  54.601 0.192 56.005 63.528 ;
     RECT  56.408 65.868 56.512 84.252 ;
     RECT  51.304 64.656 56.6 64.68 ;
     RECT  56.512 65.868 56.6 83.982 ;
     RECT  56.6 64.656 56.704 83.982 ;
     RECT  56.005 0.144 57.017 63.528 ;
     RECT  57.017 0.192 57.683 63.528 ;
     RECT  57.683 0.816 60.373 63.528 ;
     RECT  60.373 0.192 60.973 63.528 ;
     RECT  61.808 65.868 61.912 84.252 ;
     RECT  56.704 64.656 62 64.68 ;
     RECT  61.912 65.868 62 83.982 ;
     RECT  62 64.656 62.104 83.982 ;
     RECT  62.104 64.656 62.963 64.68 ;
     RECT  67.208 65.868 67.312 84.252 ;
     RECT  67.312 65.868 67.4 83.982 ;
     RECT  67.4 65.598 67.504 83.982 ;
     RECT  60.973 0.144 71.237 63.528 ;
     RECT  71.237 1.344 71.273 63.528 ;
     RECT  72.608 65.868 72.712 84.252 ;
     RECT  71.273 1.392 72.785 63.528 ;
     RECT  72.712 65.868 72.8 83.982 ;
     RECT  72.8 65.598 72.904 83.982 ;
     RECT  72.785 1.488 73.073 63.528 ;
     RECT  71.237 0.144 74.261 0.168 ;
     RECT  78.008 65.868 78.112 84.252 ;
     RECT  78.112 65.868 78.2 83.982 ;
     RECT  78.2 65.598 78.304 83.982 ;
     RECT  73.073 1.536 81.533 63.528 ;
     RECT  81.533 1.536 83.408 2.808 ;
     RECT  81.533 3.84 83.408 63.528 ;
     RECT  83.408 65.868 83.512 84.252 ;
     RECT  83.512 65.868 83.6 83.982 ;
     RECT  83.6 65.598 83.704 83.982 ;
     RECT  88.808 65.868 88.912 84.252 ;
     RECT  88.912 65.868 89 83.982 ;
     RECT  89 65.598 89.104 83.982 ;
     RECT  94.208 65.868 94.312 84.252 ;
     RECT  94.312 65.868 94.4 83.982 ;
     RECT  83.408 1.536 94.504 63.528 ;
     RECT  94.4 65.598 94.504 83.982 ;
     RECT  94.504 1.536 96.901 4.248 ;
     RECT  94.504 5.232 96.901 63.528 ;
     RECT  96.901 1.536 97.013 63.528 ;
     RECT  97.013 5.232 98.597 63.528 ;
     RECT  97.013 1.536 99.608 4.248 ;
     RECT  98.597 5.232 99.608 17.688 ;
     RECT  98.597 18.672 99.608 63.528 ;
     RECT  99.608 65.868 99.712 84.252 ;
     RECT  99.712 65.868 99.8 83.982 ;
     RECT  99.608 1.536 99.904 63.528 ;
     RECT  99.8 65.598 99.904 83.982 ;
     RECT  99.904 1.536 105.008 4.248 ;
     RECT  99.904 5.328 105.008 63.528 ;
     RECT  105.008 65.868 105.112 84.252 ;
     RECT  105.112 65.868 105.2 83.982 ;
     RECT  105.008 1.536 105.304 63.528 ;
     RECT  105.2 65.598 105.304 83.982 ;
     RECT  105.304 5.328 106.553 63.528 ;
     RECT  106.553 5.328 106.657 17.112 ;
     RECT  106.657 5.232 107.273 17.112 ;
     RECT  107.273 13.728 107.605 17.112 ;
     RECT  106.553 18.24 107.605 63.528 ;
     RECT  107.273 5.232 108.277 12.696 ;
     RECT  107.605 13.728 108.277 63.528 ;
     RECT  108.277 5.232 108.323 63.528 ;
     RECT  108.323 8.832 108.389 63.528 ;
     RECT  108.389 9.024 108.785 63.528 ;
     RECT  108.785 9.072 108.893 63.528 ;
     RECT  108.893 9.072 108.965 12.696 ;
     RECT  108.893 14.16 108.965 63.528 ;
     RECT  108.965 18.96 109.379 63.528 ;
     RECT  108.965 14.16 109.957 17.88 ;
     RECT  109.957 14.16 109.969 18.216 ;
     RECT  108.965 9.552 110.053 12.696 ;
     RECT  109.969 14.112 110.053 18.216 ;
     RECT  105.304 1.536 110.408 4.248 ;
     RECT  108.323 5.232 110.408 7.704 ;
     RECT  110.053 9.552 110.408 18.216 ;
     RECT  109.379 19.248 110.408 63.528 ;
     RECT  110.408 65.868 110.512 84.252 ;
     RECT  110.512 65.868 110.6 83.982 ;
     RECT  110.408 1.536 110.704 63.528 ;
     RECT  110.6 65.598 110.704 83.982 ;
     RECT  110.704 16.272 110.729 16.392 ;
     RECT  110.704 14.448 110.819 14.76 ;
     RECT  110.729 16.368 110.819 16.392 ;
     RECT  110.704 17.424 110.819 18.216 ;
     RECT  110.819 17.616 110.981 18.216 ;
     RECT  110.981 18.192 111.089 18.216 ;
     RECT  110.704 11.808 114.617 12.6 ;
     RECT  110.704 5.328 114.689 7.704 ;
     RECT  110.704 1.536 115.808 4.248 ;
     RECT  114.689 5.472 115.808 7.704 ;
     RECT  110.704 9.6 115.808 9.672 ;
     RECT  110.704 10.704 115.808 10.728 ;
     RECT  114.617 11.952 115.808 12.6 ;
     RECT  110.819 14.448 115.808 14.472 ;
     RECT  110.704 19.632 115.808 63.528 ;
     RECT  115.808 65.868 115.912 84.252 ;
     RECT  115.912 65.868 116 83.982 ;
     RECT  115.808 1.536 116.104 63.528 ;
     RECT  116 65.598 116.104 83.982 ;
     RECT  116.104 5.472 117.029 7.704 ;
     RECT  116.104 19.632 117.216 63.528 ;
     RECT  117.216 19.632 117.389 62.424 ;
     RECT  117.389 23.328 117.425 62.424 ;
     RECT  117.425 36.672 117.461 59.352 ;
     RECT  117.425 60.384 117.461 62.424 ;
     RECT  117.389 19.632 117.493 22.296 ;
     RECT  117.425 23.424 117.497 35.64 ;
     RECT  116.104 9.6 117.539 9.672 ;
     RECT  116.104 11.952 117.677 12.6 ;
     RECT  116.104 10.704 117.683 10.728 ;
     RECT  116.104 14.448 117.749 14.472 ;
     RECT  117.493 18.816 117.779 22.296 ;
     RECT  117.779 19.632 118.001 22.296 ;
     RECT  118.001 19.632 118.019 22.2 ;
     RECT  118.019 19.632 118.067 22.152 ;
     RECT  117.461 36.768 118.073 56.952 ;
     RECT  116.104 1.536 118.259 4.248 ;
     RECT  117.497 23.424 118.469 35.16 ;
     RECT  118.073 36.768 118.613 55.224 ;
     RECT  117.461 58.08 118.613 58.2 ;
     RECT  117.461 59.232 118.613 59.352 ;
     RECT  118.067 22.032 118.643 22.152 ;
     RECT  118.613 46.176 118.721 55.224 ;
     RECT  118.643 22.128 118.739 22.152 ;
     RECT  117.677 12.576 118.757 12.6 ;
     RECT  117.029 5.472 118.835 7.224 ;
     RECT  118.835 5.616 118.883 7.224 ;
     RECT  118.469 30.624 118.901 35.16 ;
     RECT  118.259 1.584 118.931 4.248 ;
     RECT  118.901 30.624 118.973 31.704 ;
     RECT  118.613 39.36 119.081 44.088 ;
     RECT  118.613 36.768 119.117 38.328 ;
     RECT  119.081 39.36 119.117 41.112 ;
     RECT  119.081 42.144 119.117 44.088 ;
     RECT  118.613 45.12 119.117 45.144 ;
     RECT  118.721 46.752 119.117 55.224 ;
     RECT  118.901 32.736 119.153 35.16 ;
     RECT  119.117 51.168 119.153 55.224 ;
     RECT  118.067 19.632 119.171 20.808 ;
     RECT  119.117 40.896 119.189 40.92 ;
     RECT  117.461 60.384 119.189 62.136 ;
     RECT  118.931 1.632 119.219 4.248 ;
     RECT  119.153 32.832 119.219 35.16 ;
     RECT  119.117 42.144 119.225 42.84 ;
     RECT  119.219 33.024 119.261 35.16 ;
     RECT  118.883 5.808 119.267 7.224 ;
     RECT  118.073 56.352 119.297 56.952 ;
     RECT  119.189 60.384 119.297 61.752 ;
     RECT  119.171 19.824 119.315 20.808 ;
     RECT  119.315 20.352 119.363 20.808 ;
     RECT  119.219 1.632 119.411 3.336 ;
     RECT  119.261 33.024 119.441 34.968 ;
     RECT  119.441 33.408 119.549 34.968 ;
     RECT  119.153 51.168 119.549 55.128 ;
     RECT  119.549 53.184 119.585 55.128 ;
     RECT  119.549 51.264 119.621 51.672 ;
     RECT  119.585 53.184 119.621 53.208 ;
     RECT  119.585 54.432 119.621 54.456 ;
     RECT  118.613 58.08 119.621 58.104 ;
     RECT  119.549 34.56 119.657 34.968 ;
     RECT  119.621 51.648 119.657 51.672 ;
     RECT  119.297 56.352 119.657 56.856 ;
     RECT  118.613 59.232 119.657 59.256 ;
     RECT  119.297 61.248 119.657 61.752 ;
     RECT  119.225 42.816 119.693 42.84 ;
     RECT  119.411 1.632 119.795 2.664 ;
     RECT  119.795 1.632 119.843 1.704 ;
     RECT  118.469 23.424 119.843 29.4 ;
     RECT  118.973 30.624 119.873 31.32 ;
     RECT  119.843 23.616 119.909 29.4 ;
     RECT  117.539 9.648 119.945 9.672 ;
     RECT  119.657 34.56 120.017 34.584 ;
     RECT  119.549 33.408 120.053 33.432 ;
     RECT  119.909 24.672 120.089 29.4 ;
     RECT  119.843 1.68 120.467 1.704 ;
     RECT  119.267 5.808 121.208 5.832 ;
     RECT  119.267 7.2 121.208 7.224 ;
     RECT  119.363 20.784 121.208 20.808 ;
     RECT  119.909 23.616 121.208 23.64 ;
     RECT  120.089 24.672 121.208 27.768 ;
     RECT  120.089 28.896 121.208 29.4 ;
     RECT  119.873 31.008 121.208 31.32 ;
     RECT  119.117 36.768 121.208 36.888 ;
     RECT  121.208 2.148 121.312 84.252 ;
     RECT  121.312 2.418 121.504 83.982 ;
     RECT  121.504 24.672 121.565 25.464 ;
     RECT  121.504 5.808 121.601 5.832 ;
     RECT  121.565 24.96 121.601 25.464 ;
     RECT  121.601 24.96 121.637 25.272 ;
     RECT  121.637 24.96 121.673 24.984 ;
     RECT  126.608 2.148 126.712 84.252 ;
     RECT  126.712 2.418 126.904 83.982 ;
     RECT  132.008 2.148 132.112 84.252 ;
     RECT  132.112 2.418 132.304 83.982 ;
     RECT  137.408 2.148 137.512 84.252 ;
     RECT  137.512 2.418 137.704 83.982 ;
    LAYER M5 ;
     RECT  24.528 0.144 61.272 0.227 ;
     RECT  24.672 0.227 61.272 0.275 ;
     RECT  24.816 0.275 61.272 0.611 ;
     RECT  52.752 0.611 61.272 0.899 ;
     RECT  22.8 0.901 22.824 1.043 ;
     RECT  24.816 0.611 51.768 1.139 ;
     RECT  25.392 1.139 51.768 1.187 ;
     RECT  25.392 1.187 51.624 1.379 ;
     RECT  25.392 1.379 47.448 1.427 ;
     RECT  26.544 1.427 47.448 1.475 ;
     RECT  118.224 1.525 118.248 1.573 ;
     RECT  118.224 1.573 118.92 1.621 ;
     RECT  26.544 1.475 41.208 1.667 ;
     RECT  118.224 1.621 119.832 1.669 ;
     RECT  27.264 1.667 41.208 1.763 ;
     RECT  52.752 0.899 61.128 1.763 ;
     RECT  66.576 0.144 67.896 1.763 ;
     RECT  70.512 0.144 71.112 1.763 ;
     RECT  54.048 1.763 61.128 1.811 ;
     RECT  70.656 1.763 70.68 1.859 ;
     RECT  60.672 1.811 61.128 1.907 ;
     RECT  12.048 1.093 12.072 1.909 ;
     RECT  61.104 1.907 61.128 2.137 ;
     RECT  118.224 1.669 120.456 2.137 ;
     RECT  48.432 1.379 51.624 2.147 ;
     RECT  2.4 2.137 2.52 2.151 ;
     RECT  7.8 2.137 7.92 2.151 ;
     RECT  13.2 2.137 13.32 2.151 ;
     RECT  18.6 2.137 18.72 2.151 ;
     RECT  24 2.137 24.12 2.151 ;
     RECT  61.104 2.137 61.92 2.151 ;
     RECT  72.6 2.137 72.72 2.151 ;
     RECT  78 2.137 78.12 2.151 ;
     RECT  83.4 2.137 83.52 2.151 ;
     RECT  88.8 2.137 88.92 2.151 ;
     RECT  94.2 2.137 94.32 2.151 ;
     RECT  99.6 2.137 99.72 2.151 ;
     RECT  105 2.137 105.12 2.151 ;
     RECT  110.4 2.137 110.52 2.151 ;
     RECT  115.8 2.137 115.92 2.151 ;
     RECT  118.224 2.137 121.32 2.151 ;
     RECT  126.6 2.137 126.72 2.151 ;
     RECT  132 2.137 132.12 2.151 ;
     RECT  137.4 2.137 137.52 2.151 ;
     RECT  48.432 2.147 49.32 2.195 ;
     RECT  25.392 1.427 25.416 2.291 ;
     RECT  7.8 2.151 8.112 2.341 ;
     RECT  27.84 1.763 41.208 2.483 ;
     RECT  54.048 1.811 59.4 2.579 ;
     RECT  118.224 2.151 121.512 2.581 ;
     RECT  31.584 2.483 41.208 2.677 ;
     RECT  42.192 1.475 47.448 2.677 ;
     RECT  61.104 2.151 62.112 2.725 ;
     RECT  21.264 2.725 21.288 2.773 ;
     RECT  61.104 2.725 62.712 2.819 ;
     RECT  66.864 1.763 67.896 2.819 ;
     RECT  61.8 2.819 62.712 2.869 ;
     RECT  27.84 2.483 30.312 2.915 ;
     RECT  31.584 2.677 47.448 2.915 ;
     RECT  50.304 2.147 51.624 2.915 ;
     RECT  54.048 2.579 59.208 2.915 ;
     RECT  31.584 2.915 32.616 3.011 ;
     RECT  52.896 1.763 52.92 3.107 ;
     RECT  48.432 2.195 49.032 3.155 ;
     RECT  54.048 2.915 57.096 3.157 ;
     RECT  33.84 2.915 47.448 3.253 ;
     RECT  48.432 3.155 48.936 3.253 ;
     RECT  6.864 2.341 8.112 3.349 ;
     RECT  9.648 1.621 9.672 3.349 ;
     RECT  11.424 1.909 12.072 3.397 ;
     RECT  13.2 2.151 13.512 3.397 ;
     RECT  50.304 2.915 51.312 3.443 ;
     RECT  67.2 2.819 67.896 3.443 ;
     RECT  31.728 3.011 32.616 3.683 ;
     RECT  33.84 3.253 48.936 3.731 ;
     RECT  52.416 3.109 52.44 3.827 ;
     RECT  61.8 2.869 62.808 3.827 ;
     RECT  31.728 3.683 31.752 3.875 ;
     RECT  29.136 2.915 30.312 4.019 ;
     RECT  33.888 3.731 41.304 4.019 ;
     RECT  11.424 3.397 13.512 4.021 ;
     RECT  29.136 4.019 30.168 4.069 ;
     RECT  11.424 4.021 13.608 4.117 ;
     RECT  24 2.151 24.312 4.261 ;
     RECT  61.8 3.827 62.112 4.405 ;
     RECT  22.8 4.117 22.824 4.499 ;
     RECT  67.2 3.443 67.608 4.501 ;
     RECT  72.6 2.151 72.912 4.501 ;
     RECT  88.8 2.151 89.112 4.501 ;
     RECT  42.288 3.731 48.936 4.547 ;
     RECT  21.264 2.773 21.384 4.549 ;
     RECT  43.632 4.547 48.936 4.549 ;
     RECT  24 4.261 24.408 4.595 ;
     RECT  28.656 4.069 30.168 4.595 ;
     RECT  53.712 3.157 57.096 4.691 ;
     RECT  58.656 2.915 59.208 4.693 ;
     RECT  58.656 4.693 59.736 4.739 ;
     RECT  33.888 4.019 37.848 4.741 ;
     RECT  53.712 4.691 54.648 4.741 ;
     RECT  43.632 4.549 49.08 4.787 ;
     RECT  55.632 4.691 57.096 4.789 ;
     RECT  61.68 4.405 62.112 4.835 ;
     RECT  52.752 4.741 54.648 4.931 ;
     RECT  55.632 4.789 57.144 4.931 ;
     RECT  59.712 4.739 59.736 4.931 ;
     RECT  3.984 4.885 4.008 4.933 ;
     RECT  88.224 4.501 89.112 4.981 ;
     RECT  2.4 2.151 2.712 5.029 ;
     RECT  10.944 4.117 13.608 5.029 ;
     RECT  14.832 2.773 14.856 5.029 ;
     RECT  71.904 4.501 72.912 5.029 ;
     RECT  33.072 4.741 37.848 5.075 ;
     RECT  50.832 3.443 51.312 5.075 ;
     RECT  21.12 4.549 21.384 5.077 ;
     RECT  26.208 3.925 26.232 5.077 ;
     RECT  27.312 3.109 27.336 5.077 ;
     RECT  28.656 4.595 30.072 5.123 ;
     RECT  26.208 5.077 27.336 5.125 ;
     RECT  26.016 5.125 27.336 5.171 ;
     RECT  53.712 4.931 54.648 5.171 ;
     RECT  55.632 4.931 57.096 5.171 ;
     RECT  58.656 4.739 58.68 5.171 ;
     RECT  76.704 5.029 76.728 5.173 ;
     RECT  94.2 2.151 94.512 5.221 ;
     RECT  21.12 5.077 21.528 5.269 ;
     RECT  91.392 5.221 91.416 5.269 ;
     RECT  87.312 4.981 89.112 5.317 ;
     RECT  26.016 5.171 26.808 5.363 ;
     RECT  20.4 5.269 21.528 5.365 ;
     RECT  91.392 5.269 91.512 5.411 ;
     RECT  18.6 2.151 18.912 5.461 ;
     RECT  20.4 5.365 21.576 5.461 ;
     RECT  94.2 5.221 94.872 5.461 ;
     RECT  43.632 4.787 48.456 5.507 ;
     RECT  43.632 5.507 47.448 5.509 ;
     RECT  29.04 5.123 30.072 5.555 ;
     RECT  43.584 5.509 47.448 5.555 ;
     RECT  53.712 5.171 54.216 5.555 ;
     RECT  16.656 5.509 16.68 5.557 ;
     RECT  39.216 4.019 41.304 5.557 ;
     RECT  69.456 4.501 69.48 5.557 ;
     RECT  78 2.151 78.312 5.557 ;
     RECT  115.8 2.151 116.112 5.557 ;
     RECT  80.976 5.365 81 5.605 ;
     RECT  26.016 5.363 26.04 5.651 ;
     RECT  48.432 5.507 48.456 5.651 ;
     RECT  86.016 5.317 89.112 5.653 ;
     RECT  39.216 5.557 42.024 5.699 ;
     RECT  6.864 3.349 9.672 5.701 ;
     RECT  24 4.595 24.312 5.701 ;
     RECT  47.376 5.555 47.448 5.747 ;
     RECT  6.48 5.701 9.672 5.749 ;
     RECT  76.704 5.173 76.968 5.749 ;
     RECT  93.6 5.461 94.872 5.749 ;
     RECT  95.952 5.221 95.976 5.749 ;
     RECT  6.48 5.749 9.864 5.797 ;
     RECT  10.944 5.029 14.856 5.797 ;
     RECT  16.464 5.557 16.68 5.797 ;
     RECT  71.088 5.029 72.912 5.797 ;
     RECT  80.976 5.605 81.864 5.797 ;
     RECT  93.6 5.749 95.976 5.797 ;
     RECT  47.376 5.747 47.4 5.843 ;
     RECT  75.264 5.557 75.288 5.845 ;
     RECT  76.368 5.749 76.968 5.845 ;
     RECT  78 5.557 78.648 5.845 ;
     RECT  69.456 5.557 69.576 5.893 ;
     RECT  71.088 5.797 73.032 5.893 ;
     RECT  43.584 5.555 46.2 5.939 ;
     RECT  31.152 5.125 31.176 5.941 ;
     RECT  44.304 5.939 46.2 5.987 ;
     RECT  74.976 5.845 78.648 5.987 ;
     RECT  6.48 5.797 14.856 5.989 ;
     RECT  61.8 4.835 62.112 5.989 ;
     RECT  74.976 5.987 75.864 5.989 ;
     RECT  80.976 5.797 82.056 5.989 ;
     RECT  83.4 2.151 83.712 5.989 ;
     RECT  114.576 5.845 114.6 6.035 ;
     RECT  18.6 5.461 21.576 6.037 ;
     RECT  22.752 5.077 22.776 6.037 ;
     RECT  69.168 5.893 69.576 6.037 ;
     RECT  70.656 5.893 73.032 6.037 ;
     RECT  80.976 5.989 83.712 6.037 ;
     RECT  24 5.701 24.408 6.083 ;
     RECT  16.464 5.797 17.208 6.085 ;
     RECT  115.8 5.557 117.048 6.085 ;
     RECT  118.08 2.581 121.512 6.085 ;
     RECT  44.4 5.987 46.008 6.131 ;
     RECT  16.464 6.085 17.544 6.133 ;
     RECT  18.6 6.037 22.776 6.133 ;
     RECT  67.2 4.501 68.04 6.133 ;
     RECT  66.912 6.133 68.04 6.181 ;
     RECT  69.168 6.037 73.032 6.181 ;
     RECT  100.896 5.461 100.92 6.181 ;
     RECT  102.432 5.749 102.456 6.181 ;
     RECT  66.912 6.181 73.032 6.229 ;
     RECT  93.504 5.797 95.976 6.229 ;
     RECT  44.448 6.131 46.008 6.275 ;
     RECT  3.984 4.933 4.152 6.277 ;
     RECT  54.192 5.555 54.216 6.323 ;
     RECT  55.632 5.171 56.712 6.323 ;
     RECT  80.976 6.037 83.928 6.325 ;
     RECT  84.912 5.845 84.936 6.325 ;
     RECT  92.88 6.229 95.976 6.371 ;
     RECT  44.592 6.275 46.008 6.419 ;
     RECT  93.936 6.371 95.976 6.419 ;
     RECT  80.976 6.325 84.936 6.467 ;
     RECT  6.48 5.989 15 6.565 ;
     RECT  76.944 5.987 78.648 6.565 ;
     RECT  86.016 5.653 89.592 6.611 ;
     RECT  66.624 6.229 73.032 6.613 ;
     RECT  81.84 6.467 84.936 6.613 ;
     RECT  97.728 6.469 97.752 6.613 ;
     RECT  29.232 5.555 30.072 6.661 ;
     RECT  31.152 5.941 31.512 6.661 ;
     RECT  66.624 6.613 73.272 6.661 ;
     RECT  74.448 5.989 75.864 6.661 ;
     RECT  91.392 5.411 91.416 6.661 ;
     RECT  92.88 6.371 92.952 6.661 ;
     RECT  29.232 6.661 31.512 6.709 ;
     RECT  39.216 5.699 41.16 6.757 ;
     RECT  63.648 5.077 63.672 6.757 ;
     RECT  29.232 6.709 31.896 6.803 ;
     RECT  24 6.083 24.312 6.805 ;
     RECT  33.888 5.075 37.848 6.805 ;
     RECT  39.216 6.757 41.352 6.805 ;
     RECT  63.648 6.757 63.72 6.805 ;
     RECT  90.672 6.661 91.416 6.805 ;
     RECT  92.64 6.661 92.952 6.805 ;
     RECT  94.032 6.419 95.976 6.805 ;
     RECT  105 2.151 105.312 6.805 ;
     RECT  29.4 6.803 31.896 6.851 ;
     RECT  44.592 6.419 45.912 6.851 ;
     RECT  65.232 6.709 65.256 6.853 ;
     RECT  63.648 6.805 63.816 6.901 ;
     RECT  76.944 6.565 79.464 6.901 ;
     RECT  94.032 6.805 96.312 6.949 ;
     RECT  97.728 6.613 98.136 6.949 ;
     RECT  5.76 6.565 15 6.997 ;
     RECT  5.76 6.997 15.048 7.093 ;
     RECT  63.36 6.901 63.816 7.093 ;
     RECT  64.8 6.853 65.496 7.093 ;
     RECT  94.032 6.949 98.136 7.093 ;
     RECT  60.864 5.989 62.112 7.139 ;
     RECT  66.624 6.661 75.864 7.189 ;
     RECT  76.944 6.901 80.76 7.189 ;
     RECT  81.84 6.613 84.984 7.189 ;
     RECT  86.016 6.611 89.304 7.189 ;
     RECT  94.032 7.093 98.616 7.189 ;
     RECT  99.6 2.151 99.912 7.189 ;
     RECT  105 6.805 106.248 7.189 ;
     RECT  51 5.075 51.312 7.237 ;
     RECT  104.064 7.189 106.248 7.237 ;
     RECT  94.032 7.189 99.912 7.285 ;
     RECT  100.896 6.181 102.456 7.285 ;
     RECT  5.76 7.093 15.336 7.333 ;
     RECT  16.464 6.133 22.776 7.333 ;
     RECT  47.904 7.237 47.928 7.333 ;
     RECT  58.992 7.285 59.016 7.333 ;
     RECT  33.888 6.805 41.352 7.381 ;
     RECT  53.52 6.805 53.544 7.381 ;
     RECT  47.904 7.333 48.216 7.429 ;
     RECT  44.688 6.851 45.912 7.621 ;
     RECT  81.84 7.189 89.304 7.621 ;
     RECT  90.672 6.805 92.952 7.621 ;
     RECT  33.36 7.381 41.352 7.667 ;
     RECT  44.688 7.621 46.152 7.669 ;
     RECT  47.904 7.429 49.032 7.715 ;
     RECT  31.488 6.851 31.896 7.717 ;
     RECT  66.624 7.189 80.76 7.717 ;
     RECT  81.84 7.621 92.952 7.717 ;
     RECT  94.032 7.285 102.456 7.717 ;
     RECT  103.776 7.237 106.248 7.717 ;
     RECT  44.688 7.669 46.248 7.765 ;
     RECT  63.36 7.093 65.496 7.813 ;
     RECT  94.032 7.717 106.248 7.813 ;
     RECT  33.36 7.667 33.384 7.861 ;
     RECT  31.488 7.717 31.944 7.909 ;
     RECT  52.8 7.381 53.544 7.909 ;
     RECT  58.128 7.333 59.016 7.909 ;
     RECT  54.768 7.669 54.792 7.955 ;
     RECT  63.264 7.813 65.496 7.955 ;
     RECT  29.4 6.851 29.712 7.957 ;
     RECT  34.416 7.667 41.352 7.957 ;
     RECT  51 7.237 51.768 7.957 ;
     RECT  52.8 7.909 53.784 7.957 ;
     RECT  58.128 7.909 59.208 7.957 ;
     RECT  30.864 7.909 31.992 8.005 ;
     RECT  33.12 7.861 33.384 8.005 ;
     RECT  47.904 7.715 48.216 8.147 ;
     RECT  66.624 7.717 92.952 8.147 ;
     RECT  50.592 7.957 51.768 8.197 ;
     RECT  52.8 7.957 54.264 8.197 ;
     RECT  94.032 7.813 106.584 8.243 ;
     RECT  44.688 7.765 46.632 8.245 ;
     RECT  47.904 8.147 47.928 8.245 ;
     RECT  44.688 8.245 47.928 8.293 ;
     RECT  66.624 8.147 76.392 8.293 ;
     RECT  77.568 8.147 92.952 8.293 ;
     RECT  94.032 8.243 106.392 8.293 ;
     RECT  23.76 6.805 24.312 8.341 ;
     RECT  34.416 7.957 41.88 8.341 ;
     RECT  57.84 7.957 59.208 8.341 ;
     RECT  61.8 7.139 62.112 8.341 ;
     RECT  29.04 7.957 29.712 8.389 ;
     RECT  61.8 8.341 62.232 8.483 ;
     RECT  28.8 8.389 29.712 8.485 ;
     RECT  30.864 8.005 33.384 8.485 ;
     RECT  50.592 8.197 54.264 8.485 ;
     RECT  23.76 8.341 24.888 8.533 ;
     RECT  63.36 7.955 65.496 8.533 ;
     RECT  66.576 8.293 76.392 8.533 ;
     RECT  44.4 8.293 47.928 8.579 ;
     RECT  5.76 7.333 22.776 8.581 ;
     RECT  23.76 8.533 25.032 8.581 ;
     RECT  61.8 8.483 62.112 8.677 ;
     RECT  34.416 8.341 42.168 8.773 ;
     RECT  56.4 6.323 56.712 8.773 ;
     RECT  34.416 8.773 42.312 8.821 ;
     RECT  5.76 8.581 25.032 8.965 ;
     RECT  108.288 7.909 108.312 9.013 ;
     RECT  28.8 8.485 33.384 9.061 ;
     RECT  34.416 8.821 43.128 9.061 ;
     RECT  56.256 8.773 56.712 9.061 ;
     RECT  57.84 8.341 59.352 9.061 ;
     RECT  108.288 9.013 108.456 9.155 ;
     RECT  49.92 8.485 54.264 9.157 ;
     RECT  108.432 9.155 108.456 9.157 ;
     RECT  49.92 9.157 54.504 9.253 ;
     RECT  61.68 8.677 62.112 9.253 ;
     RECT  108.432 9.157 108.648 9.253 ;
     RECT  28.8 9.061 43.128 9.301 ;
     RECT  63.36 8.533 76.392 9.301 ;
     RECT  77.568 8.293 106.392 9.301 ;
     RECT  49.44 9.253 54.744 9.395 ;
     RECT  63.36 9.301 106.392 9.539 ;
     RECT  5.76 8.965 25.512 9.541 ;
     RECT  61.344 9.253 62.112 9.541 ;
     RECT  2.4 5.029 3 9.589 ;
     RECT  3.984 6.277 4.728 9.589 ;
     RECT  5.76 9.541 26.472 9.637 ;
     RECT  27.936 9.301 43.128 9.637 ;
     RECT  69.456 9.539 106.392 9.637 ;
     RECT  63.36 9.539 68.472 9.683 ;
     RECT  5.76 9.637 43.128 9.685 ;
     RECT  69.456 9.637 106.44 9.731 ;
     RECT  60.48 9.541 62.112 9.781 ;
     RECT  5.76 9.685 43.32 9.875 ;
     RECT  2.4 9.589 4.728 9.925 ;
     RECT  5.76 9.875 42.6 9.925 ;
     RECT  76.368 9.731 106.44 9.971 ;
     RECT  44.4 8.579 47.88 9.973 ;
     RECT  76.464 9.971 106.44 10.165 ;
     RECT  2.4 9.925 42.6 10.211 ;
     RECT  76.464 10.165 106.632 10.213 ;
     RECT  2.4 10.211 42.552 10.259 ;
     RECT  49.44 9.395 54.504 10.357 ;
     RECT  76.464 10.213 107.208 10.403 ;
     RECT  60.336 9.781 62.112 10.453 ;
     RECT  63.36 9.683 68.376 10.453 ;
     RECT  110.4 2.151 110.712 10.453 ;
     RECT  56.256 9.061 59.352 10.693 ;
     RECT  85.584 10.403 107.208 10.693 ;
     RECT  108.432 9.253 108.84 10.693 ;
     RECT  27.888 10.259 42.552 10.787 ;
     RECT  55.68 10.693 59.352 10.933 ;
     RECT  60.336 10.453 68.376 10.933 ;
     RECT  55.68 10.933 68.376 11.173 ;
     RECT  55.68 11.173 68.424 11.269 ;
     RECT  69.456 9.731 75.384 11.269 ;
     RECT  55.68 11.269 75.384 11.461 ;
     RECT  76.464 10.403 84.552 11.461 ;
     RECT  110.304 10.453 110.712 11.509 ;
     RECT  110.256 11.509 110.712 11.557 ;
     RECT  108.432 10.693 108.936 11.651 ;
     RECT  27.936 10.787 42.552 11.749 ;
     RECT  43.872 9.973 47.88 11.749 ;
     RECT  48.96 10.357 54.504 11.749 ;
     RECT  110.16 11.557 110.712 11.749 ;
     RECT  43.872 11.749 54.504 11.797 ;
     RECT  55.68 11.461 84.552 11.797 ;
     RECT  85.584 10.693 107.4 11.797 ;
     RECT  55.68 11.797 107.4 12.035 ;
     RECT  27.936 11.749 42.648 12.085 ;
     RECT  55.68 12.035 75.816 12.275 ;
     RECT  27.936 12.085 42.744 12.277 ;
     RECT  43.872 11.797 54.648 12.277 ;
     RECT  2.4 10.259 26.664 12.373 ;
     RECT  2.4 12.373 26.76 12.421 ;
     RECT  27.936 12.277 54.648 12.421 ;
     RECT  108.432 11.651 108.744 12.611 ;
     RECT  76.896 12.035 107.4 12.803 ;
     RECT  58.032 12.275 75.816 13.045 ;
     RECT  76.896 12.803 102.12 13.045 ;
     RECT  2.4 12.421 54.648 13.763 ;
     RECT  103.104 12.803 107.4 13.811 ;
     RECT  58.032 13.045 102.12 13.907 ;
     RECT  103.104 13.811 107.304 13.907 ;
     RECT  58.032 13.907 102.072 13.955 ;
     RECT  110.064 11.749 110.712 14.197 ;
     RECT  58.032 13.955 74.616 14.389 ;
     RECT  75.648 13.955 102.072 14.675 ;
     RECT  109.968 14.197 110.712 14.725 ;
     RECT  48.816 13.763 54.648 14.773 ;
     RECT  55.68 12.275 56.904 14.773 ;
     RECT  57.888 14.389 74.616 14.773 ;
     RECT  108.432 12.611 108.6 14.773 ;
     RECT  109.968 14.725 110.808 14.773 ;
     RECT  55.68 14.773 74.616 14.917 ;
     RECT  75.648 14.675 99.912 14.917 ;
     RECT  2.4 13.763 47.736 15.061 ;
     RECT  48.72 14.773 54.648 15.061 ;
     RECT  108.432 14.773 110.808 15.301 ;
     RECT  55.68 14.917 99.912 15.347 ;
     RECT  101.04 14.675 102.072 15.635 ;
     RECT  103.104 13.907 107.256 15.973 ;
     RECT  108.288 15.301 110.808 15.973 ;
     RECT  76.032 15.347 99.912 16.645 ;
     RECT  75.84 16.645 99.912 16.789 ;
     RECT  101.184 15.635 102.072 16.885 ;
     RECT  103.104 15.973 110.808 16.885 ;
     RECT  75.84 16.789 100.2 16.981 ;
     RECT  101.184 16.885 110.808 16.981 ;
     RECT  2.4 15.061 54.648 17.171 ;
     RECT  75.84 16.981 110.808 17.363 ;
     RECT  77.376 17.363 110.808 17.411 ;
     RECT  97.68 17.411 110.808 17.459 ;
     RECT  2.4 17.171 54.072 17.507 ;
     RECT  77.376 17.411 96.168 17.507 ;
     RECT  97.68 17.459 110.712 17.651 ;
     RECT  55.68 15.347 74.76 17.653 ;
     RECT  36.912 17.507 54.072 17.699 ;
     RECT  75.84 17.363 76.392 17.699 ;
     RECT  97.68 17.651 98.472 17.699 ;
     RECT  36.912 17.699 53.736 17.747 ;
     RECT  55.104 17.653 74.76 17.891 ;
     RECT  97.68 17.699 97.992 17.891 ;
     RECT  45.6 17.747 53.736 17.939 ;
     RECT  77.616 17.507 96.168 17.939 ;
     RECT  95.904 17.939 96.168 17.987 ;
     RECT  75.84 17.699 76.008 17.989 ;
     RECT  75.792 17.989 76.008 18.131 ;
     RECT  36.912 17.747 44.616 18.275 ;
     RECT  45.6 17.939 53.592 18.323 ;
     RECT  55.2 17.891 74.76 18.323 ;
     RECT  77.616 17.939 94.632 18.323 ;
     RECT  77.616 18.323 91.272 18.419 ;
     RECT  74.304 18.323 74.76 18.467 ;
     RECT  77.616 18.419 85.992 18.467 ;
     RECT  47.328 18.323 53.592 18.515 ;
     RECT  96 17.987 96.168 18.563 ;
     RECT  92.496 18.323 94.632 18.611 ;
     RECT  75.792 18.131 75.864 18.707 ;
     RECT  78 18.467 85.992 18.707 ;
     RECT  87.12 18.419 91.272 18.707 ;
     RECT  55.2 18.323 67.608 18.755 ;
     RECT  60.432 18.755 67.608 18.803 ;
     RECT  82.368 18.707 85.992 18.803 ;
     RECT  50.4 18.515 53.592 18.851 ;
     RECT  78 18.707 81.192 18.851 ;
     RECT  82.368 18.803 84.552 18.851 ;
     RECT  97.68 17.891 97.848 18.851 ;
     RECT  99.504 17.651 110.712 18.851 ;
     RECT  99.504 18.851 103.944 18.899 ;
     RECT  97.68 18.851 97.752 18.901 ;
     RECT  50.88 18.851 53.592 18.947 ;
     RECT  55.2 18.755 59.16 18.947 ;
     RECT  85.776 18.803 85.992 18.947 ;
     RECT  92.688 18.611 94.632 18.947 ;
     RECT  97.632 18.901 97.752 18.947 ;
     RECT  99.504 18.899 100.296 18.947 ;
     RECT  103.488 18.899 103.944 18.947 ;
     RECT  36.912 18.275 44.472 18.995 ;
     RECT  78 18.851 81 18.995 ;
     RECT  90.528 18.707 91.272 18.995 ;
     RECT  103.728 18.947 103.944 18.995 ;
     RECT  105 18.851 110.712 18.995 ;
     RECT  97.632 18.947 97.656 19.043 ;
     RECT  105 18.995 108.456 19.043 ;
     RECT  68.88 18.323 72.912 19.091 ;
     RECT  92.688 18.947 93.192 19.091 ;
     RECT  106.512 19.043 108.456 19.091 ;
     RECT  2.4 17.507 35.784 19.093 ;
     RECT  36.912 18.995 39.048 19.093 ;
     RECT  92.688 19.091 93.096 19.139 ;
     RECT  2.4 19.093 39.048 19.187 ;
     RECT  60.432 18.803 67.512 19.187 ;
     RECT  69.072 19.091 72.912 19.187 ;
     RECT  74.592 18.467 74.76 19.187 ;
     RECT  93.072 19.139 93.096 19.187 ;
     RECT  40.2 18.995 44.472 19.235 ;
     RECT  70.32 19.187 72.912 19.235 ;
     RECT  78 18.995 79.416 19.235 ;
     RECT  90.528 18.995 90.888 19.235 ;
     RECT  101.424 18.899 102.216 19.235 ;
     RECT  108.288 19.091 108.456 19.235 ;
     RECT  96.144 18.563 96.168 19.237 ;
     RECT  2.4 19.187 28.248 19.283 ;
     RECT  56.208 18.947 56.712 19.283 ;
     RECT  57.888 18.947 59.16 19.283 ;
     RECT  99.504 18.947 99.912 19.283 ;
     RECT  106.512 19.091 107.256 19.283 ;
     RECT  108.432 19.235 108.456 19.283 ;
     RECT  109.968 18.995 110.712 19.283 ;
     RECT  52.752 18.947 53.592 19.331 ;
     RECT  83.4 18.851 84.408 19.331 ;
     RECT  60.432 19.187 63.816 19.379 ;
     RECT  69.072 19.187 69.096 19.379 ;
     RECT  75.792 18.707 75.816 19.379 ;
     RECT  90.864 19.235 90.888 19.379 ;
     RECT  50.88 18.947 51.432 19.427 ;
     RECT  53.568 19.331 53.592 19.427 ;
     RECT  64.8 19.187 67.512 19.427 ;
     RECT  85.968 18.947 85.992 19.427 ;
     RECT  87.12 18.707 89.256 19.427 ;
     RECT  94.2 18.947 94.632 19.427 ;
     RECT  107.232 19.283 107.256 19.427 ;
     RECT  70.32 19.235 71.304 19.475 ;
     RECT  78 19.235 78.792 19.475 ;
     RECT  80.544 18.995 81 19.475 ;
     RECT  87.12 19.427 89.112 19.475 ;
     RECT  70.32 19.475 70.344 19.523 ;
     RECT  96.144 19.237 96.936 19.523 ;
     RECT  103.728 18.995 103.752 19.523 ;
     RECT  51 19.427 51.432 19.571 ;
     RECT  74.736 19.187 74.76 19.571 ;
     RECT  96.912 19.523 96.936 19.571 ;
     RECT  80.544 19.475 80.568 19.619 ;
     RECT  45.6 18.323 46.296 19.621 ;
     RECT  47.328 18.515 49.272 19.621 ;
     RECT  101.712 19.235 102.216 19.763 ;
     RECT  61.296 19.379 63.816 19.811 ;
     RECT  102.192 19.763 102.216 19.811 ;
     RECT  66.624 19.427 67.512 19.859 ;
     RECT  45.6 19.621 49.272 19.909 ;
     RECT  87.744 19.475 89.112 20.003 ;
     RECT  2.4 19.283 24.456 20.389 ;
     RECT  25.536 19.283 28.248 20.389 ;
     RECT  59.088 19.283 59.16 20.435 ;
     RECT  57.888 19.283 57.912 20.579 ;
     RECT  88.224 20.003 89.112 20.867 ;
     RECT  2.4 20.389 28.248 21.061 ;
     RECT  29.4 19.187 39.048 21.061 ;
     RECT  55.2 18.947 55.224 21.061 ;
     RECT  55.056 21.061 55.224 21.107 ;
     RECT  2.4 21.061 39.048 21.109 ;
     RECT  40.2 19.235 44.376 21.109 ;
     RECT  64.8 19.427 64.824 21.155 ;
     RECT  85.584 20.149 85.608 21.491 ;
     RECT  55.056 21.107 55.08 21.683 ;
     RECT  2.4 21.109 44.376 21.685 ;
     RECT  45.6 19.909 49.56 21.685 ;
     RECT  2.4 21.685 49.56 21.877 ;
     RECT  59.088 20.435 59.112 22.019 ;
     RECT  61.296 19.811 62.952 22.067 ;
     RECT  115.8 6.085 121.512 22.403 ;
     RECT  2.4 21.877 49.608 26.245 ;
     RECT  117.144 22.403 121.512 26.627 ;
     RECT  0.24 29.605 0.264 30.181 ;
     RECT  117.144 26.627 119.4 30.851 ;
     RECT  0.24 30.181 0.312 31.189 ;
     RECT  118.704 30.851 119.4 31.523 ;
     RECT  118.848 31.523 119.4 31.619 ;
     RECT  0.192 31.189 0.312 31.861 ;
     RECT  0.192 31.861 0.36 32.341 ;
     RECT  119.184 31.619 119.4 32.867 ;
     RECT  0.192 32.341 0.408 34.117 ;
     RECT  0.192 34.117 0.456 34.307 ;
     RECT  119.376 32.867 119.4 34.403 ;
     RECT  0.192 34.307 0.408 34.451 ;
     RECT  0.192 34.451 0.36 34.595 ;
     RECT  0.192 34.595 0.312 36.179 ;
     RECT  0.288 36.179 0.312 37.091 ;
     RECT  0.24 47.845 0.264 52.067 ;
     RECT  117.144 30.851 117.24 63.528 ;
     RECT  2.304 26.245 49.608 63.827 ;
     RECT  2.304 63.827 45.912 63.971 ;
     RECT  2.304 63.971 38.232 64.115 ;
     RECT  2.304 64.115 33.384 64.643 ;
     RECT  23.088 64.643 32.808 64.691 ;
     RECT  61.8 22.067 62.952 64.691 ;
     RECT  46.992 63.827 49.608 64.739 ;
     RECT  2.304 64.643 22.056 64.979 ;
     RECT  32.736 64.691 32.808 65.027 ;
     RECT  34.416 64.115 38.232 65.171 ;
     RECT  38.208 65.171 38.232 65.219 ;
     RECT  34.416 65.171 37.08 65.267 ;
     RECT  39.648 63.971 45.912 65.507 ;
     RECT  41.616 65.507 45.912 65.699 ;
     RECT  41.616 65.699 44.328 65.747 ;
     RECT  34.416 65.267 36.888 65.797 ;
     RECT  23.088 64.691 31.32 66.325 ;
     RECT  38.208 66.325 38.232 66.373 ;
     RECT  2.4 64.979 22.056 66.469 ;
     RECT  23.04 66.325 31.32 66.469 ;
     RECT  32.736 65.027 32.76 66.565 ;
     RECT  2.4 66.469 31.32 66.613 ;
     RECT  42.192 65.747 44.328 67.045 ;
     RECT  38.208 66.373 38.424 67.187 ;
     RECT  33.888 65.797 36.888 67.237 ;
     RECT  42.048 67.045 44.328 67.237 ;
     RECT  2.4 66.613 31.416 67.285 ;
     RECT  32.496 66.565 32.76 67.285 ;
     RECT  41.568 67.237 44.328 67.429 ;
     RECT  45.312 65.699 45.912 67.429 ;
     RECT  2.4 67.285 32.76 68.005 ;
     RECT  33.888 67.237 37.08 68.005 ;
     RECT  2.4 68.005 37.08 68.197 ;
     RECT  38.208 67.187 38.376 68.197 ;
     RECT  46.992 64.739 49.56 68.435 ;
     RECT  46.992 68.435 48.984 68.963 ;
     RECT  41.568 67.429 45.912 68.965 ;
     RECT  39.648 65.507 40.512 69.829 ;
     RECT  41.52 68.965 45.912 69.829 ;
     RECT  2.4 68.197 38.376 69.875 ;
     RECT  4.992 69.875 38.376 70.307 ;
     RECT  46.992 68.963 48.84 70.405 ;
     RECT  39.648 69.829 45.912 70.787 ;
     RECT  2.4 69.875 3.96 70.835 ;
     RECT  39.648 70.787 44.424 71.267 ;
     RECT  4.992 70.307 32.472 71.749 ;
     RECT  33.648 70.307 38.376 71.749 ;
     RECT  2.4 70.835 3.864 72.133 ;
     RECT  45.504 70.787 45.912 72.325 ;
     RECT  46.992 70.405 48.888 72.325 ;
     RECT  40.2 71.267 44.424 72.467 ;
     RECT  45.504 72.325 48.888 72.565 ;
     RECT  4.992 71.749 38.376 73.093 ;
     RECT  4.992 73.093 38.808 73.525 ;
     RECT  40.2 72.467 44.088 73.813 ;
     RECT  40.08 73.813 44.088 74.051 ;
     RECT  4.992 73.525 38.952 74.147 ;
     RECT  4.992 74.147 38.808 74.195 ;
     RECT  9.648 74.195 38.808 74.339 ;
     RECT  37.584 74.339 38.808 74.387 ;
     RECT  9.648 74.339 36.456 74.483 ;
     RECT  40.2 74.051 44.088 74.629 ;
     RECT  45.504 72.565 48.936 74.629 ;
     RECT  33.168 74.483 36.456 74.675 ;
     RECT  33.168 74.675 35.736 74.867 ;
     RECT  40.2 74.629 48.936 74.963 ;
     RECT  40.2 74.963 42.024 75.107 ;
     RECT  43.056 74.963 48.936 75.107 ;
     RECT  42 75.107 42.024 75.155 ;
     RECT  40.2 75.107 40.824 75.157 ;
     RECT  33.168 74.867 35.256 75.203 ;
     RECT  4.992 74.195 8.616 75.299 ;
     RECT  33.168 75.203 35.112 75.299 ;
     RECT  43.584 75.107 48.936 75.299 ;
     RECT  9.648 74.483 32.184 75.491 ;
     RECT  10.56 75.491 32.184 75.683 ;
     RECT  44.928 75.299 48.936 75.781 ;
     RECT  10.992 75.683 32.184 75.829 ;
     RECT  44.928 75.781 48.984 75.971 ;
     RECT  39.792 75.157 40.824 76.261 ;
     RECT  39.792 76.261 41.112 76.403 ;
     RECT  5.52 75.299 8.616 76.787 ;
     RECT  10.992 75.829 32.712 76.835 ;
     RECT  40.2 76.403 41.112 77.027 ;
     RECT  37.584 74.387 38.376 77.125 ;
     RECT  11.856 76.835 32.712 77.173 ;
     RECT  33.888 75.299 35.112 77.173 ;
     RECT  37.488 77.125 38.376 77.365 ;
     RECT  11.856 77.173 35.112 77.603 ;
     RECT  37.488 77.365 38.664 77.797 ;
     RECT  40.2 77.027 40.824 77.797 ;
     RECT  42.24 76.741 42.264 77.845 ;
     RECT  43.728 75.299 43.752 77.845 ;
     RECT  11.856 77.603 17.256 77.987 ;
     RECT  46.944 75.971 48.984 78.131 ;
     RECT  12.912 77.987 17.256 78.179 ;
     RECT  36.192 77.317 36.216 78.373 ;
     RECT  37.488 77.797 40.824 78.373 ;
     RECT  12.912 78.179 16.92 78.419 ;
     RECT  36.192 78.373 40.824 78.421 ;
     RECT  18.6 77.603 35.112 78.469 ;
     RECT  36.192 78.421 40.968 78.469 ;
     RECT  5.52 76.787 8.112 78.947 ;
     RECT  18.6 78.469 40.968 79.477 ;
     RECT  42.24 77.845 43.752 79.477 ;
     RECT  12.912 78.419 16.44 80.627 ;
     RECT  5.664 78.947 8.112 80.675 ;
     RECT  5.712 80.675 8.112 81.347 ;
     RECT  11.856 77.987 11.88 81.683 ;
     RECT  14.688 80.627 16.44 82.307 ;
     RECT  44.928 75.971 45.912 82.739 ;
     RECT  14.736 82.307 16.44 83.027 ;
     RECT  18.6 79.477 43.752 83.075 ;
     RECT  20.064 83.075 43.752 83.267 ;
     RECT  47.184 78.131 48.984 83.267 ;
     RECT  23.232 83.267 43.752 83.315 ;
     RECT  2.4 72.133 3.96 83.507 ;
     RECT  5.712 81.347 6.216 83.555 ;
     RECT  20.064 83.267 22.2 83.603 ;
     RECT  24 83.315 43.752 83.603 ;
     RECT  14.784 83.027 16.44 83.939 ;
     RECT  20.064 83.603 21.912 84.083 ;
     RECT  48.24 83.267 48.984 84.181 ;
     RECT  2.4 83.507 2.712 84.249 ;
     RECT  7.344 81.347 8.112 84.249 ;
     RECT  12.912 80.627 13.512 84.249 ;
     RECT  18.6 83.075 18.912 84.249 ;
     RECT  45.6 82.739 45.912 84.249 ;
     RECT  51 19.571 51.312 84.249 ;
     RECT  56.4 19.283 56.712 84.249 ;
     RECT  61.8 64.691 62.112 84.249 ;
     RECT  67.2 19.859 67.512 84.249 ;
     RECT  72.6 19.235 72.912 84.249 ;
     RECT  78 19.475 78.312 84.249 ;
     RECT  83.4 19.331 83.712 84.249 ;
     RECT  88.8 20.867 89.112 84.249 ;
     RECT  94.2 19.427 94.512 84.249 ;
     RECT  99.6 19.283 99.912 84.249 ;
     RECT  105 19.043 105.312 84.249 ;
     RECT  110.4 19.283 110.712 84.249 ;
     RECT  115.8 22.403 116.112 84.249 ;
     RECT  121.2 26.627 121.512 84.249 ;
     RECT  126.6 2.151 126.912 84.249 ;
     RECT  132 2.151 132.312 84.249 ;
     RECT  137.4 2.151 137.712 84.249 ;
     RECT  2.4 84.249 2.52 84.263 ;
     RECT  7.344 84.249 7.92 84.263 ;
     RECT  12.912 84.249 13.32 84.263 ;
     RECT  18.6 84.249 18.72 84.263 ;
     RECT  24 83.603 42.84 84.263 ;
     RECT  45.6 84.249 45.72 84.263 ;
     RECT  51 84.249 51.12 84.263 ;
     RECT  56.4 84.249 56.52 84.263 ;
     RECT  61.8 84.249 61.92 84.263 ;
     RECT  67.2 84.249 67.32 84.263 ;
     RECT  72.6 84.249 72.72 84.263 ;
     RECT  78 84.249 78.12 84.263 ;
     RECT  83.4 84.249 83.52 84.263 ;
     RECT  88.8 84.249 88.92 84.263 ;
     RECT  94.2 84.249 94.32 84.263 ;
     RECT  99.6 84.249 99.72 84.263 ;
     RECT  105 84.249 105.12 84.263 ;
     RECT  110.4 84.249 110.52 84.263 ;
     RECT  115.8 84.249 115.92 84.263 ;
     RECT  121.2 84.249 121.32 84.263 ;
     RECT  126.6 84.249 126.72 84.263 ;
     RECT  132 84.249 132.12 84.263 ;
     RECT  137.4 84.249 137.52 84.263 ;
     RECT  20.496 84.083 21.912 84.323 ;
     RECT  16.32 83.939 16.44 84.371 ;
     RECT  3.936 83.507 3.96 84.659 ;
     RECT  7.344 84.263 7.368 84.707 ;
     RECT  6.192 83.555 6.216 84.755 ;
     RECT  12.912 84.263 13.032 84.803 ;
     RECT  14.784 83.939 14.808 84.899 ;
     RECT  20.496 84.323 20.904 85.187 ;
     RECT  20.496 85.187 20.52 85.235 ;
     RECT  13.008 84.803 13.032 85.331 ;
     RECT  16.32 84.371 16.344 85.379 ;
     RECT  48.24 84.181 49.032 85.523 ;
     RECT  48.384 85.523 48.456 85.571 ;
     RECT  48.384 85.571 48.408 85.667 ;
     RECT  21.888 84.323 21.912 86.147 ;
     RECT  24.528 84.263 42.84 86.224 ;
     RECT  51.768 0.611 52.752 1.187 ;
     RECT  61.128 0.899 61.272 2.137 ;
     RECT  24.816 1.139 25.392 2.137 ;
     RECT  51.624 1.187 52.752 1.763 ;
     RECT  47.448 1.379 48.432 3.253 ;
     RECT  25.416 1.427 26.544 1.667 ;
     RECT  41.208 1.475 42.192 2.677 ;
     RECT  27.312 1.763 27.84 2.915 ;
     RECT  51.624 1.763 52.896 2.915 ;
     RECT  52.92 1.763 54.048 3.107 ;
     RECT  59.4 1.811 60.672 1.907 ;
     RECT  12.072 2.137 13.2 3.397 ;
     RECT  24.12 2.137 25.392 2.151 ;
     RECT  49.32 2.147 50.304 2.195 ;
     RECT  24.312 2.151 25.392 2.291 ;
     RECT  49.032 2.195 50.304 3.155 ;
     RECT  30.312 2.483 31.584 3.011 ;
     RECT  13.512 2.773 14.832 4.021 ;
     RECT  27.312 2.915 29.136 3.109 ;
     RECT  32.616 2.915 33.84 3.683 ;
     RECT  51.312 2.915 52.896 3.107 ;
     RECT  30.312 3.011 31.728 3.875 ;
     RECT  51.312 3.107 54.048 3.109 ;
     RECT  27.336 3.109 29.136 4.069 ;
     RECT  51.312 3.109 52.416 3.827 ;
     RECT  52.44 3.109 54.048 3.157 ;
     RECT  48.936 3.155 50.304 3.443 ;
     RECT  52.44 3.157 53.712 3.827 ;
     RECT  48.936 3.443 49.08 4.549 ;
     RECT  67.608 3.443 67.896 4.501 ;
     RECT  31.752 3.683 33.84 3.731 ;
     RECT  31.752 3.731 33.888 3.875 ;
     RECT  41.304 3.731 42.288 4.547 ;
     RECT  51.312 3.827 53.712 4.741 ;
     RECT  30.312 3.875 31.176 4.019 ;
     RECT  33.072 3.875 33.888 4.741 ;
     RECT  26.232 3.925 27.312 5.077 ;
     RECT  30.168 4.019 31.176 4.595 ;
     RECT  37.848 4.019 39.216 6.805 ;
     RECT  13.608 4.021 14.832 5.029 ;
     RECT  27.336 4.069 28.656 5.123 ;
     RECT  9.672 4.117 10.944 5.749 ;
     RECT  21.384 4.117 22.8 4.499 ;
     RECT  22.824 4.117 24 4.499 ;
     RECT  21.384 4.499 24 5.077 ;
     RECT  68.04 4.501 69.456 5.893 ;
     RECT  41.304 4.547 42.024 5.557 ;
     RECT  43.584 4.547 43.632 5.509 ;
     RECT  24.312 4.595 24.408 5.701 ;
     RECT  30.072 4.595 31.176 5.125 ;
     RECT  54.648 4.691 55.632 5.171 ;
     RECT  58.68 4.739 59.712 4.931 ;
     RECT  51.312 4.741 52.752 4.931 ;
     RECT  57.144 4.789 58.656 4.931 ;
     RECT  61.68 4.835 61.8 5.989 ;
     RECT  2.712 4.885 3.984 5.029 ;
     RECT  3 5.029 3.984 9.589 ;
     RECT  76.728 5.029 78 5.173 ;
     RECT  21.528 5.077 22.752 5.365 ;
     RECT  22.776 5.077 24 6.805 ;
     RECT  30.072 5.125 31.152 6.661 ;
     RECT  54.216 5.171 55.632 6.323 ;
     RECT  76.968 5.173 78 5.845 ;
     RECT  94.872 5.221 95.952 5.749 ;
     RECT  18.912 5.269 20.4 5.461 ;
     RECT  21.576 5.365 22.752 6.037 ;
     RECT  91.416 5.411 91.512 6.229 ;
     RECT  99.912 5.461 100.896 7.285 ;
     RECT  47.448 5.507 48.432 5.651 ;
     RECT  46.2 5.555 47.376 5.843 ;
     RECT  53.712 5.555 54.192 6.323 ;
     RECT  69.576 5.557 71.088 5.893 ;
     RECT  75.288 5.557 76.704 5.749 ;
     RECT  117.048 5.557 118.08 6.085 ;
     RECT  41.16 5.699 41.352 6.757 ;
     RECT  9.864 5.749 10.944 5.797 ;
     RECT  75.288 5.749 76.368 5.845 ;
     RECT  100.92 5.749 102.432 6.181 ;
     RECT  17.208 5.797 18.6 6.085 ;
     RECT  82.056 5.797 83.4 5.989 ;
     RECT  83.712 5.845 84.912 6.037 ;
     RECT  84.936 5.845 86.016 6.613 ;
     RECT  114.6 5.845 115.8 6.035 ;
     RECT  68.04 5.893 69.168 6.181 ;
     RECT  69.576 5.893 70.656 6.037 ;
     RECT  75.864 5.987 76.944 7.189 ;
     RECT  15 5.989 16.464 6.997 ;
     RECT  73.032 5.989 74.448 6.613 ;
     RECT  83.928 6.037 84.912 6.325 ;
     RECT  17.544 6.085 18.6 6.133 ;
     RECT  91.416 6.229 92.88 6.661 ;
     RECT  53.712 6.323 54.792 6.805 ;
     RECT  92.952 6.371 93.936 6.419 ;
     RECT  45.912 6.419 46.008 7.621 ;
     RECT  92.952 6.419 94.032 8.293 ;
     RECT  80.976 6.467 81.84 6.565 ;
     RECT  4.728 6.565 5.76 9.925 ;
     RECT  79.464 6.565 81.84 6.901 ;
     RECT  89.304 6.611 89.592 6.661 ;
     RECT  73.272 6.613 74.448 6.661 ;
     RECT  84.984 6.613 86.016 7.189 ;
     RECT  98.136 6.613 99.6 7.093 ;
     RECT  89.304 6.661 90.672 7.621 ;
     RECT  91.416 6.661 92.64 6.805 ;
     RECT  65.256 6.709 66.624 6.853 ;
     RECT  63.72 6.757 65.232 6.805 ;
     RECT  29.232 6.803 29.4 7.957 ;
     RECT  22.776 6.805 23.76 8.581 ;
     RECT  53.544 6.805 54.792 7.669 ;
     RECT  63.816 6.805 65.232 6.853 ;
     RECT  96.312 6.805 97.728 6.949 ;
     RECT  29.712 6.851 31.488 7.909 ;
     RECT  44.592 6.851 44.688 8.293 ;
     RECT  63.816 6.853 64.8 7.093 ;
     RECT  65.496 6.853 66.624 8.293 ;
     RECT  62.112 6.901 63.36 7.813 ;
     RECT  80.76 6.901 81.84 7.717 ;
     RECT  15.048 6.997 16.464 7.093 ;
     RECT  15.336 7.093 16.464 7.333 ;
     RECT  98.616 7.093 99.6 7.189 ;
     RECT  102.456 7.237 103.776 7.717 ;
     RECT  56.712 7.333 58.128 7.957 ;
     RECT  31.896 7.381 33.36 7.717 ;
     RECT  51.768 7.381 52.8 8.197 ;
     RECT  33.384 7.667 34.416 9.061 ;
     RECT  53.544 7.669 54.768 7.909 ;
     RECT  31.944 7.717 33.36 7.861 ;
     RECT  46.632 7.765 47.904 8.245 ;
     RECT  62.112 7.813 63.264 7.955 ;
     RECT  31.944 7.861 33.12 7.909 ;
     RECT  29.712 7.909 30.864 8.485 ;
     RECT  31.992 7.909 33.12 8.005 ;
     RECT  53.784 7.909 54.768 7.955 ;
     RECT  53.784 7.955 54.792 7.957 ;
     RECT  62.112 7.955 63.36 8.341 ;
     RECT  54.264 7.957 54.792 8.773 ;
     RECT  56.712 7.957 57.84 9.061 ;
     RECT  76.392 8.147 77.568 9.301 ;
     RECT  106.392 8.243 106.44 9.637 ;
     RECT  65.496 8.293 66.576 8.533 ;
     RECT  62.232 8.341 63.36 8.483 ;
     RECT  62.112 8.483 63.36 10.453 ;
     RECT  54.264 8.773 56.256 9.157 ;
     RECT  43.128 8.821 44.4 9.685 ;
     RECT  108.288 9.155 108.432 10.213 ;
     RECT  54.504 9.157 56.256 9.253 ;
     RECT  54.744 9.253 56.256 9.395 ;
     RECT  54.504 9.395 56.256 10.693 ;
     RECT  68.472 9.539 69.456 9.683 ;
     RECT  26.472 9.541 27.936 9.637 ;
     RECT  59.352 9.541 60.48 9.781 ;
     RECT  68.376 9.683 69.456 11.173 ;
     RECT  43.32 9.685 44.4 9.875 ;
     RECT  75.384 9.731 76.368 9.971 ;
     RECT  59.352 9.781 60.336 10.933 ;
     RECT  42.6 9.875 44.4 9.973 ;
     RECT  75.384 9.971 76.464 11.461 ;
     RECT  42.6 9.973 43.872 10.211 ;
     RECT  42.552 10.211 43.872 11.749 ;
     RECT  107.208 10.213 108.432 10.693 ;
     RECT  26.664 10.259 27.888 10.787 ;
     RECT  47.88 10.357 48.96 11.749 ;
     RECT  84.552 10.403 85.584 11.797 ;
     RECT  108.84 10.453 110.304 10.693 ;
     RECT  54.504 10.693 55.68 11.797 ;
     RECT  107.4 10.693 108.432 13.811 ;
     RECT  108.936 10.693 110.304 11.509 ;
     RECT  26.664 10.787 27.936 12.373 ;
     RECT  68.424 11.173 69.456 11.269 ;
     RECT  108.936 11.509 110.256 11.557 ;
     RECT  108.936 11.557 110.16 11.651 ;
     RECT  108.744 11.651 110.16 11.749 ;
     RECT  42.648 11.749 43.872 12.085 ;
     RECT  108.744 11.749 110.064 12.611 ;
     RECT  54.648 11.797 55.68 17.171 ;
     RECT  75.816 12.035 76.896 13.045 ;
     RECT  42.744 12.085 43.872 12.277 ;
     RECT  56.904 12.275 58.032 14.389 ;
     RECT  26.76 12.373 27.936 12.421 ;
     RECT  108.6 12.611 110.064 14.197 ;
     RECT  102.12 12.803 103.104 13.907 ;
     RECT  47.736 13.763 48.816 14.773 ;
     RECT  107.304 13.811 108.432 13.907 ;
     RECT  102.072 13.907 103.104 16.885 ;
     RECT  107.256 13.907 108.432 15.301 ;
     RECT  74.616 13.955 75.648 14.917 ;
     RECT  108.6 14.197 109.968 14.773 ;
     RECT  56.904 14.389 57.888 14.773 ;
     RECT  99.912 14.675 101.04 15.635 ;
     RECT  47.736 14.773 48.72 15.061 ;
     RECT  107.256 15.301 108.288 15.973 ;
     RECT  74.76 15.347 76.032 16.645 ;
     RECT  99.912 15.635 101.184 16.789 ;
     RECT  74.76 16.645 75.84 17.989 ;
     RECT  100.2 16.789 101.184 16.981 ;
     RECT  54.072 17.171 55.68 17.653 ;
     RECT  76.392 17.363 77.376 17.507 ;
     RECT  96.168 17.411 97.68 18.901 ;
     RECT  35.784 17.507 36.912 19.093 ;
     RECT  76.392 17.507 77.616 17.699 ;
     RECT  98.472 17.651 99.504 17.699 ;
     RECT  54.072 17.653 55.104 17.699 ;
     RECT  53.736 17.699 55.104 17.891 ;
     RECT  97.992 17.699 99.504 17.891 ;
     RECT  44.616 17.747 45.6 18.275 ;
     RECT  53.736 17.891 55.2 17.939 ;
     RECT  94.632 17.939 95.904 17.987 ;
     RECT  94.632 17.987 96 18.563 ;
     RECT  74.76 17.989 75.792 19.379 ;
     RECT  44.472 18.275 45.6 19.235 ;
     RECT  46.296 18.323 47.328 19.621 ;
     RECT  67.608 18.323 68.88 18.803 ;
     RECT  72.912 18.323 74.304 18.467 ;
     RECT  91.272 18.323 92.496 18.611 ;
     RECT  85.992 18.419 87.12 19.427 ;
     RECT  49.272 18.515 50.4 18.851 ;
     RECT  94.632 18.563 96.144 19.427 ;
     RECT  91.272 18.611 92.688 18.995 ;
     RECT  81.192 18.707 82.368 18.851 ;
     RECT  89.256 18.707 90.528 19.235 ;
     RECT  59.16 18.755 60.432 19.379 ;
     RECT  67.512 18.803 68.88 19.091 ;
     RECT  84.552 18.803 85.776 18.851 ;
     RECT  49.272 18.851 50.88 19.427 ;
     RECT  84.408 18.851 85.776 18.947 ;
     RECT  103.944 18.851 105 18.995 ;
     RECT  100.296 18.899 101.424 18.947 ;
     RECT  102.216 18.899 103.488 18.947 ;
     RECT  96.168 18.901 97.632 19.043 ;
     RECT  51.432 18.947 52.752 19.331 ;
     RECT  55.224 18.947 56.208 19.283 ;
     RECT  56.712 18.947 57.888 20.579 ;
     RECT  84.408 18.947 85.968 19.331 ;
     RECT  93.192 18.947 94.2 19.091 ;
     RECT  99.912 18.947 101.424 19.235 ;
     RECT  102.216 18.947 103.728 19.523 ;
     RECT  39.048 18.995 40.2 21.109 ;
     RECT  79.416 18.995 80.544 19.235 ;
     RECT  103.752 18.995 105 19.523 ;
     RECT  108.456 18.995 109.968 19.283 ;
     RECT  96.168 19.043 96.936 19.237 ;
     RECT  105.312 19.043 106.512 19.283 ;
     RECT  93.096 19.091 94.2 19.187 ;
     RECT  107.256 19.091 108.288 19.235 ;
     RECT  28.248 19.187 29.4 21.061 ;
     RECT  63.816 19.187 64.8 19.811 ;
     RECT  69.096 19.187 70.32 19.379 ;
     RECT  44.376 19.235 45.6 21.685 ;
     RECT  71.304 19.235 72.6 19.475 ;
     RECT  107.256 19.235 108.432 19.283 ;
     RECT  24.456 19.283 25.536 20.389 ;
     RECT  55.224 19.283 56.4 21.107 ;
     RECT  57.912 19.283 59.088 20.579 ;
     RECT  85.584 19.331 85.968 19.427 ;
     RECT  49.272 19.427 51 19.909 ;
     RECT  85.584 19.427 87.12 19.475 ;
     RECT  85.584 19.475 85.608 20.149 ;
     RECT  49.56 19.909 51 21.877 ;
     RECT  55.08 21.107 56.4 21.683 ;
     RECT  49.608 21.877 51 64.739 ;
     RECT  116.112 22.403 117.144 63.528 ;
     RECT  117.24 30.851 118.704 31.523 ;
     RECT  45.912 63.827 46.992 72.325 ;
     RECT  38.232 63.971 39.648 65.219 ;
     RECT  33.384 64.115 34.416 64.643 ;
     RECT  22.056 64.643 23.088 66.325 ;
     RECT  32.808 64.643 34.416 65.027 ;
     RECT  31.32 64.691 32.736 66.565 ;
     RECT  49.56 64.739 51 68.435 ;
     RECT  32.76 65.027 34.416 65.797 ;
     RECT  37.08 65.171 38.208 65.219 ;
     RECT  37.08 65.219 39.648 65.267 ;
     RECT  36.888 65.267 39.648 66.325 ;
     RECT  40.512 65.507 41.616 65.747 ;
     RECT  44.328 65.699 45.312 67.429 ;
     RECT  40.512 65.747 42.192 67.045 ;
     RECT  32.76 65.797 33.888 68.005 ;
     RECT  22.056 66.325 23.04 66.469 ;
     RECT  36.888 66.325 38.208 67.237 ;
     RECT  38.232 66.325 39.648 66.373 ;
     RECT  38.424 66.373 39.648 67.187 ;
     RECT  31.32 66.565 32.496 66.613 ;
     RECT  31.416 66.613 32.496 67.285 ;
     RECT  40.512 67.045 42.048 67.237 ;
     RECT  38.376 67.187 39.648 71.267 ;
     RECT  37.08 67.237 38.208 68.197 ;
     RECT  40.512 67.237 41.568 68.965 ;
     RECT  48.84 68.963 48.888 70.405 ;
     RECT  40.512 68.965 41.52 69.829 ;
     RECT  3.96 69.875 4.992 70.835 ;
     RECT  32.472 70.307 33.648 71.749 ;
     RECT  44.424 70.787 45.504 72.467 ;
     RECT  3.864 70.835 4.992 72.133 ;
     RECT  3.96 72.133 4.992 75.299 ;
     RECT  44.088 72.467 45.504 74.629 ;
     RECT  38.808 73.093 40.2 73.525 ;
     RECT  38.952 73.525 40.2 73.813 ;
     RECT  38.952 73.813 40.08 74.051 ;
     RECT  38.952 74.051 40.2 74.147 ;
     RECT  38.808 74.147 40.2 74.387 ;
     RECT  8.616 74.195 9.648 75.491 ;
     RECT  36.456 74.339 37.584 74.675 ;
     RECT  38.376 74.387 40.2 75.157 ;
     RECT  32.184 74.483 33.168 75.299 ;
     RECT  42.024 74.963 43.056 75.107 ;
     RECT  40.824 75.107 42 75.155 ;
     RECT  40.824 75.155 41.112 76.261 ;
     RECT  38.376 75.157 39.792 76.403 ;
     RECT  32.184 75.299 33.888 75.829 ;
     RECT  43.584 75.299 43.728 76.741 ;
     RECT  43.752 75.299 44.928 82.739 ;
     RECT  32.712 75.829 33.888 77.173 ;
     RECT  45.912 75.971 46.944 78.131 ;
     RECT  38.376 76.403 40.2 77.365 ;
     RECT  41.112 76.741 42.24 77.027 ;
     RECT  42.264 76.741 43.728 77.845 ;
     RECT  40.824 77.027 42.24 78.421 ;
     RECT  35.112 77.317 36.192 78.469 ;
     RECT  36.216 77.317 37.488 78.373 ;
     RECT  38.664 77.365 40.2 77.797 ;
     RECT  17.256 77.603 18.6 78.179 ;
     RECT  11.88 77.987 12.912 81.683 ;
     RECT  45.912 78.131 47.184 83.267 ;
     RECT  40.968 78.421 42.24 79.477 ;
     RECT  13.512 80.627 14.688 82.307 ;
     RECT  6.216 81.347 7.344 84.707 ;
     RECT  13.512 82.307 14.736 83.027 ;
     RECT  13.512 83.027 14.784 84.249 ;
     RECT  18.912 83.075 20.064 84.083 ;
     RECT  22.2 83.267 23.232 83.315 ;
     RECT  2.712 83.507 3.936 84.249 ;
     RECT  14.808 83.939 16.32 84.899 ;
     RECT  2.52 84.249 3.936 84.263 ;
     RECT  13.32 84.249 14.784 84.263 ;
     RECT  20.904 84.323 21.888 85.187 ;
     RECT  20.52 85.187 21.888 85.235 ;
  END
END ot_s81_pq_qb_bank0_native
END LIBRARY
